VERSION 5.8 ;
BUSBITCHARS "[]" ;
DIVIDERCHAR "/" ;
UNITS
    DATABASE MICRONS 1000 ;
END UNITS

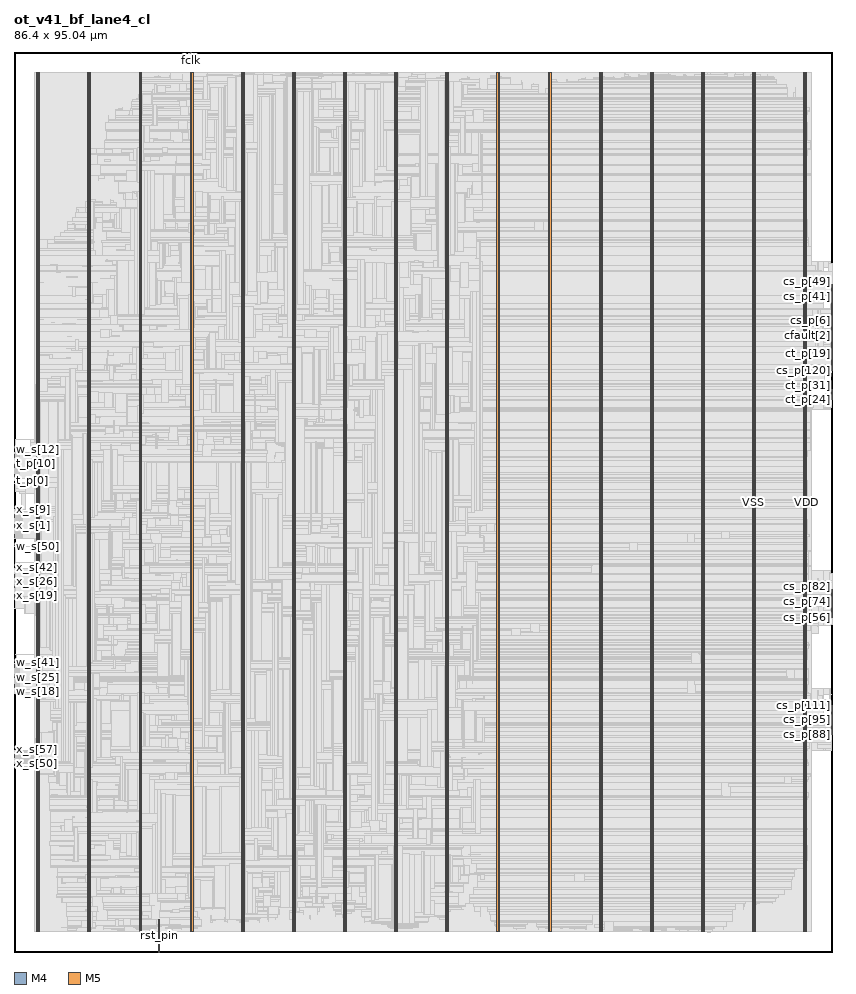
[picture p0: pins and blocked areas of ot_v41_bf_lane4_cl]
MACRO ot_v41_bf_lane4_cl
  FOREIGN ot_v41_bf_lane4_cl 0 0 ;
  CLASS BLOCK ;
  SIZE 86.4 BY 95.04 ;
  PIN cf[0]
    DIRECTION OUTPUT ;
    USE SIGNAL ;
    PORT
      LAYER M4 ;
        RECT  86.316 64.464 86.4 64.488 ;
    END
  END cf[0]
  PIN cf[1]
    DIRECTION OUTPUT ;
    USE SIGNAL ;
    PORT
      LAYER M4 ;
        RECT  86.316 64.56 86.4 64.584 ;
    END
  END cf[1]
  PIN cf[2]
    DIRECTION OUTPUT ;
    USE SIGNAL ;
    PORT
      LAYER M4 ;
        RECT  86.316 64.656 86.4 64.68 ;
    END
  END cf[2]
  PIN cf[3]
    DIRECTION OUTPUT ;
    USE SIGNAL ;
    PORT
      LAYER M4 ;
        RECT  86.316 64.752 86.4 64.776 ;
    END
  END cf[3]
  PIN cfault[0]
    DIRECTION OUTPUT ;
    USE SIGNAL ;
    PORT
      LAYER M4 ;
        RECT  86.316 64.848 86.4 64.872 ;
    END
  END cfault[0]
  PIN cfault[1]
    DIRECTION OUTPUT ;
    USE SIGNAL ;
    PORT
      LAYER M4 ;
        RECT  86.316 64.944 86.4 64.968 ;
    END
  END cfault[1]
  PIN cfault[2]
    DIRECTION OUTPUT ;
    USE SIGNAL ;
    PORT
      LAYER M4 ;
        RECT  86.316 65.04 86.4 65.064 ;
    END
  END cfault[2]
  PIN cfault[3]
    DIRECTION OUTPUT ;
    USE SIGNAL ;
    PORT
      LAYER M4 ;
        RECT  86.316 65.136 86.4 65.16 ;
    END
  END cfault[3]
  PIN cs_p[0]
    DIRECTION OUTPUT ;
    USE SIGNAL ;
    PORT
      LAYER M4 ;
        RECT  86.316 65.232 86.4 65.256 ;
    END
  END cs_p[0]
  PIN cs_p[100]
    DIRECTION OUTPUT ;
    USE SIGNAL ;
    PORT
      LAYER M4 ;
        RECT  86.316 24.144 86.4 24.168 ;
    END
  END cs_p[100]
  PIN cs_p[101]
    DIRECTION OUTPUT ;
    USE SIGNAL ;
    PORT
      LAYER M4 ;
        RECT  86.316 24.24 86.4 24.264 ;
    END
  END cs_p[101]
  PIN cs_p[102]
    DIRECTION OUTPUT ;
    USE SIGNAL ;
    PORT
      LAYER M4 ;
        RECT  86.316 24.336 86.4 24.36 ;
    END
  END cs_p[102]
  PIN cs_p[103]
    DIRECTION OUTPUT ;
    USE SIGNAL ;
    PORT
      LAYER M4 ;
        RECT  86.316 24.432 86.4 24.456 ;
    END
  END cs_p[103]
  PIN cs_p[104]
    DIRECTION OUTPUT ;
    USE SIGNAL ;
    PORT
      LAYER M4 ;
        RECT  86.316 24.528 86.4 24.552 ;
    END
  END cs_p[104]
  PIN cs_p[105]
    DIRECTION OUTPUT ;
    USE SIGNAL ;
    PORT
      LAYER M4 ;
        RECT  86.316 24.624 86.4 24.648 ;
    END
  END cs_p[105]
  PIN cs_p[106]
    DIRECTION OUTPUT ;
    USE SIGNAL ;
    PORT
      LAYER M4 ;
        RECT  86.316 24.72 86.4 24.744 ;
    END
  END cs_p[106]
  PIN cs_p[107]
    DIRECTION OUTPUT ;
    USE SIGNAL ;
    PORT
      LAYER M4 ;
        RECT  86.316 24.816 86.4 24.84 ;
    END
  END cs_p[107]
  PIN cs_p[108]
    DIRECTION OUTPUT ;
    USE SIGNAL ;
    PORT
      LAYER M4 ;
        RECT  86.316 24.912 86.4 24.936 ;
    END
  END cs_p[108]
  PIN cs_p[109]
    DIRECTION OUTPUT ;
    USE SIGNAL ;
    PORT
      LAYER M4 ;
        RECT  86.316 25.008 86.4 25.032 ;
    END
  END cs_p[109]
  PIN cs_p[10]
    DIRECTION OUTPUT ;
    USE SIGNAL ;
    PORT
      LAYER M4 ;
        RECT  86.316 66.192 86.4 66.216 ;
    END
  END cs_p[10]
  PIN cs_p[110]
    DIRECTION OUTPUT ;
    USE SIGNAL ;
    PORT
      LAYER M4 ;
        RECT  86.316 25.104 86.4 25.128 ;
    END
  END cs_p[110]
  PIN cs_p[111]
    DIRECTION OUTPUT ;
    USE SIGNAL ;
    PORT
      LAYER M4 ;
        RECT  86.316 25.2 86.4 25.224 ;
    END
  END cs_p[111]
  PIN cs_p[112]
    DIRECTION OUTPUT ;
    USE SIGNAL ;
    PORT
      LAYER M4 ;
        RECT  86.316 25.296 86.4 25.32 ;
    END
  END cs_p[112]
  PIN cs_p[113]
    DIRECTION OUTPUT ;
    USE SIGNAL ;
    PORT
      LAYER M4 ;
        RECT  86.316 25.392 86.4 25.416 ;
    END
  END cs_p[113]
  PIN cs_p[114]
    DIRECTION OUTPUT ;
    USE SIGNAL ;
    PORT
      LAYER M4 ;
        RECT  86.316 25.488 86.4 25.512 ;
    END
  END cs_p[114]
  PIN cs_p[115]
    DIRECTION OUTPUT ;
    USE SIGNAL ;
    PORT
      LAYER M4 ;
        RECT  86.316 25.584 86.4 25.608 ;
    END
  END cs_p[115]
  PIN cs_p[116]
    DIRECTION OUTPUT ;
    USE SIGNAL ;
    PORT
      LAYER M4 ;
        RECT  86.316 25.68 86.4 25.704 ;
    END
  END cs_p[116]
  PIN cs_p[117]
    DIRECTION OUTPUT ;
    USE SIGNAL ;
    PORT
      LAYER M4 ;
        RECT  86.316 25.776 86.4 25.8 ;
    END
  END cs_p[117]
  PIN cs_p[118]
    DIRECTION OUTPUT ;
    USE SIGNAL ;
    PORT
      LAYER M4 ;
        RECT  86.316 25.872 86.4 25.896 ;
    END
  END cs_p[118]
  PIN cs_p[119]
    DIRECTION OUTPUT ;
    USE SIGNAL ;
    PORT
      LAYER M4 ;
        RECT  86.316 25.968 86.4 25.992 ;
    END
  END cs_p[119]
  PIN cs_p[11]
    DIRECTION OUTPUT ;
    USE SIGNAL ;
    PORT
      LAYER M4 ;
        RECT  86.316 66.288 86.4 66.312 ;
    END
  END cs_p[11]
  PIN cs_p[120]
    DIRECTION OUTPUT ;
    USE SIGNAL ;
    PORT
      LAYER M4 ;
        RECT  86.316 61.392 86.4 61.416 ;
    END
  END cs_p[120]
  PIN cs_p[121]
    DIRECTION OUTPUT ;
    USE SIGNAL ;
    PORT
      LAYER M4 ;
        RECT  86.316 61.488 86.4 61.512 ;
    END
  END cs_p[121]
  PIN cs_p[122]
    DIRECTION OUTPUT ;
    USE SIGNAL ;
    PORT
      LAYER M4 ;
        RECT  86.316 61.584 86.4 61.608 ;
    END
  END cs_p[122]
  PIN cs_p[123]
    DIRECTION OUTPUT ;
    USE SIGNAL ;
    PORT
      LAYER M4 ;
        RECT  86.316 61.68 86.4 61.704 ;
    END
  END cs_p[123]
  PIN cs_p[124]
    DIRECTION OUTPUT ;
    USE SIGNAL ;
    PORT
      LAYER M4 ;
        RECT  86.316 61.776 86.4 61.8 ;
    END
  END cs_p[124]
  PIN cs_p[125]
    DIRECTION OUTPUT ;
    USE SIGNAL ;
    PORT
      LAYER M4 ;
        RECT  86.316 61.872 86.4 61.896 ;
    END
  END cs_p[125]
  PIN cs_p[126]
    DIRECTION OUTPUT ;
    USE SIGNAL ;
    PORT
      LAYER M4 ;
        RECT  86.316 61.968 86.4 61.992 ;
    END
  END cs_p[126]
  PIN cs_p[127]
    DIRECTION OUTPUT ;
    USE SIGNAL ;
    PORT
      LAYER M4 ;
        RECT  86.316 62.064 86.4 62.088 ;
    END
  END cs_p[127]
  PIN cs_p[12]
    DIRECTION OUTPUT ;
    USE SIGNAL ;
    PORT
      LAYER M4 ;
        RECT  86.316 66.384 86.4 66.408 ;
    END
  END cs_p[12]
  PIN cs_p[13]
    DIRECTION OUTPUT ;
    USE SIGNAL ;
    PORT
      LAYER M4 ;
        RECT  86.316 66.48 86.4 66.504 ;
    END
  END cs_p[13]
  PIN cs_p[14]
    DIRECTION OUTPUT ;
    USE SIGNAL ;
    PORT
      LAYER M4 ;
        RECT  86.316 66.576 86.4 66.6 ;
    END
  END cs_p[14]
  PIN cs_p[15]
    DIRECTION OUTPUT ;
    USE SIGNAL ;
    PORT
      LAYER M4 ;
        RECT  86.316 66.672 86.4 66.696 ;
    END
  END cs_p[15]
  PIN cs_p[16]
    DIRECTION OUTPUT ;
    USE SIGNAL ;
    PORT
      LAYER M4 ;
        RECT  86.316 66.768 86.4 66.792 ;
    END
  END cs_p[16]
  PIN cs_p[17]
    DIRECTION OUTPUT ;
    USE SIGNAL ;
    PORT
      LAYER M4 ;
        RECT  86.316 66.864 86.4 66.888 ;
    END
  END cs_p[17]
  PIN cs_p[18]
    DIRECTION OUTPUT ;
    USE SIGNAL ;
    PORT
      LAYER M4 ;
        RECT  86.316 66.96 86.4 66.984 ;
    END
  END cs_p[18]
  PIN cs_p[19]
    DIRECTION OUTPUT ;
    USE SIGNAL ;
    PORT
      LAYER M4 ;
        RECT  86.316 67.056 86.4 67.08 ;
    END
  END cs_p[19]
  PIN cs_p[1]
    DIRECTION OUTPUT ;
    USE SIGNAL ;
    PORT
      LAYER M4 ;
        RECT  86.316 65.328 86.4 65.352 ;
    END
  END cs_p[1]
  PIN cs_p[20]
    DIRECTION OUTPUT ;
    USE SIGNAL ;
    PORT
      LAYER M4 ;
        RECT  86.316 67.152 86.4 67.176 ;
    END
  END cs_p[20]
  PIN cs_p[21]
    DIRECTION OUTPUT ;
    USE SIGNAL ;
    PORT
      LAYER M4 ;
        RECT  86.316 67.248 86.4 67.272 ;
    END
  END cs_p[21]
  PIN cs_p[22]
    DIRECTION OUTPUT ;
    USE SIGNAL ;
    PORT
      LAYER M4 ;
        RECT  86.316 67.344 86.4 67.368 ;
    END
  END cs_p[22]
  PIN cs_p[23]
    DIRECTION OUTPUT ;
    USE SIGNAL ;
    PORT
      LAYER M4 ;
        RECT  86.316 67.44 86.4 67.464 ;
    END
  END cs_p[23]
  PIN cs_p[24]
    DIRECTION OUTPUT ;
    USE SIGNAL ;
    PORT
      LAYER M4 ;
        RECT  86.316 67.536 86.4 67.56 ;
    END
  END cs_p[24]
  PIN cs_p[25]
    DIRECTION OUTPUT ;
    USE SIGNAL ;
    PORT
      LAYER M4 ;
        RECT  86.316 67.632 86.4 67.656 ;
    END
  END cs_p[25]
  PIN cs_p[26]
    DIRECTION OUTPUT ;
    USE SIGNAL ;
    PORT
      LAYER M4 ;
        RECT  86.316 67.728 86.4 67.752 ;
    END
  END cs_p[26]
  PIN cs_p[27]
    DIRECTION OUTPUT ;
    USE SIGNAL ;
    PORT
      LAYER M4 ;
        RECT  86.316 67.824 86.4 67.848 ;
    END
  END cs_p[27]
  PIN cs_p[28]
    DIRECTION OUTPUT ;
    USE SIGNAL ;
    PORT
      LAYER M4 ;
        RECT  86.316 67.92 86.4 67.944 ;
    END
  END cs_p[28]
  PIN cs_p[29]
    DIRECTION OUTPUT ;
    USE SIGNAL ;
    PORT
      LAYER M4 ;
        RECT  86.316 68.016 86.4 68.04 ;
    END
  END cs_p[29]
  PIN cs_p[2]
    DIRECTION OUTPUT ;
    USE SIGNAL ;
    PORT
      LAYER M4 ;
        RECT  86.316 65.424 86.4 65.448 ;
    END
  END cs_p[2]
  PIN cs_p[30]
    DIRECTION OUTPUT ;
    USE SIGNAL ;
    PORT
      LAYER M4 ;
        RECT  86.316 68.112 86.4 68.136 ;
    END
  END cs_p[30]
  PIN cs_p[31]
    DIRECTION OUTPUT ;
    USE SIGNAL ;
    PORT
      LAYER M4 ;
        RECT  86.316 68.208 86.4 68.232 ;
    END
  END cs_p[31]
  PIN cs_p[32]
    DIRECTION OUTPUT ;
    USE SIGNAL ;
    PORT
      LAYER M4 ;
        RECT  86.316 68.304 86.4 68.328 ;
    END
  END cs_p[32]
  PIN cs_p[33]
    DIRECTION OUTPUT ;
    USE SIGNAL ;
    PORT
      LAYER M4 ;
        RECT  86.316 68.4 86.4 68.424 ;
    END
  END cs_p[33]
  PIN cs_p[34]
    DIRECTION OUTPUT ;
    USE SIGNAL ;
    PORT
      LAYER M4 ;
        RECT  86.316 68.496 86.4 68.52 ;
    END
  END cs_p[34]
  PIN cs_p[35]
    DIRECTION OUTPUT ;
    USE SIGNAL ;
    PORT
      LAYER M4 ;
        RECT  86.316 68.592 86.4 68.616 ;
    END
  END cs_p[35]
  PIN cs_p[36]
    DIRECTION OUTPUT ;
    USE SIGNAL ;
    PORT
      LAYER M4 ;
        RECT  86.316 68.688 86.4 68.712 ;
    END
  END cs_p[36]
  PIN cs_p[37]
    DIRECTION OUTPUT ;
    USE SIGNAL ;
    PORT
      LAYER M4 ;
        RECT  86.316 68.784 86.4 68.808 ;
    END
  END cs_p[37]
  PIN cs_p[38]
    DIRECTION OUTPUT ;
    USE SIGNAL ;
    PORT
      LAYER M4 ;
        RECT  86.316 68.88 86.4 68.904 ;
    END
  END cs_p[38]
  PIN cs_p[39]
    DIRECTION OUTPUT ;
    USE SIGNAL ;
    PORT
      LAYER M4 ;
        RECT  86.316 68.976 86.4 69 ;
    END
  END cs_p[39]
  PIN cs_p[3]
    DIRECTION OUTPUT ;
    USE SIGNAL ;
    PORT
      LAYER M4 ;
        RECT  86.316 65.52 86.4 65.544 ;
    END
  END cs_p[3]
  PIN cs_p[40]
    DIRECTION OUTPUT ;
    USE SIGNAL ;
    PORT
      LAYER M4 ;
        RECT  86.316 69.072 86.4 69.096 ;
    END
  END cs_p[40]
  PIN cs_p[41]
    DIRECTION OUTPUT ;
    USE SIGNAL ;
    PORT
      LAYER M4 ;
        RECT  86.316 69.168 86.4 69.192 ;
    END
  END cs_p[41]
  PIN cs_p[42]
    DIRECTION OUTPUT ;
    USE SIGNAL ;
    PORT
      LAYER M4 ;
        RECT  86.316 69.264 86.4 69.288 ;
    END
  END cs_p[42]
  PIN cs_p[43]
    DIRECTION OUTPUT ;
    USE SIGNAL ;
    PORT
      LAYER M4 ;
        RECT  86.316 69.36 86.4 69.384 ;
    END
  END cs_p[43]
  PIN cs_p[44]
    DIRECTION OUTPUT ;
    USE SIGNAL ;
    PORT
      LAYER M4 ;
        RECT  86.316 69.456 86.4 69.48 ;
    END
  END cs_p[44]
  PIN cs_p[45]
    DIRECTION OUTPUT ;
    USE SIGNAL ;
    PORT
      LAYER M4 ;
        RECT  86.316 69.552 86.4 69.576 ;
    END
  END cs_p[45]
  PIN cs_p[46]
    DIRECTION OUTPUT ;
    USE SIGNAL ;
    PORT
      LAYER M4 ;
        RECT  86.316 69.648 86.4 69.672 ;
    END
  END cs_p[46]
  PIN cs_p[47]
    DIRECTION OUTPUT ;
    USE SIGNAL ;
    PORT
      LAYER M4 ;
        RECT  86.316 69.744 86.4 69.768 ;
    END
  END cs_p[47]
  PIN cs_p[48]
    DIRECTION OUTPUT ;
    USE SIGNAL ;
    PORT
      LAYER M4 ;
        RECT  86.316 69.84 86.4 69.864 ;
    END
  END cs_p[48]
  PIN cs_p[49]
    DIRECTION OUTPUT ;
    USE SIGNAL ;
    PORT
      LAYER M4 ;
        RECT  86.316 69.936 86.4 69.96 ;
    END
  END cs_p[49]
  PIN cs_p[4]
    DIRECTION OUTPUT ;
    USE SIGNAL ;
    PORT
      LAYER M4 ;
        RECT  86.316 65.616 86.4 65.64 ;
    END
  END cs_p[4]
  PIN cs_p[50]
    DIRECTION OUTPUT ;
    USE SIGNAL ;
    PORT
      LAYER M4 ;
        RECT  86.316 70.032 86.4 70.056 ;
    END
  END cs_p[50]
  PIN cs_p[51]
    DIRECTION OUTPUT ;
    USE SIGNAL ;
    PORT
      LAYER M4 ;
        RECT  86.316 70.128 86.4 70.152 ;
    END
  END cs_p[51]
  PIN cs_p[52]
    DIRECTION OUTPUT ;
    USE SIGNAL ;
    PORT
      LAYER M4 ;
        RECT  86.316 70.224 86.4 70.248 ;
    END
  END cs_p[52]
  PIN cs_p[53]
    DIRECTION OUTPUT ;
    USE SIGNAL ;
    PORT
      LAYER M4 ;
        RECT  86.316 70.32 86.4 70.344 ;
    END
  END cs_p[53]
  PIN cs_p[54]
    DIRECTION OUTPUT ;
    USE SIGNAL ;
    PORT
      LAYER M4 ;
        RECT  86.316 70.416 86.4 70.44 ;
    END
  END cs_p[54]
  PIN cs_p[55]
    DIRECTION OUTPUT ;
    USE SIGNAL ;
    PORT
      LAYER M4 ;
        RECT  86.316 70.512 86.4 70.536 ;
    END
  END cs_p[55]
  PIN cs_p[56]
    DIRECTION OUTPUT ;
    USE SIGNAL ;
    PORT
      LAYER M4 ;
        RECT  86.316 35.28 86.4 35.304 ;
    END
  END cs_p[56]
  PIN cs_p[57]
    DIRECTION OUTPUT ;
    USE SIGNAL ;
    PORT
      LAYER M4 ;
        RECT  86.316 35.376 86.4 35.4 ;
    END
  END cs_p[57]
  PIN cs_p[58]
    DIRECTION OUTPUT ;
    USE SIGNAL ;
    PORT
      LAYER M4 ;
        RECT  86.316 35.472 86.4 35.496 ;
    END
  END cs_p[58]
  PIN cs_p[59]
    DIRECTION OUTPUT ;
    USE SIGNAL ;
    PORT
      LAYER M4 ;
        RECT  86.316 35.568 86.4 35.592 ;
    END
  END cs_p[59]
  PIN cs_p[5]
    DIRECTION OUTPUT ;
    USE SIGNAL ;
    PORT
      LAYER M4 ;
        RECT  86.316 65.712 86.4 65.736 ;
    END
  END cs_p[5]
  PIN cs_p[60]
    DIRECTION OUTPUT ;
    USE SIGNAL ;
    PORT
      LAYER M4 ;
        RECT  86.316 35.664 86.4 35.688 ;
    END
  END cs_p[60]
  PIN cs_p[61]
    DIRECTION OUTPUT ;
    USE SIGNAL ;
    PORT
      LAYER M4 ;
        RECT  86.316 35.76 86.4 35.784 ;
    END
  END cs_p[61]
  PIN cs_p[62]
    DIRECTION OUTPUT ;
    USE SIGNAL ;
    PORT
      LAYER M4 ;
        RECT  86.316 35.856 86.4 35.88 ;
    END
  END cs_p[62]
  PIN cs_p[63]
    DIRECTION OUTPUT ;
    USE SIGNAL ;
    PORT
      LAYER M4 ;
        RECT  86.316 35.952 86.4 35.976 ;
    END
  END cs_p[63]
  PIN cs_p[64]
    DIRECTION OUTPUT ;
    USE SIGNAL ;
    PORT
      LAYER M4 ;
        RECT  86.316 36.048 86.4 36.072 ;
    END
  END cs_p[64]
  PIN cs_p[65]
    DIRECTION OUTPUT ;
    USE SIGNAL ;
    PORT
      LAYER M4 ;
        RECT  86.316 36.144 86.4 36.168 ;
    END
  END cs_p[65]
  PIN cs_p[66]
    DIRECTION OUTPUT ;
    USE SIGNAL ;
    PORT
      LAYER M4 ;
        RECT  86.316 36.24 86.4 36.264 ;
    END
  END cs_p[66]
  PIN cs_p[67]
    DIRECTION OUTPUT ;
    USE SIGNAL ;
    PORT
      LAYER M4 ;
        RECT  86.316 36.336 86.4 36.36 ;
    END
  END cs_p[67]
  PIN cs_p[68]
    DIRECTION OUTPUT ;
    USE SIGNAL ;
    PORT
      LAYER M4 ;
        RECT  86.316 36.432 86.4 36.456 ;
    END
  END cs_p[68]
  PIN cs_p[69]
    DIRECTION OUTPUT ;
    USE SIGNAL ;
    PORT
      LAYER M4 ;
        RECT  86.316 36.528 86.4 36.552 ;
    END
  END cs_p[69]
  PIN cs_p[6]
    DIRECTION OUTPUT ;
    USE SIGNAL ;
    PORT
      LAYER M4 ;
        RECT  86.316 65.808 86.4 65.832 ;
    END
  END cs_p[6]
  PIN cs_p[70]
    DIRECTION OUTPUT ;
    USE SIGNAL ;
    PORT
      LAYER M4 ;
        RECT  86.316 36.624 86.4 36.648 ;
    END
  END cs_p[70]
  PIN cs_p[71]
    DIRECTION OUTPUT ;
    USE SIGNAL ;
    PORT
      LAYER M4 ;
        RECT  86.316 36.72 86.4 36.744 ;
    END
  END cs_p[71]
  PIN cs_p[72]
    DIRECTION OUTPUT ;
    USE SIGNAL ;
    PORT
      LAYER M4 ;
        RECT  86.316 36.816 86.4 36.84 ;
    END
  END cs_p[72]
  PIN cs_p[73]
    DIRECTION OUTPUT ;
    USE SIGNAL ;
    PORT
      LAYER M4 ;
        RECT  86.316 36.912 86.4 36.936 ;
    END
  END cs_p[73]
  PIN cs_p[74]
    DIRECTION OUTPUT ;
    USE SIGNAL ;
    PORT
      LAYER M4 ;
        RECT  86.316 37.008 86.4 37.032 ;
    END
  END cs_p[74]
  PIN cs_p[75]
    DIRECTION OUTPUT ;
    USE SIGNAL ;
    PORT
      LAYER M4 ;
        RECT  86.316 37.104 86.4 37.128 ;
    END
  END cs_p[75]
  PIN cs_p[76]
    DIRECTION OUTPUT ;
    USE SIGNAL ;
    PORT
      LAYER M4 ;
        RECT  86.316 37.2 86.4 37.224 ;
    END
  END cs_p[76]
  PIN cs_p[77]
    DIRECTION OUTPUT ;
    USE SIGNAL ;
    PORT
      LAYER M4 ;
        RECT  86.316 37.296 86.4 37.32 ;
    END
  END cs_p[77]
  PIN cs_p[78]
    DIRECTION OUTPUT ;
    USE SIGNAL ;
    PORT
      LAYER M4 ;
        RECT  86.316 37.392 86.4 37.416 ;
    END
  END cs_p[78]
  PIN cs_p[79]
    DIRECTION OUTPUT ;
    USE SIGNAL ;
    PORT
      LAYER M4 ;
        RECT  86.316 37.488 86.4 37.512 ;
    END
  END cs_p[79]
  PIN cs_p[7]
    DIRECTION OUTPUT ;
    USE SIGNAL ;
    PORT
      LAYER M4 ;
        RECT  86.316 65.904 86.4 65.928 ;
    END
  END cs_p[7]
  PIN cs_p[80]
    DIRECTION OUTPUT ;
    USE SIGNAL ;
    PORT
      LAYER M4 ;
        RECT  86.316 37.584 86.4 37.608 ;
    END
  END cs_p[80]
  PIN cs_p[81]
    DIRECTION OUTPUT ;
    USE SIGNAL ;
    PORT
      LAYER M4 ;
        RECT  86.316 37.68 86.4 37.704 ;
    END
  END cs_p[81]
  PIN cs_p[82]
    DIRECTION OUTPUT ;
    USE SIGNAL ;
    PORT
      LAYER M4 ;
        RECT  86.316 37.776 86.4 37.8 ;
    END
  END cs_p[82]
  PIN cs_p[83]
    DIRECTION OUTPUT ;
    USE SIGNAL ;
    PORT
      LAYER M4 ;
        RECT  86.316 37.872 86.4 37.896 ;
    END
  END cs_p[83]
  PIN cs_p[84]
    DIRECTION OUTPUT ;
    USE SIGNAL ;
    PORT
      LAYER M4 ;
        RECT  86.316 37.968 86.4 37.992 ;
    END
  END cs_p[84]
  PIN cs_p[85]
    DIRECTION OUTPUT ;
    USE SIGNAL ;
    PORT
      LAYER M4 ;
        RECT  86.316 38.064 86.4 38.088 ;
    END
  END cs_p[85]
  PIN cs_p[86]
    DIRECTION OUTPUT ;
    USE SIGNAL ;
    PORT
      LAYER M4 ;
        RECT  86.316 38.16 86.4 38.184 ;
    END
  END cs_p[86]
  PIN cs_p[87]
    DIRECTION OUTPUT ;
    USE SIGNAL ;
    PORT
      LAYER M4 ;
        RECT  86.316 38.256 86.4 38.28 ;
    END
  END cs_p[87]
  PIN cs_p[88]
    DIRECTION OUTPUT ;
    USE SIGNAL ;
    PORT
      LAYER M4 ;
        RECT  86.316 22.992 86.4 23.016 ;
    END
  END cs_p[88]
  PIN cs_p[89]
    DIRECTION OUTPUT ;
    USE SIGNAL ;
    PORT
      LAYER M4 ;
        RECT  86.316 23.088 86.4 23.112 ;
    END
  END cs_p[89]
  PIN cs_p[8]
    DIRECTION OUTPUT ;
    USE SIGNAL ;
    PORT
      LAYER M4 ;
        RECT  86.316 66 86.4 66.024 ;
    END
  END cs_p[8]
  PIN cs_p[90]
    DIRECTION OUTPUT ;
    USE SIGNAL ;
    PORT
      LAYER M4 ;
        RECT  86.316 23.184 86.4 23.208 ;
    END
  END cs_p[90]
  PIN cs_p[91]
    DIRECTION OUTPUT ;
    USE SIGNAL ;
    PORT
      LAYER M4 ;
        RECT  86.316 23.28 86.4 23.304 ;
    END
  END cs_p[91]
  PIN cs_p[92]
    DIRECTION OUTPUT ;
    USE SIGNAL ;
    PORT
      LAYER M4 ;
        RECT  86.316 23.376 86.4 23.4 ;
    END
  END cs_p[92]
  PIN cs_p[93]
    DIRECTION OUTPUT ;
    USE SIGNAL ;
    PORT
      LAYER M4 ;
        RECT  86.316 23.472 86.4 23.496 ;
    END
  END cs_p[93]
  PIN cs_p[94]
    DIRECTION OUTPUT ;
    USE SIGNAL ;
    PORT
      LAYER M4 ;
        RECT  86.316 23.568 86.4 23.592 ;
    END
  END cs_p[94]
  PIN cs_p[95]
    DIRECTION OUTPUT ;
    USE SIGNAL ;
    PORT
      LAYER M4 ;
        RECT  86.316 23.664 86.4 23.688 ;
    END
  END cs_p[95]
  PIN cs_p[96]
    DIRECTION OUTPUT ;
    USE SIGNAL ;
    PORT
      LAYER M4 ;
        RECT  86.316 23.76 86.4 23.784 ;
    END
  END cs_p[96]
  PIN cs_p[97]
    DIRECTION OUTPUT ;
    USE SIGNAL ;
    PORT
      LAYER M4 ;
        RECT  86.316 23.856 86.4 23.88 ;
    END
  END cs_p[97]
  PIN cs_p[98]
    DIRECTION OUTPUT ;
    USE SIGNAL ;
    PORT
      LAYER M4 ;
        RECT  86.316 23.952 86.4 23.976 ;
    END
  END cs_p[98]
  PIN cs_p[99]
    DIRECTION OUTPUT ;
    USE SIGNAL ;
    PORT
      LAYER M4 ;
        RECT  86.316 24.048 86.4 24.072 ;
    END
  END cs_p[99]
  PIN cs_p[9]
    DIRECTION OUTPUT ;
    USE SIGNAL ;
    PORT
      LAYER M4 ;
        RECT  86.316 66.096 86.4 66.12 ;
    END
  END cs_p[9]
  PIN ct_p[0]
    DIRECTION OUTPUT ;
    USE SIGNAL ;
    PORT
      LAYER M4 ;
        RECT  86.316 62.16 86.4 62.184 ;
    END
  END ct_p[0]
  PIN ct_p[10]
    DIRECTION OUTPUT ;
    USE SIGNAL ;
    PORT
      LAYER M4 ;
        RECT  86.316 63.12 86.4 63.144 ;
    END
  END ct_p[10]
  PIN ct_p[11]
    DIRECTION OUTPUT ;
    USE SIGNAL ;
    PORT
      LAYER M4 ;
        RECT  86.316 63.216 86.4 63.24 ;
    END
  END ct_p[11]
  PIN ct_p[12]
    DIRECTION OUTPUT ;
    USE SIGNAL ;
    PORT
      LAYER M4 ;
        RECT  86.316 63.312 86.4 63.336 ;
    END
  END ct_p[12]
  PIN ct_p[13]
    DIRECTION OUTPUT ;
    USE SIGNAL ;
    PORT
      LAYER M4 ;
        RECT  86.316 63.408 86.4 63.432 ;
    END
  END ct_p[13]
  PIN ct_p[14]
    DIRECTION OUTPUT ;
    USE SIGNAL ;
    PORT
      LAYER M4 ;
        RECT  86.316 63.504 86.4 63.528 ;
    END
  END ct_p[14]
  PIN ct_p[15]
    DIRECTION OUTPUT ;
    USE SIGNAL ;
    PORT
      LAYER M4 ;
        RECT  86.316 63.6 86.4 63.624 ;
    END
  END ct_p[15]
  PIN ct_p[16]
    DIRECTION OUTPUT ;
    USE SIGNAL ;
    PORT
      LAYER M4 ;
        RECT  86.316 63.696 86.4 63.72 ;
    END
  END ct_p[16]
  PIN ct_p[17]
    DIRECTION OUTPUT ;
    USE SIGNAL ;
    PORT
      LAYER M4 ;
        RECT  86.316 63.792 86.4 63.816 ;
    END
  END ct_p[17]
  PIN ct_p[18]
    DIRECTION OUTPUT ;
    USE SIGNAL ;
    PORT
      LAYER M4 ;
        RECT  86.316 63.888 86.4 63.912 ;
    END
  END ct_p[18]
  PIN ct_p[19]
    DIRECTION OUTPUT ;
    USE SIGNAL ;
    PORT
      LAYER M4 ;
        RECT  86.316 63.984 86.4 64.008 ;
    END
  END ct_p[19]
  PIN ct_p[1]
    DIRECTION OUTPUT ;
    USE SIGNAL ;
    PORT
      LAYER M4 ;
        RECT  86.316 62.256 86.4 62.28 ;
    END
  END ct_p[1]
  PIN ct_p[20]
    DIRECTION OUTPUT ;
    USE SIGNAL ;
    PORT
      LAYER M4 ;
        RECT  86.316 64.08 86.4 64.104 ;
    END
  END ct_p[20]
  PIN ct_p[21]
    DIRECTION OUTPUT ;
    USE SIGNAL ;
    PORT
      LAYER M4 ;
        RECT  86.316 64.176 86.4 64.2 ;
    END
  END ct_p[21]
  PIN ct_p[22]
    DIRECTION OUTPUT ;
    USE SIGNAL ;
    PORT
      LAYER M4 ;
        RECT  86.316 64.272 86.4 64.296 ;
    END
  END ct_p[22]
  PIN ct_p[23]
    DIRECTION OUTPUT ;
    USE SIGNAL ;
    PORT
      LAYER M4 ;
        RECT  86.316 64.368 86.4 64.392 ;
    END
  END ct_p[23]
  PIN ct_p[24]
    DIRECTION OUTPUT ;
    USE SIGNAL ;
    PORT
      LAYER M4 ;
        RECT  86.316 58.32 86.4 58.344 ;
    END
  END ct_p[24]
  PIN ct_p[25]
    DIRECTION OUTPUT ;
    USE SIGNAL ;
    PORT
      LAYER M4 ;
        RECT  86.316 58.416 86.4 58.44 ;
    END
  END ct_p[25]
  PIN ct_p[26]
    DIRECTION OUTPUT ;
    USE SIGNAL ;
    PORT
      LAYER M4 ;
        RECT  86.316 58.512 86.4 58.536 ;
    END
  END ct_p[26]
  PIN ct_p[27]
    DIRECTION OUTPUT ;
    USE SIGNAL ;
    PORT
      LAYER M4 ;
        RECT  86.316 58.608 86.4 58.632 ;
    END
  END ct_p[27]
  PIN ct_p[28]
    DIRECTION OUTPUT ;
    USE SIGNAL ;
    PORT
      LAYER M4 ;
        RECT  86.316 58.704 86.4 58.728 ;
    END
  END ct_p[28]
  PIN ct_p[29]
    DIRECTION OUTPUT ;
    USE SIGNAL ;
    PORT
      LAYER M4 ;
        RECT  86.316 58.8 86.4 58.824 ;
    END
  END ct_p[29]
  PIN ct_p[2]
    DIRECTION OUTPUT ;
    USE SIGNAL ;
    PORT
      LAYER M4 ;
        RECT  86.316 62.352 86.4 62.376 ;
    END
  END ct_p[2]
  PIN ct_p[30]
    DIRECTION OUTPUT ;
    USE SIGNAL ;
    PORT
      LAYER M4 ;
        RECT  86.316 58.896 86.4 58.92 ;
    END
  END ct_p[30]
  PIN ct_p[31]
    DIRECTION OUTPUT ;
    USE SIGNAL ;
    PORT
      LAYER M4 ;
        RECT  86.316 58.992 86.4 59.016 ;
    END
  END ct_p[31]
  PIN ct_p[3]
    DIRECTION OUTPUT ;
    USE SIGNAL ;
    PORT
      LAYER M4 ;
        RECT  86.316 62.448 86.4 62.472 ;
    END
  END ct_p[3]
  PIN ct_p[4]
    DIRECTION OUTPUT ;
    USE SIGNAL ;
    PORT
      LAYER M4 ;
        RECT  86.316 62.544 86.4 62.568 ;
    END
  END ct_p[4]
  PIN ct_p[5]
    DIRECTION OUTPUT ;
    USE SIGNAL ;
    PORT
      LAYER M4 ;
        RECT  86.316 62.64 86.4 62.664 ;
    END
  END ct_p[5]
  PIN ct_p[6]
    DIRECTION OUTPUT ;
    USE SIGNAL ;
    PORT
      LAYER M4 ;
        RECT  86.316 62.736 86.4 62.76 ;
    END
  END ct_p[6]
  PIN ct_p[7]
    DIRECTION OUTPUT ;
    USE SIGNAL ;
    PORT
      LAYER M4 ;
        RECT  86.316 62.832 86.4 62.856 ;
    END
  END ct_p[7]
  PIN ct_p[8]
    DIRECTION OUTPUT ;
    USE SIGNAL ;
    PORT
      LAYER M4 ;
        RECT  86.316 62.928 86.4 62.952 ;
    END
  END ct_p[8]
  PIN ct_p[9]
    DIRECTION OUTPUT ;
    USE SIGNAL ;
    PORT
      LAYER M4 ;
        RECT  86.316 63.024 86.4 63.048 ;
    END
  END ct_p[9]
  PIN cv[0]
    DIRECTION OUTPUT ;
    USE SIGNAL ;
    PORT
      LAYER M4 ;
        RECT  86.316 59.088 86.4 59.112 ;
    END
  END cv[0]
  PIN cv[1]
    DIRECTION OUTPUT ;
    USE SIGNAL ;
    PORT
      LAYER M4 ;
        RECT  86.316 59.184 86.4 59.208 ;
    END
  END cv[1]
  PIN cv[2]
    DIRECTION OUTPUT ;
    USE SIGNAL ;
    PORT
      LAYER M4 ;
        RECT  86.316 59.28 86.4 59.304 ;
    END
  END cv[2]
  PIN cv[3]
    DIRECTION OUTPUT ;
    USE SIGNAL ;
    PORT
      LAYER M4 ;
        RECT  86.316 59.376 86.4 59.4 ;
    END
  END cv[3]
  PIN fclk
    DIRECTION INPUT ;
    USE SIGNAL ;
    PORT
      LAYER M5 ;
        RECT  18.672 94.956 18.696 95.04 ;
    END
    PORT
      LAYER M5 ;
        RECT  18.672 94.931 18.696 94.992 ;
    END
  END fclk
  PIN rst_pin
    DIRECTION INPUT ;
    USE SIGNAL ;
    PORT
      LAYER M5 ;
        RECT  15.312 0 15.336 0.084 ;
    END
    PORT
      LAYER M5 ;
        RECT  15.312 0.016 15.336 3.397 ;
    END
  END rst_pin
  PIN t_p[0]
    DIRECTION INPUT ;
    USE SIGNAL ;
    PORT
      LAYER M4 ;
        RECT  0 49.776 0.084 49.8 ;
    END
  END t_p[0]
  PIN t_p[10]
    DIRECTION INPUT ;
    USE SIGNAL ;
    PORT
      LAYER M4 ;
        RECT  0 50.736 0.084 50.76 ;
    END
  END t_p[10]
  PIN t_p[11]
    DIRECTION INPUT ;
    USE SIGNAL ;
    PORT
      LAYER M4 ;
        RECT  0 50.832 0.084 50.856 ;
    END
  END t_p[11]
  PIN t_p[12]
    DIRECTION INPUT ;
    USE SIGNAL ;
    PORT
      LAYER M4 ;
        RECT  0 50.928 0.084 50.952 ;
    END
  END t_p[12]
  PIN t_p[1]
    DIRECTION INPUT ;
    USE SIGNAL ;
    PORT
      LAYER M4 ;
        RECT  0 49.872 0.084 49.896 ;
    END
  END t_p[1]
  PIN t_p[2]
    DIRECTION INPUT ;
    USE SIGNAL ;
    PORT
      LAYER M4 ;
        RECT  0 49.968 0.084 49.992 ;
    END
  END t_p[2]
  PIN t_p[3]
    DIRECTION INPUT ;
    USE SIGNAL ;
    PORT
      LAYER M4 ;
        RECT  0 50.064 0.084 50.088 ;
    END
  END t_p[3]
  PIN t_p[4]
    DIRECTION INPUT ;
    USE SIGNAL ;
    PORT
      LAYER M4 ;
        RECT  0 50.16 0.084 50.184 ;
    END
  END t_p[4]
  PIN t_p[5]
    DIRECTION INPUT ;
    USE SIGNAL ;
    PORT
      LAYER M4 ;
        RECT  0 50.256 0.084 50.28 ;
    END
  END t_p[5]
  PIN t_p[6]
    DIRECTION INPUT ;
    USE SIGNAL ;
    PORT
      LAYER M4 ;
        RECT  0 50.352 0.084 50.376 ;
    END
  END t_p[6]
  PIN t_p[7]
    DIRECTION INPUT ;
    USE SIGNAL ;
    PORT
      LAYER M4 ;
        RECT  0 50.448 0.084 50.472 ;
    END
  END t_p[7]
  PIN t_p[8]
    DIRECTION INPUT ;
    USE SIGNAL ;
    PORT
      LAYER M4 ;
        RECT  0 50.544 0.084 50.568 ;
    END
  END t_p[8]
  PIN t_p[9]
    DIRECTION INPUT ;
    USE SIGNAL ;
    PORT
      LAYER M4 ;
        RECT  0 50.64 0.084 50.664 ;
    END
  END t_p[9]
  PIN v_s
    DIRECTION INPUT ;
    USE SIGNAL ;
    PORT
      LAYER M4 ;
        RECT  0 51.024 0.084 51.048 ;
    END
  END v_s
  PIN w_s[0]
    DIRECTION INPUT ;
    USE SIGNAL ;
    PORT
      LAYER M4 ;
        RECT  0 51.12 0.084 51.144 ;
    END
  END w_s[0]
  PIN w_s[10]
    DIRECTION INPUT ;
    USE SIGNAL ;
    PORT
      LAYER M4 ;
        RECT  0 52.08 0.084 52.104 ;
    END
  END w_s[10]
  PIN w_s[11]
    DIRECTION INPUT ;
    USE SIGNAL ;
    PORT
      LAYER M4 ;
        RECT  0 52.176 0.084 52.2 ;
    END
  END w_s[11]
  PIN w_s[12]
    DIRECTION INPUT ;
    USE SIGNAL ;
    PORT
      LAYER M4 ;
        RECT  0 52.272 0.084 52.296 ;
    END
  END w_s[12]
  PIN w_s[13]
    DIRECTION INPUT ;
    USE SIGNAL ;
    PORT
      LAYER M4 ;
        RECT  0 52.368 0.084 52.392 ;
    END
  END w_s[13]
  PIN w_s[14]
    DIRECTION INPUT ;
    USE SIGNAL ;
    PORT
      LAYER M4 ;
        RECT  0 52.464 0.084 52.488 ;
    END
  END w_s[14]
  PIN w_s[15]
    DIRECTION INPUT ;
    USE SIGNAL ;
    PORT
      LAYER M4 ;
        RECT  0 52.56 0.084 52.584 ;
    END
  END w_s[15]
  PIN w_s[16]
    DIRECTION INPUT ;
    USE SIGNAL ;
    PORT
      LAYER M4 ;
        RECT  0 52.656 0.084 52.68 ;
    END
  END w_s[16]
  PIN w_s[17]
    DIRECTION INPUT ;
    USE SIGNAL ;
    PORT
      LAYER M4 ;
        RECT  0 52.752 0.084 52.776 ;
    END
  END w_s[17]
  PIN w_s[18]
    DIRECTION INPUT ;
    USE SIGNAL ;
    PORT
      LAYER M4 ;
        RECT  0 27.504 0.084 27.528 ;
    END
  END w_s[18]
  PIN w_s[19]
    DIRECTION INPUT ;
    USE SIGNAL ;
    PORT
      LAYER M4 ;
        RECT  0 27.6 0.084 27.624 ;
    END
  END w_s[19]
  PIN w_s[1]
    DIRECTION INPUT ;
    USE SIGNAL ;
    PORT
      LAYER M4 ;
        RECT  0 51.216 0.084 51.24 ;
    END
  END w_s[1]
  PIN w_s[20]
    DIRECTION INPUT ;
    USE SIGNAL ;
    PORT
      LAYER M4 ;
        RECT  0 27.696 0.084 27.72 ;
    END
  END w_s[20]
  PIN w_s[21]
    DIRECTION INPUT ;
    USE SIGNAL ;
    PORT
      LAYER M4 ;
        RECT  0 27.792 0.084 27.816 ;
    END
  END w_s[21]
  PIN w_s[22]
    DIRECTION INPUT ;
    USE SIGNAL ;
    PORT
      LAYER M4 ;
        RECT  0 27.888 0.084 27.912 ;
    END
  END w_s[22]
  PIN w_s[23]
    DIRECTION INPUT ;
    USE SIGNAL ;
    PORT
      LAYER M4 ;
        RECT  0 27.984 0.084 28.008 ;
    END
  END w_s[23]
  PIN w_s[24]
    DIRECTION INPUT ;
    USE SIGNAL ;
    PORT
      LAYER M4 ;
        RECT  0 28.08 0.084 28.104 ;
    END
  END w_s[24]
  PIN w_s[25]
    DIRECTION INPUT ;
    USE SIGNAL ;
    PORT
      LAYER M4 ;
        RECT  0 28.176 0.084 28.2 ;
    END
  END w_s[25]
  PIN w_s[26]
    DIRECTION INPUT ;
    USE SIGNAL ;
    PORT
      LAYER M4 ;
        RECT  0 28.272 0.084 28.296 ;
    END
  END w_s[26]
  PIN w_s[27]
    DIRECTION INPUT ;
    USE SIGNAL ;
    PORT
      LAYER M4 ;
        RECT  0 28.368 0.084 28.392 ;
    END
  END w_s[27]
  PIN w_s[28]
    DIRECTION INPUT ;
    USE SIGNAL ;
    PORT
      LAYER M4 ;
        RECT  0 28.464 0.084 28.488 ;
    END
  END w_s[28]
  PIN w_s[29]
    DIRECTION INPUT ;
    USE SIGNAL ;
    PORT
      LAYER M4 ;
        RECT  0 28.56 0.084 28.584 ;
    END
  END w_s[29]
  PIN w_s[2]
    DIRECTION INPUT ;
    USE SIGNAL ;
    PORT
      LAYER M4 ;
        RECT  0 51.312 0.084 51.336 ;
    END
  END w_s[2]
  PIN w_s[30]
    DIRECTION INPUT ;
    USE SIGNAL ;
    PORT
      LAYER M4 ;
        RECT  0 28.656 0.084 28.68 ;
    END
  END w_s[30]
  PIN w_s[31]
    DIRECTION INPUT ;
    USE SIGNAL ;
    PORT
      LAYER M4 ;
        RECT  0 28.752 0.084 28.776 ;
    END
  END w_s[31]
  PIN w_s[32]
    DIRECTION INPUT ;
    USE SIGNAL ;
    PORT
      LAYER M4 ;
        RECT  0 28.848 0.084 28.872 ;
    END
  END w_s[32]
  PIN w_s[33]
    DIRECTION INPUT ;
    USE SIGNAL ;
    PORT
      LAYER M4 ;
        RECT  0 28.944 0.084 28.968 ;
    END
  END w_s[33]
  PIN w_s[34]
    DIRECTION INPUT ;
    USE SIGNAL ;
    PORT
      LAYER M4 ;
        RECT  0 29.04 0.084 29.064 ;
    END
  END w_s[34]
  PIN w_s[35]
    DIRECTION INPUT ;
    USE SIGNAL ;
    PORT
      LAYER M4 ;
        RECT  0 29.136 0.084 29.16 ;
    END
  END w_s[35]
  PIN w_s[36]
    DIRECTION INPUT ;
    USE SIGNAL ;
    PORT
      LAYER M4 ;
        RECT  0 29.232 0.084 29.256 ;
    END
  END w_s[36]
  PIN w_s[37]
    DIRECTION INPUT ;
    USE SIGNAL ;
    PORT
      LAYER M4 ;
        RECT  0 29.328 0.084 29.352 ;
    END
  END w_s[37]
  PIN w_s[38]
    DIRECTION INPUT ;
    USE SIGNAL ;
    PORT
      LAYER M4 ;
        RECT  0 29.424 0.084 29.448 ;
    END
  END w_s[38]
  PIN w_s[39]
    DIRECTION INPUT ;
    USE SIGNAL ;
    PORT
      LAYER M4 ;
        RECT  0 29.52 0.084 29.544 ;
    END
  END w_s[39]
  PIN w_s[3]
    DIRECTION INPUT ;
    USE SIGNAL ;
    PORT
      LAYER M4 ;
        RECT  0 51.408 0.084 51.432 ;
    END
  END w_s[3]
  PIN w_s[40]
    DIRECTION INPUT ;
    USE SIGNAL ;
    PORT
      LAYER M4 ;
        RECT  0 29.616 0.084 29.64 ;
    END
  END w_s[40]
  PIN w_s[41]
    DIRECTION INPUT ;
    USE SIGNAL ;
    PORT
      LAYER M4 ;
        RECT  0 29.712 0.084 29.736 ;
    END
  END w_s[41]
  PIN w_s[42]
    DIRECTION INPUT ;
    USE SIGNAL ;
    PORT
      LAYER M4 ;
        RECT  0 29.808 0.084 29.832 ;
    END
  END w_s[42]
  PIN w_s[43]
    DIRECTION INPUT ;
    USE SIGNAL ;
    PORT
      LAYER M4 ;
        RECT  0 29.904 0.084 29.928 ;
    END
  END w_s[43]
  PIN w_s[44]
    DIRECTION INPUT ;
    USE SIGNAL ;
    PORT
      LAYER M4 ;
        RECT  0 30 0.084 30.024 ;
    END
  END w_s[44]
  PIN w_s[45]
    DIRECTION INPUT ;
    USE SIGNAL ;
    PORT
      LAYER M4 ;
        RECT  0 30.096 0.084 30.12 ;
    END
  END w_s[45]
  PIN w_s[46]
    DIRECTION INPUT ;
    USE SIGNAL ;
    PORT
      LAYER M4 ;
        RECT  0 30.192 0.084 30.216 ;
    END
  END w_s[46]
  PIN w_s[47]
    DIRECTION INPUT ;
    USE SIGNAL ;
    PORT
      LAYER M4 ;
        RECT  0 30.288 0.084 30.312 ;
    END
  END w_s[47]
  PIN w_s[48]
    DIRECTION INPUT ;
    USE SIGNAL ;
    PORT
      LAYER M4 ;
        RECT  0 30.384 0.084 30.408 ;
    END
  END w_s[48]
  PIN w_s[49]
    DIRECTION INPUT ;
    USE SIGNAL ;
    PORT
      LAYER M4 ;
        RECT  0 30.48 0.084 30.504 ;
    END
  END w_s[49]
  PIN w_s[4]
    DIRECTION INPUT ;
    USE SIGNAL ;
    PORT
      LAYER M4 ;
        RECT  0 51.504 0.084 51.528 ;
    END
  END w_s[4]
  PIN w_s[50]
    DIRECTION INPUT ;
    USE SIGNAL ;
    PORT
      LAYER M4 ;
        RECT  0 43.632 0.084 43.656 ;
    END
  END w_s[50]
  PIN w_s[51]
    DIRECTION INPUT ;
    USE SIGNAL ;
    PORT
      LAYER M4 ;
        RECT  0 43.728 0.084 43.752 ;
    END
  END w_s[51]
  PIN w_s[52]
    DIRECTION INPUT ;
    USE SIGNAL ;
    PORT
      LAYER M4 ;
        RECT  0 43.824 0.084 43.848 ;
    END
  END w_s[52]
  PIN w_s[53]
    DIRECTION INPUT ;
    USE SIGNAL ;
    PORT
      LAYER M4 ;
        RECT  0 43.92 0.084 43.944 ;
    END
  END w_s[53]
  PIN w_s[54]
    DIRECTION INPUT ;
    USE SIGNAL ;
    PORT
      LAYER M4 ;
        RECT  0 44.016 0.084 44.04 ;
    END
  END w_s[54]
  PIN w_s[55]
    DIRECTION INPUT ;
    USE SIGNAL ;
    PORT
      LAYER M4 ;
        RECT  0 44.112 0.084 44.136 ;
    END
  END w_s[55]
  PIN w_s[56]
    DIRECTION INPUT ;
    USE SIGNAL ;
    PORT
      LAYER M4 ;
        RECT  0 44.208 0.084 44.232 ;
    END
  END w_s[56]
  PIN w_s[57]
    DIRECTION INPUT ;
    USE SIGNAL ;
    PORT
      LAYER M4 ;
        RECT  0 44.304 0.084 44.328 ;
    END
  END w_s[57]
  PIN w_s[58]
    DIRECTION INPUT ;
    USE SIGNAL ;
    PORT
      LAYER M4 ;
        RECT  0 44.4 0.084 44.424 ;
    END
  END w_s[58]
  PIN w_s[59]
    DIRECTION INPUT ;
    USE SIGNAL ;
    PORT
      LAYER M4 ;
        RECT  0 44.496 0.084 44.52 ;
    END
  END w_s[59]
  PIN w_s[5]
    DIRECTION INPUT ;
    USE SIGNAL ;
    PORT
      LAYER M4 ;
        RECT  0 51.6 0.084 51.624 ;
    END
  END w_s[5]
  PIN w_s[60]
    DIRECTION INPUT ;
    USE SIGNAL ;
    PORT
      LAYER M4 ;
        RECT  0 44.592 0.084 44.616 ;
    END
  END w_s[60]
  PIN w_s[61]
    DIRECTION INPUT ;
    USE SIGNAL ;
    PORT
      LAYER M4 ;
        RECT  0 44.688 0.084 44.712 ;
    END
  END w_s[61]
  PIN w_s[62]
    DIRECTION INPUT ;
    USE SIGNAL ;
    PORT
      LAYER M4 ;
        RECT  0 44.784 0.084 44.808 ;
    END
  END w_s[62]
  PIN w_s[63]
    DIRECTION INPUT ;
    USE SIGNAL ;
    PORT
      LAYER M4 ;
        RECT  0 44.88 0.084 44.904 ;
    END
  END w_s[63]
  PIN w_s[6]
    DIRECTION INPUT ;
    USE SIGNAL ;
    PORT
      LAYER M4 ;
        RECT  0 51.696 0.084 51.72 ;
    END
  END w_s[6]
  PIN w_s[7]
    DIRECTION INPUT ;
    USE SIGNAL ;
    PORT
      LAYER M4 ;
        RECT  0 51.792 0.084 51.816 ;
    END
  END w_s[7]
  PIN w_s[8]
    DIRECTION INPUT ;
    USE SIGNAL ;
    PORT
      LAYER M4 ;
        RECT  0 51.888 0.084 51.912 ;
    END
  END w_s[8]
  PIN w_s[9]
    DIRECTION INPUT ;
    USE SIGNAL ;
    PORT
      LAYER M4 ;
        RECT  0 51.984 0.084 52.008 ;
    END
  END w_s[9]
  PIN x_s[0]
    DIRECTION INPUT ;
    USE SIGNAL ;
    PORT
      LAYER M4 ;
        RECT  0 44.976 0.084 45 ;
    END
  END x_s[0]
  PIN x_s[10]
    DIRECTION INPUT ;
    USE SIGNAL ;
    PORT
      LAYER M4 ;
        RECT  0 45.936 0.084 45.96 ;
    END
  END x_s[10]
  PIN x_s[11]
    DIRECTION INPUT ;
    USE SIGNAL ;
    PORT
      LAYER M4 ;
        RECT  0 46.032 0.084 46.056 ;
    END
  END x_s[11]
  PIN x_s[12]
    DIRECTION INPUT ;
    USE SIGNAL ;
    PORT
      LAYER M4 ;
        RECT  0 46.128 0.084 46.152 ;
    END
  END x_s[12]
  PIN x_s[13]
    DIRECTION INPUT ;
    USE SIGNAL ;
    PORT
      LAYER M4 ;
        RECT  0 46.224 0.084 46.248 ;
    END
  END x_s[13]
  PIN x_s[14]
    DIRECTION INPUT ;
    USE SIGNAL ;
    PORT
      LAYER M4 ;
        RECT  0 46.32 0.084 46.344 ;
    END
  END x_s[14]
  PIN x_s[15]
    DIRECTION INPUT ;
    USE SIGNAL ;
    PORT
      LAYER M4 ;
        RECT  0 46.416 0.084 46.44 ;
    END
  END x_s[15]
  PIN x_s[16]
    DIRECTION INPUT ;
    USE SIGNAL ;
    PORT
      LAYER M4 ;
        RECT  0 46.512 0.084 46.536 ;
    END
  END x_s[16]
  PIN x_s[17]
    DIRECTION INPUT ;
    USE SIGNAL ;
    PORT
      LAYER M4 ;
        RECT  0 46.608 0.084 46.632 ;
    END
  END x_s[17]
  PIN x_s[18]
    DIRECTION INPUT ;
    USE SIGNAL ;
    PORT
      LAYER M4 ;
        RECT  0 37.488 0.084 37.512 ;
    END
  END x_s[18]
  PIN x_s[19]
    DIRECTION INPUT ;
    USE SIGNAL ;
    PORT
      LAYER M4 ;
        RECT  0 37.584 0.084 37.608 ;
    END
  END x_s[19]
  PIN x_s[1]
    DIRECTION INPUT ;
    USE SIGNAL ;
    PORT
      LAYER M4 ;
        RECT  0 45.072 0.084 45.096 ;
    END
  END x_s[1]
  PIN x_s[20]
    DIRECTION INPUT ;
    USE SIGNAL ;
    PORT
      LAYER M4 ;
        RECT  0 37.68 0.084 37.704 ;
    END
  END x_s[20]
  PIN x_s[21]
    DIRECTION INPUT ;
    USE SIGNAL ;
    PORT
      LAYER M4 ;
        RECT  0 37.776 0.084 37.8 ;
    END
  END x_s[21]
  PIN x_s[22]
    DIRECTION INPUT ;
    USE SIGNAL ;
    PORT
      LAYER M4 ;
        RECT  0 37.872 0.084 37.896 ;
    END
  END x_s[22]
  PIN x_s[23]
    DIRECTION INPUT ;
    USE SIGNAL ;
    PORT
      LAYER M4 ;
        RECT  0 37.968 0.084 37.992 ;
    END
  END x_s[23]
  PIN x_s[24]
    DIRECTION INPUT ;
    USE SIGNAL ;
    PORT
      LAYER M4 ;
        RECT  0 38.064 0.084 38.088 ;
    END
  END x_s[24]
  PIN x_s[25]
    DIRECTION INPUT ;
    USE SIGNAL ;
    PORT
      LAYER M4 ;
        RECT  0 38.16 0.084 38.184 ;
    END
  END x_s[25]
  PIN x_s[26]
    DIRECTION INPUT ;
    USE SIGNAL ;
    PORT
      LAYER M4 ;
        RECT  0 38.256 0.084 38.28 ;
    END
  END x_s[26]
  PIN x_s[27]
    DIRECTION INPUT ;
    USE SIGNAL ;
    PORT
      LAYER M4 ;
        RECT  0 38.352 0.084 38.376 ;
    END
  END x_s[27]
  PIN x_s[28]
    DIRECTION INPUT ;
    USE SIGNAL ;
    PORT
      LAYER M4 ;
        RECT  0 38.448 0.084 38.472 ;
    END
  END x_s[28]
  PIN x_s[29]
    DIRECTION INPUT ;
    USE SIGNAL ;
    PORT
      LAYER M4 ;
        RECT  0 38.544 0.084 38.568 ;
    END
  END x_s[29]
  PIN x_s[2]
    DIRECTION INPUT ;
    USE SIGNAL ;
    PORT
      LAYER M4 ;
        RECT  0 45.168 0.084 45.192 ;
    END
  END x_s[2]
  PIN x_s[30]
    DIRECTION INPUT ;
    USE SIGNAL ;
    PORT
      LAYER M4 ;
        RECT  0 38.64 0.084 38.664 ;
    END
  END x_s[30]
  PIN x_s[31]
    DIRECTION INPUT ;
    USE SIGNAL ;
    PORT
      LAYER M4 ;
        RECT  0 38.736 0.084 38.76 ;
    END
  END x_s[31]
  PIN x_s[32]
    DIRECTION INPUT ;
    USE SIGNAL ;
    PORT
      LAYER M4 ;
        RECT  0 38.832 0.084 38.856 ;
    END
  END x_s[32]
  PIN x_s[33]
    DIRECTION INPUT ;
    USE SIGNAL ;
    PORT
      LAYER M4 ;
        RECT  0 38.928 0.084 38.952 ;
    END
  END x_s[33]
  PIN x_s[34]
    DIRECTION INPUT ;
    USE SIGNAL ;
    PORT
      LAYER M4 ;
        RECT  0 39.024 0.084 39.048 ;
    END
  END x_s[34]
  PIN x_s[35]
    DIRECTION INPUT ;
    USE SIGNAL ;
    PORT
      LAYER M4 ;
        RECT  0 39.12 0.084 39.144 ;
    END
  END x_s[35]
  PIN x_s[36]
    DIRECTION INPUT ;
    USE SIGNAL ;
    PORT
      LAYER M4 ;
        RECT  0 39.216 0.084 39.24 ;
    END
  END x_s[36]
  PIN x_s[37]
    DIRECTION INPUT ;
    USE SIGNAL ;
    PORT
      LAYER M4 ;
        RECT  0 39.312 0.084 39.336 ;
    END
  END x_s[37]
  PIN x_s[38]
    DIRECTION INPUT ;
    USE SIGNAL ;
    PORT
      LAYER M4 ;
        RECT  0 39.408 0.084 39.432 ;
    END
  END x_s[38]
  PIN x_s[39]
    DIRECTION INPUT ;
    USE SIGNAL ;
    PORT
      LAYER M4 ;
        RECT  0 39.504 0.084 39.528 ;
    END
  END x_s[39]
  PIN x_s[3]
    DIRECTION INPUT ;
    USE SIGNAL ;
    PORT
      LAYER M4 ;
        RECT  0 45.264 0.084 45.288 ;
    END
  END x_s[3]
  PIN x_s[40]
    DIRECTION INPUT ;
    USE SIGNAL ;
    PORT
      LAYER M4 ;
        RECT  0 39.6 0.084 39.624 ;
    END
  END x_s[40]
  PIN x_s[41]
    DIRECTION INPUT ;
    USE SIGNAL ;
    PORT
      LAYER M4 ;
        RECT  0 39.696 0.084 39.72 ;
    END
  END x_s[41]
  PIN x_s[42]
    DIRECTION INPUT ;
    USE SIGNAL ;
    PORT
      LAYER M4 ;
        RECT  0 39.792 0.084 39.816 ;
    END
  END x_s[42]
  PIN x_s[43]
    DIRECTION INPUT ;
    USE SIGNAL ;
    PORT
      LAYER M4 ;
        RECT  0 39.888 0.084 39.912 ;
    END
  END x_s[43]
  PIN x_s[44]
    DIRECTION INPUT ;
    USE SIGNAL ;
    PORT
      LAYER M4 ;
        RECT  0 39.984 0.084 40.008 ;
    END
  END x_s[44]
  PIN x_s[45]
    DIRECTION INPUT ;
    USE SIGNAL ;
    PORT
      LAYER M4 ;
        RECT  0 40.08 0.084 40.104 ;
    END
  END x_s[45]
  PIN x_s[46]
    DIRECTION INPUT ;
    USE SIGNAL ;
    PORT
      LAYER M4 ;
        RECT  0 40.176 0.084 40.2 ;
    END
  END x_s[46]
  PIN x_s[47]
    DIRECTION INPUT ;
    USE SIGNAL ;
    PORT
      LAYER M4 ;
        RECT  0 40.272 0.084 40.296 ;
    END
  END x_s[47]
  PIN x_s[48]
    DIRECTION INPUT ;
    USE SIGNAL ;
    PORT
      LAYER M4 ;
        RECT  0 40.368 0.084 40.392 ;
    END
  END x_s[48]
  PIN x_s[49]
    DIRECTION INPUT ;
    USE SIGNAL ;
    PORT
      LAYER M4 ;
        RECT  0 40.464 0.084 40.488 ;
    END
  END x_s[49]
  PIN x_s[4]
    DIRECTION INPUT ;
    USE SIGNAL ;
    PORT
      LAYER M4 ;
        RECT  0 45.36 0.084 45.384 ;
    END
  END x_s[4]
  PIN x_s[50]
    DIRECTION INPUT ;
    USE SIGNAL ;
    PORT
      LAYER M4 ;
        RECT  0 19.92 0.084 19.944 ;
    END
  END x_s[50]
  PIN x_s[51]
    DIRECTION INPUT ;
    USE SIGNAL ;
    PORT
      LAYER M4 ;
        RECT  0 20.016 0.084 20.04 ;
    END
  END x_s[51]
  PIN x_s[52]
    DIRECTION INPUT ;
    USE SIGNAL ;
    PORT
      LAYER M4 ;
        RECT  0 20.112 0.084 20.136 ;
    END
  END x_s[52]
  PIN x_s[53]
    DIRECTION INPUT ;
    USE SIGNAL ;
    PORT
      LAYER M4 ;
        RECT  0 20.208 0.084 20.232 ;
    END
  END x_s[53]
  PIN x_s[54]
    DIRECTION INPUT ;
    USE SIGNAL ;
    PORT
      LAYER M4 ;
        RECT  0 20.304 0.084 20.328 ;
    END
  END x_s[54]
  PIN x_s[55]
    DIRECTION INPUT ;
    USE SIGNAL ;
    PORT
      LAYER M4 ;
        RECT  0 20.4 0.084 20.424 ;
    END
  END x_s[55]
  PIN x_s[56]
    DIRECTION INPUT ;
    USE SIGNAL ;
    PORT
      LAYER M4 ;
        RECT  0 20.496 0.084 20.52 ;
    END
  END x_s[56]
  PIN x_s[57]
    DIRECTION INPUT ;
    USE SIGNAL ;
    PORT
      LAYER M4 ;
        RECT  0 20.592 0.084 20.616 ;
    END
  END x_s[57]
  PIN x_s[58]
    DIRECTION INPUT ;
    USE SIGNAL ;
    PORT
      LAYER M4 ;
        RECT  0 20.688 0.084 20.712 ;
    END
  END x_s[58]
  PIN x_s[59]
    DIRECTION INPUT ;
    USE SIGNAL ;
    PORT
      LAYER M4 ;
        RECT  0 20.784 0.084 20.808 ;
    END
  END x_s[59]
  PIN x_s[5]
    DIRECTION INPUT ;
    USE SIGNAL ;
    PORT
      LAYER M4 ;
        RECT  0 45.456 0.084 45.48 ;
    END
  END x_s[5]
  PIN x_s[60]
    DIRECTION INPUT ;
    USE SIGNAL ;
    PORT
      LAYER M4 ;
        RECT  0 20.88 0.084 20.904 ;
    END
  END x_s[60]
  PIN x_s[61]
    DIRECTION INPUT ;
    USE SIGNAL ;
    PORT
      LAYER M4 ;
        RECT  0 20.976 0.084 21 ;
    END
  END x_s[61]
  PIN x_s[62]
    DIRECTION INPUT ;
    USE SIGNAL ;
    PORT
      LAYER M4 ;
        RECT  0 21.072 0.084 21.096 ;
    END
  END x_s[62]
  PIN x_s[63]
    DIRECTION INPUT ;
    USE SIGNAL ;
    PORT
      LAYER M4 ;
        RECT  0 21.168 0.084 21.192 ;
    END
  END x_s[63]
  PIN x_s[6]
    DIRECTION INPUT ;
    USE SIGNAL ;
    PORT
      LAYER M4 ;
        RECT  0 45.552 0.084 45.576 ;
    END
  END x_s[6]
  PIN x_s[7]
    DIRECTION INPUT ;
    USE SIGNAL ;
    PORT
      LAYER M4 ;
        RECT  0 45.648 0.084 45.672 ;
    END
  END x_s[7]
  PIN x_s[8]
    DIRECTION INPUT ;
    USE SIGNAL ;
    PORT
      LAYER M4 ;
        RECT  0 45.744 0.084 45.768 ;
    END
  END x_s[8]
  PIN x_s[9]
    DIRECTION INPUT ;
    USE SIGNAL ;
    PORT
      LAYER M4 ;
        RECT  0 45.84 0.084 45.864 ;
    END
  END x_s[9]
  PIN ze_d
    DIRECTION INPUT ;
    USE SIGNAL ;
    PORT
      LAYER M4 ;
        RECT  0 21.264 0.084 21.288 ;
    END
  END ze_d
  PIN VSS
    DIRECTION INOUT ;
    USE GROUND ;
    PORT
      LAYER M5 ;
        RECT  83.4 2.137 83.52 92.903 ;
        RECT  78 2.137 78.12 92.903 ;
        RECT  72.6 2.137 72.72 92.903 ;
        RECT  67.2 2.137 67.32 92.903 ;
        RECT  61.8 2.137 61.92 92.903 ;
        RECT  56.4 2.137 56.52 92.903 ;
        RECT  51 2.137 51.12 92.903 ;
        RECT  45.6 2.137 45.72 92.903 ;
        RECT  40.2 2.137 40.32 92.903 ;
        RECT  34.8 2.137 34.92 92.903 ;
        RECT  29.4 2.137 29.52 92.903 ;
        RECT  24 2.137 24.12 92.903 ;
        RECT  18.6 2.137 18.72 92.903 ;
        RECT  13.2 2.137 13.32 92.903 ;
        RECT  7.8 2.137 7.92 92.903 ;
        RECT  2.4 2.137 2.52 92.903 ;
    END
  END VSS
  PIN VDD
    DIRECTION INOUT ;
    USE POWER ;
    PORT
      LAYER M5 ;
        RECT  83.592 2.151 83.712 92.889 ;
        RECT  78.192 2.151 78.312 92.889 ;
        RECT  72.792 2.151 72.912 92.889 ;
        RECT  67.392 2.151 67.512 92.889 ;
        RECT  61.992 2.151 62.112 92.889 ;
        RECT  56.592 2.151 56.712 92.889 ;
        RECT  51.192 2.151 51.312 92.889 ;
        RECT  45.792 2.151 45.912 92.889 ;
        RECT  40.392 2.151 40.512 92.889 ;
        RECT  34.992 2.151 35.112 92.889 ;
        RECT  29.592 2.151 29.712 92.889 ;
        RECT  24.192 2.151 24.312 92.889 ;
        RECT  18.792 2.151 18.912 92.889 ;
        RECT  13.392 2.151 13.512 92.889 ;
        RECT  7.992 2.151 8.112 92.889 ;
        RECT  2.592 2.151 2.712 92.889 ;
    END
  END VDD
  # OT_OBS_CLOSED layer=M5 d_um=1.536 added=929
  OBS
    LAYER RVTN ;
     RECT  2.16 2.16 84.24 2.295 ;
     RECT  2.16 2.565 84.24 2.835 ;
     RECT  2.16 3.105 84.24 3.375 ;
     RECT  2.16 3.645 84.24 3.915 ;
     RECT  2.16 4.185 84.24 4.455 ;
     RECT  2.16 4.725 84.24 4.995 ;
     RECT  2.16 5.265 84.24 5.535 ;
     RECT  2.16 5.805 84.24 6.075 ;
     RECT  2.16 6.345 84.24 6.615 ;
     RECT  2.16 6.885 84.24 7.155 ;
     RECT  2.16 7.425 84.24 7.695 ;
     RECT  2.16 7.965 84.24 8.235 ;
     RECT  2.16 8.505 84.24 8.775 ;
     RECT  2.16 9.045 84.24 9.315 ;
     RECT  2.16 9.585 84.24 9.855 ;
     RECT  2.16 10.125 84.24 10.395 ;
     RECT  2.16 10.665 84.24 10.935 ;
     RECT  2.16 11.205 84.24 11.475 ;
     RECT  2.16 11.745 84.24 12.015 ;
     RECT  2.16 12.285 84.24 12.555 ;
     RECT  2.16 12.825 84.24 13.095 ;
     RECT  2.16 13.365 84.24 13.635 ;
     RECT  2.16 13.905 84.24 14.175 ;
     RECT  2.16 14.445 84.24 14.715 ;
     RECT  2.16 14.985 84.24 15.255 ;
     RECT  2.16 15.525 84.24 15.795 ;
     RECT  2.16 16.065 84.24 16.335 ;
     RECT  2.16 16.605 84.24 16.875 ;
     RECT  2.16 17.145 84.24 17.415 ;
     RECT  2.16 17.685 84.24 17.955 ;
     RECT  2.16 18.225 84.24 18.495 ;
     RECT  2.16 18.765 84.24 19.035 ;
     RECT  2.16 19.305 84.24 19.575 ;
     RECT  2.16 19.845 84.24 20.115 ;
     RECT  2.16 20.385 84.24 20.655 ;
     RECT  2.16 20.925 84.24 21.195 ;
     RECT  2.16 21.465 84.24 21.735 ;
     RECT  2.16 22.005 84.24 22.275 ;
     RECT  2.16 22.545 84.24 22.815 ;
     RECT  2.16 23.085 84.24 23.355 ;
     RECT  2.16 23.625 84.24 23.895 ;
     RECT  2.16 24.165 84.24 24.435 ;
     RECT  2.16 24.705 84.24 24.975 ;
     RECT  2.16 25.245 84.24 25.515 ;
     RECT  2.16 25.785 84.24 26.055 ;
     RECT  2.16 26.325 84.24 26.595 ;
     RECT  2.16 26.865 84.24 27.135 ;
     RECT  2.16 27.405 84.24 27.675 ;
     RECT  2.16 27.945 84.24 28.215 ;
     RECT  2.16 28.485 84.24 28.755 ;
     RECT  2.16 29.025 84.24 29.295 ;
     RECT  2.16 29.565 84.24 29.835 ;
     RECT  2.16 30.105 84.24 30.375 ;
     RECT  2.16 30.645 84.24 30.915 ;
     RECT  2.16 31.185 84.24 31.455 ;
     RECT  2.16 31.725 84.24 31.995 ;
     RECT  2.16 32.265 84.24 32.535 ;
     RECT  2.16 32.805 84.24 33.075 ;
     RECT  2.16 33.345 84.24 33.615 ;
     RECT  2.16 33.885 84.24 34.155 ;
     RECT  2.16 34.425 84.24 34.695 ;
     RECT  2.16 34.965 84.24 35.235 ;
     RECT  2.16 35.505 84.24 35.775 ;
     RECT  2.16 36.045 84.24 36.315 ;
     RECT  2.16 36.585 84.24 36.855 ;
     RECT  2.16 37.125 84.24 37.395 ;
     RECT  2.16 37.665 84.24 37.935 ;
     RECT  2.16 38.205 84.24 38.475 ;
     RECT  2.16 38.745 84.24 39.015 ;
     RECT  2.16 39.285 84.24 39.555 ;
     RECT  2.16 39.825 84.24 40.095 ;
     RECT  2.16 40.365 84.24 40.635 ;
     RECT  2.16 40.905 84.24 41.175 ;
     RECT  2.16 41.445 84.24 41.715 ;
     RECT  2.16 41.985 84.24 42.255 ;
     RECT  2.16 42.525 84.24 42.795 ;
     RECT  2.16 43.065 84.24 43.335 ;
     RECT  2.16 43.605 84.24 43.875 ;
     RECT  2.16 44.145 84.24 44.415 ;
     RECT  2.16 44.685 84.24 44.955 ;
     RECT  2.16 45.225 84.24 45.495 ;
     RECT  2.16 45.765 84.24 46.035 ;
     RECT  2.16 46.305 84.24 46.575 ;
     RECT  2.16 46.845 84.24 47.115 ;
     RECT  2.16 47.385 84.24 47.655 ;
     RECT  2.16 47.925 84.24 48.195 ;
     RECT  2.16 48.465 84.24 48.735 ;
     RECT  2.16 49.005 84.24 49.275 ;
     RECT  2.16 49.545 84.24 49.815 ;
     RECT  2.16 50.085 84.24 50.355 ;
     RECT  2.16 50.625 84.24 50.895 ;
     RECT  2.16 51.165 84.24 51.435 ;
     RECT  2.16 51.705 84.24 51.975 ;
     RECT  2.16 52.245 84.24 52.515 ;
     RECT  2.16 52.785 84.24 53.055 ;
     RECT  2.16 53.325 84.24 53.595 ;
     RECT  2.16 53.865 84.24 54.135 ;
     RECT  2.16 54.405 84.24 54.675 ;
     RECT  2.16 54.945 84.24 55.215 ;
     RECT  2.16 55.485 84.24 55.755 ;
     RECT  2.16 56.025 84.24 56.295 ;
     RECT  2.16 56.565 84.24 56.835 ;
     RECT  2.16 57.105 84.24 57.375 ;
     RECT  2.16 57.645 84.24 57.915 ;
     RECT  2.16 58.185 84.24 58.455 ;
     RECT  2.16 58.725 84.24 58.995 ;
     RECT  2.16 59.265 84.24 59.535 ;
     RECT  2.16 59.805 84.24 60.075 ;
     RECT  2.16 60.345 84.24 60.615 ;
     RECT  2.16 60.885 84.24 61.155 ;
     RECT  2.16 61.425 84.24 61.695 ;
     RECT  2.16 61.965 84.24 62.235 ;
     RECT  2.16 62.505 84.24 62.775 ;
     RECT  2.16 63.045 84.24 63.315 ;
     RECT  2.16 63.585 84.24 63.855 ;
     RECT  2.16 64.125 84.24 64.395 ;
     RECT  2.16 64.665 84.24 64.935 ;
     RECT  2.16 65.205 84.24 65.475 ;
     RECT  2.16 65.745 84.24 66.015 ;
     RECT  2.16 66.285 84.24 66.555 ;
     RECT  2.16 66.825 84.24 67.095 ;
     RECT  2.16 67.365 84.24 67.635 ;
     RECT  2.16 67.905 84.24 68.175 ;
     RECT  2.16 68.445 84.24 68.715 ;
     RECT  2.16 68.985 84.24 69.255 ;
     RECT  2.16 69.525 84.24 69.795 ;
     RECT  2.16 70.065 84.24 70.335 ;
     RECT  2.16 70.605 84.24 70.875 ;
     RECT  2.16 71.145 84.24 71.415 ;
     RECT  2.16 71.685 84.24 71.955 ;
     RECT  2.16 72.225 84.24 72.495 ;
     RECT  2.16 72.765 84.24 73.035 ;
     RECT  2.16 73.305 84.24 73.575 ;
     RECT  2.16 73.845 84.24 74.115 ;
     RECT  2.16 74.385 84.24 74.655 ;
     RECT  2.16 74.925 84.24 75.195 ;
     RECT  2.16 75.465 84.24 75.735 ;
     RECT  2.16 76.005 84.24 76.275 ;
     RECT  2.16 76.545 84.24 76.815 ;
     RECT  2.16 77.085 84.24 77.355 ;
     RECT  2.16 77.625 84.24 77.895 ;
     RECT  2.16 78.165 84.24 78.435 ;
     RECT  2.16 78.705 84.24 78.975 ;
     RECT  2.16 79.245 84.24 79.515 ;
     RECT  2.16 79.785 84.24 80.055 ;
     RECT  2.16 80.325 84.24 80.595 ;
     RECT  2.16 80.865 84.24 81.135 ;
     RECT  2.16 81.405 84.24 81.675 ;
     RECT  2.16 81.945 84.24 82.215 ;
     RECT  2.16 82.485 84.24 82.755 ;
     RECT  2.16 83.025 84.24 83.295 ;
     RECT  2.16 83.565 84.24 83.835 ;
     RECT  2.16 84.105 84.24 84.375 ;
     RECT  2.16 84.645 84.24 84.915 ;
     RECT  2.16 85.185 84.24 85.455 ;
     RECT  2.16 85.725 84.24 85.995 ;
     RECT  2.16 86.265 84.24 86.535 ;
     RECT  2.16 86.805 84.24 87.075 ;
     RECT  2.16 87.345 84.24 87.615 ;
     RECT  2.16 87.885 84.24 88.155 ;
     RECT  2.16 88.425 84.24 88.695 ;
     RECT  2.16 88.965 84.24 89.235 ;
     RECT  2.16 89.505 84.24 89.775 ;
     RECT  2.16 90.045 84.24 90.315 ;
     RECT  2.16 90.585 84.24 90.855 ;
     RECT  2.16 91.125 84.24 91.395 ;
     RECT  2.16 91.665 84.24 91.935 ;
     RECT  2.16 92.205 84.24 92.475 ;
     RECT  2.16 92.745 84.24 92.88 ;
    LAYER RVTP ;
     RECT  2.16 2.295 84.24 2.565 ;
     RECT  2.16 2.835 84.24 3.105 ;
     RECT  2.16 3.375 84.24 3.645 ;
     RECT  2.16 3.915 84.24 4.185 ;
     RECT  2.16 4.455 84.24 4.725 ;
     RECT  2.16 4.995 84.24 5.265 ;
     RECT  2.16 5.535 84.24 5.805 ;
     RECT  2.16 6.075 84.24 6.345 ;
     RECT  2.16 6.615 84.24 6.885 ;
     RECT  2.16 7.155 84.24 7.425 ;
     RECT  2.16 7.695 84.24 7.965 ;
     RECT  2.16 8.235 84.24 8.505 ;
     RECT  2.16 8.775 84.24 9.045 ;
     RECT  2.16 9.315 84.24 9.585 ;
     RECT  2.16 9.855 84.24 10.125 ;
     RECT  2.16 10.395 84.24 10.665 ;
     RECT  2.16 10.935 84.24 11.205 ;
     RECT  2.16 11.475 84.24 11.745 ;
     RECT  2.16 12.015 84.24 12.285 ;
     RECT  2.16 12.555 84.24 12.825 ;
     RECT  2.16 13.095 84.24 13.365 ;
     RECT  2.16 13.635 84.24 13.905 ;
     RECT  2.16 14.175 84.24 14.445 ;
     RECT  2.16 14.715 84.24 14.985 ;
     RECT  2.16 15.255 84.24 15.525 ;
     RECT  2.16 15.795 84.24 16.065 ;
     RECT  2.16 16.335 84.24 16.605 ;
     RECT  2.16 16.875 84.24 17.145 ;
     RECT  2.16 17.415 84.24 17.685 ;
     RECT  2.16 17.955 84.24 18.225 ;
     RECT  2.16 18.495 84.24 18.765 ;
     RECT  2.16 19.035 84.24 19.305 ;
     RECT  2.16 19.575 84.24 19.845 ;
     RECT  2.16 20.115 84.24 20.385 ;
     RECT  2.16 20.655 84.24 20.925 ;
     RECT  2.16 21.195 84.24 21.465 ;
     RECT  2.16 21.735 84.24 22.005 ;
     RECT  2.16 22.275 84.24 22.545 ;
     RECT  2.16 22.815 84.24 23.085 ;
     RECT  2.16 23.355 84.24 23.625 ;
     RECT  2.16 23.895 84.24 24.165 ;
     RECT  2.16 24.435 84.24 24.705 ;
     RECT  2.16 24.975 84.24 25.245 ;
     RECT  2.16 25.515 84.24 25.785 ;
     RECT  2.16 26.055 84.24 26.325 ;
     RECT  2.16 26.595 84.24 26.865 ;
     RECT  2.16 27.135 84.24 27.405 ;
     RECT  2.16 27.675 84.24 27.945 ;
     RECT  2.16 28.215 84.24 28.485 ;
     RECT  2.16 28.755 84.24 29.025 ;
     RECT  2.16 29.295 84.24 29.565 ;
     RECT  2.16 29.835 84.24 30.105 ;
     RECT  2.16 30.375 84.24 30.645 ;
     RECT  2.16 30.915 84.24 31.185 ;
     RECT  2.16 31.455 84.24 31.725 ;
     RECT  2.16 31.995 84.24 32.265 ;
     RECT  2.16 32.535 84.24 32.805 ;
     RECT  2.16 33.075 84.24 33.345 ;
     RECT  2.16 33.615 84.24 33.885 ;
     RECT  2.16 34.155 84.24 34.425 ;
     RECT  2.16 34.695 84.24 34.965 ;
     RECT  2.16 35.235 84.24 35.505 ;
     RECT  2.16 35.775 84.24 36.045 ;
     RECT  2.16 36.315 84.24 36.585 ;
     RECT  2.16 36.855 84.24 37.125 ;
     RECT  2.16 37.395 84.24 37.665 ;
     RECT  2.16 37.935 84.24 38.205 ;
     RECT  2.16 38.475 84.24 38.745 ;
     RECT  2.16 39.015 84.24 39.285 ;
     RECT  2.16 39.555 84.24 39.825 ;
     RECT  2.16 40.095 84.24 40.365 ;
     RECT  2.16 40.635 84.24 40.905 ;
     RECT  2.16 41.175 84.24 41.445 ;
     RECT  2.16 41.715 84.24 41.985 ;
     RECT  2.16 42.255 84.24 42.525 ;
     RECT  2.16 42.795 84.24 43.065 ;
     RECT  2.16 43.335 84.24 43.605 ;
     RECT  2.16 43.875 84.24 44.145 ;
     RECT  2.16 44.415 84.24 44.685 ;
     RECT  2.16 44.955 84.24 45.225 ;
     RECT  2.16 45.495 84.24 45.765 ;
     RECT  2.16 46.035 84.24 46.305 ;
     RECT  2.16 46.575 84.24 46.845 ;
     RECT  2.16 47.115 84.24 47.385 ;
     RECT  2.16 47.655 84.24 47.925 ;
     RECT  2.16 48.195 84.24 48.465 ;
     RECT  2.16 48.735 84.24 49.005 ;
     RECT  2.16 49.275 84.24 49.545 ;
     RECT  2.16 49.815 84.24 50.085 ;
     RECT  2.16 50.355 84.24 50.625 ;
     RECT  2.16 50.895 84.24 51.165 ;
     RECT  2.16 51.435 84.24 51.705 ;
     RECT  2.16 51.975 84.24 52.245 ;
     RECT  2.16 52.515 84.24 52.785 ;
     RECT  2.16 53.055 84.24 53.325 ;
     RECT  2.16 53.595 84.24 53.865 ;
     RECT  2.16 54.135 84.24 54.405 ;
     RECT  2.16 54.675 84.24 54.945 ;
     RECT  2.16 55.215 84.24 55.485 ;
     RECT  2.16 55.755 84.24 56.025 ;
     RECT  2.16 56.295 84.24 56.565 ;
     RECT  2.16 56.835 84.24 57.105 ;
     RECT  2.16 57.375 84.24 57.645 ;
     RECT  2.16 57.915 84.24 58.185 ;
     RECT  2.16 58.455 84.24 58.725 ;
     RECT  2.16 58.995 84.24 59.265 ;
     RECT  2.16 59.535 84.24 59.805 ;
     RECT  2.16 60.075 84.24 60.345 ;
     RECT  2.16 60.615 84.24 60.885 ;
     RECT  2.16 61.155 84.24 61.425 ;
     RECT  2.16 61.695 84.24 61.965 ;
     RECT  2.16 62.235 84.24 62.505 ;
     RECT  2.16 62.775 84.24 63.045 ;
     RECT  2.16 63.315 84.24 63.585 ;
     RECT  2.16 63.855 84.24 64.125 ;
     RECT  2.16 64.395 84.24 64.665 ;
     RECT  2.16 64.935 84.24 65.205 ;
     RECT  2.16 65.475 84.24 65.745 ;
     RECT  2.16 66.015 84.24 66.285 ;
     RECT  2.16 66.555 84.24 66.825 ;
     RECT  2.16 67.095 84.24 67.365 ;
     RECT  2.16 67.635 84.24 67.905 ;
     RECT  2.16 68.175 84.24 68.445 ;
     RECT  2.16 68.715 84.24 68.985 ;
     RECT  2.16 69.255 84.24 69.525 ;
     RECT  2.16 69.795 84.24 70.065 ;
     RECT  2.16 70.335 84.24 70.605 ;
     RECT  2.16 70.875 84.24 71.145 ;
     RECT  2.16 71.415 84.24 71.685 ;
     RECT  2.16 71.955 84.24 72.225 ;
     RECT  2.16 72.495 84.24 72.765 ;
     RECT  2.16 73.035 84.24 73.305 ;
     RECT  2.16 73.575 84.24 73.845 ;
     RECT  2.16 74.115 84.24 74.385 ;
     RECT  2.16 74.655 84.24 74.925 ;
     RECT  2.16 75.195 84.24 75.465 ;
     RECT  2.16 75.735 84.24 76.005 ;
     RECT  2.16 76.275 84.24 76.545 ;
     RECT  2.16 76.815 84.24 77.085 ;
     RECT  2.16 77.355 84.24 77.625 ;
     RECT  2.16 77.895 84.24 78.165 ;
     RECT  2.16 78.435 84.24 78.705 ;
     RECT  2.16 78.975 84.24 79.245 ;
     RECT  2.16 79.515 84.24 79.785 ;
     RECT  2.16 80.055 84.24 80.325 ;
     RECT  2.16 80.595 84.24 80.865 ;
     RECT  2.16 81.135 84.24 81.405 ;
     RECT  2.16 81.675 84.24 81.945 ;
     RECT  2.16 82.215 84.24 82.485 ;
     RECT  2.16 82.755 84.24 83.025 ;
     RECT  2.16 83.295 84.24 83.565 ;
     RECT  2.16 83.835 84.24 84.105 ;
     RECT  2.16 84.375 84.24 84.645 ;
     RECT  2.16 84.915 84.24 85.185 ;
     RECT  2.16 85.455 84.24 85.725 ;
     RECT  2.16 85.995 84.24 86.265 ;
     RECT  2.16 86.535 84.24 86.805 ;
     RECT  2.16 87.075 84.24 87.345 ;
     RECT  2.16 87.615 84.24 87.885 ;
     RECT  2.16 88.155 84.24 88.425 ;
     RECT  2.16 88.695 84.24 88.965 ;
     RECT  2.16 89.235 84.24 89.505 ;
     RECT  2.16 89.775 84.24 90.045 ;
     RECT  2.16 90.315 84.24 90.585 ;
     RECT  2.16 90.855 84.24 91.125 ;
     RECT  2.16 91.395 84.24 91.665 ;
     RECT  2.16 91.935 84.24 92.205 ;
     RECT  2.16 92.475 84.24 92.745 ;
    LAYER M1 ;
     RECT  2.16 2.151 84.24 92.889 ;
    LAYER M2 ;
     RECT  0.103 37.602 0.139 37.62 ;
     RECT  0.103 36.252 0.175 36.27 ;
     RECT  0.139 37.026 0.175 37.62 ;
     RECT  0.103 27.342 0.499 27.36 ;
     RECT  0.175 48.672 0.499 48.69 ;
     RECT  0.103 49.482 0.499 49.5 ;
     RECT  0.103 45 0.535 45.018 ;
     RECT  0.499 48.672 0.535 49.5 ;
     RECT  0.175 51.21 0.535 51.228 ;
     RECT  0.103 52.524 0.535 52.542 ;
     RECT  0.535 48.672 0.571 49.572 ;
     RECT  0.175 36.252 1.147 37.62 ;
     RECT  0.103 46.746 1.175 46.764 ;
     RECT  0.139 54.072 1.723 54.09 ;
     RECT  0.103 19.62 2.16 19.638 ;
     RECT  0.499 27.072 2.16 27.36 ;
     RECT  0.211 31.392 2.16 31.41 ;
     RECT  1.147 35.712 2.16 37.62 ;
     RECT  0.103 38.484 2.16 39.24 ;
     RECT  0.535 41.112 2.16 41.13 ;
     RECT  0.103 42.804 2.16 42.822 ;
     RECT  0.103 43.812 2.16 43.83 ;
     RECT  0.535 44.928 2.16 45.018 ;
     RECT  0.571 48.402 2.16 49.572 ;
     RECT  0.535 50.67 2.16 51.228 ;
     RECT  0.535 51.984 2.16 52.542 ;
     RECT  1.723 53.802 2.16 54.09 ;
     RECT  2.16 2.151 73.183 92.889 ;
     RECT  73.183 2.106 73.535 92.889 ;
     RECT  73.535 2.151 84.24 92.889 ;
     RECT  84.24 60.048 84.875 72.954 ;
     RECT  84.875 60.318 84.911 70.398 ;
     RECT  84.875 71.226 84.911 72.954 ;
     RECT  84.24 33.588 84.947 36.504 ;
     RECT  84.947 33.588 84.983 33.606 ;
     RECT  84.911 66.798 85.307 70.398 ;
     RECT  85.307 69.156 85.415 70.398 ;
     RECT  84.24 25.956 85.451 27.774 ;
     RECT  84.911 60.318 85.451 66.006 ;
     RECT  85.307 66.798 85.451 68.364 ;
     RECT  84.911 71.586 85.451 72.954 ;
     RECT  84.24 21.276 85.487 25.164 ;
     RECT  84.947 34.506 85.487 36.504 ;
     RECT  84.24 38.376 85.487 40.284 ;
     RECT  85.451 60.318 85.487 65.844 ;
     RECT  85.487 21.276 85.523 24.264 ;
     RECT  85.451 26.406 85.523 27.774 ;
     RECT  85.487 34.506 85.523 36.414 ;
     RECT  85.487 60.318 85.523 65.574 ;
     RECT  85.451 66.798 85.523 68.202 ;
     RECT  85.523 26.406 85.559 26.424 ;
     RECT  85.523 61.092 85.559 64.386 ;
     RECT  85.523 60.318 85.595 60.336 ;
     RECT  85.523 21.276 85.667 23.184 ;
     RECT  85.667 22.824 85.703 23.184 ;
     RECT  85.559 61.236 85.703 64.386 ;
     RECT  85.451 72.234 86.027 72.954 ;
     RECT  84.24 57.312 86.143 58.644 ;
     RECT  85.523 27.216 86.171 27.774 ;
     RECT  85.523 34.506 86.171 35.802 ;
     RECT  86.143 57.312 86.171 58.716 ;
     RECT  86.171 27.216 86.207 27.702 ;
     RECT  86.171 34.506 86.207 35.19 ;
     RECT  85.487 38.826 86.207 40.284 ;
     RECT  86.171 57.501 86.207 58.716 ;
     RECT  86.027 72.234 86.207 72.864 ;
     RECT  86.207 34.506 86.243 35.064 ;
     RECT  86.207 39.096 86.243 40.284 ;
     RECT  85.415 69.336 86.243 70.398 ;
     RECT  86.207 27.216 86.279 27.234 ;
     RECT  86.243 34.632 86.279 35.064 ;
     RECT  86.243 39.096 86.279 40.014 ;
     RECT  86.207 58.536 86.279 58.716 ;
     RECT  85.703 61.236 86.279 63.306 ;
     RECT  85.523 66.798 86.279 67.968 ;
     RECT  86.243 69.336 86.279 69.984 ;
     RECT  85.667 21.276 86.315 21.96 ;
     RECT  86.279 34.632 86.315 34.758 ;
     RECT  86.279 39.096 86.315 39.114 ;
     RECT  86.207 57.501 86.315 57.519 ;
     RECT  86.279 58.698 86.315 58.716 ;
     RECT  86.279 61.506 86.315 62.46 ;
     RECT  85.703 64.368 86.315 64.386 ;
     RECT  85.523 65.25 86.315 65.268 ;
     RECT  86.279 67.716 86.315 67.734 ;
     RECT  86.279 69.381 86.315 69.984 ;
     RECT  86.315 21.942 86.351 21.96 ;
     RECT  85.703 22.824 86.351 22.842 ;
     RECT  86.315 62.046 86.351 62.064 ;
     RECT  86.279 63.288 86.351 63.306 ;
     RECT  86.207 72.234 86.351 72.684 ;
     RECT  86.315 34.632 86.387 34.65 ;
     RECT  86.287 36.018 86.387 36.036 ;
     RECT  86.215 37.791 86.387 37.809 ;
     RECT  86.279 39.996 86.387 40.014 ;
     RECT  86.315 69.381 86.387 69.399 ;
     RECT  86.351 72.666 86.387 72.684 ;
    LAYER M3 ;
     RECT  73.188 2.101 73.53 2.143 ;
     RECT  67.215 2.143 67.305 2.191 ;
     RECT  72.615 2.143 73.53 2.191 ;
     RECT  6.588 2.191 6.606 2.227 ;
     RECT  63.864 2.191 64.602 2.227 ;
     RECT  66.816 2.191 67.305 2.227 ;
     RECT  71.244 2.191 71.262 2.227 ;
     RECT  63.864 2.227 65.286 2.251 ;
     RECT  18.615 2.143 18.705 2.263 ;
     RECT  63.828 2.251 65.286 2.263 ;
     RECT  66.816 2.227 67.554 2.263 ;
     RECT  68.4 2.191 68.814 2.263 ;
     RECT  11.592 2.191 11.61 2.299 ;
     RECT  13.215 2.143 13.305 2.335 ;
     RECT  14.328 2.263 14.346 2.335 ;
     RECT  66.384 2.263 67.554 2.335 ;
     RECT  70.308 2.191 70.326 2.335 ;
     RECT  71.1 2.227 71.262 2.335 ;
     RECT  7.815 2.143 7.905 2.371 ;
     RECT  10.98 2.299 11.718 2.371 ;
     RECT  13.215 2.335 14.418 2.371 ;
     RECT  61.815 2.143 61.905 2.371 ;
     RECT  63.288 2.263 65.286 2.371 ;
     RECT  66.096 2.335 67.554 2.371 ;
     RECT  68.4 2.263 68.886 2.371 ;
     RECT  69.948 2.335 70.326 2.371 ;
     RECT  71.1 2.335 71.442 2.371 ;
     RECT  72.288 2.191 73.71 2.371 ;
     RECT  2.415 2.143 2.505 2.413 ;
     RECT  24.015 2.143 24.105 2.413 ;
     RECT  29.415 2.143 29.505 2.413 ;
     RECT  34.815 2.143 34.905 2.413 ;
     RECT  40.215 2.143 40.305 2.413 ;
     RECT  45.615 2.143 45.705 2.413 ;
     RECT  51.015 2.143 51.105 2.413 ;
     RECT  56.415 2.143 56.505 2.413 ;
     RECT  78.015 2.143 78.105 2.413 ;
     RECT  83.415 2.143 83.505 2.413 ;
     RECT  9.468 2.371 9.486 2.461 ;
     RECT  10.26 2.371 11.718 2.461 ;
     RECT  12.924 2.371 14.418 2.461 ;
     RECT  16.596 2.371 16.686 2.461 ;
     RECT  17.64 2.371 17.658 2.461 ;
     RECT  18.615 2.263 18.99 2.461 ;
     RECT  40.215 2.413 40.497 2.461 ;
     RECT  56.415 2.413 56.697 2.461 ;
     RECT  63.288 2.371 65.358 2.461 ;
     RECT  66.096 2.371 68.886 2.461 ;
     RECT  7.815 2.371 8.19 2.497 ;
     RECT  39.78 2.461 41.274 2.497 ;
     RECT  53.028 2.371 53.046 2.497 ;
     RECT  59.184 2.371 59.202 2.497 ;
     RECT  60.3 2.371 60.498 2.497 ;
     RECT  5.616 2.227 6.606 2.533 ;
     RECT  16.488 2.461 17.658 2.533 ;
     RECT  39.78 2.497 42.102 2.533 ;
     RECT  52.74 2.497 53.046 2.533 ;
     RECT  54 2.497 54.018 2.533 ;
     RECT  57.708 2.497 57.726 2.533 ;
     RECT  69.804 2.371 73.782 2.533 ;
     RECT  7.815 2.497 8.586 2.569 ;
     RECT  12.816 2.461 15.066 2.569 ;
     RECT  39.708 2.533 42.102 2.569 ;
     RECT  55.368 2.371 55.386 2.569 ;
     RECT  56.124 2.461 56.697 2.569 ;
     RECT  57.708 2.533 57.942 2.569 ;
     RECT  58.68 2.497 60.498 2.569 ;
     RECT  5.616 2.533 6.678 2.605 ;
     RECT  7.452 2.569 8.586 2.605 ;
     RECT  16.02 2.533 17.658 2.605 ;
     RECT  18.615 2.461 19.422 2.605 ;
     RECT  39.708 2.569 42.75 2.605 ;
     RECT  55.368 2.569 56.718 2.605 ;
     RECT  57.708 2.569 60.498 2.605 ;
     RECT  61.815 2.371 62.406 2.605 ;
     RECT  63.288 2.461 68.886 2.605 ;
     RECT  69.804 2.533 73.962 2.605 ;
     RECT  16.02 2.605 19.422 2.633 ;
     RECT  5.616 2.605 8.586 2.641 ;
     RECT  12.636 2.569 15.066 2.641 ;
     RECT  16.308 2.633 19.422 2.641 ;
     RECT  39.528 2.605 42.75 2.641 ;
     RECT  51.015 2.413 51.297 2.641 ;
     RECT  52.74 2.533 54.018 2.641 ;
     RECT  55.26 2.605 60.498 2.641 ;
     RECT  63.288 2.605 73.962 2.641 ;
     RECT  74.88 2.371 74.898 2.641 ;
     RECT  9.468 2.461 11.718 2.725 ;
     RECT  9.468 2.725 11.79 2.731 ;
     RECT  12.636 2.641 15.534 2.731 ;
     RECT  63.288 2.641 74.898 2.731 ;
     RECT  9.468 2.731 15.534 2.759 ;
     RECT  16.308 2.641 19.818 2.759 ;
     RECT  9.468 2.759 15.39 2.765 ;
     RECT  50.796 2.641 54.018 2.767 ;
     RECT  5.616 2.641 8.73 2.839 ;
     RECT  9.468 2.765 11.538 2.839 ;
     RECT  39.456 2.641 42.75 2.839 ;
     RECT  61.308 2.605 62.406 2.861 ;
     RECT  39.42 2.839 42.75 2.875 ;
     RECT  55.152 2.641 60.498 2.875 ;
     RECT  39.348 2.875 42.75 2.911 ;
     RECT  50.688 2.767 54.018 2.911 ;
     RECT  37.764 3.001 37.782 3.037 ;
     RECT  38.844 2.911 42.75 3.037 ;
     RECT  37.764 3.037 42.75 3.073 ;
     RECT  50.688 2.911 54.234 3.109 ;
     RECT  55.152 2.875 61.074 3.109 ;
     RECT  20.7 3.073 20.718 3.145 ;
     RECT  24.015 2.413 24.297 3.145 ;
     RECT  22.536 3.073 22.554 3.181 ;
     RECT  23.832 3.145 24.297 3.181 ;
     RECT  37.008 3.109 37.026 3.181 ;
     RECT  37.764 3.073 43.65 3.181 ;
     RECT  61.815 2.861 62.406 3.181 ;
     RECT  63.288 2.731 75.222 3.181 ;
     RECT  50.688 3.109 61.074 3.271 ;
     RECT  5.616 2.839 11.538 3.299 ;
     RECT  20.7 3.145 20.934 3.307 ;
     RECT  25.884 3.109 25.902 3.307 ;
     RECT  50.4 3.271 61.074 3.343 ;
     RECT  9.468 3.299 11.538 3.371 ;
     RECT  23.832 3.181 24.714 3.379 ;
     RECT  22.32 3.181 22.554 3.403 ;
     RECT  23.508 3.379 24.714 3.403 ;
     RECT  16.38 2.759 19.818 3.407 ;
     RECT  26.856 3.271 26.874 3.415 ;
     RECT  29.415 2.413 29.697 3.415 ;
     RECT  12.312 2.765 15.39 3.437 ;
     RECT  20.7 3.307 21.33 3.437 ;
     RECT  22.32 3.403 24.714 3.451 ;
     RECT  25.704 3.307 25.902 3.451 ;
     RECT  45.615 2.413 45.897 3.451 ;
     RECT  9.828 3.371 11.538 3.541 ;
     RECT  12.312 3.437 14.382 3.541 ;
     RECT  22.248 3.451 25.974 3.541 ;
     RECT  26.82 3.415 26.874 3.541 ;
     RECT  31.284 3.451 31.302 3.541 ;
     RECT  34.815 2.413 35.097 3.541 ;
     RECT  9.828 3.541 14.382 3.569 ;
     RECT  20.7 3.437 20.898 3.569 ;
     RECT  16.38 3.407 19.638 3.605 ;
     RECT  22.248 3.541 26.01 3.605 ;
     RECT  16.38 3.605 19.602 3.613 ;
     RECT  22.32 3.605 26.01 3.613 ;
     RECT  26.82 3.541 26.91 3.613 ;
     RECT  27.648 3.451 27.666 3.613 ;
     RECT  37.008 3.181 43.758 3.613 ;
     RECT  44.892 3.451 45.897 3.613 ;
     RECT  34.776 3.541 35.097 3.649 ;
     RECT  36.972 3.613 43.758 3.649 ;
     RECT  15.408 3.613 19.602 3.677 ;
     RECT  22.32 3.613 27.666 3.685 ;
     RECT  36.756 3.649 43.758 3.685 ;
     RECT  5.616 3.299 8.73 3.721 ;
     RECT  36.756 3.685 43.866 3.721 ;
     RECT  44.676 3.613 45.897 3.721 ;
     RECT  9.828 3.569 14.238 3.839 ;
     RECT  20.736 3.569 20.898 3.839 ;
     RECT  31.212 3.541 31.302 3.839 ;
     RECT  31.284 3.839 31.302 3.875 ;
     RECT  22.32 3.685 27.846 3.911 ;
     RECT  50.292 3.343 61.074 3.955 ;
     RECT  61.815 3.181 75.834 3.955 ;
     RECT  33.984 3.721 34.002 3.979 ;
     RECT  34.74 3.649 35.097 3.979 ;
     RECT  25.596 3.911 27.846 3.983 ;
     RECT  25.668 3.983 27.846 3.991 ;
     RECT  50.292 3.955 75.834 3.991 ;
     RECT  33.984 3.979 35.097 4.081 ;
     RECT  29.088 3.415 29.697 4.153 ;
     RECT  30.528 3.919 30.546 4.153 ;
     RECT  22.32 3.911 24.642 4.205 ;
     RECT  5.544 3.721 8.73 4.225 ;
     RECT  33.984 4.081 35.658 4.225 ;
     RECT  49.284 3.721 49.302 4.225 ;
     RECT  50.256 3.991 75.834 4.225 ;
     RECT  15.408 3.677 19.422 4.253 ;
     RECT  25.668 3.991 27.99 4.253 ;
     RECT  32.04 3.991 32.058 4.261 ;
     RECT  36.684 3.721 45.897 4.261 ;
     RECT  5.544 4.225 8.946 4.301 ;
     RECT  33.984 4.225 35.946 4.351 ;
     RECT  15.408 4.253 19.098 4.379 ;
     RECT  25.74 4.253 27.99 4.415 ;
     RECT  29.088 4.153 30.546 4.415 ;
     RECT  9.828 3.839 13.554 4.423 ;
     RECT  9.72 4.423 13.554 4.459 ;
     RECT  36.684 4.261 46.098 4.459 ;
     RECT  27.072 4.415 27.99 4.487 ;
     RECT  19.836 4.459 19.962 4.531 ;
     RECT  22.32 4.205 24.57 4.531 ;
     RECT  33.732 4.351 35.946 4.531 ;
     RECT  36.684 4.459 46.17 4.531 ;
     RECT  47.232 4.495 47.25 4.531 ;
     RECT  50.04 4.225 75.834 4.531 ;
     RECT  19.836 4.531 20.142 4.621 ;
     RECT  20.952 4.459 20.97 4.621 ;
     RECT  22.248 4.531 24.57 4.621 ;
     RECT  32.04 4.261 32.274 4.651 ;
     RECT  9.504 4.459 13.554 4.693 ;
     RECT  31.392 4.651 32.274 4.693 ;
     RECT  9.504 4.693 13.59 4.729 ;
     RECT  14.4 4.315 14.49 4.729 ;
     RECT  30.744 4.693 32.274 4.729 ;
     RECT  33.732 4.531 47.25 4.729 ;
     RECT  33.66 4.729 47.25 4.765 ;
     RECT  5.544 4.301 8.766 4.793 ;
     RECT  28.44 4.651 28.602 4.793 ;
     RECT  48.6 4.225 49.302 4.801 ;
     RECT  50.04 4.531 76.194 4.801 ;
     RECT  77.04 4.531 77.058 4.801 ;
     RECT  5.544 4.793 8.334 4.829 ;
     RECT  30.744 4.729 32.778 4.829 ;
     RECT  27.072 4.487 27.126 4.919 ;
     RECT  33.66 4.765 47.682 4.919 ;
     RECT  19.836 4.621 24.57 4.927 ;
     RECT  9.504 4.729 14.49 4.942 ;
     RECT  19.836 4.927 24.786 4.999 ;
     RECT  78.015 2.413 78.297 5.035 ;
     RECT  48.564 4.801 76.194 5.071 ;
     RECT  77.04 4.801 77.13 5.071 ;
     RECT  78.015 5.035 78.39 5.071 ;
     RECT  47.664 4.919 47.682 5.083 ;
     RECT  48.564 5.071 77.13 5.083 ;
     RECT  33.66 4.919 46.926 5.099 ;
     RECT  47.664 5.083 77.13 5.117 ;
     RECT  48.096 5.117 77.13 5.161 ;
     RECT  78.015 5.071 78.462 5.161 ;
     RECT  5.544 4.829 8.298 5.179 ;
     RECT  33.66 5.099 36.054 5.189 ;
     RECT  9.504 4.942 14.31 5.197 ;
     RECT  30.744 4.829 32.634 5.197 ;
     RECT  15.444 4.379 19.098 5.233 ;
     RECT  19.836 4.999 24.966 5.233 ;
     RECT  25.74 4.415 26.298 5.233 ;
     RECT  78.015 5.161 78.75 5.233 ;
     RECT  80.1 5.161 80.118 5.233 ;
     RECT  15.444 5.233 26.298 5.305 ;
     RECT  48.096 5.161 77.274 5.305 ;
     RECT  78.015 5.233 80.118 5.305 ;
     RECT  27.108 4.919 27.126 5.341 ;
     RECT  29.415 4.415 29.898 5.341 ;
     RECT  30.708 5.197 32.634 5.341 ;
     RECT  15.156 5.305 26.298 5.459 ;
     RECT  33.984 5.189 36.054 5.459 ;
     RECT  27.108 5.341 27.882 5.575 ;
     RECT  28.656 5.341 28.674 5.575 ;
     RECT  29.415 5.341 32.634 5.611 ;
     RECT  48.096 5.305 80.406 5.611 ;
     RECT  15.156 5.459 17.298 5.639 ;
     RECT  18.072 5.459 26.298 5.701 ;
     RECT  5.004 5.179 8.298 5.707 ;
     RECT  27.108 5.575 28.674 5.707 ;
     RECT  29.415 5.611 33.174 5.707 ;
     RECT  48.096 5.611 80.55 5.773 ;
     RECT  27.108 5.707 33.174 5.873 ;
     RECT  4.464 5.707 8.298 5.881 ;
     RECT  9.324 5.197 14.31 5.881 ;
     RECT  27.108 5.873 30.474 5.881 ;
     RECT  36.792 5.099 46.926 5.881 ;
     RECT  18.072 5.701 26.334 5.971 ;
     RECT  27.072 5.881 30.474 5.971 ;
     RECT  4.464 5.881 14.31 6.035 ;
     RECT  48.096 5.773 80.73 6.035 ;
     RECT  48.564 6.035 80.73 6.043 ;
     RECT  4.608 6.035 14.31 6.151 ;
     RECT  31.212 5.873 33.174 6.151 ;
     RECT  33.984 5.459 35.622 6.151 ;
     RECT  36.504 5.881 46.926 6.235 ;
     RECT  15.192 5.639 17.298 6.349 ;
     RECT  18.072 5.971 30.474 6.349 ;
     RECT  4.608 6.151 14.418 6.523 ;
     RECT  15.192 6.349 30.474 6.523 ;
     RECT  48.564 6.043 81.414 6.583 ;
     RECT  4.608 6.523 30.474 6.809 ;
     RECT  48.564 6.583 82.134 6.845 ;
     RECT  26.964 6.809 30.474 6.961 ;
     RECT  31.212 6.151 35.622 6.961 ;
     RECT  36.504 6.235 47.466 6.961 ;
     RECT  26.964 6.961 47.466 7.051 ;
     RECT  26.964 7.051 47.502 7.195 ;
     RECT  26.964 7.195 48.042 7.349 ;
     RECT  48.996 6.845 82.134 7.493 ;
     RECT  26.964 7.349 35.622 7.619 ;
     RECT  60.228 7.493 82.134 7.663 ;
     RECT  4.608 6.809 26.19 7.861 ;
     RECT  26.964 7.619 35.514 7.861 ;
     RECT  4.608 7.861 35.514 7.867 ;
     RECT  4.464 7.867 35.514 7.925 ;
     RECT  60.228 7.663 82.206 7.963 ;
     RECT  36.576 7.349 48.042 8.041 ;
     RECT  48.996 7.493 59.238 8.131 ;
     RECT  60.228 7.963 82.458 8.275 ;
     RECT  36.576 8.041 48.078 8.311 ;
     RECT  48.924 8.131 59.238 8.311 ;
     RECT  60.192 8.275 82.458 8.311 ;
     RECT  36.576 8.311 82.458 8.339 ;
     RECT  4.608 7.925 35.514 8.401 ;
     RECT  36.576 8.339 47.826 8.401 ;
     RECT  48.6 8.339 82.458 8.429 ;
     RECT  83.415 2.413 83.697 8.581 ;
     RECT  48.816 8.429 82.458 8.671 ;
     RECT  48.816 8.671 82.494 8.707 ;
     RECT  48.816 8.707 82.602 8.815 ;
     RECT  83.376 8.581 83.697 8.815 ;
     RECT  4.608 8.401 47.826 8.971 ;
     RECT  3.816 8.971 47.826 9.011 ;
     RECT  3.852 9.011 47.826 9.067 ;
     RECT  3.852 9.067 48.042 9.113 ;
     RECT  48.816 8.815 83.697 9.391 ;
     RECT  48.348 9.391 83.697 9.625 ;
     RECT  3.852 9.113 47.502 9.779 ;
     RECT  11.124 9.779 47.502 9.859 ;
     RECT  48.348 9.625 83.754 9.859 ;
     RECT  11.124 9.859 83.754 10.049 ;
     RECT  3.852 9.779 10.242 10.157 ;
     RECT  3.852 10.157 9.702 10.319 ;
     RECT  48.24 10.049 83.754 10.471 ;
     RECT  11.124 10.049 47.286 10.831 ;
     RECT  10.512 10.831 47.286 10.903 ;
     RECT  10.512 10.903 47.322 11.011 ;
     RECT  48.24 10.471 83.826 11.237 ;
     RECT  3.852 10.319 9.63 11.281 ;
     RECT  10.512 11.011 47.502 11.281 ;
     RECT  48.24 11.237 83.697 11.281 ;
     RECT  10.512 11.281 83.697 11.471 ;
     RECT  3.78 11.281 9.63 11.669 ;
     RECT  3.852 11.669 9.63 11.785 ;
     RECT  10.512 11.471 36.99 11.785 ;
     RECT  3.852 11.785 36.99 12.325 ;
     RECT  37.764 11.471 83.697 12.325 ;
     RECT  3.852 12.325 83.697 12.749 ;
     RECT  38.556 12.749 83.697 12.901 ;
     RECT  38.556 12.901 83.79 13.019 ;
     RECT  38.592 13.019 83.79 13.091 ;
     RECT  3.852 12.749 37.602 13.289 ;
     RECT  3.852 13.289 37.494 13.703 ;
     RECT  28.62 13.703 37.494 14.215 ;
     RECT  38.592 13.091 83.697 14.215 ;
     RECT  3.852 13.703 27.846 14.881 ;
     RECT  3.816 14.881 27.846 14.953 ;
     RECT  3.78 14.953 27.846 15.061 ;
     RECT  28.62 14.215 83.697 15.061 ;
     RECT  3.78 15.061 83.697 15.493 ;
     RECT  3.744 15.493 83.697 16.141 ;
     RECT  3.744 16.141 83.79 16.267 ;
     RECT  3.744 16.267 83.934 16.397 ;
     RECT  3.744 16.397 74.862 16.529 ;
     RECT  75.672 16.397 83.934 16.799 ;
     RECT  75.672 16.799 83.79 16.835 ;
     RECT  3.744 16.529 74.718 17.117 ;
     RECT  75.672 16.835 83.697 17.491 ;
     RECT  75.456 17.491 83.697 17.753 ;
     RECT  3.744 17.117 74.682 17.851 ;
     RECT  75.456 17.753 81.414 17.851 ;
     RECT  82.152 17.753 83.697 18.031 ;
     RECT  82.152 18.031 83.754 18.265 ;
     RECT  3.672 17.851 81.414 18.499 ;
     RECT  82.152 18.265 83.934 18.499 ;
     RECT  3.672 18.499 83.934 18.571 ;
     RECT  2.415 2.413 2.697 18.697 ;
     RECT  2.415 18.697 2.862 18.769 ;
     RECT  3.672 18.571 84.114 18.769 ;
     RECT  2.415 18.769 84.114 18.797 ;
     RECT  2.415 18.797 83.697 19.651 ;
     RECT  2.415 19.651 83.79 19.741 ;
     RECT  2.415 19.741 83.934 19.885 ;
     RECT  2.304 19.885 83.934 20.039 ;
     RECT  0.108 19.615 0.126 20.237 ;
     RECT  2.304 20.039 83.79 20.309 ;
     RECT  2.304 20.309 83.697 21.067 ;
     RECT  2.268 21.067 83.697 21.235 ;
     RECT  2.268 21.235 83.754 21.299 ;
     RECT  2.268 21.299 17.37 21.389 ;
     RECT  86.292 21.271 86.31 21.469 ;
     RECT  18.108 21.299 83.754 21.505 ;
     RECT  85.608 21.469 86.31 21.541 ;
     RECT  2.268 21.389 17.334 21.659 ;
     RECT  18.108 21.505 83.97 21.695 ;
     RECT  2.268 21.659 17.226 21.803 ;
     RECT  84.888 21.541 86.31 21.937 ;
     RECT  2.268 21.803 17.19 21.965 ;
     RECT  18.144 21.695 83.97 22.081 ;
     RECT  84.888 21.937 86.346 22.081 ;
     RECT  2.304 21.965 17.19 22.505 ;
     RECT  2.34 22.505 17.19 22.613 ;
     RECT  18.144 22.081 86.346 22.621 ;
     RECT  17.532 22.621 86.346 22.847 ;
     RECT  2.34 22.613 16.722 23.009 ;
     RECT  2.415 23.009 16.722 23.165 ;
     RECT  2.415 23.165 2.862 23.189 ;
     RECT  3.672 23.165 16.722 23.279 ;
     RECT  17.532 22.847 86.31 23.309 ;
     RECT  4.104 23.279 16.722 23.315 ;
     RECT  4.104 23.315 14.346 23.387 ;
     RECT  15.192 23.315 16.722 23.665 ;
     RECT  17.532 23.309 86.274 23.665 ;
     RECT  15.192 23.665 86.274 23.933 ;
     RECT  15.552 23.933 86.274 23.981 ;
     RECT  15.552 23.981 85.698 24.077 ;
     RECT  4.104 23.387 14.13 24.241 ;
     RECT  15.552 24.077 85.518 24.269 ;
     RECT  4.104 24.241 14.238 24.331 ;
     RECT  4.104 24.331 14.634 24.475 ;
     RECT  3.888 24.475 14.634 24.673 ;
     RECT  3.888 24.673 14.814 24.781 ;
     RECT  15.552 24.269 83.934 24.781 ;
     RECT  3.888 24.781 83.934 25.099 ;
     RECT  84.888 24.269 85.518 25.099 ;
     RECT  3.888 25.099 85.518 25.483 ;
     RECT  86.256 25.387 86.274 25.483 ;
     RECT  2.415 23.189 2.697 26.491 ;
     RECT  3.888 25.483 86.274 26.491 ;
     RECT  2.415 26.491 86.274 26.627 ;
     RECT  2.415 26.627 85.374 26.699 ;
     RECT  84.888 26.699 85.374 27.059 ;
     RECT  2.415 26.699 84.114 27.095 ;
     RECT  0.504 27.067 0.522 27.139 ;
     RECT  86.148 26.627 86.274 27.239 ;
     RECT  9.756 27.095 84.114 27.329 ;
     RECT  0.504 27.139 0.558 27.337 ;
     RECT  39.744 27.329 71.118 27.365 ;
     RECT  71.964 27.329 83.898 27.365 ;
     RECT  71.964 27.365 83.79 27.509 ;
     RECT  0.108 27.337 0.558 27.533 ;
     RECT  84.888 27.059 84.906 27.599 ;
     RECT  0.108 27.533 0.522 27.629 ;
     RECT  2.415 27.095 9.018 27.691 ;
     RECT  86.148 27.239 86.202 27.707 ;
     RECT  86.148 27.707 86.166 27.779 ;
     RECT  0.504 27.629 0.522 27.821 ;
     RECT  2.412 27.691 9.018 27.841 ;
     RECT  39.744 27.365 71.082 27.869 ;
     RECT  2.412 27.841 9.09 27.979 ;
     RECT  2.34 27.979 9.09 28.075 ;
     RECT  2.304 28.075 9.09 28.255 ;
     RECT  9.828 27.329 38.862 28.255 ;
     RECT  71.964 27.509 83.754 28.255 ;
     RECT  71.856 28.255 83.754 28.291 ;
     RECT  2.304 28.255 38.862 28.552 ;
     RECT  2.268 28.552 38.862 28.561 ;
     RECT  39.744 27.869 46.998 28.561 ;
     RECT  2.268 28.561 46.998 28.651 ;
     RECT  47.736 27.869 71.082 28.651 ;
     RECT  71.856 28.291 83.898 28.651 ;
     RECT  2.268 28.651 83.898 28.787 ;
     RECT  2.268 28.787 83.862 28.829 ;
     RECT  2.268 28.829 81.666 28.985 ;
     RECT  2.304 28.985 81.666 29.069 ;
     RECT  2.304 29.069 81.594 29.525 ;
     RECT  12.744 29.525 81.594 29.597 ;
     RECT  12.924 29.597 81.594 29.633 ;
     RECT  2.304 29.525 11.826 29.707 ;
     RECT  13.104 29.633 81.594 29.795 ;
     RECT  13.176 29.795 81.594 29.875 ;
     RECT  82.404 28.829 83.862 29.875 ;
     RECT  13.176 29.875 83.862 29.939 ;
     RECT  0.144 29.899 0.162 29.995 ;
     RECT  0.144 29.995 0.234 30.077 ;
     RECT  2.268 29.707 11.826 30.283 ;
     RECT  13.176 29.939 83.697 30.443 ;
     RECT  2.232 30.283 11.826 30.451 ;
     RECT  13.176 30.443 71.55 30.649 ;
     RECT  2.232 30.451 12.294 30.685 ;
     RECT  2.232 30.685 12.33 30.721 ;
     RECT  13.104 30.649 71.55 30.721 ;
     RECT  2.232 30.721 71.55 30.875 ;
     RECT  72.468 30.443 83.697 30.883 ;
     RECT  2.268 30.875 71.55 30.947 ;
     RECT  2.34 30.947 71.55 31.145 ;
     RECT  2.376 31.145 71.55 31.253 ;
     RECT  2.376 31.253 10.638 31.379 ;
     RECT  0.216 30.077 0.234 31.415 ;
     RECT  11.628 31.253 71.55 31.451 ;
     RECT  72.468 30.883 83.754 31.459 ;
     RECT  72.36 31.459 83.754 31.495 ;
     RECT  72.36 31.495 83.79 31.531 ;
     RECT  11.736 31.451 71.55 31.621 ;
     RECT  72.288 31.531 83.79 31.621 ;
     RECT  11.736 31.621 83.79 31.721 ;
     RECT  11.808 31.721 83.79 31.955 ;
     RECT  11.952 31.955 83.79 32.071 ;
     RECT  2.415 31.379 10.494 32.341 ;
     RECT  11.952 32.071 83.862 32.341 ;
     RECT  11.952 32.341 83.97 32.459 ;
     RECT  2.415 32.341 10.782 32.467 ;
     RECT  2.415 32.467 10.854 32.491 ;
     RECT  11.952 32.459 83.862 32.729 ;
     RECT  2.415 32.491 10.962 32.881 ;
     RECT  11.952 32.729 83.697 32.881 ;
     RECT  2.415 32.881 11.07 33.043 ;
     RECT  11.844 32.881 83.697 33.043 ;
     RECT  2.415 33.043 83.697 33.377 ;
     RECT  53.496 33.377 83.697 33.719 ;
     RECT  53.496 33.719 54.738 33.809 ;
     RECT  55.512 33.719 83.697 33.925 ;
     RECT  2.415 33.377 52.506 33.953 ;
     RECT  55.512 33.925 83.934 33.961 ;
     RECT  84.96 33.583 84.978 34.051 ;
     RECT  11.88 33.953 52.506 34.079 ;
     RECT  11.988 34.079 52.506 34.159 ;
     RECT  11.988 34.159 52.542 34.195 ;
     RECT  53.496 33.809 54.594 34.195 ;
     RECT  2.415 33.953 10.962 34.349 ;
     RECT  84.924 34.051 84.978 34.357 ;
     RECT  55.512 33.961 84.114 34.429 ;
     RECT  84.888 34.357 84.978 34.429 ;
     RECT  86.22 34.501 86.238 34.627 ;
     RECT  11.988 34.195 54.594 34.699 ;
     RECT  55.512 34.429 84.978 34.699 ;
     RECT  11.988 34.699 84.978 35.041 ;
     RECT  86.22 34.627 86.382 35.167 ;
     RECT  11.952 35.041 84.978 35.239 ;
     RECT  86.184 35.167 86.382 35.239 ;
     RECT  2.415 34.349 10.458 35.275 ;
     RECT  11.952 35.239 86.382 35.275 ;
     RECT  2.415 35.275 86.382 35.581 ;
     RECT  2.304 35.581 86.382 35.597 ;
     RECT  2.304 35.597 84.438 35.981 ;
     RECT  85.464 35.597 86.382 36.041 ;
     RECT  85.464 36.041 86.31 36.077 ;
     RECT  2.304 35.981 84.042 36.239 ;
     RECT  11.448 36.239 84.042 36.383 ;
     RECT  85.464 36.077 86.274 36.461 ;
     RECT  2.304 36.239 10.53 36.509 ;
     RECT  85.464 36.461 86.202 36.557 ;
     RECT  2.304 36.509 10.458 36.653 ;
     RECT  85.464 36.557 86.166 36.653 ;
     RECT  85.464 36.653 86.13 36.749 ;
     RECT  1.152 35.707 1.17 36.787 ;
     RECT  85.464 36.749 85.59 36.845 ;
     RECT  0.108 36.247 0.126 36.895 ;
     RECT  1.152 36.787 1.206 36.923 ;
     RECT  1.152 36.923 1.17 37.049 ;
     RECT  11.664 36.383 84.042 37.099 ;
     RECT  11.664 37.099 84.366 37.195 ;
     RECT  85.464 36.845 85.518 37.195 ;
     RECT  11.664 37.195 85.518 37.327 ;
     RECT  0.108 36.895 0.198 37.363 ;
     RECT  2.304 36.653 10.278 37.399 ;
     RECT  11.448 37.327 85.518 37.399 ;
     RECT  0.108 37.363 0.234 37.561 ;
     RECT  86.292 37.579 86.31 37.675 ;
     RECT  0.108 37.561 0.306 37.709 ;
     RECT  2.304 37.399 85.518 37.771 ;
     RECT  86.256 37.675 86.31 37.771 ;
     RECT  2.304 37.771 86.31 37.786 ;
     RECT  2.304 37.786 86.382 38.137 ;
     RECT  2.268 38.137 86.382 38.309 ;
     RECT  0.144 37.709 0.306 38.479 ;
     RECT  2.268 38.309 16.65 38.713 ;
     RECT  0.108 38.479 0.306 38.923 ;
     RECT  17.46 38.309 86.382 39.011 ;
     RECT  0.108 38.923 0.342 39.053 ;
     RECT  17.46 39.011 83.898 39.083 ;
     RECT  2.232 38.713 16.65 39.181 ;
     RECT  84.888 39.011 86.382 39.209 ;
     RECT  84.888 39.209 84.906 39.479 ;
     RECT  1.26 39.403 1.278 39.499 ;
     RECT  1.152 39.499 1.278 39.533 ;
     RECT  1.152 39.533 1.17 39.677 ;
     RECT  0.108 39.053 0.126 39.787 ;
     RECT  17.676 39.083 83.898 39.821 ;
     RECT  31.248 39.821 83.898 39.929 ;
     RECT  2.232 39.181 16.794 40.019 ;
     RECT  86.112 39.209 86.382 40.019 ;
     RECT  14.328 40.019 16.794 40.027 ;
     RECT  17.676 39.821 30.474 40.027 ;
     RECT  31.248 39.929 61.002 40.055 ;
     RECT  86.112 40.019 86.238 40.127 ;
     RECT  86.22 40.127 86.238 40.289 ;
     RECT  2.232 40.019 13.497 40.493 ;
     RECT  2.304 40.493 13.497 40.595 ;
     RECT  14.328 40.027 30.474 40.639 ;
     RECT  31.248 40.055 60.966 40.639 ;
     RECT  61.815 39.929 83.898 40.675 ;
     RECT  14.328 40.639 60.966 40.801 ;
     RECT  61.815 40.675 84.114 40.829 ;
     RECT  2.34 40.595 13.497 40.837 ;
     RECT  14.328 40.801 61.074 40.837 ;
     RECT  2.34 40.837 61.074 40.909 ;
     RECT  61.815 40.829 83.934 40.909 ;
     RECT  2.34 40.909 83.934 40.973 ;
     RECT  21.42 40.973 83.934 41.009 ;
     RECT  0.108 39.787 0.558 41.135 ;
     RECT  2.34 40.973 20.502 41.341 ;
     RECT  43.884 41.009 83.934 41.477 ;
     RECT  21.42 41.009 42.894 41.755 ;
     RECT  43.884 41.477 83.898 41.755 ;
     RECT  21.42 41.755 83.898 41.989 ;
     RECT  2.304 41.341 20.502 42.025 ;
     RECT  21.276 41.989 83.898 42.025 ;
     RECT  2.304 42.025 83.898 42.295 ;
     RECT  2.304 42.295 84.114 42.449 ;
     RECT  2.304 42.449 64.998 42.719 ;
     RECT  2.304 42.719 20.142 42.755 ;
     RECT  0.108 41.135 0.126 42.827 ;
     RECT  65.808 42.449 83.826 42.989 ;
     RECT  20.88 42.719 64.998 43.097 ;
     RECT  2.304 42.755 19.854 43.181 ;
     RECT  21.78 43.097 64.998 43.231 ;
     RECT  65.808 42.989 83.79 43.231 ;
     RECT  2.304 43.181 14.67 43.259 ;
     RECT  21.78 43.231 83.79 43.295 ;
     RECT  2.304 43.259 14.49 43.529 ;
     RECT  71.892 43.295 83.79 43.637 ;
     RECT  15.552 43.181 19.854 43.807 ;
     RECT  20.88 43.097 20.898 43.807 ;
     RECT  75.528 43.637 83.79 43.843 ;
     RECT  15.552 43.807 20.898 43.853 ;
     RECT  75.528 43.843 83.826 43.915 ;
     RECT  0.108 43.807 0.126 43.949 ;
     RECT  75.528 43.915 84.042 44.069 ;
     RECT  21.78 43.295 71.154 44.149 ;
     RECT  71.892 43.637 74.754 44.149 ;
     RECT  18.615 43.853 20.898 44.203 ;
     RECT  21.78 44.149 74.754 44.203 ;
     RECT  2.304 43.529 14.454 44.299 ;
     RECT  18.615 44.203 74.754 44.381 ;
     RECT  15.552 43.853 17.766 44.419 ;
     RECT  50.688 44.381 74.754 44.419 ;
     RECT  75.528 44.069 83.826 44.419 ;
     RECT  2.268 44.299 14.454 44.617 ;
     RECT  15.3 44.419 17.766 44.617 ;
     RECT  2.268 44.617 17.766 44.879 ;
     RECT  2.268 44.879 14.13 44.951 ;
     RECT  0.54 44.923 0.558 44.995 ;
     RECT  14.94 44.879 17.766 45.023 ;
     RECT  18.615 44.381 49.914 45.023 ;
     RECT  50.688 44.419 83.826 45.149 ;
     RECT  0.108 44.995 0.558 45.293 ;
     RECT  33.372 45.023 49.914 45.301 ;
     RECT  50.688 45.149 83.754 45.301 ;
     RECT  12.24 44.951 14.13 45.455 ;
     RECT  18.615 45.023 32.598 45.463 ;
     RECT  17.352 45.023 17.766 45.535 ;
     RECT  18.504 45.463 32.598 45.535 ;
     RECT  0.18 45.293 0.558 45.581 ;
     RECT  33.372 45.301 83.754 45.689 ;
     RECT  2.268 44.951 11.394 45.697 ;
     RECT  2.268 45.697 11.682 45.724 ;
     RECT  12.528 45.455 14.13 45.769 ;
     RECT  14.94 45.023 16.506 45.769 ;
     RECT  17.352 45.535 32.598 45.841 ;
     RECT  33.372 45.689 83.697 45.841 ;
     RECT  0.18 45.581 0.198 46.027 ;
     RECT  12.528 45.769 16.506 46.111 ;
     RECT  12.528 46.111 16.542 46.265 ;
     RECT  12.528 46.265 16.326 46.373 ;
     RECT  2.232 45.724 11.682 46.381 ;
     RECT  12.528 46.373 14.418 46.381 ;
     RECT  2.232 46.381 14.418 46.571 ;
     RECT  0.108 46.027 0.198 46.603 ;
     RECT  0.108 46.603 0.846 46.741 ;
     RECT  0.108 46.741 1.17 46.769 ;
     RECT  2.268 46.571 14.418 46.805 ;
     RECT  17.352 45.841 83.697 46.849 ;
     RECT  17.352 46.849 83.754 47.011 ;
     RECT  2.304 46.805 14.418 47.075 ;
     RECT  2.34 47.075 14.418 47.191 ;
     RECT  15.3 46.373 16.326 47.191 ;
     RECT  2.34 47.191 16.326 47.345 ;
     RECT  17.208 47.011 83.754 47.461 ;
     RECT  2.376 47.345 16.326 47.615 ;
     RECT  12.276 47.615 16.326 47.731 ;
     RECT  17.136 47.461 83.79 47.731 ;
     RECT  12.276 47.731 83.79 47.759 ;
     RECT  12.276 47.759 20.682 47.849 ;
     RECT  12.276 47.849 17.226 47.891 ;
     RECT  0.828 46.769 1.17 48.397 ;
     RECT  2.376 47.615 11.466 48.469 ;
     RECT  12.276 47.891 17.118 48.469 ;
     RECT  2.376 48.469 17.118 48.541 ;
     RECT  18.036 47.849 20.682 48.541 ;
     RECT  21.564 47.759 83.79 48.541 ;
     RECT  0.576 48.397 1.17 48.667 ;
     RECT  2.34 48.541 17.118 48.811 ;
     RECT  18.036 48.541 83.79 48.811 ;
     RECT  0.18 48.667 1.17 48.965 ;
     RECT  0.18 48.965 1.134 49.477 ;
     RECT  0.108 49.477 1.134 49.505 ;
     RECT  2.304 48.811 83.79 49.613 ;
     RECT  0.108 49.505 0.558 49.805 ;
     RECT  12.6 49.613 83.79 49.811 ;
     RECT  12.6 49.811 83.697 50.045 ;
     RECT  22.572 50.045 83.697 50.081 ;
     RECT  2.304 49.613 11.682 50.251 ;
     RECT  22.68 50.081 83.697 50.423 ;
     RECT  12.6 50.045 21.798 50.431 ;
     RECT  2.268 50.251 11.682 50.521 ;
     RECT  12.564 50.431 21.798 50.521 ;
     RECT  23.508 50.423 83.697 50.621 ;
     RECT  23.832 50.621 83.697 50.657 ;
     RECT  0.108 49.805 0.522 50.665 ;
     RECT  2.268 50.521 21.798 50.827 ;
     RECT  2.196 50.827 21.798 50.864 ;
     RECT  0.108 50.665 0.558 51.149 ;
     RECT  24.015 50.657 83.697 51.233 ;
     RECT  2.268 50.864 21.798 51.331 ;
     RECT  22.572 50.971 22.662 51.331 ;
     RECT  2.268 51.331 22.662 51.403 ;
     RECT  24.015 51.233 27.486 51.403 ;
     RECT  23.976 51.403 27.486 51.451 ;
     RECT  2.268 51.403 22.734 51.475 ;
     RECT  23.904 51.451 27.486 51.475 ;
     RECT  2.268 51.475 27.486 51.595 ;
     RECT  1.98 51.595 27.486 51.629 ;
     RECT  1.98 51.629 26.694 51.773 ;
     RECT  27.468 51.629 27.486 51.809 ;
     RECT  28.296 51.233 83.697 51.899 ;
     RECT  28.548 51.899 83.697 51.935 ;
     RECT  0.108 51.149 0.342 51.979 ;
     RECT  35.928 51.935 83.697 52.169 ;
     RECT  27.504 52.141 27.522 52.285 ;
     RECT  2.232 51.773 26.694 52.313 ;
     RECT  36 52.169 83.697 52.321 ;
     RECT  27.504 52.285 27.666 52.439 ;
     RECT  0.108 51.979 0.558 52.547 ;
     RECT  2.232 52.313 19.854 52.555 ;
     RECT  20.808 52.313 26.694 52.591 ;
     RECT  0.144 52.547 0.558 52.685 ;
     RECT  27.576 52.439 27.594 52.733 ;
     RECT  28.548 51.935 35.19 52.795 ;
     RECT  20.808 52.591 26.802 52.979 ;
     RECT  36 52.321 83.826 52.987 ;
     RECT  20.808 52.979 26.694 53.015 ;
     RECT  28.548 52.795 35.226 53.249 ;
     RECT  33.66 53.249 35.226 53.321 ;
     RECT  28.548 53.249 32.814 53.365 ;
     RECT  1.728 52.555 19.854 53.519 ;
     RECT  18.18 53.519 19.854 53.527 ;
     RECT  28.224 53.365 32.814 53.527 ;
     RECT  21.132 53.015 26.694 53.555 ;
     RECT  27.972 53.527 32.814 53.563 ;
     RECT  18.18 53.527 20.034 53.591 ;
     RECT  21.132 53.555 24.354 53.627 ;
     RECT  27.756 53.563 32.814 53.635 ;
     RECT  27.684 53.635 32.814 53.671 ;
     RECT  25.128 53.555 26.694 53.761 ;
     RECT  27.576 53.671 32.814 53.761 ;
     RECT  1.728 53.519 17.406 53.825 ;
     RECT  33.696 53.321 35.226 53.833 ;
     RECT  36 52.987 84.114 53.833 ;
     RECT  21.132 53.627 24.318 53.905 ;
     RECT  2.304 53.825 17.406 53.969 ;
     RECT  0.144 52.685 0.162 54.095 ;
     RECT  18.288 53.591 20.034 54.095 ;
     RECT  21.096 53.905 24.318 54.103 ;
     RECT  25.128 53.761 32.814 54.211 ;
     RECT  33.696 53.833 84.114 54.211 ;
     RECT  25.128 54.211 84.114 54.301 ;
     RECT  2.304 53.969 16.362 54.329 ;
     RECT  25.056 54.301 84.114 54.329 ;
     RECT  17.244 53.969 17.406 54.409 ;
     RECT  18.288 54.095 19.386 54.409 ;
     RECT  20.304 54.211 20.322 54.445 ;
     RECT  21.06 54.103 24.318 54.445 ;
     RECT  17.244 54.409 19.386 54.671 ;
     RECT  20.304 54.445 24.318 54.715 ;
     RECT  25.056 54.329 25.182 54.715 ;
     RECT  12.492 54.329 16.362 54.841 ;
     RECT  17.28 54.671 19.386 54.949 ;
     RECT  20.304 54.715 25.182 54.949 ;
     RECT  2.304 54.329 11.538 54.985 ;
     RECT  17.28 54.949 25.182 55.099 ;
     RECT  25.992 54.329 84.114 55.099 ;
     RECT  2.268 54.985 11.538 55.111 ;
     RECT  12.492 54.841 16.434 55.111 ;
     RECT  17.28 55.099 84.114 55.139 ;
     RECT  2.268 55.111 16.434 55.181 ;
     RECT  2.304 55.181 16.434 55.489 ;
     RECT  2.304 55.489 16.506 55.525 ;
     RECT  17.28 55.139 35.19 55.525 ;
     RECT  2.304 55.525 35.19 55.589 ;
     RECT  20.052 55.589 35.19 55.679 ;
     RECT  36 55.139 84.114 55.949 ;
     RECT  20.052 55.679 35.097 56.219 ;
     RECT  2.304 55.589 19.062 56.497 ;
     RECT  20.052 56.219 32.742 56.497 ;
     RECT  36 55.949 84.078 57.109 ;
     RECT  36 57.109 84.222 57.145 ;
     RECT  35.856 57.145 84.222 57.299 ;
     RECT  2.304 56.497 32.742 57.307 ;
     RECT  33.48 56.219 35.097 57.307 ;
     RECT  86.148 57.307 86.166 57.379 ;
     RECT  36 57.299 84.222 57.415 ;
     RECT  2.304 57.307 35.097 57.451 ;
     RECT  36 57.415 84.366 57.451 ;
     RECT  85.5 57.379 86.166 57.496 ;
     RECT  2.304 57.451 35.226 58.261 ;
     RECT  36 57.451 84.402 58.261 ;
     RECT  2.304 58.261 84.402 58.349 ;
     RECT  85.5 57.496 86.31 58.541 ;
     RECT  2.304 58.349 84.222 58.685 ;
     RECT  85.572 58.541 86.31 58.733 ;
     RECT  2.304 58.685 16.758 58.829 ;
     RECT  85.608 58.733 86.31 58.829 ;
     RECT  85.68 58.829 86.31 58.925 ;
     RECT  85.68 58.925 86.274 59.021 ;
     RECT  86.184 59.021 86.274 59.117 ;
     RECT  86.184 59.117 86.238 59.213 ;
     RECT  86.184 59.213 86.202 59.309 ;
     RECT  17.568 58.685 84.222 59.371 ;
     RECT  2.304 58.829 13.986 59.611 ;
     RECT  14.796 58.829 16.758 59.611 ;
     RECT  2.304 59.611 16.758 59.737 ;
     RECT  17.568 59.371 84.87 59.737 ;
     RECT  2.304 59.737 84.87 59.909 ;
     RECT  2.376 59.909 84.87 60.035 ;
     RECT  2.415 60.035 84.87 60.313 ;
     RECT  2.415 60.313 85.59 61.231 ;
     RECT  2.415 61.231 86.274 61.501 ;
     RECT  2.415 61.501 86.31 62.041 ;
     RECT  2.415 62.041 86.346 63.311 ;
     RECT  2.415 63.311 86.274 63.917 ;
     RECT  85.464 63.917 86.274 64.202 ;
     RECT  85.5 64.202 86.274 64.363 ;
     RECT  2.415 63.917 84.69 64.493 ;
     RECT  85.5 64.363 86.31 65.035 ;
     RECT  85.464 65.035 86.31 65.227 ;
     RECT  85.428 65.227 86.31 65.453 ;
     RECT  2.415 64.493 84.654 65.543 ;
     RECT  85.428 65.453 86.274 65.837 ;
     RECT  85.428 65.837 85.482 65.849 ;
     RECT  26.928 65.543 84.654 66.011 ;
     RECT  85.428 65.849 85.446 66.011 ;
     RECT  2.415 65.543 26.19 66.245 ;
     RECT  39.276 66.011 84.654 66.283 ;
     RECT  10.944 66.245 26.19 66.289 ;
     RECT  26.928 66.011 38.466 66.289 ;
     RECT  86.22 65.837 86.274 66.365 ;
     RECT  39.276 66.283 85.302 66.413 ;
     RECT  86.256 66.365 86.274 66.571 ;
     RECT  10.944 66.289 38.466 66.757 ;
     RECT  39.276 66.413 84.222 66.757 ;
     RECT  85.176 66.413 85.302 66.763 ;
     RECT  2.415 66.245 10.206 67.019 ;
     RECT  2.415 67.019 9.018 67.027 ;
     RECT  10.944 66.757 84.222 67.147 ;
     RECT  9.972 67.019 10.206 67.171 ;
     RECT  10.944 67.147 84.366 67.171 ;
     RECT  85.176 66.763 85.482 67.339 ;
     RECT  85.176 67.339 85.518 67.405 ;
     RECT  86.256 66.571 86.31 67.405 ;
     RECT  2.376 67.027 9.018 67.801 ;
     RECT  9.972 67.171 84.366 67.801 ;
     RECT  2.376 67.801 84.366 67.819 ;
     RECT  85.176 67.405 86.31 67.819 ;
     RECT  2.376 67.819 86.31 67.949 ;
     RECT  2.376 67.949 85.518 68.525 ;
     RECT  86.256 67.949 86.31 68.971 ;
     RECT  2.376 68.525 85.482 69.355 ;
     RECT  86.22 68.971 86.31 69.355 ;
     RECT  2.376 69.355 86.31 69.376 ;
     RECT  2.376 69.376 86.382 71.879 ;
     RECT  2.376 71.879 85.266 71.987 ;
     RECT  2.376 71.987 84.654 72.455 ;
     RECT  2.415 72.455 84.654 72.527 ;
     RECT  86.004 71.879 86.382 72.689 ;
     RECT  86.004 72.689 86.202 72.869 ;
     RECT  86.004 72.869 86.022 72.959 ;
     RECT  2.415 72.527 84.222 73.535 ;
     RECT  2.415 73.535 8.586 74.039 ;
     RECT  2.415 74.039 8.514 74.075 ;
     RECT  2.415 74.075 8.406 74.309 ;
     RECT  9.324 73.535 84.222 74.489 ;
     RECT  3.492 74.309 8.406 74.849 ;
     RECT  4.284 74.849 8.406 74.893 ;
     RECT  9.324 74.489 83.934 74.893 ;
     RECT  4.284 74.893 8.55 74.993 ;
     RECT  9.288 74.893 83.934 75.119 ;
     RECT  9.72 75.119 83.934 75.227 ;
     RECT  3.492 74.849 3.51 75.245 ;
     RECT  9.792 75.227 83.934 75.497 ;
     RECT  4.284 74.993 8.406 75.533 ;
     RECT  4.896 75.533 8.406 75.965 ;
     RECT  9.792 75.497 83.754 76.045 ;
     RECT  9.72 76.045 83.754 76.081 ;
     RECT  5.328 75.965 8.406 76.235 ;
     RECT  9.324 76.081 83.754 76.235 ;
     RECT  5.616 76.235 8.406 76.411 ;
     RECT  9.324 76.235 54.99 76.505 ;
     RECT  5.616 76.411 8.586 76.775 ;
     RECT  9.36 76.505 54.99 77.125 ;
     RECT  5.616 76.775 8.442 77.153 ;
     RECT  9.36 77.125 55.134 77.161 ;
     RECT  55.872 76.235 83.754 77.161 ;
     RECT  9.36 77.161 83.754 77.279 ;
     RECT  10.116 77.279 83.754 77.315 ;
     RECT  10.224 77.315 83.754 77.387 ;
     RECT  6.192 77.153 8.442 77.515 ;
     RECT  9.36 77.279 9.378 77.515 ;
     RECT  6.192 77.515 9.378 77.549 ;
     RECT  6.516 77.549 9.378 78.089 ;
     RECT  7.524 78.089 9.378 78.133 ;
     RECT  10.224 77.387 83.697 78.133 ;
     RECT  6.624 78.089 6.786 78.359 ;
     RECT  7.524 78.133 83.697 78.629 ;
     RECT  6.624 78.359 6.642 78.653 ;
     RECT  11.592 78.629 83.697 78.665 ;
     RECT  7.56 78.629 10.818 78.809 ;
     RECT  7.596 78.809 10.818 78.935 ;
     RECT  7.596 78.935 9.486 78.971 ;
     RECT  10.224 78.935 10.818 79.169 ;
     RECT  7.596 78.971 9.342 79.229 ;
     RECT  7.815 79.229 8.802 79.241 ;
     RECT  10.224 79.169 10.53 79.313 ;
     RECT  7.815 79.241 8.586 79.439 ;
     RECT  10.224 79.313 10.242 79.439 ;
     RECT  11.808 78.665 83.697 79.439 ;
     RECT  7.815 79.439 8.37 79.475 ;
     RECT  11.556 79.447 11.754 80.131 ;
     RECT  11.016 80.131 11.754 80.221 ;
     RECT  12.528 79.439 83.697 80.221 ;
     RECT  11.016 80.221 83.697 81.403 ;
     RECT  8.892 81.445 8.91 81.715 ;
     RECT  7.815 79.475 8.097 82.021 ;
     RECT  8.892 81.715 9.594 82.021 ;
     RECT  10.656 81.403 83.697 82.021 ;
     RECT  7.815 82.021 84.114 82.061 ;
     RECT  8.892 82.061 84.114 82.211 ;
     RECT  7.815 82.061 8.097 83.101 ;
     RECT  8.892 82.211 83.697 83.101 ;
     RECT  7.815 83.101 83.697 83.165 ;
     RECT  8.82 83.165 83.697 84.145 ;
     RECT  7.815 83.165 8.097 84.181 ;
     RECT  8.82 84.145 83.754 84.181 ;
     RECT  7.815 84.181 83.754 84.299 ;
     RECT  7.815 84.299 8.694 84.365 ;
     RECT  9.54 84.299 83.754 84.721 ;
     RECT  9.54 84.721 84.114 84.839 ;
     RECT  9.576 84.839 84.114 85.469 ;
     RECT  9.576 85.469 16.83 85.649 ;
     RECT  17.748 85.469 84.114 85.649 ;
     RECT  9.576 85.649 16.506 85.685 ;
     RECT  9.648 85.685 16.506 85.757 ;
     RECT  17.748 85.649 83.754 86.575 ;
     RECT  9.756 85.757 16.506 86.635 ;
     RECT  17.64 86.575 83.754 86.635 ;
     RECT  9.756 86.635 83.754 86.737 ;
     RECT  9.684 86.737 83.754 86.873 ;
     RECT  9.684 86.873 17.37 87.611 ;
     RECT  18.288 86.873 83.754 87.647 ;
     RECT  9.936 87.611 17.37 87.853 ;
     RECT  18.288 87.647 83.697 87.853 ;
     RECT  9.936 87.853 83.697 87.917 ;
     RECT  10.692 87.917 83.697 88.115 ;
     RECT  10.692 88.115 47.646 88.349 ;
     RECT  9.936 87.917 9.954 88.385 ;
     RECT  10.692 88.349 32.886 88.385 ;
     RECT  18.432 88.385 32.886 88.397 ;
     RECT  48.384 88.115 83.697 88.429 ;
     RECT  18.432 88.397 32.85 88.541 ;
     RECT  33.732 88.349 47.646 88.727 ;
     RECT  48.384 88.429 83.79 88.735 ;
     RECT  45.252 88.727 47.646 88.861 ;
     RECT  48.384 88.735 83.97 88.861 ;
     RECT  10.692 88.385 17.622 88.889 ;
     RECT  10.692 88.889 11.43 88.925 ;
     RECT  12.312 88.889 17.622 89.033 ;
     RECT  11.052 88.925 11.43 89.069 ;
     RECT  45.252 88.861 83.97 89.159 ;
     RECT  11.412 89.069 11.43 89.195 ;
     RECT  45.252 89.159 83.862 89.195 ;
     RECT  12.456 89.033 17.622 89.311 ;
     RECT  18.432 88.541 32.706 89.311 ;
     RECT  33.732 88.727 44.514 89.311 ;
     RECT  12.456 89.311 44.514 89.473 ;
     RECT  45.252 89.195 83.697 89.473 ;
     RECT  12.456 89.473 83.697 89.807 ;
     RECT  12.564 89.807 83.697 90.041 ;
     RECT  12.96 90.041 83.697 90.077 ;
     RECT  13.104 90.077 83.697 90.239 ;
     RECT  82.368 90.239 83.697 90.275 ;
     RECT  13.104 90.239 81.63 90.581 ;
     RECT  13.215 90.581 81.63 90.605 ;
     RECT  82.368 90.275 82.53 90.779 ;
     RECT  13.215 90.605 55.35 90.887 ;
     RECT  18.18 90.887 55.35 91.049 ;
     RECT  82.476 90.779 82.53 91.049 ;
     RECT  50.004 91.049 55.35 91.085 ;
     RECT  18.18 91.049 49.266 91.181 ;
     RECT  41.328 91.181 49.266 91.193 ;
     RECT  56.16 90.605 81.63 91.193 ;
     RECT  56.415 91.193 81.63 91.319 ;
     RECT  82.476 91.049 82.494 91.319 ;
     RECT  54.612 91.085 55.35 91.355 ;
     RECT  50.004 91.085 53.658 91.589 ;
     RECT  54.684 91.355 55.35 91.589 ;
     RECT  56.415 91.319 81.558 91.589 ;
     RECT  50.004 91.589 52.65 91.625 ;
     RECT  54.792 91.589 55.242 91.625 ;
     RECT  54.864 91.625 54.882 91.661 ;
     RECT  13.215 90.887 17.442 91.705 ;
     RECT  18.18 91.181 40.59 91.705 ;
     RECT  56.415 91.589 80.514 91.769 ;
     RECT  41.328 91.193 49.158 91.859 ;
     RECT  53.604 91.589 53.658 91.859 ;
     RECT  13.215 91.705 40.59 91.895 ;
     RECT  41.328 91.859 46.17 91.901 ;
     RECT  56.415 91.769 57.402 91.901 ;
     RECT  18.615 91.895 40.59 91.931 ;
     RECT  58.32 91.769 80.514 91.931 ;
     RECT  58.32 91.931 58.626 91.967 ;
     RECT  41.328 91.901 45.897 92.003 ;
     RECT  53.604 91.859 53.622 92.003 ;
     RECT  13.215 91.895 17.838 92.129 ;
     RECT  47.052 91.859 49.158 92.129 ;
     RECT  56.415 91.901 57.294 92.129 ;
     RECT  58.32 91.967 58.482 92.129 ;
     RECT  59.58 91.931 80.514 92.129 ;
     RECT  17.28 92.129 17.838 92.165 ;
     RECT  47.232 92.129 49.158 92.165 ;
     RECT  56.415 92.129 57.186 92.165 ;
     RECT  58.32 92.129 58.338 92.165 ;
     RECT  59.58 92.129 80.298 92.165 ;
     RECT  41.616 92.003 45.897 92.237 ;
     RECT  49.14 92.165 49.158 92.237 ;
     RECT  61.164 92.165 80.298 92.237 ;
     RECT  18.615 91.931 19.602 92.273 ;
     RECT  47.232 92.165 48.078 92.273 ;
     RECT  50.004 91.625 52.398 92.273 ;
     RECT  59.976 92.165 60.318 92.273 ;
     RECT  13.215 92.129 16.542 92.309 ;
     RECT  60.3 92.273 60.318 92.309 ;
     RECT  61.164 92.237 63.378 92.309 ;
     RECT  64.152 92.237 80.298 92.333 ;
     RECT  14.76 92.309 16.542 92.399 ;
     RECT  18.615 92.273 19.386 92.399 ;
     RECT  44.568 92.237 45.897 92.399 ;
     RECT  47.844 92.273 48.078 92.399 ;
     RECT  50.328 92.273 52.398 92.399 ;
     RECT  61.815 92.309 62.55 92.399 ;
     RECT  63.288 92.309 63.378 92.399 ;
     RECT  64.512 92.333 80.298 92.399 ;
     RECT  65.916 92.399 75.366 92.429 ;
     RECT  41.616 92.237 42.642 92.435 ;
     RECT  47.844 92.399 47.862 92.435 ;
     RECT  50.328 92.399 51.462 92.435 ;
     RECT  61.815 92.399 62.406 92.435 ;
     RECT  63.288 92.399 63.306 92.435 ;
     RECT  64.512 92.399 65.07 92.435 ;
     RECT  65.916 92.429 70.974 92.435 ;
     RECT  71.784 92.429 75.366 92.435 ;
     RECT  76.104 92.399 80.19 92.435 ;
     RECT  14.796 92.399 15.426 92.471 ;
     RECT  76.104 92.435 79.614 92.471 ;
     RECT  20.34 91.931 40.59 92.507 ;
     RECT  50.328 92.435 51.297 92.507 ;
     RECT  65.916 92.435 69.822 92.507 ;
     RECT  15.228 92.471 15.246 92.543 ;
     RECT  45 92.399 45.897 92.543 ;
     RECT  28.188 92.507 40.59 92.551 ;
     RECT  16.38 92.399 16.542 92.579 ;
     RECT  20.34 92.507 27.306 92.579 ;
     RECT  70.668 92.435 70.974 92.579 ;
     RECT  2.415 74.309 2.697 92.627 ;
     RECT  7.815 84.365 8.097 92.627 ;
     RECT  13.215 92.309 13.497 92.627 ;
     RECT  18.615 92.399 18.897 92.627 ;
     RECT  45.615 92.543 45.897 92.627 ;
     RECT  51.015 92.507 51.297 92.627 ;
     RECT  56.415 92.165 56.697 92.627 ;
     RECT  61.815 92.435 62.097 92.627 ;
     RECT  83.415 90.275 83.697 92.627 ;
     RECT  18.615 92.627 18.774 92.669 ;
     RECT  20.34 92.579 23.058 92.669 ;
     RECT  23.832 92.579 27.306 92.669 ;
     RECT  28.188 92.551 40.626 92.669 ;
     RECT  42.012 92.435 42.642 92.669 ;
     RECT  65.916 92.507 66.042 92.669 ;
     RECT  66.888 92.507 69.318 92.669 ;
     RECT  70.668 92.579 70.866 92.669 ;
     RECT  71.82 92.435 75.366 92.669 ;
     RECT  77.796 92.471 78.822 92.669 ;
     RECT  79.596 92.471 79.614 92.669 ;
     RECT  17.82 92.165 17.838 92.705 ;
     RECT  21.564 92.669 22.014 92.705 ;
     RECT  24.015 92.669 26.37 92.705 ;
     RECT  27.288 92.669 27.306 92.705 ;
     RECT  33.264 92.669 33.966 92.705 ;
     RECT  34.815 92.669 40.626 92.705 ;
     RECT  64.512 92.435 64.854 92.705 ;
     RECT  65.916 92.669 65.934 92.705 ;
     RECT  68.22 92.669 68.238 92.705 ;
     RECT  69.084 92.669 69.318 92.705 ;
     RECT  70.668 92.669 70.686 92.705 ;
     RECT  73.44 92.669 74.034 92.705 ;
     RECT  76.104 92.471 77.022 92.705 ;
     RECT  42.012 92.669 42.03 92.717 ;
     RECT  43.452 92.237 43.47 92.717 ;
     RECT  28.656 92.669 32.526 92.741 ;
     RECT  24.015 92.705 25.398 92.777 ;
     RECT  26.352 92.705 26.37 92.777 ;
     RECT  29.415 92.741 30.366 92.777 ;
     RECT  32.508 92.741 32.526 92.777 ;
     RECT  35.712 92.705 35.91 92.777 ;
     RECT  37.116 92.705 37.638 92.777 ;
     RECT  66.888 92.669 67.374 92.777 ;
     RECT  69.084 92.705 69.102 92.777 ;
     RECT  75.024 92.669 75.366 92.777 ;
     RECT  16.524 92.579 16.542 92.813 ;
     RECT  20.448 92.669 20.466 92.813 ;
     RECT  24.015 92.777 25.362 92.813 ;
     RECT  31.392 92.741 31.59 92.813 ;
     RECT  35.712 92.777 35.73 92.813 ;
     RECT  38.664 92.705 39.402 92.813 ;
     RECT  40.215 92.705 40.626 92.813 ;
     RECT  75.06 92.777 75.366 92.813 ;
     RECT  78.015 92.669 78.354 92.813 ;
     RECT  24.015 92.813 24.786 92.849 ;
     RECT  28.656 92.741 28.674 92.849 ;
     RECT  29.415 92.777 30.078 92.849 ;
     RECT  31.572 92.813 31.59 92.849 ;
     RECT  33.588 92.705 33.606 92.849 ;
     RECT  37.62 92.777 37.638 92.849 ;
     RECT  39.384 92.813 39.402 92.849 ;
     RECT  64.512 92.705 64.53 92.849 ;
     RECT  67.215 92.777 67.374 92.849 ;
     RECT  75.348 92.813 75.366 92.849 ;
     RECT  76.14 92.705 76.158 92.849 ;
     RECT  77.004 92.705 77.022 92.849 ;
     RECT  2.415 92.627 2.505 92.897 ;
     RECT  7.815 92.627 7.905 92.897 ;
     RECT  13.215 92.627 13.305 92.897 ;
     RECT  18.615 92.669 18.705 92.897 ;
     RECT  24.015 92.849 24.105 92.897 ;
     RECT  29.415 92.849 29.505 92.897 ;
     RECT  34.815 92.705 34.905 92.897 ;
     RECT  40.215 92.813 40.305 92.897 ;
     RECT  45.615 92.627 45.705 92.897 ;
     RECT  51.015 92.627 51.105 92.897 ;
     RECT  56.415 92.627 56.505 92.897 ;
     RECT  61.815 92.627 61.905 92.897 ;
     RECT  67.215 92.849 67.305 92.897 ;
     RECT  72.615 92.669 72.705 92.897 ;
     RECT  78.015 92.813 78.105 92.897 ;
     RECT  83.415 92.627 83.505 92.897 ;
    LAYER M4 ;
     RECT  0.084 37.488 0.137 37.512 ;
     RECT  0.06 37.512 0.137 37.584 ;
     RECT  0.084 37.584 0.137 37.608 ;
     RECT  0.06 37.608 0.137 37.68 ;
     RECT  0.084 37.68 0.137 37.704 ;
     RECT  0.06 37.704 0.137 37.776 ;
     RECT  0.084 37.776 0.137 37.8 ;
     RECT  0.06 37.8 0.137 37.872 ;
     RECT  0.084 37.872 0.137 37.896 ;
     RECT  0.06 37.896 0.137 37.968 ;
     RECT  0.084 37.968 0.137 37.992 ;
     RECT  0.06 37.992 0.137 38.064 ;
     RECT  0.084 38.064 0.137 38.088 ;
     RECT  0.06 38.088 0.137 38.16 ;
     RECT  0.084 38.16 0.137 38.184 ;
     RECT  0.06 38.184 0.137 38.256 ;
     RECT  0.084 38.256 0.137 38.28 ;
     RECT  0.06 38.28 0.137 38.352 ;
     RECT  0.084 38.352 0.137 38.376 ;
     RECT  0.06 38.376 0.137 38.448 ;
     RECT  0.084 38.448 0.137 38.472 ;
     RECT  0.06 38.472 0.137 38.544 ;
     RECT  0.084 38.544 0.137 38.568 ;
     RECT  0.06 38.568 0.137 38.64 ;
     RECT  0.084 38.64 0.137 38.664 ;
     RECT  0.06 38.664 0.137 38.736 ;
     RECT  0.084 38.736 0.137 38.76 ;
     RECT  0.06 38.76 0.137 38.832 ;
     RECT  0.084 38.832 0.137 38.856 ;
     RECT  0.06 38.856 0.137 38.928 ;
     RECT  0.084 38.928 0.137 38.952 ;
     RECT  0.06 38.952 0.137 39.024 ;
     RECT  0.084 39.024 0.137 39.048 ;
     RECT  0.06 39.048 0.137 39.12 ;
     RECT  0.084 39.12 0.137 39.144 ;
     RECT  0.06 39.144 0.137 39.216 ;
     RECT  0.084 39.216 0.137 39.24 ;
     RECT  0.06 39.24 0.137 39.312 ;
     RECT  0.084 39.312 0.137 39.336 ;
     RECT  0.06 39.336 0.137 39.408 ;
     RECT  0.084 39.408 0.137 39.432 ;
     RECT  0.06 39.432 0.137 39.504 ;
     RECT  0.084 39.504 0.137 39.528 ;
     RECT  0.06 39.528 0.137 39.6 ;
     RECT  0.084 39.6 0.137 39.624 ;
     RECT  0.06 39.624 0.137 39.696 ;
     RECT  0.084 39.696 0.137 39.72 ;
     RECT  0.06 39.72 0.137 39.792 ;
     RECT  0.084 39.792 0.137 39.816 ;
     RECT  0.06 39.816 0.137 39.888 ;
     RECT  0.084 39.888 0.137 39.912 ;
     RECT  0.06 39.912 0.137 39.984 ;
     RECT  0.084 39.984 0.137 40.008 ;
     RECT  0.06 40.008 0.137 40.08 ;
     RECT  0.084 40.08 0.137 40.104 ;
     RECT  0.06 40.104 0.137 40.176 ;
     RECT  0.084 40.176 0.137 40.2 ;
     RECT  0.06 40.2 0.137 40.272 ;
     RECT  0.084 40.272 0.137 40.296 ;
     RECT  0.06 40.296 0.137 40.368 ;
     RECT  0.084 40.368 0.137 40.392 ;
     RECT  0.06 40.392 0.137 40.464 ;
     RECT  0.084 40.464 0.137 40.488 ;
     RECT  0.084 27.504 0.569 27.528 ;
     RECT  0.06 27.528 0.569 27.6 ;
     RECT  0.084 27.6 0.569 27.624 ;
     RECT  0.06 27.624 0.569 27.696 ;
     RECT  0.084 27.696 0.569 27.72 ;
     RECT  0.06 27.72 0.569 27.792 ;
     RECT  0.084 27.792 0.569 27.816 ;
     RECT  0.06 27.816 0.569 27.888 ;
     RECT  0.084 27.888 0.569 27.912 ;
     RECT  0.06 27.912 0.569 27.984 ;
     RECT  0.084 27.984 0.569 28.008 ;
     RECT  0.06 28.008 0.569 28.08 ;
     RECT  0.084 28.08 0.569 28.104 ;
     RECT  0.06 28.104 0.569 28.176 ;
     RECT  0.084 28.176 0.569 28.2 ;
     RECT  0.06 28.2 0.569 28.272 ;
     RECT  0.084 28.272 0.569 28.296 ;
     RECT  0.06 28.296 0.569 28.368 ;
     RECT  0.084 28.368 0.569 28.392 ;
     RECT  0.06 28.392 0.569 28.464 ;
     RECT  0.084 28.464 0.569 28.488 ;
     RECT  0.06 28.488 0.569 28.56 ;
     RECT  0.084 28.56 0.569 28.584 ;
     RECT  0.06 28.584 0.569 28.656 ;
     RECT  0.084 28.656 0.569 28.68 ;
     RECT  0.06 28.68 0.569 28.752 ;
     RECT  0.084 28.752 0.569 28.776 ;
     RECT  0.06 28.776 0.569 28.848 ;
     RECT  0.084 28.848 0.569 28.872 ;
     RECT  0.06 28.872 0.569 28.944 ;
     RECT  0.084 28.944 0.569 28.968 ;
     RECT  0.06 28.968 0.569 29.04 ;
     RECT  0.084 29.04 0.569 29.064 ;
     RECT  0.06 29.064 0.569 29.136 ;
     RECT  0.084 29.136 0.569 29.16 ;
     RECT  0.06 29.16 0.569 29.232 ;
     RECT  0.084 29.232 0.569 29.256 ;
     RECT  0.06 29.256 0.569 29.328 ;
     RECT  0.084 29.328 0.569 29.352 ;
     RECT  0.06 29.352 0.569 29.424 ;
     RECT  0.084 29.424 0.569 29.448 ;
     RECT  0.06 29.448 0.569 29.52 ;
     RECT  0.084 29.52 0.569 29.544 ;
     RECT  0.06 29.544 0.569 29.616 ;
     RECT  0.084 29.616 0.569 29.64 ;
     RECT  0.06 29.64 0.569 29.712 ;
     RECT  0.084 29.712 0.569 29.736 ;
     RECT  0.06 29.736 0.569 29.808 ;
     RECT  0.084 29.808 0.569 29.832 ;
     RECT  0.06 29.832 0.569 29.904 ;
     RECT  0.084 29.904 0.569 29.928 ;
     RECT  0.06 29.928 0.569 30 ;
     RECT  0.084 30 0.569 30.024 ;
     RECT  0.06 30.024 0.569 30.096 ;
     RECT  0.084 30.096 0.569 30.12 ;
     RECT  0.06 30.12 0.569 30.192 ;
     RECT  0.084 30.192 0.569 30.216 ;
     RECT  0.06 30.216 0.569 30.288 ;
     RECT  0.084 30.288 0.569 30.312 ;
     RECT  0.06 30.312 0.569 30.384 ;
     RECT  0.084 30.384 0.569 30.408 ;
     RECT  0.06 30.408 0.569 30.48 ;
     RECT  0.084 30.48 0.569 30.504 ;
     RECT  0.084 49.776 0.569 49.8 ;
     RECT  0.06 49.8 0.569 49.872 ;
     RECT  0.084 49.872 0.569 49.896 ;
     RECT  0.06 49.896 0.569 49.968 ;
     RECT  0.084 49.968 0.569 49.992 ;
     RECT  0.06 49.992 0.569 50.064 ;
     RECT  0.084 50.064 0.569 50.088 ;
     RECT  0.06 50.088 0.569 50.16 ;
     RECT  0.084 50.16 0.569 50.184 ;
     RECT  0.06 50.184 0.569 50.256 ;
     RECT  0.084 50.256 0.569 50.28 ;
     RECT  0.06 50.28 0.569 50.352 ;
     RECT  0.084 50.352 0.569 50.376 ;
     RECT  0.06 50.376 0.569 50.448 ;
     RECT  0.084 50.448 0.569 50.472 ;
     RECT  0.06 50.472 0.569 50.544 ;
     RECT  0.084 50.544 0.569 50.568 ;
     RECT  0.06 50.568 0.569 50.64 ;
     RECT  0.084 50.64 0.569 50.664 ;
     RECT  0.06 50.664 0.569 50.736 ;
     RECT  0.084 50.736 0.569 50.76 ;
     RECT  0.06 50.76 0.569 50.832 ;
     RECT  0.084 50.832 0.569 50.856 ;
     RECT  0.06 50.856 0.569 50.928 ;
     RECT  0.084 50.928 0.569 50.952 ;
     RECT  0.06 50.952 0.569 51.024 ;
     RECT  0.084 51.024 0.569 51.048 ;
     RECT  0.06 51.048 0.569 51.12 ;
     RECT  0.084 51.12 0.569 51.144 ;
     RECT  0.06 51.144 0.569 51.216 ;
     RECT  0.084 51.216 0.569 51.24 ;
     RECT  0.06 51.24 0.569 51.312 ;
     RECT  0.084 51.312 0.569 51.336 ;
     RECT  0.06 51.336 0.569 51.408 ;
     RECT  0.084 51.408 0.569 51.432 ;
     RECT  0.06 51.432 0.569 51.504 ;
     RECT  0.084 51.504 0.569 51.528 ;
     RECT  0.06 51.528 0.569 51.6 ;
     RECT  0.084 51.6 0.569 51.624 ;
     RECT  0.06 51.624 0.569 51.696 ;
     RECT  0.084 51.696 0.569 51.72 ;
     RECT  0.06 51.72 0.569 51.792 ;
     RECT  0.084 51.792 0.569 51.816 ;
     RECT  0.06 51.816 0.569 51.888 ;
     RECT  0.084 51.888 0.569 51.912 ;
     RECT  0.06 51.912 0.569 51.984 ;
     RECT  0.084 51.984 0.569 52.008 ;
     RECT  0.06 52.008 0.569 52.08 ;
     RECT  0.084 52.08 0.569 52.104 ;
     RECT  0.06 52.104 0.569 52.176 ;
     RECT  0.084 52.176 0.569 52.2 ;
     RECT  0.06 52.2 0.569 52.272 ;
     RECT  0.084 52.272 0.569 52.296 ;
     RECT  0.06 52.296 0.569 52.368 ;
     RECT  0.084 52.368 0.569 52.392 ;
     RECT  0.06 52.392 0.569 52.464 ;
     RECT  0.084 52.464 0.569 52.488 ;
     RECT  0.06 52.488 0.569 52.56 ;
     RECT  0.084 52.56 0.569 52.584 ;
     RECT  0.06 52.584 0.569 52.656 ;
     RECT  0.084 52.656 0.569 52.68 ;
     RECT  0.06 52.68 0.569 52.752 ;
     RECT  0.084 52.752 0.569 52.776 ;
     RECT  0.084 43.632 0.857 43.656 ;
     RECT  0.06 43.656 0.857 43.728 ;
     RECT  0.084 43.728 0.857 43.752 ;
     RECT  0.06 43.752 0.857 43.824 ;
     RECT  0.084 43.824 0.857 43.848 ;
     RECT  0.06 43.848 0.857 43.92 ;
     RECT  0.084 43.92 0.857 43.944 ;
     RECT  0.06 43.944 0.857 44.016 ;
     RECT  0.084 44.016 0.857 44.04 ;
     RECT  0.06 44.04 0.857 44.112 ;
     RECT  0.084 44.112 0.857 44.136 ;
     RECT  0.06 44.136 0.857 44.208 ;
     RECT  0.084 44.208 0.857 44.232 ;
     RECT  0.06 44.232 0.857 44.304 ;
     RECT  0.084 44.304 0.857 44.328 ;
     RECT  0.06 44.328 0.857 44.4 ;
     RECT  0.084 44.4 0.857 44.424 ;
     RECT  0.06 44.424 0.857 44.496 ;
     RECT  0.084 44.496 0.857 44.52 ;
     RECT  0.06 44.52 0.857 44.592 ;
     RECT  0.084 44.592 0.857 44.616 ;
     RECT  0.06 44.616 0.857 44.688 ;
     RECT  0.084 44.688 0.857 44.712 ;
     RECT  0.06 44.712 0.857 44.784 ;
     RECT  0.084 44.784 0.857 44.808 ;
     RECT  0.06 44.808 0.857 44.88 ;
     RECT  0.084 44.88 0.857 44.904 ;
     RECT  0.06 44.904 0.857 44.976 ;
     RECT  0.084 44.976 0.857 45 ;
     RECT  0.06 45 0.857 45.072 ;
     RECT  0.084 45.072 0.857 45.096 ;
     RECT  0.06 45.096 0.857 45.168 ;
     RECT  0.084 45.168 0.857 45.192 ;
     RECT  0.06 45.192 0.857 45.264 ;
     RECT  0.084 45.264 0.857 45.288 ;
     RECT  0.06 45.288 0.857 45.36 ;
     RECT  0.084 45.36 0.857 45.384 ;
     RECT  0.06 45.384 0.857 45.456 ;
     RECT  0.084 45.456 0.857 45.48 ;
     RECT  0.06 45.48 0.857 45.552 ;
     RECT  0.084 45.552 0.857 45.576 ;
     RECT  0.06 45.576 0.857 45.648 ;
     RECT  0.084 45.648 0.857 45.672 ;
     RECT  0.06 45.672 0.857 45.744 ;
     RECT  0.084 45.744 0.857 45.768 ;
     RECT  0.06 45.768 0.857 45.84 ;
     RECT  0.084 45.84 0.857 45.864 ;
     RECT  0.06 45.864 0.857 45.936 ;
     RECT  0.084 45.936 0.857 45.96 ;
     RECT  0.06 45.96 0.857 46.032 ;
     RECT  0.084 46.032 0.857 46.056 ;
     RECT  0.06 46.056 0.857 46.128 ;
     RECT  0.084 46.128 0.857 46.152 ;
     RECT  0.06 46.152 0.857 46.224 ;
     RECT  0.084 46.224 0.857 46.248 ;
     RECT  0.06 46.248 0.857 46.32 ;
     RECT  0.084 46.32 0.857 46.344 ;
     RECT  0.06 46.344 0.857 46.416 ;
     RECT  0.084 46.416 0.857 46.44 ;
     RECT  0.06 46.44 0.857 46.512 ;
     RECT  0.084 46.512 0.857 46.536 ;
     RECT  0.06 46.536 0.857 46.608 ;
     RECT  0.084 46.608 0.857 46.632 ;
     RECT  0.137 37.584 2.293 40.488 ;
     RECT  2.257 55.152 2.293 55.176 ;
     RECT  0.857 43.632 2.365 46.536 ;
     RECT  0.084 19.92 2.401 19.944 ;
     RECT  0.06 19.944 2.401 20.016 ;
     RECT  0.084 20.016 2.401 20.04 ;
     RECT  0.06 20.04 2.401 20.112 ;
     RECT  0.084 20.112 2.401 20.136 ;
     RECT  0.06 20.136 2.401 20.208 ;
     RECT  0.084 20.208 2.401 20.232 ;
     RECT  0.06 20.232 2.401 20.304 ;
     RECT  0.084 20.304 2.401 20.328 ;
     RECT  0.06 20.328 2.401 20.4 ;
     RECT  0.084 20.4 2.401 20.424 ;
     RECT  0.06 20.424 2.401 20.496 ;
     RECT  0.084 20.496 2.401 20.52 ;
     RECT  0.06 20.52 2.401 20.592 ;
     RECT  0.084 20.592 2.401 20.616 ;
     RECT  0.06 20.616 2.401 20.688 ;
     RECT  0.084 20.688 2.401 20.712 ;
     RECT  0.06 20.712 2.401 20.784 ;
     RECT  0.084 20.784 2.401 20.808 ;
     RECT  0.06 20.808 2.401 20.88 ;
     RECT  0.084 20.88 2.401 20.904 ;
     RECT  0.06 20.904 2.401 20.976 ;
     RECT  0.084 20.976 2.401 21 ;
     RECT  0.06 21 2.401 21.072 ;
     RECT  0.084 21.072 2.401 21.096 ;
     RECT  0.06 21.096 2.401 21.168 ;
     RECT  0.084 21.168 2.401 21.192 ;
     RECT  0.06 21.192 2.401 21.264 ;
     RECT  0.084 21.264 2.401 21.288 ;
     RECT  2.401 19.92 2.408 21.528 ;
     RECT  0.569 27.696 2.408 30.504 ;
     RECT  2.293 36.576 2.408 41.4 ;
     RECT  2.365 43.104 2.408 47.4 ;
     RECT  0.569 49.968 2.408 52.776 ;
     RECT  2.293 54.912 2.408 55.176 ;
     RECT  2.293 56.784 2.408 56.808 ;
     RECT  2.408 2.148 2.512 92.892 ;
     RECT  2.512 2.418 2.704 92.622 ;
     RECT  2.704 32.208 2.765 58.152 ;
     RECT  2.704 28.176 2.801 30.408 ;
     RECT  2.765 32.208 2.819 46.008 ;
     RECT  2.704 19.92 2.867 23.16 ;
     RECT  2.819 40.992 2.909 46.008 ;
     RECT  2.801 28.464 3.017 30.408 ;
     RECT  2.704 66.816 3.161 66.84 ;
     RECT  2.704 70.656 3.161 70.68 ;
     RECT  2.704 26.784 3.341 26.808 ;
     RECT  2.819 32.208 3.449 39.624 ;
     RECT  2.704 59.232 3.539 60.552 ;
     RECT  2.765 47.04 3.628 58.152 ;
     RECT  3.449 32.208 3.733 38.28 ;
     RECT  3.017 28.464 3.769 29.304 ;
     RECT  2.704 63.024 3.769 63.048 ;
     RECT  3.733 31.92 3.877 38.28 ;
     RECT  3.449 39.312 3.905 39.624 ;
     RECT  3.539 60.528 3.949 60.552 ;
     RECT  3.697 30.72 3.985 30.744 ;
     RECT  3.985 30.72 4.021 30.84 ;
     RECT  3.877 31.872 4.021 38.28 ;
     RECT  2.704 18.768 4.057 18.792 ;
     RECT  3.769 62.64 4.061 63.048 ;
     RECT  4.057 18.768 4.129 18.84 ;
     RECT  2.909 40.992 4.129 45.48 ;
     RECT  4.129 18.768 4.165 19.032 ;
     RECT  2.867 20.064 4.165 23.16 ;
     RECT  3.905 39.312 4.172 39.912 ;
     RECT  4.172 39.312 4.201 40.008 ;
     RECT  4.129 40.992 4.201 46.008 ;
     RECT  4.165 18.768 4.237 23.16 ;
     RECT  3.769 28.128 4.273 29.304 ;
     RECT  4.165 14.832 4.277 14.856 ;
     RECT  3.949 66.432 4.277 66.456 ;
     RECT  4.237 18.768 4.309 23.4 ;
     RECT  4.201 25.68 4.345 26.472 ;
     RECT  4.273 28.128 4.389 29.352 ;
     RECT  4.021 30.72 4.389 38.28 ;
     RECT  4.201 39.312 4.412 46.008 ;
     RECT  3.628 47.04 4.412 49.032 ;
     RECT  4.345 25.68 4.417 26.808 ;
     RECT  4.389 28.128 4.417 38.28 ;
     RECT  4.309 18.672 4.453 23.4 ;
     RECT  4.453 18.624 4.525 23.4 ;
     RECT  3.805 72.576 4.525 72.6 ;
     RECT  3.949 16.56 4.565 16.584 ;
     RECT  4.525 17.76 4.565 24.216 ;
     RECT  4.412 39.312 4.597 49.032 ;
     RECT  3.628 50.112 4.597 58.152 ;
     RECT  4.525 71.808 4.601 72.6 ;
     RECT  4.417 25.68 4.705 38.28 ;
     RECT  4.597 39.312 4.705 58.152 ;
     RECT  4.565 17.76 4.709 19.128 ;
     RECT  4.705 25.68 4.745 58.152 ;
     RECT  3.805 8.976 4.781 9 ;
     RECT  4.709 17.76 4.844 18.936 ;
     RECT  3.949 60.528 4.885 60.792 ;
     RECT  4.885 13.056 4.957 13.08 ;
     RECT  4.601 71.808 4.961 71.832 ;
     RECT  4.453 5.712 4.988 5.736 ;
     RECT  4.957 13.056 4.993 13.368 ;
     RECT  4.453 7.872 5.001 7.896 ;
     RECT  4.565 20.16 5.029 24.216 ;
     RECT  4.745 25.68 5.029 53.064 ;
     RECT  4.993 12.912 5.065 13.368 ;
     RECT  4.988 5.184 5.075 5.736 ;
     RECT  5.001 7.248 5.075 7.896 ;
     RECT  5.075 5.712 5.097 5.736 ;
     RECT  5.029 20.16 5.177 53.064 ;
     RECT  5.101 66.384 5.281 66.408 ;
     RECT  4.745 54.096 5.317 58.152 ;
     RECT  5.065 12.768 5.353 13.368 ;
     RECT  5.317 54.096 5.389 58.728 ;
     RECT  4.885 59.712 5.389 60.792 ;
     RECT  5.075 7.248 5.429 7.368 ;
     RECT  5.177 20.16 5.459 37.608 ;
     RECT  4.061 62.64 5.533 62.664 ;
     RECT  4.844 17.616 5.569 18.936 ;
     RECT  5.569 16.8 5.701 18.936 ;
     RECT  5.459 20.16 5.747 37.32 ;
     RECT  5.747 20.16 5.789 29.064 ;
     RECT  5.389 54.096 5.893 60.792 ;
     RECT  5.281 66.24 5.897 66.408 ;
     RECT  5.533 62.64 5.933 62.76 ;
     RECT  5.893 54.096 5.941 61.608 ;
     RECT  5.941 54.048 5.965 61.608 ;
     RECT  5.701 16.512 5.969 18.936 ;
     RECT  5.789 20.16 6.001 26.376 ;
     RECT  5.965 54.048 6.005 61.656 ;
     RECT  6.005 54.048 6.041 54.696 ;
     RECT  5.677 64.992 6.077 65.016 ;
     RECT  5.177 38.688 6.092 53.064 ;
     RECT  6.041 54.048 6.092 54.504 ;
     RECT  5.569 63.744 6.109 63.768 ;
     RECT  5.389 9.648 6.145 9.672 ;
     RECT  6.092 38.688 6.149 54.504 ;
     RECT  5.353 12.768 6.181 13.944 ;
     RECT  5.747 30.144 6.193 37.32 ;
     RECT  6.181 69.216 6.217 69.24 ;
     RECT  5.749 70.272 6.217 70.296 ;
     RECT  6.181 12.768 6.221 14.28 ;
     RECT  6.149 46.224 6.221 54.504 ;
     RECT  6.149 38.688 6.253 45.192 ;
     RECT  5.789 27.648 6.275 29.064 ;
     RECT  6.145 9.6 6.289 9.672 ;
     RECT  4.777 11.136 6.289 11.16 ;
     RECT  6.221 12.768 6.289 13.224 ;
     RECT  5.969 16.944 6.325 18.936 ;
     RECT  6.001 19.92 6.325 26.376 ;
     RECT  6.289 12.336 6.365 13.224 ;
     RECT  6.221 14.256 6.365 14.28 ;
     RECT  6.325 16.944 6.365 26.376 ;
     RECT  6.365 19.44 6.371 26.376 ;
     RECT  6.181 76.944 6.373 76.968 ;
     RECT  6.289 9.6 6.397 11.16 ;
     RECT  6.365 12.336 6.397 13.128 ;
     RECT  6.275 27.648 6.401 28.488 ;
     RECT  2.704 75.216 6.419 75.24 ;
     RECT  6.373 76.32 6.437 76.968 ;
     RECT  6.437 76.32 6.46 76.824 ;
     RECT  6.253 38.64 6.473 45.192 ;
     RECT  5.897 66.384 6.473 66.408 ;
     RECT  6.109 63.504 6.505 63.768 ;
     RECT  6.005 55.872 6.545 61.656 ;
     RECT  6.217 69.216 6.545 70.296 ;
     RECT  6.193 30.192 6.577 37.32 ;
     RECT  6.473 38.64 6.577 44.184 ;
     RECT  6.371 23.904 6.581 26.376 ;
     RECT  6.371 19.44 6.617 22.776 ;
     RECT  5.533 71.28 6.653 71.304 ;
     RECT  6.545 55.872 6.707 60.264 ;
     RECT  5.429 7.344 6.709 7.368 ;
     RECT  6.545 61.392 6.721 61.656 ;
     RECT  6.397 9.6 6.725 13.128 ;
     RECT  6.725 9.6 6.797 12.504 ;
     RECT  6.505 63.504 6.797 64.68 ;
     RECT  6.707 55.872 6.803 58.68 ;
     RECT  6.365 16.944 7.009 18.408 ;
     RECT  5.029 2.544 7.117 2.568 ;
     RECT  6.221 46.224 7.189 54.36 ;
     RECT  6.721 61.392 7.189 62.04 ;
     RECT  6.797 63.504 7.189 63.768 ;
     RECT  6.473 45.168 7.333 45.192 ;
     RECT  7.189 46.224 7.333 54.744 ;
     RECT  7.009 16.56 7.405 18.408 ;
     RECT  6.617 19.44 7.405 21.144 ;
     RECT  6.401 27.696 7.441 28.488 ;
     RECT  6.709 7.344 7.513 7.752 ;
     RECT  7.405 16.56 7.585 21.144 ;
     RECT  6.617 22.176 7.585 22.776 ;
     RECT  6.46 76.32 7.585 76.344 ;
     RECT  6.613 78.624 7.585 78.648 ;
     RECT  7.585 16.56 7.657 22.776 ;
     RECT  6.581 24.192 7.657 26.376 ;
     RECT  6.577 30.192 7.669 44.184 ;
     RECT  7.333 45.168 7.669 54.744 ;
     RECT  7.117 2.544 7.808 3.336 ;
     RECT  7.585 4.416 7.808 4.44 ;
     RECT  7.045 6.048 7.808 6.072 ;
     RECT  7.513 7.344 7.808 8.184 ;
     RECT  6.797 10.176 7.808 12.504 ;
     RECT  7.585 14.208 7.808 14.232 ;
     RECT  7.669 15.312 7.808 15.336 ;
     RECT  7.657 16.56 7.808 26.376 ;
     RECT  7.441 27.6 7.808 28.488 ;
     RECT  7.669 30.192 7.808 54.744 ;
     RECT  6.803 56.496 7.808 58.68 ;
     RECT  6.707 59.808 7.808 60.264 ;
     RECT  7.189 61.392 7.808 63.768 ;
     RECT  6.757 66.768 7.808 66.792 ;
     RECT  7.585 68.928 7.808 68.952 ;
     RECT  6.545 70.128 7.808 70.296 ;
     RECT  7.225 72.432 7.808 72.456 ;
     RECT  7.585 76.32 7.808 76.872 ;
     RECT  7.585 78.624 7.808 79.224 ;
     RECT  7.808 2.148 7.912 92.892 ;
     RECT  7.912 2.418 8.104 92.622 ;
     RECT  8.104 72.384 8.234 72.456 ;
     RECT  8.104 2.544 8.237 4.296 ;
     RECT  8.104 45.936 8.243 51.96 ;
     RECT  8.104 75.168 8.243 75.192 ;
     RECT  8.104 19.536 8.284 29.4 ;
     RECT  8.104 14.784 8.304 18.216 ;
     RECT  8.104 30.624 8.309 44.184 ;
     RECT  8.104 68.64 8.339 70.68 ;
     RECT  8.234 72.384 8.339 72.408 ;
     RECT  8.339 68.64 8.345 69.432 ;
     RECT  8.284 20.112 8.381 29.4 ;
     RECT  8.381 20.16 8.417 29.4 ;
     RECT  8.104 76.32 8.417 79.224 ;
     RECT  8.309 30.816 8.483 44.184 ;
     RECT  8.104 10.944 8.489 11.4 ;
     RECT  8.483 30.816 8.489 43.56 ;
     RECT  8.417 76.416 8.489 79.224 ;
     RECT  8.243 45.936 8.524 51.72 ;
     RECT  8.489 76.416 8.524 77.784 ;
     RECT  8.104 55.824 8.579 56.712 ;
     RECT  8.237 2.544 8.597 3.144 ;
     RECT  8.524 76.416 8.597 77.544 ;
     RECT  8.597 2.88 8.633 3.144 ;
     RECT  8.489 30.816 8.633 36.792 ;
     RECT  8.104 5.904 8.675 7.896 ;
     RECT  8.633 30.816 8.677 36.264 ;
     RECT  8.597 76.992 8.705 77.544 ;
     RECT  8.304 14.784 8.723 17.976 ;
     RECT  8.417 20.16 8.723 26.808 ;
     RECT  8.104 84.336 8.723 84.84 ;
     RECT  8.723 17.616 8.813 17.976 ;
     RECT  8.524 46.08 8.813 51.72 ;
     RECT  8.339 70.656 8.813 70.68 ;
     RECT  8.677 33.072 8.849 36.264 ;
     RECT  8.723 14.784 8.867 16.296 ;
     RECT  8.489 11.232 8.913 11.4 ;
     RECT  8.104 57.984 8.915 59.16 ;
     RECT  8.237 4.272 8.957 4.296 ;
     RECT  8.867 16.032 9.065 16.296 ;
     RECT  8.417 27.888 9.065 29.4 ;
     RECT  8.489 38.112 9.065 43.56 ;
     RECT  8.579 55.824 9.065 56.424 ;
     RECT  8.675 6.48 9.107 7.896 ;
     RECT  8.723 20.544 9.137 26.568 ;
     RECT  8.104 52.992 9.137 53.832 ;
     RECT  8.104 82.032 9.137 83.16 ;
     RECT  9.065 56.4 9.145 56.424 ;
     RECT  9.065 38.112 9.155 39.24 ;
     RECT  9.133 64.944 9.169 64.968 ;
     RECT  9.137 20.592 9.209 26.568 ;
     RECT  8.104 66.768 9.209 66.792 ;
     RECT  9.107 7.728 9.245 7.896 ;
     RECT  8.813 46.512 9.245 51.72 ;
     RECT  8.913 11.376 9.251 11.4 ;
     RECT  8.677 30.816 9.281 31.8 ;
     RECT  8.867 14.784 9.317 14.904 ;
     RECT  8.104 60.24 9.353 60.264 ;
     RECT  8.489 79.2 9.353 79.224 ;
     RECT  9.241 68.064 9.385 68.088 ;
     RECT  8.345 69.264 9.385 69.432 ;
     RECT  8.849 33.072 9.425 34.632 ;
     RECT  9.245 47.664 9.457 51.72 ;
     RECT  9.137 52.992 9.457 53.112 ;
     RECT  8.915 57.984 9.529 59.064 ;
     RECT  8.104 61.392 9.529 61.464 ;
     RECT  9.137 82.032 9.605 82.056 ;
     RECT  9.529 54.672 9.637 54.696 ;
     RECT  9.637 54.672 9.683 55.368 ;
     RECT  8.849 35.712 9.733 36.264 ;
     RECT  9.637 72.96 9.745 72.984 ;
     RECT  9.529 61.392 9.788 61.896 ;
     RECT  9.385 68.064 9.817 69.432 ;
     RECT  9.788 61.392 9.829 62.664 ;
     RECT  9.745 72.96 9.857 73.128 ;
     RECT  9.829 61.392 9.875 63.48 ;
     RECT  8.104 9.648 9.893 9.672 ;
     RECT  9.065 27.888 9.893 28.536 ;
     RECT  9.733 35.712 9.893 36.6 ;
     RECT  9.245 7.776 9.929 7.896 ;
     RECT  9.155 38.784 9.929 39.24 ;
     RECT  8.104 12.48 9.961 12.504 ;
     RECT  9.817 68.064 9.961 70.008 ;
     RECT  9.875 62.976 9.965 63.48 ;
     RECT  9.425 34.608 9.989 34.632 ;
     RECT  9.893 35.712 9.989 36.504 ;
     RECT  9.425 33.072 10.021 33.384 ;
     RECT  9.065 40.368 10.021 43.56 ;
     RECT  10.021 40.368 10.033 44.424 ;
     RECT  9.875 61.392 10.033 61.896 ;
     RECT  9.169 64.944 10.067 65.688 ;
     RECT  9.989 34.608 10.073 36.504 ;
     RECT  9.929 38.832 10.141 39.24 ;
     RECT  10.033 40.368 10.141 45.096 ;
     RECT  9.209 20.592 10.145 22.488 ;
     RECT  9.565 83.472 10.145 83.64 ;
     RECT  9.457 47.664 10.177 53.112 ;
     RECT  9.209 24.096 10.181 26.568 ;
     RECT  10.141 38.832 10.181 45.096 ;
     RECT  9.107 6.48 10.213 6.504 ;
     RECT  9.133 71.136 10.213 71.16 ;
     RECT  10.145 83.616 10.217 83.64 ;
     RECT  10.213 6.144 10.249 6.504 ;
     RECT  10.145 21.744 10.249 22.488 ;
     RECT  10.181 24.096 10.249 25.512 ;
     RECT  10.181 38.832 10.253 44.424 ;
     RECT  10.253 39.792 10.259 44.424 ;
     RECT  9.281 31.2 10.261 31.8 ;
     RECT  10.021 32.784 10.261 33.384 ;
     RECT  10.177 47.664 10.261 53.592 ;
     RECT  10.261 31.2 10.307 33.384 ;
     RECT  10.067 65.04 10.325 65.688 ;
     RECT  10.145 20.592 10.357 20.616 ;
     RECT  10.073 35.712 10.361 36.504 ;
     RECT  9.529 57.552 10.361 59.064 ;
     RECT  8.705 76.992 10.393 77.016 ;
     RECT  10.259 41.52 10.397 44.424 ;
     RECT  9.857 72.96 10.429 73.032 ;
     RECT  10.393 76.656 10.429 77.016 ;
     RECT  8.723 84.816 10.429 84.84 ;
     RECT  9.893 28.512 10.433 28.536 ;
     RECT  10.261 47.664 10.433 53.112 ;
     RECT  10.033 60.432 10.46 61.896 ;
     RECT  10.261 29.952 10.465 29.976 ;
     RECT  10.307 31.2 10.465 31.224 ;
     RECT  10.361 57.552 10.501 59.016 ;
     RECT  10.429 76.656 10.501 77.16 ;
     RECT  10.465 29.952 10.505 31.224 ;
     RECT  10.361 35.712 10.505 36.264 ;
     RECT  10.46 60.24 10.505 61.896 ;
     RECT  9.683 54.72 10.508 55.368 ;
     RECT  10.307 32.496 10.541 33.384 ;
     RECT  9.965 62.976 10.541 63.336 ;
     RECT  10.505 60.24 10.547 60.264 ;
     RECT  10.249 6.144 10.549 6.696 ;
     RECT  9.317 14.88 10.549 14.904 ;
     RECT  9.065 16.272 10.549 16.296 ;
     RECT  10.501 76.512 10.573 77.16 ;
     RECT  10.508 54.72 10.595 56.136 ;
     RECT  10.505 61.248 10.595 61.896 ;
     RECT  10.573 76.368 10.609 77.16 ;
     RECT  10.549 14.88 10.636 16.296 ;
     RECT  9.245 46.512 10.645 46.632 ;
     RECT  10.433 47.664 10.645 48.264 ;
     RECT  9.961 67.248 10.645 70.008 ;
     RECT  10.213 71.136 10.645 71.448 ;
     RECT  10.357 20.4 10.681 20.616 ;
     RECT  10.501 57.504 10.681 59.016 ;
     RECT  10.645 46.512 10.685 48.264 ;
     RECT  10.595 61.344 10.685 61.896 ;
     RECT  9.929 7.872 10.717 7.896 ;
     RECT  10.681 17.664 10.748 17.688 ;
     RECT  10.505 29.952 10.757 30.936 ;
     RECT  10.429 72.576 10.793 73.032 ;
     RECT  10.609 76.368 10.817 77.832 ;
     RECT  10.073 34.608 10.825 34.632 ;
     RECT  10.685 46.848 10.829 48.264 ;
     RECT  10.645 67.248 10.861 71.448 ;
     RECT  10.793 72.576 10.861 72.984 ;
     RECT  10.789 74.16 10.861 74.184 ;
     RECT  10.717 7.872 10.937 8.04 ;
     RECT  10.541 32.496 10.973 33 ;
     RECT  10.825 34.08 10.973 34.632 ;
     RECT  10.433 49.296 10.973 53.112 ;
     RECT  10.861 67.248 10.973 72.984 ;
     RECT  10.636 16.032 11.029 16.296 ;
     RECT  10.748 17.568 11.029 17.688 ;
     RECT  10.717 2.736 11.081 3.384 ;
     RECT  10.595 54.72 11.117 55.608 ;
     RECT  10.181 26.544 11.149 26.568 ;
     RECT  10.817 76.368 11.149 78.12 ;
     RECT  11.029 16.032 11.185 17.688 ;
     RECT  10.325 65.04 11.189 65.064 ;
     RECT  10.501 10.848 11.221 10.872 ;
     RECT  9.961 12 11.221 12.504 ;
     RECT  10.549 6.144 11.249 6.84 ;
     RECT  11.185 16.032 11.257 18.504 ;
     RECT  10.681 19.776 11.257 20.616 ;
     RECT  10.685 61.872 11.293 61.896 ;
     RECT  11.081 2.736 11.333 2.808 ;
     RECT  11.249 6.144 11.333 6.936 ;
     RECT  10.757 30.72 11.333 30.936 ;
     RECT  11.149 26.544 11.365 27.096 ;
     RECT  10.259 39.792 11.365 40.392 ;
     RECT  11.149 76.368 11.365 78.504 ;
     RECT  10.429 84.336 11.369 84.84 ;
     RECT  11.257 16.032 11.405 20.616 ;
     RECT  11.293 61.872 11.405 62.184 ;
     RECT  10.397 41.664 11.459 44.424 ;
     RECT  11.365 39.792 11.473 40.68 ;
     RECT  11.149 66.096 11.473 66.12 ;
     RECT  11.365 26.544 11.513 27.144 ;
     RECT  10.973 49.296 11.513 52.392 ;
     RECT  11.473 65.568 11.513 66.12 ;
     RECT  10.541 63.264 11.549 63.336 ;
     RECT  10.829 46.848 11.585 47.688 ;
     RECT  11.333 6.144 11.653 6.6 ;
     RECT  11.405 16.032 11.689 20.04 ;
     RECT  11.473 39.456 11.689 40.68 ;
     RECT  11.459 41.664 11.689 42.552 ;
     RECT  11.689 39.456 11.693 42.552 ;
     RECT  11.689 15.936 11.747 20.04 ;
     RECT  10.636 14.88 11.761 14.904 ;
     RECT  10.861 74.064 11.761 74.184 ;
     RECT  11.333 2.736 11.801 2.76 ;
     RECT  11.761 14.88 11.833 14.952 ;
     RECT  10.681 56.928 11.833 59.016 ;
     RECT  11.221 10.464 11.869 12.504 ;
     RECT  11.117 55.584 11.869 55.608 ;
     RECT  11.833 56.688 11.869 59.016 ;
     RECT  10.645 81.408 11.869 81.432 ;
     RECT  11.869 81.408 11.893 81.48 ;
     RECT  11.833 14.688 11.945 14.952 ;
     RECT  11.869 55.584 11.945 59.016 ;
     RECT  11.585 47.328 11.987 47.688 ;
     RECT  11.945 14.928 12.013 14.952 ;
     RECT  11.747 15.936 12.013 19.32 ;
     RECT  11.945 55.92 12.017 59.016 ;
     RECT  12.013 14.928 12.097 19.32 ;
     RECT  10.973 67.296 12.121 72.984 ;
     RECT  11.693 39.456 12.125 39.576 ;
     RECT  12.017 58.896 12.161 59.016 ;
     RECT  11.459 43.536 12.181 44.424 ;
     RECT  11.413 45.84 12.181 45.864 ;
     RECT  10.249 21.744 12.193 25.512 ;
     RECT  11.513 26.544 12.193 27.096 ;
     RECT  11.369 84.336 12.193 84.408 ;
     RECT  12.049 88.416 12.193 88.44 ;
     RECT  11.693 40.656 12.197 42.552 ;
     RECT  12.181 43.536 12.227 45.864 ;
     RECT  11.405 62.16 12.229 62.184 ;
     RECT  12.193 88.368 12.229 88.44 ;
     RECT  10.937 8.016 12.233 8.04 ;
     RECT  10.973 34.608 12.265 34.632 ;
     RECT  10.505 35.712 12.265 35.736 ;
     RECT  12.193 21.744 12.301 27.096 ;
     RECT  11.761 74.064 12.301 74.712 ;
     RECT  11.365 75.936 12.301 78.504 ;
     RECT  11.365 53.472 12.325 53.688 ;
     RECT  11.333 30.72 12.332 30.744 ;
     RECT  11.869 10.176 12.373 12.504 ;
     RECT  12.181 60.432 12.409 60.456 ;
     RECT  12.229 62.16 12.517 63.096 ;
     RECT  12.229 88.368 12.517 88.872 ;
     RECT  12.193 83.568 12.589 84.408 ;
     RECT  12.589 83.568 12.625 84.744 ;
     RECT  12.301 74.064 12.697 78.504 ;
     RECT  12.125 39.456 12.769 39.48 ;
     RECT  12.121 67.296 12.769 73.032 ;
     RECT  12.697 74.016 12.769 78.504 ;
     RECT  12.553 80.256 12.769 80.28 ;
     RECT  12.769 80.064 12.913 80.28 ;
     RECT  11.653 6.096 12.949 6.6 ;
     RECT  11.893 81.408 12.949 82.488 ;
     RECT  12.625 83.568 12.949 84.888 ;
     RECT  12.373 10.128 12.985 12.504 ;
     RECT  12.227 44.112 12.985 45.864 ;
     RECT  11.987 47.664 12.985 47.688 ;
     RECT  12.409 60.432 12.985 60.984 ;
     RECT  12.517 62.16 12.985 63.816 ;
     RECT  12.301 21.12 13.021 27.096 ;
     RECT  12.017 55.92 13.021 57.624 ;
     RECT  12.097 14.928 13.093 14.952 ;
     RECT  12.097 16.032 13.093 19.32 ;
     RECT  12.769 67.296 13.093 78.504 ;
     RECT  12.913 79.776 13.093 80.28 ;
     RECT  12.949 81.408 13.093 84.888 ;
     RECT  12.985 10.128 13.165 12.6 ;
     RECT  10.973 32.784 13.201 33 ;
     RECT  12.949 6.096 13.208 6.888 ;
     RECT  12.697 8.544 13.208 8.808 ;
     RECT  13.165 9.888 13.208 12.6 ;
     RECT  12.985 13.824 13.208 13.848 ;
     RECT  13.093 14.928 13.208 19.32 ;
     RECT  13.021 21.12 13.208 27.384 ;
     RECT  12.877 28.992 13.208 29.016 ;
     RECT  12.332 30.72 13.208 30.84 ;
     RECT  13.201 32.784 13.208 33.096 ;
     RECT  12.265 34.608 13.208 35.736 ;
     RECT  12.373 37.056 13.208 37.08 ;
     RECT  12.769 39.216 13.208 39.48 ;
     RECT  12.197 40.8 13.208 42.552 ;
     RECT  12.985 44.112 13.208 47.688 ;
     RECT  11.513 49.296 13.208 51.816 ;
     RECT  12.325 52.992 13.208 53.688 ;
     RECT  13.021 55.92 13.208 57.672 ;
     RECT  12.161 58.992 13.208 59.016 ;
     RECT  12.985 60.432 13.208 63.816 ;
     RECT  11.513 65.568 13.208 65.592 ;
     RECT  13.093 67.296 13.208 80.28 ;
     RECT  13.093 81.312 13.208 84.936 ;
     RECT  12.517 88.368 13.208 88.92 ;
     RECT  12.949 90.048 13.208 90.072 ;
     RECT  13.208 2.148 13.312 92.892 ;
     RECT  13.312 2.418 13.504 92.622 ;
     RECT  13.504 28.992 13.565 29.016 ;
     RECT  13.504 88.368 13.601 90.552 ;
     RECT  13.504 61.632 13.637 61.656 ;
     RECT  13.504 83.472 13.637 87.288 ;
     RECT  13.504 56.88 13.673 58.92 ;
     RECT  13.504 2.592 13.709 2.616 ;
     RECT  13.504 21.744 13.709 25.272 ;
     RECT  13.673 57.648 13.709 58.92 ;
     RECT  13.504 62.688 13.709 64.392 ;
     RECT  13.709 21.744 13.781 25.224 ;
     RECT  13.504 40.848 13.781 42.552 ;
     RECT  13.504 46.368 13.781 51.816 ;
     RECT  13.637 83.472 13.781 84.12 ;
     RECT  13.504 26.256 13.817 27.384 ;
     RECT  13.504 67.296 13.817 82.488 ;
     RECT  13.637 85.488 13.825 87.288 ;
     RECT  13.781 21.744 13.853 25.176 ;
     RECT  13.504 34.704 13.853 36.648 ;
     RECT  13.504 53.568 13.859 54.504 ;
     RECT  13.504 92.16 13.955 92.184 ;
     RECT  13.859 53.952 13.961 54.504 ;
     RECT  13.853 34.704 14.003 35.736 ;
     RECT  13.504 44.208 14.033 45.192 ;
     RECT  13.781 46.704 14.033 51.816 ;
     RECT  13.817 68.064 14.069 82.488 ;
     RECT  13.709 62.688 14.105 63.096 ;
     RECT  13.504 55.776 14.177 55.896 ;
     RECT  13.817 26.256 14.285 27.096 ;
     RECT  13.504 65.568 14.285 66.12 ;
     RECT  14.069 68.064 14.285 72.84 ;
     RECT  13.825 85.536 14.285 87.288 ;
     RECT  13.504 14.64 14.357 18.84 ;
     RECT  13.853 21.744 14.357 25.032 ;
     RECT  14.177 55.776 14.357 55.8 ;
     RECT  14.069 74.064 14.393 82.488 ;
     RECT  13.781 83.472 14.429 84.024 ;
     RECT  14.033 46.704 14.473 51.72 ;
     RECT  13.504 4.32 14.485 4.92 ;
     RECT  13.504 37.872 14.497 37.896 ;
     RECT  14.285 87.264 14.497 87.288 ;
     RECT  13.504 39.216 14.501 39.24 ;
     RECT  14.485 3.408 14.531 4.92 ;
     RECT  13.601 89.52 14.533 90.552 ;
     RECT  14.393 74.064 14.537 75.24 ;
     RECT  14.533 89.52 14.573 90.792 ;
     RECT  13.504 6.144 14.605 13.08 ;
     RECT  13.961 54.432 14.605 54.504 ;
     RECT  14.497 87.264 14.605 87.336 ;
     RECT  13.601 88.368 14.605 88.392 ;
     RECT  14.533 60.384 14.641 60.408 ;
     RECT  14.573 90.672 14.641 90.792 ;
     RECT  14.605 6.144 14.677 13.368 ;
     RECT  14.605 87.264 14.677 88.392 ;
     RECT  14.573 89.52 14.677 89.544 ;
     RECT  14.641 90.672 14.677 90.84 ;
     RECT  14.285 26.256 14.681 26.28 ;
     RECT  13.709 64.368 14.713 64.392 ;
     RECT  14.285 85.536 14.725 85.944 ;
     RECT  13.781 41.136 14.732 42.552 ;
     RECT  14.713 63.84 14.753 64.392 ;
     RECT  14.677 87.264 14.753 89.544 ;
     RECT  14.531 4.896 14.819 4.92 ;
     RECT  14.393 76.272 14.819 82.488 ;
     RECT  14.677 90.672 14.821 91.032 ;
     RECT  14.357 14.64 14.825 18.264 ;
     RECT  13.504 31.632 14.861 33.624 ;
     RECT  13.709 58.032 14.893 58.92 ;
     RECT  14.357 23.904 14.897 25.032 ;
     RECT  14.285 68.256 14.897 72.84 ;
     RECT  14.605 54.432 14.929 54.696 ;
     RECT  14.677 6.144 14.965 13.416 ;
     RECT  14.003 34.896 14.965 35.736 ;
     RECT  14.732 41.136 14.965 42.792 ;
     RECT  14.531 3.408 15.001 3.432 ;
     RECT  14.965 34.752 15.001 35.736 ;
     RECT  14.497 37.584 15.001 37.896 ;
     RECT  14.897 68.352 15.005 72.84 ;
     RECT  15.001 34.752 15.011 37.896 ;
     RECT  14.285 65.712 15.011 66.12 ;
     RECT  14.605 28.416 15.037 28.44 ;
     RECT  15.001 2.832 15.041 3.432 ;
     RECT  14.929 53.184 15.041 54.744 ;
     RECT  15.037 27.84 15.077 28.44 ;
     RECT  14.473 47.664 15.077 51.72 ;
     RECT  14.753 87.312 15.077 89.544 ;
     RECT  14.821 90.672 15.077 91.56 ;
     RECT  15.011 65.76 15.107 66.12 ;
     RECT  14.861 33.6 15.109 33.624 ;
     RECT  15.011 34.752 15.109 36.648 ;
     RECT  14.725 85.92 15.113 85.944 ;
     RECT  15.077 90.672 15.113 91.512 ;
     RECT  13.504 30.048 15.145 30.216 ;
     RECT  14.861 31.632 15.145 32.616 ;
     RECT  15.041 53.184 15.149 54.504 ;
     RECT  15.005 68.352 15.149 71.16 ;
     RECT  15.077 87.312 15.149 89.208 ;
     RECT  15.113 90.768 15.149 91.512 ;
     RECT  14.965 6.144 15.181 13.656 ;
     RECT  14.825 14.64 15.181 17.208 ;
     RECT  15.145 30.048 15.181 32.616 ;
     RECT  14.537 74.064 15.185 75 ;
     RECT  15.149 89.136 15.185 89.208 ;
     RECT  14.897 23.904 15.221 24.936 ;
     RECT  15.077 27.84 15.221 28.008 ;
     RECT  15.221 27.84 15.253 27.96 ;
     RECT  15.149 54.048 15.257 54.504 ;
     RECT  14.965 41.136 15.293 43.176 ;
     RECT  14.825 18.24 15.325 18.264 ;
     RECT  15.109 33.6 15.329 36.648 ;
     RECT  14.033 44.208 15.329 44.472 ;
     RECT  14.773 45.84 15.349 45.864 ;
     RECT  15.257 54.048 15.365 54.12 ;
     RECT  15.005 72.192 15.397 72.84 ;
     RECT  15.185 74.064 15.397 74.856 ;
     RECT  14.429 83.616 15.401 84.024 ;
     RECT  15.011 37.824 15.433 37.896 ;
     RECT  15.293 41.616 15.436 43.176 ;
     RECT  15.181 6.144 15.437 17.208 ;
     RECT  14.929 39.744 15.437 39.912 ;
     RECT  15.349 45.6 15.509 45.864 ;
     RECT  15.149 68.352 15.509 70.92 ;
     RECT  14.893 57.984 15.577 58.92 ;
     RECT  14.641 59.952 15.577 60.408 ;
     RECT  15.437 6.144 15.581 16.776 ;
     RECT  15.509 68.496 15.581 70.92 ;
     RECT  14.357 21.744 15.589 22.584 ;
     RECT  15.577 57.984 15.617 60.408 ;
     RECT  14.753 63.84 15.653 63.864 ;
     RECT  15.401 84 15.721 84.024 ;
     RECT  15.721 84 15.724 84.984 ;
     RECT  15.397 72.192 15.731 74.856 ;
     RECT  14.105 62.688 15.757 62.712 ;
     RECT  14.819 76.272 15.761 82.152 ;
     RECT  15.185 89.184 15.797 89.208 ;
     RECT  15.325 18.24 15.829 18.648 ;
     RECT  15.365 54.096 15.833 54.12 ;
     RECT  15.731 72.24 15.833 74.856 ;
     RECT  15.833 72.528 15.905 74.856 ;
     RECT  15.581 69.216 15.941 70.92 ;
     RECT  15.581 9.024 15.971 16.776 ;
     RECT  15.829 18.24 15.973 18.696 ;
     RECT  15.589 21.648 15.973 22.584 ;
     RECT  15.757 62.688 15.973 63.288 ;
     RECT  15.581 6.144 16.013 7.608 ;
     RECT  14.749 20.16 16.013 20.184 ;
     RECT  15.941 69.216 16.013 69.768 ;
     RECT  15.149 90.816 16.013 91.512 ;
     RECT  15.905 72.72 16.049 74.856 ;
     RECT  15.761 76.272 16.049 76.92 ;
     RECT  15.107 66.096 16.085 66.12 ;
     RECT  15.724 84.384 16.157 84.984 ;
     RECT  15.253 27.312 16.189 27.96 ;
     RECT  15.077 47.664 16.189 47.88 ;
     RECT  15.509 45.84 16.213 45.864 ;
     RECT  16.189 47.28 16.213 47.88 ;
     RECT  16.213 45.84 16.259 47.88 ;
     RECT  16.259 46.08 16.3 47.88 ;
     RECT  15.973 21.648 16.301 22.824 ;
     RECT  16.049 73.488 16.301 74.856 ;
     RECT  16.189 27.264 16.333 27.96 ;
     RECT  15.617 58.032 16.337 60.408 ;
     RECT  16.3 47.28 16.357 47.88 ;
     RECT  15.077 49.296 16.357 51.72 ;
     RECT  16.333 26.88 16.364 27.96 ;
     RECT  15.181 29.088 16.364 32.616 ;
     RECT  16.357 47.28 16.403 51.72 ;
     RECT  15.329 34.032 16.405 36.648 ;
     RECT  15.433 37.824 16.405 38.376 ;
     RECT  16.364 26.88 16.445 32.616 ;
     RECT  16.405 34.032 16.445 38.376 ;
     RECT  16.445 27.216 16.451 32.616 ;
     RECT  15.437 39.744 16.481 39.768 ;
     RECT  16.013 91.296 16.481 91.512 ;
     RECT  15.436 41.616 16.501 42.456 ;
     RECT  15.149 88.032 16.517 88.056 ;
     RECT  16.501 41.616 16.547 42.84 ;
     RECT  16.301 73.488 16.553 74.616 ;
     RECT  16.451 29.184 16.597 32.616 ;
     RECT  16.445 34.032 16.597 35.736 ;
     RECT  16.445 37.008 16.621 38.376 ;
     RECT  15.221 24.576 16.657 24.936 ;
     RECT  16.621 37.008 16.661 39.24 ;
     RECT  16.513 4.176 16.693 4.2 ;
     RECT  15.941 70.8 16.693 70.92 ;
     RECT  15.761 77.904 16.693 82.152 ;
     RECT  15.971 9.024 16.697 16.632 ;
     RECT  16.697 9.024 16.769 9.048 ;
     RECT  16.597 29.184 16.787 35.736 ;
     RECT  16.693 77.904 16.837 82.2 ;
     RECT  16.697 10.32 16.841 16.632 ;
     RECT  16.013 69.216 16.873 69.528 ;
     RECT  16.837 77.616 16.913 82.2 ;
     RECT  15.973 18.24 16.981 18.936 ;
     RECT  16.657 24.48 16.981 24.936 ;
     RECT  16.873 68.64 16.981 69.528 ;
     RECT  16.693 70.8 16.981 71.208 ;
     RECT  16.661 37.008 16.985 37.896 ;
     RECT  16.981 68.64 16.988 71.208 ;
     RECT  16.337 58.896 17.021 60.408 ;
     RECT  16.013 6.144 17.053 6.792 ;
     RECT  15.973 61.44 17.053 63.288 ;
     RECT  17.017 8.304 17.089 8.328 ;
     RECT  16.049 76.272 17.089 76.296 ;
     RECT  16.913 77.616 17.089 78.696 ;
     RECT  16.913 79.728 17.089 82.2 ;
     RECT  16.841 10.368 17.093 16.632 ;
     RECT  17.089 76.272 17.093 78.696 ;
     RECT  17.089 79.728 17.093 83.496 ;
     RECT  16.981 24.48 17.123 25.128 ;
     RECT  16.981 65.76 17.125 65.784 ;
     RECT  17.093 83.088 17.125 83.496 ;
     RECT  16.988 68.256 17.129 71.208 ;
     RECT  17.125 83.088 17.201 84.072 ;
     RECT  16.981 18.24 17.237 18.984 ;
     RECT  16.301 21.648 17.237 22.584 ;
     RECT  17.125 65.712 17.237 65.784 ;
     RECT  16.403 47.664 17.267 51.72 ;
     RECT  15.901 67.2 17.269 67.224 ;
     RECT  17.129 68.256 17.269 69.528 ;
     RECT  17.269 67.2 17.273 69.528 ;
     RECT  17.125 41.376 17.309 41.4 ;
     RECT  17.093 76.272 17.309 76.92 ;
     RECT  17.305 21.12 17.389 21.144 ;
     RECT  17.021 58.896 17.413 58.92 ;
     RECT  16.553 74.064 17.413 74.616 ;
     RECT  17.269 89.856 17.449 89.88 ;
     RECT  17.161 86.64 17.459 86.664 ;
     RECT  16.693 4.176 17.489 4.44 ;
     RECT  17.089 85.44 17.5 85.464 ;
     RECT  17.053 61.44 17.521 63.624 ;
     RECT  17.237 65.76 17.521 65.784 ;
     RECT  17.273 67.2 17.521 69 ;
     RECT  17.377 72.672 17.521 72.792 ;
     RECT  17.413 74.064 17.521 74.904 ;
     RECT  15.041 2.832 17.555 2.856 ;
     RECT  17.237 22.56 17.557 22.584 ;
     RECT  17.521 72.672 17.557 74.904 ;
     RECT  16.787 29.232 17.593 35.736 ;
     RECT  17.593 29.232 17.603 35.88 ;
     RECT  16.661 39.024 17.605 39.24 ;
     RECT  17.603 31.92 17.66 35.88 ;
     RECT  16.985 37.008 17.66 37.656 ;
     RECT  17.129 70.656 17.701 71.208 ;
     RECT  17.557 72.24 17.701 74.904 ;
     RECT  15.329 44.208 17.737 44.424 ;
     RECT  17.605 39.024 17.804 39.576 ;
     RECT  17.021 59.904 17.809 60.408 ;
     RECT  17.521 61.44 17.809 64.056 ;
     RECT  17.267 47.664 17.845 47.688 ;
     RECT  17.093 78.144 17.953 78.696 ;
     RECT  17.093 79.728 17.953 81.96 ;
     RECT  16.451 27.216 17.989 28.152 ;
     RECT  17.603 29.232 17.989 30.936 ;
     RECT  17.509 4.608 18.025 4.632 ;
     RECT  17.989 27.216 18.025 30.936 ;
     RECT  17.089 8.016 18.061 8.328 ;
     RECT  17.485 57.6 18.125 57.624 ;
     RECT  17.413 58.656 18.125 58.92 ;
     RECT  16.3 46.08 18.169 46.152 ;
     RECT  17.449 89.28 18.169 89.88 ;
     RECT  17.237 18.912 18.205 18.984 ;
     RECT  17.804 38.64 18.205 39.576 ;
     RECT  17.053 6.144 18.277 6.936 ;
     RECT  18.061 7.92 18.277 8.328 ;
     RECT  18.025 27.024 18.277 30.936 ;
     RECT  17.521 65.76 18.38 69 ;
     RECT  18.277 6.144 18.385 8.328 ;
     RECT  17.309 76.272 18.385 76.296 ;
     RECT  17.917 85.776 18.421 85.8 ;
     RECT  17.629 86.832 18.421 86.856 ;
     RECT  17.557 22.56 18.457 23.208 ;
     RECT  17.123 24.48 18.457 25.032 ;
     RECT  18.277 26.112 18.457 30.936 ;
     RECT  18.205 18.912 18.493 19.896 ;
     RECT  18.421 3.6 18.608 3.624 ;
     RECT  18.025 4.608 18.608 4.776 ;
     RECT  18.385 5.808 18.608 8.328 ;
     RECT  17.093 10.368 18.608 16.536 ;
     RECT  17.269 17.712 18.608 17.736 ;
     RECT  18.493 18.72 18.608 19.896 ;
     RECT  18.457 20.928 18.608 20.952 ;
     RECT  18.457 22.032 18.608 23.304 ;
     RECT  18.457 24.48 18.608 30.936 ;
     RECT  17.66 31.92 18.608 37.656 ;
     RECT  18.205 38.64 18.608 40.056 ;
     RECT  18.061 41.088 18.608 41.112 ;
     RECT  16.547 42.816 18.608 42.84 ;
     RECT  17.737 43.824 18.608 44.424 ;
     RECT  18.169 45.984 18.608 46.152 ;
     RECT  17.845 47.28 18.608 47.688 ;
     RECT  17.267 49.008 18.608 51.72 ;
     RECT  16.189 53.088 18.608 53.112 ;
     RECT  17.809 55.728 18.608 55.752 ;
     RECT  18.125 57.6 18.608 58.92 ;
     RECT  17.809 59.904 18.608 64.056 ;
     RECT  18.38 65.76 18.608 69.384 ;
     RECT  17.701 70.656 18.608 74.904 ;
     RECT  18.385 75.936 18.608 76.968 ;
     RECT  17.953 78.144 18.608 81.96 ;
     RECT  17.201 83.232 18.608 84.072 ;
     RECT  18.421 85.776 18.608 86.856 ;
     RECT  18.169 89.28 18.608 90.024 ;
     RECT  18.421 94.896 18.707 94.92 ;
     RECT  18.608 2.148 18.712 92.892 ;
     RECT  18.712 2.418 18.904 92.622 ;
     RECT  18.904 45.888 18.965 46.008 ;
     RECT  18.904 4.752 19.037 7.944 ;
     RECT  18.904 69.984 19.037 72.456 ;
     RECT  18.904 52.848 19.043 55.8 ;
     RECT  18.904 75.792 19.043 76.68 ;
     RECT  18.904 8.976 19.073 17.496 ;
     RECT  18.904 66 19.073 68.664 ;
     RECT  19.073 66 19.109 68.136 ;
     RECT  19.037 69.984 19.109 72.264 ;
     RECT  19.109 66.768 19.145 68.136 ;
     RECT  18.904 3.6 19.181 3.72 ;
     RECT  18.904 77.664 19.187 80.28 ;
     RECT  18.904 63.6 19.217 64.92 ;
     RECT  19.181 3.6 19.253 3.624 ;
     RECT  18.904 18.72 19.361 20.328 ;
     RECT  19.145 67.008 19.397 68.136 ;
     RECT  19.043 52.848 19.427 54.984 ;
     RECT  18.904 35.328 19.505 40.488 ;
     RECT  18.904 57.168 19.577 61.08 ;
     RECT  19.577 57.168 19.619 59.448 ;
     RECT  19.577 61.008 19.621 61.08 ;
     RECT  19.037 4.752 19.721 7.608 ;
     RECT  18.904 83.04 19.793 83.256 ;
     RECT  19.427 52.848 19.865 53.592 ;
     RECT  18.904 84.336 19.897 88.92 ;
     RECT  18.904 21.648 19.916 23.352 ;
     RECT  18.904 24.672 19.916 33.72 ;
     RECT  18.904 81.6 19.933 81.624 ;
     RECT  19.073 9.072 19.937 17.496 ;
     RECT  19.187 78.768 19.937 80.28 ;
     RECT  19.505 36.912 19.957 40.488 ;
     RECT  18.904 41.616 19.957 41.64 ;
     RECT  18.904 90 19.957 90.696 ;
     RECT  19.933 81.6 19.969 82.056 ;
     RECT  19.427 54.96 19.973 54.984 ;
     RECT  19.621 61.056 20.009 61.08 ;
     RECT  18.904 62.496 20.041 62.52 ;
     RECT  19.217 63.6 20.041 63.624 ;
     RECT  19.619 57.312 20.045 59.448 ;
     RECT  18.904 74.592 20.045 74.616 ;
     RECT  19.957 90 20.053 90.744 ;
     RECT  18.904 92.016 20.053 92.424 ;
     RECT  18.904 43.824 20.077 44.616 ;
     RECT  18.965 45.888 20.077 45.912 ;
     RECT  19.916 21.648 20.092 33.72 ;
     RECT  20.041 62.496 20.113 63.624 ;
     RECT  19.043 76.272 20.113 76.68 ;
     RECT  20.092 21.648 20.125 22.968 ;
     RECT  20.113 62.4 20.149 63.624 ;
     RECT  19.957 36.912 20.153 41.64 ;
     RECT  19.397 67.008 20.153 67.032 ;
     RECT  19.937 9.072 20.189 9.144 ;
     RECT  19.937 10.176 20.189 17.496 ;
     RECT  20.077 43.824 20.189 45.912 ;
     RECT  19.897 83.664 20.189 88.92 ;
     RECT  20.092 23.952 20.221 33.72 ;
     RECT  19.505 35.328 20.221 35.832 ;
     RECT  19.109 69.984 20.221 72.024 ;
     RECT  20.189 44.064 20.245 45.912 ;
     RECT  18.904 47.184 20.245 47.88 ;
     RECT  20.149 61.632 20.293 63.624 ;
     RECT  19.217 64.656 20.293 64.92 ;
     RECT  19.397 68.064 20.293 68.136 ;
     RECT  20.189 10.368 20.333 17.496 ;
     RECT  20.153 40.992 20.339 41.64 ;
     RECT  19.969 81.6 20.339 82.68 ;
     RECT  20.189 86.064 20.387 88.92 ;
     RECT  19.187 77.664 20.389 77.688 ;
     RECT  19.937 78.768 20.389 80.232 ;
     RECT  20.293 61.632 20.401 64.92 ;
     RECT  20.113 75.792 20.437 76.68 ;
     RECT  20.389 77.664 20.437 80.232 ;
     RECT  20.153 36.912 20.441 39.912 ;
     RECT  20.441 36.912 20.473 38.712 ;
     RECT  20.293 68.064 20.473 68.952 ;
     RECT  20.339 40.992 20.483 41.4 ;
     RECT  20.053 90 20.483 92.424 ;
     RECT  20.401 61.632 20.509 64.968 ;
     RECT  20.437 75.792 20.531 80.232 ;
     RECT  20.221 23.952 20.533 35.832 ;
     RECT  20.473 36.816 20.533 38.712 ;
     RECT  20.125 21.648 20.557 22.824 ;
     RECT  20.509 61.632 20.617 65.256 ;
     RECT  20.533 23.952 20.621 38.712 ;
     RECT  20.245 44.064 20.621 47.88 ;
     RECT  20.483 90 20.657 91.656 ;
     RECT  20.531 75.792 20.693 79.848 ;
     RECT  20.621 26.64 20.729 37.032 ;
     RECT  20.693 78.096 20.729 79.848 ;
     RECT  20.441 39.744 20.737 39.912 ;
     RECT  20.387 88.896 20.773 88.92 ;
     RECT  20.657 90 20.773 91.32 ;
     RECT  20.339 81.648 20.797 82.68 ;
     RECT  20.189 83.664 20.797 84.408 ;
     RECT  20.621 46.224 20.801 47.88 ;
     RECT  20.473 67.536 20.821 68.952 ;
     RECT  20.221 69.984 20.821 72.408 ;
     RECT  20.729 26.64 20.837 26.664 ;
     RECT  20.045 57.312 20.869 58.92 ;
     RECT  20.821 67.536 20.909 72.408 ;
     RECT  19.721 4.752 21.013 7.56 ;
     RECT  21.013 4.752 21.049 7.608 ;
     RECT  20.693 75.792 21.155 76.92 ;
     RECT  21.049 4.752 21.157 7.992 ;
     RECT  20.189 9.12 21.157 9.144 ;
     RECT  20.387 86.064 21.193 87.864 ;
     RECT  20.869 57.024 21.265 58.92 ;
     RECT  21.049 60.48 21.265 60.504 ;
     RECT  20.617 61.632 21.269 65.4 ;
     RECT  20.797 81.648 21.337 84.408 ;
     RECT  21.193 85.488 21.337 87.864 ;
     RECT  21.269 61.632 21.341 63.48 ;
     RECT  20.557 21.648 21.373 22.776 ;
     RECT  18.904 49.296 21.373 51.72 ;
     RECT  20.729 27.648 21.377 37.032 ;
     RECT  21.155 75.84 21.385 76.92 ;
     RECT  21.265 57.024 21.413 60.504 ;
     RECT  21.373 21.168 21.517 22.776 ;
     RECT  21.269 64.656 21.589 65.4 ;
     RECT  21.337 81.648 21.589 87.864 ;
     RECT  20.773 88.896 21.589 91.32 ;
     RECT  21.385 76.896 21.593 76.92 ;
     RECT  20.801 46.32 21.625 47.88 ;
     RECT  21.373 49.152 21.625 51.72 ;
     RECT  21.589 81.648 21.625 91.32 ;
     RECT  20.621 44.064 21.661 44.472 ;
     RECT  20.909 69.984 21.661 72.408 ;
     RECT  20.221 74.016 21.661 74.04 ;
     RECT  20.333 10.368 21.685 17.208 ;
     RECT  20.621 23.952 21.697 25.32 ;
     RECT  21.697 76.944 21.733 77.112 ;
     RECT  20.729 78.096 21.733 79.512 ;
     RECT  21.413 57.024 21.737 60.072 ;
     RECT  19.361 18.72 21.773 19.608 ;
     RECT  21.773 18.768 21.841 19.608 ;
     RECT  20.113 55.872 21.877 55.896 ;
     RECT  21.733 76.944 21.877 79.512 ;
     RECT  21.625 80.88 21.877 91.32 ;
     RECT  21.685 10.368 21.881 17.448 ;
     RECT  20.909 67.536 21.913 69 ;
     RECT  21.661 69.984 21.913 74.04 ;
     RECT  21.341 61.632 21.953 63.288 ;
     RECT  21.517 21.12 22.021 22.776 ;
     RECT  21.697 23.904 22.021 25.32 ;
     RECT  21.377 27.744 22.057 37.032 ;
     RECT  21.877 76.944 22.097 79.8 ;
     RECT  21.877 80.784 22.097 91.32 ;
     RECT  22.021 21.12 22.129 25.32 ;
     RECT  21.949 26.304 22.129 26.328 ;
     RECT  19.865 53.568 22.129 53.592 ;
     RECT  22.097 76.944 22.211 79.272 ;
     RECT  21.841 18.768 22.213 19.944 ;
     RECT  22.129 21.12 22.213 26.328 ;
     RECT  21.589 64.656 22.237 66.024 ;
     RECT  21.385 75.84 22.261 75.912 ;
     RECT  20.725 3.408 22.268 3.432 ;
     RECT  22.097 84.96 22.273 91.32 ;
     RECT  21.953 61.632 22.277 63.144 ;
     RECT  22.268 3.216 22.309 3.432 ;
     RECT  21.157 4.752 22.309 9.144 ;
     RECT  20.621 38.688 22.313 38.712 ;
     RECT  21.913 67.536 22.348 74.04 ;
     RECT  22.213 18.768 22.349 26.328 ;
     RECT  22.211 76.944 22.349 79.224 ;
     RECT  22.309 3.216 22.355 9.144 ;
     RECT  22.273 84.96 22.355 91.512 ;
     RECT  22.237 64.656 22.453 66.168 ;
     RECT  22.348 67.536 22.453 73.656 ;
     RECT  21.661 44.064 22.489 44.664 ;
     RECT  22.097 80.784 22.489 83.88 ;
     RECT  22.489 44.064 22.525 44.76 ;
     RECT  22.355 87.168 22.525 91.512 ;
     RECT  22.525 44.064 22.561 44.856 ;
     RECT  20.737 39.744 22.597 39.768 ;
     RECT  20.483 40.992 22.597 41.016 ;
     RECT  22.561 44.064 22.597 44.952 ;
     RECT  22.261 75.216 22.597 75.912 ;
     RECT  22.597 75.216 22.645 76.488 ;
     RECT  18.904 42.816 22.669 42.84 ;
     RECT  22.349 18.768 22.673 26.232 ;
     RECT  22.057 27.744 22.705 37.416 ;
     RECT  22.355 3.408 22.777 9.144 ;
     RECT  22.597 43.872 22.777 44.952 ;
     RECT  22.453 64.656 22.781 73.656 ;
     RECT  22.781 64.656 22.787 69.624 ;
     RECT  22.597 39.216 22.813 41.016 ;
     RECT  22.669 42.24 22.813 42.84 ;
     RECT  22.777 43.872 22.813 45.048 ;
     RECT  22.129 53.568 22.813 54.312 ;
     RECT  21.877 55.872 22.813 56.04 ;
     RECT  22.705 27.744 22.844 37.752 ;
     RECT  21.625 46.32 22.849 51.72 ;
     RECT  22.673 19.344 22.853 26.232 ;
     RECT  22.813 53.568 22.853 56.04 ;
     RECT  22.813 39.216 22.885 41.112 ;
     RECT  22.853 53.808 22.897 56.04 ;
     RECT  22.885 39.216 22.921 41.208 ;
     RECT  22.813 42.24 22.921 45.048 ;
     RECT  22.849 46.176 22.921 51.72 ;
     RECT  22.844 27.216 22.931 37.752 ;
     RECT  22.853 19.344 22.961 23.304 ;
     RECT  22.897 53.808 22.961 54.312 ;
     RECT  22.787 64.656 23.027 69.48 ;
     RECT  21.737 57.024 23.173 59.832 ;
     RECT  22.669 60.96 23.173 61.224 ;
     RECT  22.489 80.4 23.173 83.88 ;
     RECT  22.355 84.96 23.173 86.04 ;
     RECT  22.277 62.496 23.281 63.144 ;
     RECT  22.781 70.656 23.317 73.656 ;
     RECT  22.645 74.64 23.317 76.488 ;
     RECT  23.173 80.4 23.353 86.04 ;
     RECT  22.921 39.216 23.365 51.72 ;
     RECT  22.349 77.856 23.389 79.224 ;
     RECT  22.525 87.168 23.389 92.376 ;
     RECT  23.317 70.656 23.413 76.488 ;
     RECT  23.389 77.52 23.413 79.224 ;
     RECT  23.353 80.304 23.533 86.04 ;
     RECT  23.389 87.168 23.533 92.424 ;
     RECT  23.027 64.656 23.713 68.136 ;
     RECT  23.027 69.216 23.785 69.48 ;
     RECT  23.413 70.656 23.785 79.224 ;
     RECT  21.881 10.464 23.821 17.448 ;
     RECT  23.821 10.464 23.857 18.36 ;
     RECT  23.281 62.496 23.857 63.336 ;
     RECT  22.931 27.312 23.893 37.704 ;
     RECT  23.365 38.784 23.893 51.72 ;
     RECT  23.677 52.704 23.929 52.728 ;
     RECT  22.853 24.48 23.965 26.232 ;
     RECT  23.893 27.312 23.965 51.72 ;
     RECT  22.777 3.408 24.008 9.384 ;
     RECT  23.857 10.464 24.008 18.456 ;
     RECT  22.961 19.536 24.008 23.304 ;
     RECT  23.965 24.48 24.008 51.72 ;
     RECT  23.929 52.704 24.008 52.776 ;
     RECT  22.961 53.808 24.008 54.168 ;
     RECT  22.897 55.68 24.008 56.04 ;
     RECT  23.173 57.024 24.008 61.224 ;
     RECT  23.857 62.208 24.008 63.336 ;
     RECT  23.713 64.416 24.008 68.136 ;
     RECT  23.785 69.216 24.008 79.224 ;
     RECT  23.533 80.304 24.008 92.424 ;
     RECT  24.008 2.148 24.112 92.892 ;
     RECT  24.112 2.418 24.304 92.664 ;
     RECT  24.304 52.704 24.401 56.04 ;
     RECT  24.304 69.456 24.419 87.384 ;
     RECT  24.304 4.08 24.437 11.4 ;
     RECT  24.304 13.008 24.556 51.72 ;
     RECT  24.419 69.456 24.617 84.408 ;
     RECT  24.437 4.08 24.661 8.52 ;
     RECT  24.304 58.896 24.833 60.792 ;
     RECT  24.556 24.624 24.941 51.72 ;
     RECT  24.833 60.384 24.941 60.792 ;
     RECT  24.401 53.04 25.013 56.04 ;
     RECT  24.556 13.008 25.085 23.4 ;
     RECT  24.941 30.768 25.121 51.72 ;
     RECT  25.013 53.04 25.157 54.12 ;
     RECT  24.661 4.08 25.193 8.328 ;
     RECT  25.121 30.768 25.235 48.456 ;
     RECT  24.304 64.944 25.265 68.136 ;
     RECT  24.304 62.208 25.301 63.912 ;
     RECT  24.419 85.488 25.333 87.384 ;
     RECT  24.304 88.464 25.333 92.664 ;
     RECT  24.941 24.624 25.379 29.64 ;
     RECT  24.833 58.896 25.379 59.304 ;
     RECT  24.437 9.648 25.405 11.4 ;
     RECT  25.085 13.152 25.417 23.4 ;
     RECT  25.013 55.104 25.436 56.04 ;
     RECT  24.304 57.024 25.436 57.672 ;
     RECT  25.379 58.896 25.436 58.92 ;
     RECT  25.235 39.36 25.481 48.456 ;
     RECT  25.436 55.104 25.523 58.92 ;
     RECT  25.379 24.624 25.549 29.352 ;
     RECT  25.193 4.08 25.553 6.696 ;
     RECT  25.265 64.944 25.553 67.32 ;
     RECT  25.523 55.104 25.589 56.04 ;
     RECT  24.617 69.792 25.625 84.408 ;
     RECT  25.625 71.808 25.669 84.408 ;
     RECT  25.333 85.488 25.669 92.664 ;
     RECT  25.669 71.808 25.697 92.664 ;
     RECT  25.553 4.08 25.733 4.776 ;
     RECT  25.405 9.648 25.763 12.024 ;
     RECT  25.549 68.4 25.765 68.424 ;
     RECT  25.625 69.792 25.765 70.776 ;
     RECT  25.553 5.904 25.769 6.696 ;
     RECT  25.417 13.152 25.769 23.352 ;
     RECT  25.763 9.648 25.804 11.208 ;
     RECT  25.301 62.208 25.805 63.432 ;
     RECT  25.804 9.648 25.877 11.16 ;
     RECT  25.697 71.808 25.913 90.36 ;
     RECT  25.913 74.544 25.949 90.36 ;
     RECT  25.765 68.4 25.985 70.776 ;
     RECT  25.523 57.024 26.021 57.672 ;
     RECT  24.941 60.384 26.108 60.408 ;
     RECT  25.769 13.152 26.129 19.464 ;
     RECT  25.235 30.768 26.129 38.04 ;
     RECT  25.589 55.824 26.129 56.04 ;
     RECT  25.949 75.12 26.129 90.36 ;
     RECT  25.193 7.872 26.156 8.328 ;
     RECT  26.108 59.952 26.161 60.408 ;
     RECT  26.129 36.816 26.195 38.04 ;
     RECT  25.523 58.656 26.195 58.92 ;
     RECT  26.156 7.392 26.197 8.328 ;
     RECT  25.553 65.712 26.201 67.32 ;
     RECT  25.877 10.272 26.237 11.16 ;
     RECT  26.197 7.392 26.243 8.568 ;
     RECT  26.129 18.144 26.243 19.464 ;
     RECT  26.201 66.576 26.269 67.32 ;
     RECT  25.481 39.36 26.273 48.36 ;
     RECT  26.269 66.576 26.273 67.416 ;
     RECT  26.243 8.256 26.281 8.568 ;
     RECT  25.769 5.904 26.345 6.264 ;
     RECT  25.697 91.536 26.38 92.664 ;
     RECT  26.161 59.952 26.521 60.648 ;
     RECT  25.157 53.04 26.525 53.832 ;
     RECT  26.525 53.808 26.54 53.832 ;
     RECT  26.129 13.152 26.561 17.064 ;
     RECT  26.273 39.36 26.593 47.88 ;
     RECT  25.121 49.584 26.629 51.72 ;
     RECT  25.549 24.384 26.636 29.352 ;
     RECT  25.769 20.88 26.701 23.352 ;
     RECT  25.805 62.64 26.705 63.432 ;
     RECT  26.705 62.64 26.741 63.24 ;
     RECT  25.733 4.752 26.773 4.776 ;
     RECT  26.561 13.152 26.773 14.232 ;
     RECT  26.701 20.88 26.773 23.4 ;
     RECT  26.195 58.896 26.773 58.92 ;
     RECT  26.521 59.952 26.773 60.84 ;
     RECT  26.195 36.816 26.777 37.896 ;
     RECT  26.021 57.024 26.813 57.576 ;
     RECT  25.985 68.64 26.813 70.776 ;
     RECT  25.913 71.808 26.813 73.56 ;
     RECT  26.629 49.008 26.849 51.72 ;
     RECT  26.773 13.056 26.917 14.232 ;
     RECT  26.773 3.792 26.921 4.776 ;
     RECT  26.593 39.264 26.921 47.88 ;
     RECT  26.813 69.024 26.921 70.68 ;
     RECT  26.129 75.264 26.953 90.36 ;
     RECT  26.953 75.264 26.989 90.408 ;
     RECT  26.773 20.784 27.097 23.4 ;
     RECT  26.773 58.896 27.097 60.84 ;
     RECT  27.097 20.736 27.133 23.4 ;
     RECT  26.636 24.384 27.133 29.688 ;
     RECT  26.777 37.872 27.205 37.896 ;
     RECT  26.921 39.264 27.205 39.384 ;
     RECT  26.813 71.856 27.205 73.56 ;
     RECT  26.989 75.264 27.212 90.6 ;
     RECT  26.237 10.992 27.241 11.16 ;
     RECT  26.917 13.008 27.241 14.232 ;
     RECT  26.345 5.952 27.277 6.264 ;
     RECT  27.212 75.12 27.299 90.6 ;
     RECT  27.205 37.872 27.317 39.384 ;
     RECT  26.38 91.872 27.317 92.664 ;
     RECT  26.561 15.504 27.349 17.064 ;
     RECT  26.243 18.144 27.349 19.368 ;
     RECT  27.133 20.736 27.349 29.688 ;
     RECT  26.129 30.768 27.349 35.832 ;
     RECT  27.241 10.992 27.385 14.232 ;
     RECT  27.317 91.872 27.389 91.896 ;
     RECT  27.299 75.84 27.425 90.6 ;
     RECT  27.277 5.952 27.457 6.696 ;
     RECT  26.281 8.256 27.457 8.472 ;
     RECT  27.349 15.504 27.461 19.368 ;
     RECT  27.349 20.736 27.529 35.832 ;
     RECT  26.777 36.816 27.529 36.888 ;
     RECT  26.54 53.808 27.529 53.976 ;
     RECT  27.205 71.856 27.541 74.04 ;
     RECT  27.529 53.808 27.565 54.216 ;
     RECT  26.129 55.872 27.565 56.04 ;
     RECT  27.425 81.024 27.601 90.6 ;
     RECT  27.541 71.856 27.628 74.856 ;
     RECT  27.565 53.808 27.637 56.04 ;
     RECT  26.813 57.36 27.637 57.576 ;
     RECT  27.097 58.896 27.637 61.464 ;
     RECT  27.637 57.36 27.641 61.464 ;
     RECT  27.461 18.336 27.709 19.368 ;
     RECT  26.273 67.152 27.709 67.416 ;
     RECT  27.461 15.504 27.713 17.208 ;
     RECT  27.385 10.704 27.781 14.232 ;
     RECT  27.641 57.36 27.781 61.176 ;
     RECT  26.921 69.936 27.781 70.68 ;
     RECT  27.628 71.856 27.781 74.424 ;
     RECT  27.457 5.952 27.853 8.472 ;
     RECT  27.529 20.736 27.853 36.888 ;
     RECT  26.921 40.608 27.853 47.88 ;
     RECT  27.781 57.216 27.857 61.176 ;
     RECT  26.741 62.976 27.857 63.24 ;
     RECT  27.853 40.608 27.889 48.024 ;
     RECT  27.637 53.808 27.889 56.232 ;
     RECT  27.857 57.216 27.889 60.12 ;
     RECT  27.709 66.48 27.889 67.416 ;
     RECT  26.921 3.936 27.923 4.776 ;
     RECT  27.853 20.688 27.964 36.888 ;
     RECT  27.781 9.792 27.965 14.232 ;
     RECT  27.713 16.128 27.965 17.208 ;
     RECT  27.889 66.336 27.965 68.088 ;
     RECT  27.923 4.656 28.105 4.776 ;
     RECT  27.853 5.952 28.105 8.52 ;
     RECT  27.857 62.976 28.177 63.144 ;
     RECT  27.964 31.104 28.249 36.888 ;
     RECT  27.317 37.872 28.249 37.896 ;
     RECT  28.249 31.104 28.285 37.896 ;
     RECT  27.317 39.216 28.285 39.384 ;
     RECT  27.965 67.344 28.285 68.088 ;
     RECT  27.889 40.608 28.307 48.264 ;
     RECT  27.709 18.336 28.321 19.512 ;
     RECT  27.964 20.688 28.321 29.784 ;
     RECT  28.307 41.04 28.321 48.264 ;
     RECT  26.849 49.584 28.321 51.72 ;
     RECT  28.321 41.04 28.333 51.72 ;
     RECT  27.889 64.944 28.357 64.968 ;
     RECT  27.965 66.336 28.357 66.36 ;
     RECT  28.285 31.104 28.361 39.384 ;
     RECT  28.333 41.04 28.361 44.712 ;
     RECT  28.361 36.528 28.405 39.384 ;
     RECT  27.965 16.224 28.429 17.208 ;
     RECT  28.321 18.336 28.429 29.784 ;
     RECT  27.781 69.936 28.429 74.424 ;
     RECT  27.425 75.84 28.465 79.992 ;
     RECT  27.601 81.024 28.465 91.176 ;
     RECT  28.465 75.84 28.501 91.176 ;
     RECT  28.285 67.344 28.537 68.28 ;
     RECT  28.429 69.888 28.537 74.424 ;
     RECT  28.501 75.84 28.573 91.8 ;
     RECT  28.333 46.08 28.645 51.72 ;
     RECT  27.565 52.704 28.645 52.728 ;
     RECT  27.889 53.808 28.645 60.12 ;
     RECT  28.573 75.792 28.645 91.8 ;
     RECT  28.645 75.792 28.789 92.28 ;
     RECT  27.965 10.176 28.825 14.232 ;
     RECT  28.537 67.344 28.897 74.424 ;
     RECT  28.789 75.792 28.897 92.424 ;
     RECT  28.177 62.16 28.933 63.144 ;
     RECT  28.357 64.944 28.933 66.36 ;
     RECT  28.897 67.344 28.933 92.424 ;
     RECT  28.105 4.656 29.041 8.52 ;
     RECT  28.429 16.224 29.077 29.784 ;
     RECT  29.077 16.224 29.185 29.88 ;
     RECT  28.361 31.104 29.185 35.448 ;
     RECT  29.041 4.656 29.408 9.096 ;
     RECT  28.825 10.176 29.408 14.664 ;
     RECT  29.185 16.224 29.408 35.448 ;
     RECT  28.405 36.528 29.408 39.288 ;
     RECT  28.361 41.184 29.408 44.712 ;
     RECT  28.645 46.08 29.408 60.12 ;
     RECT  27.857 61.152 29.408 61.176 ;
     RECT  28.933 62.16 29.408 63.816 ;
     RECT  28.933 64.944 29.408 92.424 ;
     RECT  29.408 2.148 29.512 92.892 ;
     RECT  29.512 2.418 29.704 92.622 ;
     RECT  29.704 16.8 29.729 35.064 ;
     RECT  29.704 66.672 29.837 91.176 ;
     RECT  29.729 17.184 29.873 35.064 ;
     RECT  29.837 66.672 29.873 91.08 ;
     RECT  29.704 4.272 29.881 10.728 ;
     RECT  29.873 68.352 29.939 91.08 ;
     RECT  29.881 5.808 29.945 10.728 ;
     RECT  29.704 12.384 29.981 15.48 ;
     RECT  29.981 12.48 30.053 15.48 ;
     RECT  29.873 17.184 30.089 18.456 ;
     RECT  30.053 12.576 30.125 15.48 ;
     RECT  29.881 4.272 30.197 4.68 ;
     RECT  29.704 92.256 30.197 92.376 ;
     RECT  29.945 5.808 30.227 9.144 ;
     RECT  30.227 7.392 30.233 9.144 ;
     RECT  29.704 36.096 30.233 38.232 ;
     RECT  30.233 7.92 30.269 9.144 ;
     RECT  29.704 39.456 30.341 40.008 ;
     RECT  29.704 57.888 30.371 63.816 ;
     RECT  29.873 19.536 30.413 35.064 ;
     RECT  30.371 57.888 30.413 63.24 ;
     RECT  29.873 66.672 30.419 67.32 ;
     RECT  30.227 5.808 30.449 6.072 ;
     RECT  29.939 68.352 30.563 90.84 ;
     RECT  30.413 34.656 30.593 35.064 ;
     RECT  29.704 46.32 30.629 56.328 ;
     RECT  30.419 66.72 30.659 67.32 ;
     RECT  30.629 46.32 30.665 54.216 ;
     RECT  29.945 10.176 30.697 10.728 ;
     RECT  29.704 65.088 30.697 65.688 ;
     RECT  30.125 12.768 30.733 15.48 ;
     RECT  29.704 42.576 30.803 42.888 ;
     RECT  30.629 55.536 30.805 56.328 ;
     RECT  30.563 68.352 30.809 70.68 ;
     RECT  30.805 55.536 30.845 56.376 ;
     RECT  29.704 41.184 30.853 41.208 ;
     RECT  30.803 42.576 30.853 42.792 ;
     RECT  30.845 55.584 30.953 56.376 ;
     RECT  29.704 44.112 31.052 44.712 ;
     RECT  30.659 67.248 31.061 67.32 ;
     RECT  30.733 12.768 31.165 15.96 ;
     RECT  31.061 67.296 31.201 67.32 ;
     RECT  30.809 68.352 31.201 70.392 ;
     RECT  30.563 72.048 31.201 90.84 ;
     RECT  31.201 72.048 31.228 90.888 ;
     RECT  30.341 39.984 31.237 40.008 ;
     RECT  30.233 36.096 31.273 37.368 ;
     RECT  31.201 38.64 31.273 39 ;
     RECT  31.052 44.112 31.285 45.336 ;
     RECT  30.665 46.32 31.285 53.832 ;
     RECT  31.273 36.096 31.313 39 ;
     RECT  31.285 44.112 31.313 53.832 ;
     RECT  30.269 8.016 31.34 9.144 ;
     RECT  31.34 7.968 31.345 9.144 ;
     RECT  30.089 17.568 31.345 18.456 ;
     RECT  30.413 19.536 31.345 33.576 ;
     RECT  31.313 36.096 31.345 37.128 ;
     RECT  30.197 92.352 31.345 92.376 ;
     RECT  31.313 44.304 31.372 53.832 ;
     RECT  31.165 12.528 31.381 15.96 ;
     RECT  31.345 36.048 31.385 37.128 ;
     RECT  31.201 67.296 31.385 70.392 ;
     RECT  31.228 72.048 31.385 81.192 ;
     RECT  30.593 34.992 31.417 35.064 ;
     RECT  31.385 36.048 31.417 36.936 ;
     RECT  31.228 82.224 31.453 90.888 ;
     RECT  31.345 92.256 31.453 92.376 ;
     RECT  30.853 41.184 31.484 42.792 ;
     RECT  30.197 4.656 31.525 4.68 ;
     RECT  30.449 5.808 31.525 5.832 ;
     RECT  31.453 82.224 31.537 92.376 ;
     RECT  31.417 34.992 31.561 36.936 ;
     RECT  30.413 57.936 31.561 63.24 ;
     RECT  31.525 4.656 31.565 5.832 ;
     RECT  31.561 34.752 31.58 36.936 ;
     RECT  30.697 10.176 31.597 11.4 ;
     RECT  31.381 12.48 31.597 15.96 ;
     RECT  31.345 17.568 31.597 33.576 ;
     RECT  31.58 34.656 31.597 36.936 ;
     RECT  31.385 67.296 31.601 69.96 ;
     RECT  30.953 55.584 31.612 56.04 ;
     RECT  31.601 67.44 31.637 69.96 ;
     RECT  31.537 82.224 31.637 91.128 ;
     RECT  31.561 57.84 31.669 63.24 ;
     RECT  31.597 10.176 31.681 16.008 ;
     RECT  31.597 17.568 31.741 36.936 ;
     RECT  31.313 38.208 31.745 39 ;
     RECT  31.669 57.84 31.753 63.864 ;
     RECT  31.345 7.776 31.813 9.144 ;
     RECT  31.681 10.176 31.813 15.624 ;
     RECT  31.372 46.272 31.813 53.832 ;
     RECT  31.565 5.088 31.849 5.832 ;
     RECT  31.237 39.984 31.849 40.056 ;
     RECT  31.484 41.04 31.849 42.792 ;
     RECT  31.849 39.984 31.853 42.792 ;
     RECT  31.637 68.928 31.853 69.96 ;
     RECT  31.612 55.824 31.859 56.04 ;
     RECT  31.853 40.032 31.885 42.792 ;
     RECT  31.813 46.272 31.907 53.88 ;
     RECT  31.859 55.872 31.921 56.04 ;
     RECT  31.741 17.52 31.925 36.936 ;
     RECT  30.697 64.848 31.925 65.688 ;
     RECT  31.637 82.224 31.925 87.144 ;
     RECT  31.925 17.52 31.961 19.992 ;
     RECT  31.925 64.944 31.961 65.688 ;
     RECT  31.925 82.416 31.961 87.144 ;
     RECT  31.849 5.088 31.993 6.504 ;
     RECT  31.813 7.776 31.993 15.624 ;
     RECT  31.885 40.032 32.003 42.984 ;
     RECT  31.993 5.088 32.033 15.624 ;
     RECT  32.003 41.04 32.051 42.984 ;
     RECT  31.907 46.272 32.069 53.736 ;
     RECT  31.637 67.44 32.069 67.464 ;
     RECT  31.961 82.416 32.105 87.096 ;
     RECT  31.637 88.176 32.105 91.128 ;
     RECT  31.921 55.872 32.137 56.328 ;
     RECT  31.753 57.84 32.137 63.672 ;
     RECT  31.537 92.256 32.173 92.376 ;
     RECT  31.961 17.52 32.209 19.944 ;
     RECT  32.105 82.416 32.236 86.952 ;
     RECT  32.051 41.04 32.243 42.936 ;
     RECT  32.236 86.832 32.249 86.952 ;
     RECT  32.137 55.872 32.285 63.672 ;
     RECT  32.105 90 32.357 91.128 ;
     RECT  31.372 44.304 32.387 45.048 ;
     RECT  32.285 57.84 32.393 63.672 ;
     RECT  32.387 44.688 32.425 45.048 ;
     RECT  32.069 46.272 32.425 53.16 ;
     RECT  32.173 92.256 32.429 92.472 ;
     RECT  32.033 5.088 32.465 5.832 ;
     RECT  31.925 21.072 32.465 36.936 ;
     RECT  32.003 40.032 32.465 40.056 ;
     RECT  32.465 28.704 32.497 36.936 ;
     RECT  31.745 38.208 32.497 38.808 ;
     RECT  32.393 57.84 32.501 57.864 ;
     RECT  31.385 72.048 32.501 80.904 ;
     RECT  32.033 6.816 32.509 15.624 ;
     RECT  32.501 72.576 32.509 80.904 ;
     RECT  32.425 44.688 32.537 53.16 ;
     RECT  32.509 75.936 32.537 80.904 ;
     RECT  32.285 55.872 32.573 56.328 ;
     RECT  32.509 72.576 32.609 74.904 ;
     RECT  32.465 21.072 32.675 27.672 ;
     RECT  32.429 92.448 32.681 92.472 ;
     RECT  32.509 7.92 32.717 15.624 ;
     RECT  32.209 17.232 32.723 19.944 ;
     RECT  32.243 41.04 32.771 42.792 ;
     RECT  32.573 55.872 32.825 56.184 ;
     RECT  32.717 11.424 32.861 15.624 ;
     RECT  32.861 13.824 32.897 15.624 ;
     RECT  32.723 17.232 32.917 19.896 ;
     RECT  32.897 13.824 32.963 15.432 ;
     RECT  32.861 11.424 33.005 12.744 ;
     RECT  32.917 16.464 33.005 19.896 ;
     RECT  32.497 28.704 33.013 38.808 ;
     RECT  32.857 67.68 33.037 67.704 ;
     RECT  31.853 69.072 33.037 69.96 ;
     RECT  32.393 58.896 33.049 63.672 ;
     RECT  33.005 11.424 33.059 12.456 ;
     RECT  32.771 41.04 33.077 42.744 ;
     RECT  32.509 6.816 33.113 6.84 ;
     RECT  32.537 44.688 33.149 45.192 ;
     RECT  32.537 76.896 33.181 80.904 ;
     RECT  33.049 60.432 33.212 63.672 ;
     RECT  31.961 64.944 33.212 65.544 ;
     RECT  33.037 67.68 33.217 67.944 ;
     RECT  33.037 69.024 33.217 69.96 ;
     RECT  33.181 76.896 33.217 81 ;
     RECT  32.609 72.72 33.257 74.904 ;
     RECT  33.257 72.72 33.293 74.184 ;
     RECT  32.236 82.416 33.293 84.984 ;
     RECT  33.013 28.704 33.365 38.856 ;
     RECT  33.217 67.68 33.365 69.96 ;
     RECT  33.217 76.896 33.365 81.096 ;
     RECT  33.212 60.432 33.397 65.544 ;
     RECT  33.293 82.416 33.397 84.936 ;
     RECT  33.293 72.72 33.401 73.896 ;
     RECT  33.077 41.04 33.469 42.6 ;
     RECT  32.675 21.6 33.505 27.672 ;
     RECT  33.365 28.704 33.505 28.728 ;
     RECT  32.357 90.096 33.505 91.128 ;
     RECT  33.059 11.856 33.545 12.456 ;
     RECT  32.249 86.832 33.577 86.856 ;
     RECT  32.717 7.92 33.653 10.056 ;
     RECT  33.005 17.04 33.685 19.896 ;
     RECT  33.505 21.6 33.685 28.728 ;
     RECT  33.289 71.088 33.685 71.112 ;
     RECT  33.685 17.04 33.689 28.728 ;
     RECT  33.397 60.432 33.689 65.976 ;
     RECT  32.105 88.176 33.689 89.016 ;
     RECT  32.537 46.272 33.725 53.16 ;
     RECT  33.397 81.984 33.725 84.936 ;
     RECT  33.365 67.68 33.733 69.48 ;
     RECT  33.545 11.952 33.761 12.456 ;
     RECT  33.733 67.344 33.779 69.48 ;
     RECT  33.577 85.968 33.788 86.856 ;
     RECT  33.689 60.432 33.833 62.184 ;
     RECT  33.505 90.096 33.937 91.848 ;
     RECT  33.788 85.92 34.045 86.856 ;
     RECT  33.149 44.976 34.117 45.192 ;
     RECT  33.365 76.896 34.153 81 ;
     RECT  33.505 43.824 34.225 43.848 ;
     RECT  34.117 44.976 34.225 45.24 ;
     RECT  32.963 13.824 34.261 15 ;
     RECT  33.689 63.264 34.261 65.976 ;
     RECT  33.725 82.272 34.297 84.936 ;
     RECT  34.045 85.92 34.297 87.144 ;
     RECT  33.401 72.912 34.333 73.896 ;
     RECT  34.333 72.912 34.453 74.376 ;
     RECT  34.261 13.632 34.477 15 ;
     RECT  32.825 56.16 34.477 56.184 ;
     RECT  34.453 72.816 34.549 74.376 ;
     RECT  34.153 76.464 34.549 81 ;
     RECT  34.297 82.272 34.585 87.144 ;
     RECT  32.465 5.088 34.621 5.112 ;
     RECT  33.689 22.032 34.657 28.728 ;
     RECT  34.549 72.72 34.685 74.376 ;
     RECT  34.549 75.6 34.685 81 ;
     RECT  33.653 10.032 34.693 10.056 ;
     RECT  33.689 17.04 34.693 20.712 ;
     RECT  34.685 72.72 34.729 81 ;
     RECT  34.585 82.272 34.729 87.336 ;
     RECT  34.657 21.984 34.765 28.728 ;
     RECT  33.365 29.76 34.765 38.856 ;
     RECT  33.937 90.096 34.801 91.896 ;
     RECT  34.621 3.984 34.808 5.112 ;
     RECT  33.653 7.92 34.808 8.568 ;
     RECT  34.693 10.032 34.808 10.92 ;
     RECT  33.761 11.952 34.808 11.976 ;
     RECT  34.477 13.632 34.808 15.48 ;
     RECT  34.693 16.896 34.808 20.712 ;
     RECT  34.765 21.984 34.808 38.856 ;
     RECT  33.469 40.992 34.808 42.6 ;
     RECT  34.225 43.824 34.808 45.24 ;
     RECT  33.725 46.272 34.808 52.392 ;
     RECT  34.477 56.16 34.808 56.328 ;
     RECT  34.477 57.6 34.808 57.624 ;
     RECT  33.049 58.896 34.808 58.92 ;
     RECT  33.833 60.912 34.808 62.184 ;
     RECT  34.261 63.264 34.808 66.168 ;
     RECT  33.779 67.344 34.808 67.896 ;
     RECT  33.779 68.928 34.808 69.48 ;
     RECT  33.685 70.896 34.808 71.112 ;
     RECT  34.729 72.72 34.808 87.336 ;
     RECT  33.689 88.944 34.808 89.016 ;
     RECT  34.801 90 34.808 91.896 ;
     RECT  34.808 2.148 34.912 92.892 ;
     RECT  34.912 2.418 35.104 92.622 ;
     RECT  35.104 36.048 35.129 38.232 ;
     RECT  35.104 34.176 35.165 35.016 ;
     RECT  35.104 63.264 35.165 64.968 ;
     RECT  35.104 66.048 35.201 71.112 ;
     RECT  35.104 57.6 35.219 61.944 ;
     RECT  35.104 52.8 35.237 52.824 ;
     RECT  35.219 58.32 35.309 61.944 ;
     RECT  35.104 79.728 35.315 91.896 ;
     RECT  35.129 36.048 35.345 37.992 ;
     RECT  35.104 6.864 35.363 8.52 ;
     RECT  35.309 59.856 35.381 61.944 ;
     RECT  35.363 7.392 35.459 8.52 ;
     RECT  35.104 12.96 35.459 18.792 ;
     RECT  35.459 13.104 35.489 18.792 ;
     RECT  35.315 79.728 35.489 87.816 ;
     RECT  35.165 34.368 35.525 35.016 ;
     RECT  35.489 15.888 35.561 18.792 ;
     RECT  35.165 63.264 35.633 64.632 ;
     RECT  35.489 85.776 35.633 87.816 ;
     RECT  35.104 19.872 35.669 30.648 ;
     RECT  35.381 59.856 35.741 61.896 ;
     RECT  35.345 36.048 35.777 37.896 ;
     RECT  35.489 79.728 35.777 84.792 ;
     RECT  35.104 75.648 35.849 78.648 ;
     RECT  35.104 4.512 35.957 4.968 ;
     RECT  35.777 79.728 36.029 79.752 ;
     RECT  35.104 40.272 36.092 42.6 ;
     RECT  35.669 20.112 36.097 30.648 ;
     RECT  35.104 31.68 36.097 32.232 ;
     RECT  35.315 88.8 36.101 91.896 ;
     RECT  35.849 75.936 36.133 78.648 ;
     RECT  36.133 75.936 36.227 79.272 ;
     RECT  36.205 56.688 36.241 56.712 ;
     RECT  35.561 15.888 36.268 16.632 ;
     RECT  36.092 39.984 36.277 42.6 ;
     RECT  35.201 66.048 36.313 70.968 ;
     RECT  35.104 72.24 36.313 73.176 ;
     RECT  35.561 17.616 36.317 18.792 ;
     RECT  36.097 20.112 36.385 32.232 ;
     RECT  36.277 33.36 36.385 33.384 ;
     RECT  35.633 87.792 36.385 87.816 ;
     RECT  36.101 88.8 36.385 91.752 ;
     RECT  36.277 39.984 36.421 42.744 ;
     RECT  36.241 56.688 36.421 57 ;
     RECT  35.309 58.32 36.421 58.344 ;
     RECT  35.741 60.432 36.421 61.896 ;
     RECT  35.104 10.896 36.457 10.92 ;
     RECT  36.421 56.688 36.457 58.344 ;
     RECT  35.777 80.832 36.457 84.792 ;
     RECT  35.633 85.776 36.457 86.616 ;
     RECT  36.457 10.224 36.469 10.92 ;
     RECT  35.104 11.952 36.469 11.976 ;
     RECT  35.525 34.608 36.469 35.016 ;
     RECT  35.777 36.048 36.469 37.464 ;
     RECT  36.268 16.272 36.497 16.632 ;
     RECT  36.469 10.224 36.515 11.976 ;
     RECT  36.385 20.112 36.529 33.384 ;
     RECT  36.469 34.608 36.529 37.464 ;
     RECT  35.633 63.6 36.529 64.632 ;
     RECT  36.313 66.048 36.565 73.176 ;
     RECT  35.489 13.104 36.677 14.808 ;
     RECT  35.104 44.448 36.709 47.448 ;
     RECT  36.529 20.112 36.745 37.464 ;
     RECT  35.104 48.432 36.781 51.72 ;
     RECT  36.745 19.968 36.817 37.464 ;
     RECT  36.421 39.024 36.817 42.744 ;
     RECT  36.781 48.432 36.817 52.296 ;
     RECT  36.515 11.664 36.821 11.976 ;
     RECT  36.457 80.832 36.821 86.616 ;
     RECT  36.529 63.6 36.853 65.016 ;
     RECT  36.227 75.936 36.889 79.08 ;
     RECT  36.817 19.968 36.893 42.744 ;
     RECT  36.421 60.432 36.917 62.184 ;
     RECT  36.457 56.496 36.929 58.344 ;
     RECT  36.677 13.68 36.961 14.808 ;
     RECT  36.497 16.512 36.961 16.632 ;
     RECT  36.317 17.616 36.961 17.736 ;
     RECT  36.709 43.776 36.997 47.448 ;
     RECT  36.817 48.432 36.997 53.592 ;
     RECT  36.917 60.384 37.001 62.184 ;
     RECT  36.565 66 37.001 73.176 ;
     RECT  35.459 7.392 37.033 8.328 ;
     RECT  36.821 81.36 37.033 86.616 ;
     RECT  36.385 87.792 37.033 91.752 ;
     RECT  37.001 66 37.073 72.792 ;
     RECT  37.033 81.36 37.073 91.752 ;
     RECT  36.853 63.504 37.091 65.016 ;
     RECT  37.033 7.392 37.105 8.808 ;
     RECT  37.001 60.432 37.141 62.184 ;
     RECT  37.091 63.504 37.141 64.44 ;
     RECT  37.105 6.24 37.177 8.808 ;
     RECT  35.957 4.848 37.213 4.968 ;
     RECT  37.213 4.56 37.249 4.968 ;
     RECT  37.177 6.24 37.249 9.096 ;
     RECT  36.961 13.68 37.253 14.904 ;
     RECT  36.317 18.768 37.285 18.792 ;
     RECT  36.893 19.968 37.285 25.56 ;
     RECT  36.997 43.776 37.361 53.592 ;
     RECT  37.253 13.872 37.429 14.904 ;
     RECT  36.929 56.688 37.501 58.344 ;
     RECT  36.893 26.784 37.505 42.744 ;
     RECT  36.637 55.104 37.573 55.128 ;
     RECT  37.501 56.688 37.573 58.536 ;
     RECT  35.104 74.352 37.573 74.376 ;
     RECT  37.505 26.784 37.619 37.464 ;
     RECT  37.573 74.208 37.619 74.376 ;
     RECT  37.573 56.688 37.645 58.728 ;
     RECT  37.645 56.688 37.681 58.968 ;
     RECT  37.537 3.312 37.717 3.336 ;
     RECT  37.249 4.56 37.717 9.096 ;
     RECT  36.961 16.512 37.717 17.736 ;
     RECT  37.285 18.768 37.717 25.56 ;
     RECT  37.361 43.776 37.724 48.456 ;
     RECT  37.429 13.872 37.753 15.288 ;
     RECT  37.717 16.512 37.753 25.56 ;
     RECT  37.361 49.584 37.753 53.592 ;
     RECT  37.619 36.912 37.757 37.464 ;
     RECT  37.619 74.208 37.789 74.328 ;
     RECT  37.505 38.784 37.825 42.744 ;
     RECT  37.724 43.728 37.825 48.456 ;
     RECT  36.889 75.792 37.861 79.08 ;
     RECT  37.073 68.592 37.865 72.792 ;
     RECT  37.681 56.688 37.897 59.352 ;
     RECT  37.865 68.928 37.901 72.792 ;
     RECT  37.619 26.784 37.973 35.352 ;
     RECT  37.757 37.104 38.009 37.464 ;
     RECT  38.009 37.104 38.045 37.176 ;
     RECT  37.717 3.312 38.077 9.096 ;
     RECT  36.515 10.224 38.077 10.248 ;
     RECT  37.073 81.36 38.077 91.08 ;
     RECT  38.077 3.312 38.081 10.248 ;
     RECT  37.825 38.784 38.081 48.456 ;
     RECT  38.077 80.976 38.081 91.08 ;
     RECT  37.861 75.648 38.101 79.08 ;
     RECT  37.753 49.584 38.113 53.784 ;
     RECT  37.573 55.104 38.113 55.176 ;
     RECT  37.753 13.872 38.149 25.56 ;
     RECT  37.973 26.784 38.149 27.288 ;
     RECT  38.113 49.584 38.149 55.176 ;
     RECT  37.897 56.64 38.149 59.352 ;
     RECT  37.141 60.432 38.149 64.44 ;
     RECT  38.081 80.976 38.161 81.384 ;
     RECT  38.149 60.432 38.185 64.584 ;
     RECT  38.081 3.408 38.221 10.248 ;
     RECT  37.073 66 38.225 67.224 ;
     RECT  38.185 60.432 38.252 64.92 ;
     RECT  37.789 74.064 38.261 74.328 ;
     RECT  38.101 75.648 38.261 79.8 ;
     RECT  37.901 69.024 38.293 72.792 ;
     RECT  38.149 13.872 38.333 27.288 ;
     RECT  38.252 60.432 38.339 65.544 ;
     RECT  38.261 79.728 38.339 79.8 ;
     RECT  38.081 82.608 38.339 91.08 ;
     RECT  38.081 40.896 38.341 48.456 ;
     RECT  38.149 49.584 38.341 59.352 ;
     RECT  38.221 3.408 38.441 10.344 ;
     RECT  38.441 3.408 38.477 9.288 ;
     RECT  38.333 15.696 38.513 27.288 ;
     RECT  38.081 38.784 38.581 39.864 ;
     RECT  38.513 15.696 38.585 27.24 ;
     RECT  38.339 82.944 38.653 91.08 ;
     RECT  38.339 79.776 38.657 79.8 ;
     RECT  38.225 66.576 38.689 67.224 ;
     RECT  38.045 37.104 38.761 37.128 ;
     RECT  38.161 81.216 38.771 81.384 ;
     RECT  38.339 60.432 38.801 65.208 ;
     RECT  38.441 10.32 38.833 10.344 ;
     RECT  38.333 13.872 38.869 14.664 ;
     RECT  38.341 40.896 38.873 59.352 ;
     RECT  38.261 75.648 38.905 78.744 ;
     RECT  38.585 25.44 38.909 27.24 ;
     RECT  37.973 28.704 38.965 35.352 ;
     RECT  38.965 28.608 38.972 35.352 ;
     RECT  38.653 82.944 38.981 91.8 ;
     RECT  38.761 37.008 39.049 37.128 ;
     RECT  38.771 81.36 39.049 81.384 ;
     RECT  38.909 26.208 39.053 27.24 ;
     RECT  38.585 15.696 39.059 24.408 ;
     RECT  38.689 66.576 39.089 67.8 ;
     RECT  38.293 69.024 39.089 72.84 ;
     RECT  38.972 28.608 39.107 35.448 ;
     RECT  38.873 44.352 39.116 59.352 ;
     RECT  38.801 60.432 39.116 60.888 ;
     RECT  39.053 26.208 39.161 26.808 ;
     RECT  39.059 17.712 39.233 24.408 ;
     RECT  36.961 12.528 39.308 12.552 ;
     RECT  38.869 13.824 39.308 14.664 ;
     RECT  38.981 82.944 39.349 86.76 ;
     RECT  39.089 69.024 39.373 72.696 ;
     RECT  38.833 10.32 39.481 10.584 ;
     RECT  38.801 62.4 39.481 65.208 ;
     RECT  38.581 38.736 39.553 39.864 ;
     RECT  38.873 40.896 39.553 42.6 ;
     RECT  39.107 33.648 39.661 35.448 ;
     RECT  39.049 37.008 39.661 37.416 ;
     RECT  39.661 33.648 39.769 37.416 ;
     RECT  39.107 28.608 39.841 32.232 ;
     RECT  38.905 75.504 39.877 78.744 ;
     RECT  38.477 3.504 39.913 9.288 ;
     RECT  39.913 3.36 39.985 9.288 ;
     RECT  39.985 2.88 40.057 9.288 ;
     RECT  39.481 10.32 40.057 11.208 ;
     RECT  40.057 2.88 40.208 11.208 ;
     RECT  39.308 12.528 40.208 14.664 ;
     RECT  39.059 15.696 40.208 16.584 ;
     RECT  39.233 17.712 40.208 18.792 ;
     RECT  39.233 20.16 40.208 24.408 ;
     RECT  39.161 26.208 40.208 26.232 ;
     RECT  39.841 27.888 40.208 32.232 ;
     RECT  39.769 33.648 40.208 37.608 ;
     RECT  39.553 38.736 40.208 42.6 ;
     RECT  39.116 44.352 40.208 60.888 ;
     RECT  39.481 62.4 40.208 65.544 ;
     RECT  39.089 66.576 40.208 67.272 ;
     RECT  39.373 68.688 40.208 72.696 ;
     RECT  38.261 74.304 40.208 74.328 ;
     RECT  39.877 75.504 40.208 79.272 ;
     RECT  39.049 81.36 40.208 81.48 ;
     RECT  39.349 82.56 40.208 86.76 ;
     RECT  38.981 87.84 40.208 91.8 ;
     RECT  40.208 2.148 40.312 92.892 ;
     RECT  40.312 2.418 40.504 92.622 ;
     RECT  40.504 62.64 40.529 72.84 ;
     RECT  40.504 84.048 40.565 86.328 ;
     RECT  40.529 62.64 40.643 64.344 ;
     RECT  40.529 65.52 40.665 72.84 ;
     RECT  40.665 65.568 40.673 72.84 ;
     RECT  40.504 12.768 40.709 14.232 ;
     RECT  40.504 15.456 40.709 18.792 ;
     RECT  40.504 80.544 40.709 81.624 ;
     RECT  40.709 13.584 40.739 14.232 ;
     RECT  40.709 15.456 40.925 18.744 ;
     RECT  40.504 3.024 40.997 11.208 ;
     RECT  40.739 13.584 41.069 14.136 ;
     RECT  40.673 65.568 41.105 70.152 ;
     RECT  40.504 44.352 41.123 61.512 ;
     RECT  40.504 35.424 41.177 43.32 ;
     RECT  41.177 38.736 41.213 43.32 ;
     RECT  41.105 65.568 41.357 69.048 ;
     RECT  40.504 90.912 41.363 91.368 ;
     RECT  40.925 15.456 41.497 18.6 ;
     RECT  40.709 80.928 41.533 81.624 ;
     RECT  40.504 20.16 41.537 24.792 ;
     RECT  40.504 26.64 41.605 33.864 ;
     RECT  41.177 35.424 41.605 37.752 ;
     RECT  40.673 71.184 41.641 72.84 ;
     RECT  40.504 92.352 41.645 92.376 ;
     RECT  41.497 15.168 41.651 18.6 ;
     RECT  41.605 26.64 41.681 37.752 ;
     RECT  41.213 38.736 41.681 43.224 ;
     RECT  41.105 70.128 41.681 70.152 ;
     RECT  41.651 16.416 41.753 18.6 ;
     RECT  40.997 3.024 41.789 10.44 ;
     RECT  41.357 66.672 41.789 69.048 ;
     RECT  41.641 71.184 41.825 72.936 ;
     RECT  40.504 75.696 41.845 79.224 ;
     RECT  41.533 80.928 41.845 81.768 ;
     RECT  41.845 75.696 41.891 81.768 ;
     RECT  41.825 71.184 41.893 71.832 ;
     RECT  41.891 79.68 41.965 81.768 ;
     RECT  41.753 17.664 41.969 18.6 ;
     RECT  41.891 75.696 41.987 78.456 ;
     RECT  40.504 87.936 42.001 88.776 ;
     RECT  41.123 45.552 42.037 61.512 ;
     RECT  40.643 62.64 42.037 64.056 ;
     RECT  41.357 65.568 42.037 65.592 ;
     RECT  41.605 11.952 42.073 11.976 ;
     RECT  42.073 11.952 42.133 12.552 ;
     RECT  41.069 13.68 42.133 14.136 ;
     RECT  41.123 44.352 42.133 44.472 ;
     RECT  42.037 45.552 42.133 64.056 ;
     RECT  40.504 74.304 42.145 74.472 ;
     RECT  41.987 75.696 42.145 75.912 ;
     RECT  41.893 70.464 42.179 71.832 ;
     RECT  42.133 11.952 42.181 14.136 ;
     RECT  41.651 15.168 42.181 15.192 ;
     RECT  42.037 65.472 42.185 65.592 ;
     RECT  41.681 32.016 42.227 37.752 ;
     RECT  41.825 72.816 42.253 72.936 ;
     RECT  42.145 74.304 42.253 75.912 ;
     RECT  41.789 3.024 42.257 10.248 ;
     RECT  42.227 35.424 42.277 37.752 ;
     RECT  41.681 38.736 42.277 38.808 ;
     RECT  42.277 35.424 42.323 38.808 ;
     RECT  42.133 44.352 42.325 64.056 ;
     RECT  42.257 3.024 42.329 3.048 ;
     RECT  42.253 74.16 42.361 75.912 ;
     RECT  41.789 67.392 42.373 69.048 ;
     RECT  40.504 82.992 42.397 83.016 ;
     RECT  42.361 74.064 42.481 75.912 ;
     RECT  42.181 11.952 42.581 15.192 ;
     RECT  41.537 20.16 42.649 20.184 ;
     RECT  41.681 39.84 42.685 43.224 ;
     RECT  42.581 11.952 42.689 14.136 ;
     RECT  42.001 87.936 42.721 89.304 ;
     RECT  41.681 26.64 42.757 30.6 ;
     RECT  42.685 39.84 42.757 43.32 ;
     RECT  42.325 44.304 42.757 64.056 ;
     RECT  42.373 67.392 42.757 69.48 ;
     RECT  42.397 82.992 42.757 83.304 ;
     RECT  42.185 65.472 42.761 65.496 ;
     RECT  42.253 72.816 42.761 72.984 ;
     RECT  41.965 79.68 42.793 81.912 ;
     RECT  42.757 82.944 42.793 83.304 ;
     RECT  42.757 39.84 42.797 64.248 ;
     RECT  42.793 79.68 42.805 83.304 ;
     RECT  40.565 84.288 42.805 86.328 ;
     RECT  42.797 42.24 42.833 58.68 ;
     RECT  42.797 59.808 42.851 64.248 ;
     RECT  42.649 19.824 42.865 20.184 ;
     RECT  42.757 66.576 42.869 69.48 ;
     RECT  42.721 87.84 42.901 89.304 ;
     RECT  41.363 91.344 42.901 91.368 ;
     RECT  42.851 59.856 42.905 64.248 ;
     RECT  42.865 19.584 42.937 20.184 ;
     RECT  41.537 21.408 42.937 24.792 ;
     RECT  42.833 57.12 42.941 58.68 ;
     RECT  42.869 66.672 42.941 69.48 ;
     RECT  42.805 79.776 42.973 86.328 ;
     RECT  42.901 87.84 42.973 91.368 ;
     RECT  42.257 4.128 43.009 10.248 ;
     RECT  42.941 67.008 43.045 69.48 ;
     RECT  42.179 70.464 43.045 71.496 ;
     RECT  42.689 13.968 43.049 14.136 ;
     RECT  43.045 67.008 43.085 71.496 ;
     RECT  42.581 15.168 43.117 15.192 ;
     RECT  41.753 16.416 43.117 16.44 ;
     RECT  42.833 42.24 43.121 55.8 ;
     RECT  42.761 72.816 43.153 72.936 ;
     RECT  43.117 15.168 43.157 16.44 ;
     RECT  42.941 57.264 43.193 58.68 ;
     RECT  43.153 72.336 43.193 72.936 ;
     RECT  43.009 4.128 43.225 10.584 ;
     RECT  42.227 32.016 43.297 34.392 ;
     RECT  42.323 35.424 43.297 38.76 ;
     RECT  42.757 26.64 43.301 30.84 ;
     RECT  43.121 42.24 43.301 54.168 ;
     RECT  43.225 3.984 43.331 10.584 ;
     RECT  42.797 39.84 43.373 41.256 ;
     RECT  41.969 17.664 43.405 18.552 ;
     RECT  42.973 79.776 43.405 91.368 ;
     RECT  42.001 92.688 43.405 92.712 ;
     RECT  43.297 32.016 43.409 38.76 ;
     RECT  43.373 40.8 43.409 41.256 ;
     RECT  42.905 60.192 43.409 64.248 ;
     RECT  41.987 76.944 43.409 78.456 ;
     RECT  43.405 79.776 43.481 92.712 ;
     RECT  42.689 11.952 43.549 12.888 ;
     RECT  43.049 14.112 43.585 14.136 ;
     RECT  43.157 15.168 43.585 16.392 ;
     RECT  43.481 79.776 43.625 91.992 ;
     RECT  42.937 19.584 43.657 24.792 ;
     RECT  43.621 65.616 43.729 65.64 ;
     RECT  43.301 44.304 43.733 53.016 ;
     RECT  43.729 65.52 43.769 65.64 ;
     RECT  43.409 77.904 43.837 78.456 ;
     RECT  43.085 67.008 43.859 71.208 ;
     RECT  43.409 33.84 43.873 38.76 ;
     RECT  43.121 55.152 43.909 55.8 ;
     RECT  43.549 11.328 43.955 12.888 ;
     RECT  43.909 55.152 43.981 55.944 ;
     RECT  43.193 57.264 43.981 58.536 ;
     RECT  43.331 3.984 44.021 10.2 ;
     RECT  43.301 26.832 44.057 30.84 ;
     RECT  43.733 44.304 44.057 52.872 ;
     RECT  43.955 11.424 44.06 12.888 ;
     RECT  43.585 14.112 44.06 16.392 ;
     RECT  43.409 40.992 44.089 41.256 ;
     RECT  43.301 42.24 44.089 43.32 ;
     RECT  44.06 11.424 44.093 16.392 ;
     RECT  42.481 74.064 44.125 75.864 ;
     RECT  43.513 76.848 44.125 76.872 ;
     RECT  43.657 19.584 44.129 25.656 ;
     RECT  43.859 67.008 44.129 71.16 ;
     RECT  44.093 11.424 44.147 15.192 ;
     RECT  43.409 32.016 44.149 32.52 ;
     RECT  43.981 55.152 44.161 58.536 ;
     RECT  43.409 60.192 44.161 62.184 ;
     RECT  43.409 63.216 44.201 64.248 ;
     RECT  44.147 11.424 44.237 12.888 ;
     RECT  44.129 67.008 44.245 67.416 ;
     RECT  43.193 72.336 44.305 72.84 ;
     RECT  44.129 19.584 44.341 21.192 ;
     RECT  44.021 3.984 44.377 5.448 ;
     RECT  44.089 40.992 44.377 43.32 ;
     RECT  43.873 33.84 44.417 39.24 ;
     RECT  44.161 55.152 44.417 62.184 ;
     RECT  44.377 3.888 44.453 5.448 ;
     RECT  44.021 6.672 44.453 10.2 ;
     RECT  44.417 55.92 44.489 62.184 ;
     RECT  43.837 77.904 44.557 78.504 ;
     RECT  43.625 79.776 44.557 83.256 ;
     RECT  44.057 26.832 44.581 30.264 ;
     RECT  44.377 40.32 44.593 43.32 ;
     RECT  44.057 44.304 44.593 52.728 ;
     RECT  44.417 33.84 44.597 34.248 ;
     RECT  43.769 65.52 44.597 65.544 ;
     RECT  44.489 56.736 44.629 62.184 ;
     RECT  44.201 63.216 44.629 63.816 ;
     RECT  44.125 74.064 44.665 76.872 ;
     RECT  44.557 77.904 44.665 83.256 ;
     RECT  43.405 17.616 44.701 18.552 ;
     RECT  44.305 72.336 44.701 72.984 ;
     RECT  44.665 74.064 44.701 83.256 ;
     RECT  44.149 31.584 44.732 32.52 ;
     RECT  44.129 22.224 44.737 25.656 ;
     RECT  44.581 26.64 44.737 30.264 ;
     RECT  44.701 72.336 44.809 83.256 ;
     RECT  43.625 84.288 44.809 91.992 ;
     RECT  43.301 54.144 44.953 54.168 ;
     RECT  44.701 17.424 45.061 18.552 ;
     RECT  44.341 19.536 45.061 21.192 ;
     RECT  44.593 40.32 45.133 52.728 ;
     RECT  44.732 31.584 45.205 32.76 ;
     RECT  44.597 33.84 45.205 33.96 ;
     RECT  44.417 35.328 45.205 39.24 ;
     RECT  45.133 40.32 45.205 52.824 ;
     RECT  44.245 66.816 45.277 67.416 ;
     RECT  45.061 17.424 45.493 21.192 ;
     RECT  44.737 22.224 45.493 30.264 ;
     RECT  44.809 72.336 45.493 91.992 ;
     RECT  45.493 17.424 45.529 30.264 ;
     RECT  45.205 31.584 45.529 33.96 ;
     RECT  45.493 6.336 45.601 6.36 ;
     RECT  44.453 7.392 45.601 10.2 ;
     RECT  44.453 3.888 45.608 5.112 ;
     RECT  45.601 6.336 45.608 10.2 ;
     RECT  44.237 11.424 45.608 11.448 ;
     RECT  44.237 12.816 45.608 12.888 ;
     RECT  44.147 14.112 45.608 15.192 ;
     RECT  44.093 16.368 45.608 16.392 ;
     RECT  45.529 17.424 45.608 33.96 ;
     RECT  45.205 35.328 45.608 52.824 ;
     RECT  44.953 54.144 45.608 54.216 ;
     RECT  44.629 56.736 45.608 63.816 ;
     RECT  45.277 66.816 45.608 67.848 ;
     RECT  44.129 68.832 45.608 71.16 ;
     RECT  45.493 72.144 45.608 91.992 ;
     RECT  45.608 2.148 45.712 92.892 ;
     RECT  45.712 2.418 45.904 92.622 ;
     RECT  45.904 31.2 45.965 32.616 ;
     RECT  45.904 45.456 45.965 54.216 ;
     RECT  45.904 66.816 46.001 72.36 ;
     RECT  45.904 6.288 46.019 10.296 ;
     RECT  46.001 66.816 46.019 69.48 ;
     RECT  45.904 86.256 46.019 91.896 ;
     RECT  45.904 20.592 46.037 20.904 ;
     RECT  45.965 45.456 46.037 54.168 ;
     RECT  46.019 7.392 46.045 10.296 ;
     RECT  46.001 70.8 46.045 72.36 ;
     RECT  45.904 73.536 46.045 85.08 ;
     RECT  46.045 73.632 46.06 85.08 ;
     RECT  46.037 20.592 46.145 20.616 ;
     RECT  45.904 56.88 46.145 58.728 ;
     RECT  45.904 35.424 46.217 44.424 ;
     RECT  46.019 6.288 46.253 6.36 ;
     RECT  45.904 17.088 46.253 19.608 ;
     RECT  46.037 45.504 46.253 54.168 ;
     RECT  46.045 7.392 46.325 10.2 ;
     RECT  45.904 60.048 46.325 63.816 ;
     RECT  45.965 31.2 46.361 32.52 ;
     RECT  46.253 45.504 46.369 54.072 ;
     RECT  46.145 56.976 46.433 58.728 ;
     RECT  46.019 87.648 46.433 91.896 ;
     RECT  46.06 73.632 46.469 83.256 ;
     RECT  46.433 57.024 46.541 58.728 ;
     RECT  45.904 25.824 46.577 30.216 ;
     RECT  46.369 45.504 46.613 47.064 ;
     RECT  46.469 74.016 46.636 83.256 ;
     RECT  46.217 39.408 46.739 44.424 ;
     RECT  46.739 39.408 46.787 42.84 ;
     RECT  46.253 17.088 46.829 18.216 ;
     RECT  46.577 25.824 46.829 26.76 ;
     RECT  46.577 27.744 46.829 30.216 ;
     RECT  46.636 74.016 46.876 80.136 ;
     RECT  46.636 81.36 46.883 83.256 ;
     RECT  46.325 7.392 46.937 9 ;
     RECT  46.613 45.6 46.937 47.064 ;
     RECT  46.369 48.24 46.973 54.072 ;
     RECT  46.883 82.032 46.973 83.256 ;
     RECT  46.06 84.288 46.981 85.08 ;
     RECT  46.019 86.256 46.981 86.568 ;
     RECT  46.019 66.816 47.005 69.288 ;
     RECT  46.045 70.8 47.005 72.168 ;
     RECT  46.973 48.24 47.009 53.832 ;
     RECT  46.541 57.024 47.017 58.68 ;
     RECT  46.829 17.088 47.041 17.112 ;
     RECT  47.005 66.816 47.045 72.168 ;
     RECT  45.904 13.008 47.077 13.08 ;
     RECT  45.904 14.112 47.077 15 ;
     RECT  46.361 31.92 47.113 32.52 ;
     RECT  45.904 33.6 47.113 33.912 ;
     RECT  46.981 84.288 47.113 86.568 ;
     RECT  46.433 87.648 47.113 88.152 ;
     RECT  46.937 7.632 47.117 9 ;
     RECT  47.045 70.128 47.149 72.168 ;
     RECT  47.017 57.312 47.153 58.68 ;
     RECT  47.077 13.008 47.185 15 ;
     RECT  46.253 19.584 47.221 19.608 ;
     RECT  45.904 22.464 47.221 24.792 ;
     RECT  46.829 25.824 47.221 26.664 ;
     RECT  47.113 31.92 47.221 33.912 ;
     RECT  46.217 35.424 47.221 38.184 ;
     RECT  46.433 89.28 47.261 91.896 ;
     RECT  47.221 19.392 47.293 19.944 ;
     RECT  47.293 19.392 47.333 20.52 ;
     RECT  46.325 10.176 47.363 10.2 ;
     RECT  46.973 82.032 47.363 83.112 ;
     RECT  47.185 13.008 47.365 15.288 ;
     RECT  47.285 11.424 47.369 11.448 ;
     RECT  47.221 31.92 47.369 34.344 ;
     RECT  46.325 60.048 47.369 63.384 ;
     RECT  47.261 90.096 47.369 91.656 ;
     RECT  46.253 6.288 47.393 6.312 ;
     RECT  47.221 22.464 47.401 26.664 ;
     RECT  47.365 12.528 47.405 15.288 ;
     RECT  47.393 6.24 47.42 6.312 ;
     RECT  47.369 90.24 47.441 91.656 ;
     RECT  47.221 4.512 47.459 4.536 ;
     RECT  47.117 8.208 47.461 9 ;
     RECT  47.221 35.424 47.477 38.568 ;
     RECT  47.42 6.24 47.507 6.36 ;
     RECT  46.829 18.192 47.509 18.216 ;
     RECT  47.333 19.392 47.509 19.416 ;
     RECT  47.401 21.552 47.513 26.664 ;
     RECT  46.787 40.128 47.513 42.84 ;
     RECT  46.876 74.016 47.513 75.96 ;
     RECT  47.461 8.208 47.548 9.24 ;
     RECT  47.509 18.192 47.549 19.416 ;
     RECT  46.876 77.04 47.549 80.136 ;
     RECT  46.829 29.184 47.581 30.216 ;
     RECT  45.904 64.848 47.581 65.832 ;
     RECT  47.045 66.816 47.581 69.048 ;
     RECT  47.513 21.552 47.603 25.464 ;
     RECT  47.113 84.288 47.617 88.152 ;
     RECT  46.739 44.016 47.657 44.424 ;
     RECT  47.617 84.288 47.657 88.344 ;
     RECT  47.657 44.352 47.725 44.424 ;
     RECT  46.937 45.6 47.725 46.968 ;
     RECT  47.333 20.496 47.729 20.52 ;
     RECT  47.549 77.136 47.729 80.136 ;
     RECT  47.477 36.624 47.761 38.568 ;
     RECT  47.513 40.128 47.761 41.256 ;
     RECT  47.729 79.68 47.833 80.136 ;
     RECT  47.549 18.576 47.891 19.416 ;
     RECT  47.725 44.352 47.891 46.968 ;
     RECT  47.441 90.576 47.891 91.656 ;
     RECT  47.833 79.68 47.905 80.184 ;
     RECT  47.891 19.344 47.909 19.416 ;
     RECT  47.513 42.24 47.909 42.84 ;
     RECT  47.041 16.464 47.941 17.112 ;
     RECT  47.891 44.352 47.945 45.048 ;
     RECT  47.149 70.128 47.945 72.84 ;
     RECT  47.153 57.984 47.977 58.68 ;
     RECT  47.369 60.048 47.977 62.376 ;
     RECT  47.945 70.8 47.98 72.84 ;
     RECT  47.98 70.896 48.017 72.84 ;
     RECT  47.548 8.208 48.083 9.096 ;
     RECT  47.653 5.088 48.085 5.112 ;
     RECT  47.581 29.184 48.085 30.792 ;
     RECT  47.581 64.848 48.085 69.048 ;
     RECT  47.905 79.68 48.089 80.664 ;
     RECT  48.085 5.088 48.125 5.832 ;
     RECT  47.977 57.984 48.157 62.376 ;
     RECT  48.085 29.184 48.193 30.888 ;
     RECT  47.369 31.92 48.193 33.672 ;
     RECT  48.085 64.368 48.193 69.048 ;
     RECT  48.193 29.184 48.229 33.672 ;
     RECT  47.405 13.632 48.265 15.288 ;
     RECT  47.941 16.464 48.265 17.352 ;
     RECT  47.891 46.464 48.265 46.968 ;
     RECT  47.009 48.24 48.265 53.592 ;
     RECT  46.892 55.824 48.265 55.848 ;
     RECT  47.657 84.288 48.268 86.568 ;
     RECT  48.089 80.016 48.301 80.664 ;
     RECT  48.157 57.12 48.332 62.376 ;
     RECT  47.369 63.36 48.332 63.384 ;
     RECT  48.037 10.32 48.337 10.344 ;
     RECT  48.268 84.288 48.337 86.52 ;
     RECT  48.332 57.12 48.373 63.384 ;
     RECT  48.193 64.368 48.373 69.768 ;
     RECT  48.229 29.088 48.38 33.672 ;
     RECT  47.363 82.944 48.38 83.112 ;
     RECT  48.38 82.944 48.381 83.256 ;
     RECT  47.513 26.448 48.409 26.664 ;
     RECT  48.301 80.016 48.409 80.904 ;
     RECT  48.38 28.32 48.467 33.672 ;
     RECT  48.467 29.088 48.469 33.672 ;
     RECT  48.469 29.088 48.485 34.44 ;
     RECT  47.729 77.136 48.485 78.648 ;
     RECT  47.405 12.528 48.517 12.552 ;
     RECT  48.265 13.632 48.517 17.352 ;
     RECT  48.485 29.52 48.557 34.44 ;
     RECT  47.657 87.648 48.565 88.344 ;
     RECT  48.265 55.056 48.613 55.848 ;
     RECT  47.603 22.464 48.661 25.464 ;
     RECT  48.265 46.464 48.661 53.592 ;
     RECT  48.613 55.056 48.661 55.944 ;
     RECT  48.661 46.464 48.665 55.944 ;
     RECT  47.891 91.536 48.697 91.656 ;
     RECT  48.337 10.272 48.701 10.344 ;
     RECT  48.661 22.224 48.701 25.464 ;
     RECT  48.517 12.48 48.733 12.552 ;
     RECT  48.517 13.632 48.733 18.216 ;
     RECT  48.409 26.448 48.737 26.76 ;
     RECT  47.761 36.624 48.773 41.256 ;
     RECT  48.557 30.768 48.805 34.44 ;
     RECT  47.477 35.424 48.805 35.448 ;
     RECT  48.697 73.248 48.805 73.272 ;
     RECT  48.485 77.136 48.805 77.16 ;
     RECT  48.805 73.248 48.841 73.32 ;
     RECT  47.513 74.4 48.841 75.96 ;
     RECT  48.665 46.656 48.877 55.944 ;
     RECT  48.373 57.12 48.877 69.768 ;
     RECT  48.701 22.224 48.881 25.416 ;
     RECT  48.841 73.248 48.881 75.96 ;
     RECT  48.773 39.216 48.953 41.256 ;
     RECT  48.805 30.768 48.995 35.448 ;
     RECT  48.995 30.864 49.021 35.448 ;
     RECT  48.773 36.624 49.021 37.944 ;
     RECT  49.021 20.88 49.045 20.904 ;
     RECT  48.381 82.416 49.057 83.256 ;
     RECT  48.337 84.24 49.057 86.52 ;
     RECT  49.045 20.88 49.105 21.048 ;
     RECT  47.945 44.4 49.129 45.048 ;
     RECT  48.017 70.896 49.129 72.168 ;
     RECT  48.881 73.248 49.129 75 ;
     RECT  49.105 20.928 49.132 21.048 ;
     RECT  48.805 77.04 49.189 77.16 ;
     RECT  48.877 46.656 49.201 69.768 ;
     RECT  49.129 70.896 49.201 75 ;
     RECT  48.701 10.272 49.273 10.296 ;
     RECT  49.021 30.864 49.277 37.944 ;
     RECT  48.083 8.208 49.309 8.232 ;
     RECT  48.733 12.48 49.313 18.216 ;
     RECT  49.129 43.824 49.313 45.048 ;
     RECT  49.201 46.656 49.313 75 ;
     RECT  49.057 82.416 49.313 86.52 ;
     RECT  49.313 44.976 49.381 45.048 ;
     RECT  48.409 80.016 49.381 81.384 ;
     RECT  49.313 82.416 49.381 86.376 ;
     RECT  49.132 20.928 49.385 20.952 ;
     RECT  49.313 46.656 49.421 72.888 ;
     RECT  48.485 78.336 49.429 78.648 ;
     RECT  49.381 80.016 49.429 86.376 ;
     RECT  49.429 78.336 49.475 86.376 ;
     RECT  48.881 22.224 49.525 24.792 ;
     RECT  47.909 19.344 49.561 19.368 ;
     RECT  48.737 26.64 49.561 26.76 ;
     RECT  48.565 87.648 49.571 88.968 ;
     RECT  47.909 42.24 49.597 42.696 ;
     RECT  49.313 43.824 49.597 43.944 ;
     RECT  49.571 87.792 49.597 88.968 ;
     RECT  49.489 90.048 49.597 90.072 ;
     RECT  49.597 42.24 49.601 43.944 ;
     RECT  49.561 26.64 49.633 27 ;
     RECT  49.601 42.24 49.637 43.848 ;
     RECT  49.525 22.128 49.669 24.792 ;
     RECT  49.309 7.632 49.676 8.232 ;
     RECT  49.676 7.632 49.705 8.424 ;
     RECT  49.421 46.656 49.745 72.408 ;
     RECT  49.597 87.792 49.745 90.072 ;
     RECT  49.475 78.336 49.763 78.36 ;
     RECT  49.669 21.984 49.817 24.792 ;
     RECT  49.313 13.008 49.925 18.216 ;
     RECT  49.633 26.64 49.957 27.864 ;
     RECT  49.313 74.016 49.993 75 ;
     RECT  49.189 76.32 49.993 77.16 ;
     RECT  49.561 19.344 50.003 19.704 ;
     RECT  49.277 33.072 50.029 37.944 ;
     RECT  49.957 26.64 50.041 27.96 ;
     RECT  49.273 9.648 50.065 10.296 ;
     RECT  49.381 44.976 50.065 45.624 ;
     RECT  49.745 46.656 50.065 52.536 ;
     RECT  50.065 9.6 50.137 10.296 ;
     RECT  49.925 13.68 50.137 18.216 ;
     RECT  50.003 19.344 50.137 19.368 ;
     RECT  50.137 9.504 50.204 10.296 ;
     RECT  49.993 11.472 50.204 11.496 ;
     RECT  49.273 3.936 50.281 3.96 ;
     RECT  49.745 89.472 50.353 90.072 ;
     RECT  48.697 91.536 50.353 91.992 ;
     RECT  49.745 53.568 50.389 72.408 ;
     RECT  49.475 79.536 50.425 86.376 ;
     RECT  48.125 5.808 50.437 5.832 ;
     RECT  50.353 89.472 50.461 91.992 ;
     RECT  50.204 9.504 50.485 11.496 ;
     RECT  50.437 5.136 50.492 5.832 ;
     RECT  50.389 53.568 50.533 72.696 ;
     RECT  49.993 74.016 50.533 77.16 ;
     RECT  49.637 42.24 50.605 43.56 ;
     RECT  50.065 44.976 50.605 52.536 ;
     RECT  49.705 7.632 50.629 8.52 ;
     RECT  50.485 9.504 50.629 11.592 ;
     RECT  50.629 7.632 50.641 11.592 ;
     RECT  50.209 21.072 50.677 21.096 ;
     RECT  50.605 42.24 50.785 52.536 ;
     RECT  50.533 53.568 50.785 77.16 ;
     RECT  49.277 30.864 50.828 32.04 ;
     RECT  50.029 33.072 50.828 38.184 ;
     RECT  48.953 39.552 50.857 41.256 ;
     RECT  50.785 42.24 50.857 77.16 ;
     RECT  48.557 29.52 50.869 29.544 ;
     RECT  50.828 30.864 50.869 38.184 ;
     RECT  50.857 39.552 50.869 77.16 ;
     RECT  50.425 79.536 50.869 86.616 ;
     RECT  50.281 3.408 51.008 3.96 ;
     RECT  50.492 5.136 51.008 5.976 ;
     RECT  50.641 7.632 51.008 11.784 ;
     RECT  50.137 13.68 51.008 19.368 ;
     RECT  50.677 20.928 51.008 21.096 ;
     RECT  49.817 22.08 51.008 24.792 ;
     RECT  50.041 26.64 51.008 27 ;
     RECT  50.101 28.08 51.008 28.104 ;
     RECT  50.869 29.52 51.008 38.424 ;
     RECT  50.869 39.552 51.008 86.616 ;
     RECT  49.745 87.792 51.008 88.44 ;
     RECT  50.461 89.472 51.008 92.424 ;
     RECT  51.008 2.148 51.112 92.892 ;
     RECT  51.112 2.418 51.304 92.622 ;
     RECT  51.304 87.84 51.473 92.424 ;
     RECT  51.304 86.496 51.509 86.616 ;
     RECT  51.304 4.272 51.581 4.872 ;
     RECT  51.304 6.768 51.581 16.68 ;
     RECT  51.304 29.328 51.587 29.544 ;
     RECT  51.304 25.92 51.617 27.576 ;
     RECT  51.473 87.84 51.617 91.656 ;
     RECT  51.617 25.92 51.725 27.384 ;
     RECT  51.304 31.872 51.731 32.04 ;
     RECT  51.304 35.76 51.797 40.488 ;
     RECT  51.304 41.664 51.833 74.808 ;
     RECT  51.833 44.352 51.869 74.808 ;
     RECT  51.731 31.872 51.875 31.896 ;
     RECT  51.304 33.072 51.877 34.536 ;
     RECT  51.581 6.768 51.905 11.4 ;
     RECT  51.581 12.432 51.905 16.68 ;
     RECT  51.877 33.552 51.905 34.536 ;
     RECT  51.833 41.664 51.941 43.32 ;
     RECT  51.905 33.6 52.201 34.536 ;
     RECT  51.905 12.528 52.229 16.68 ;
     RECT  51.304 18.048 52.297 18.072 ;
     RECT  51.581 4.272 52.307 4.296 ;
     RECT  51.797 36.336 52.309 40.488 ;
     RECT  52.201 33.888 52.316 34.536 ;
     RECT  52.309 36.336 52.373 41.016 ;
     RECT  51.869 44.352 52.373 72.504 ;
     RECT  52.373 36.624 52.396 41.016 ;
     RECT  52.316 33.888 52.403 35.352 ;
     RECT  52.373 44.352 52.403 45.672 ;
     RECT  52.403 33.888 52.409 34.44 ;
     RECT  51.304 75.936 52.412 85.416 ;
     RECT  51.509 86.496 52.412 86.52 ;
     RECT  51.725 25.92 52.553 26.856 ;
     RECT  52.412 75.936 52.556 86.52 ;
     RECT  51.869 73.488 52.585 74.808 ;
     RECT  52.556 75.936 52.585 86.712 ;
     RECT  51.304 30.624 52.657 30.648 ;
     RECT  52.403 44.448 52.661 45.672 ;
     RECT  51.304 20.16 52.693 24.792 ;
     RECT  52.229 12.528 52.739 15.288 ;
     RECT  51.587 29.328 52.805 29.352 ;
     RECT  52.585 73.488 52.94 86.712 ;
     RECT  51.617 87.84 52.94 91.464 ;
     RECT  52.229 16.272 52.981 16.68 ;
     RECT  52.297 18.048 52.981 18.6 ;
     RECT  52.693 19.584 52.981 24.792 ;
     RECT  52.373 46.848 52.981 72.504 ;
     RECT  52.94 73.488 52.981 91.464 ;
     RECT  52.553 25.92 53.021 26.808 ;
     RECT  51.941 42.288 53.027 43.32 ;
     RECT  53.027 43.008 53.053 43.32 ;
     RECT  52.981 46.848 53.057 91.464 ;
     RECT  52.739 14.112 53.075 15.288 ;
     RECT  53.057 61.728 53.129 91.464 ;
     RECT  51.905 6.768 53.197 9.96 ;
     RECT  52.657 30.624 53.201 31.464 ;
     RECT  53.057 46.848 53.381 60.696 ;
     RECT  52.409 34.224 53.485 34.44 ;
     RECT  53.129 61.968 53.489 91.464 ;
     RECT  52.297 5.76 53.509 5.784 ;
     RECT  53.197 6.768 53.509 10.056 ;
     RECT  52.661 44.64 53.557 45.672 ;
     RECT  53.509 5.76 53.561 10.056 ;
     RECT  53.305 29.616 53.564 29.64 ;
     RECT  53.201 30.624 53.564 30.888 ;
     RECT  53.489 83.088 53.597 91.464 ;
     RECT  52.981 16.272 53.629 16.776 ;
     RECT  53.089 41.616 53.629 41.976 ;
     RECT  53.053 43.008 53.629 43.416 ;
     RECT  53.557 44.64 53.629 45.864 ;
     RECT  53.381 46.848 53.629 48.12 ;
     RECT  53.489 61.968 53.633 82.104 ;
     RECT  51.905 11.232 53.665 11.4 ;
     RECT  53.597 83.088 53.699 91.224 ;
     RECT  53.561 8.88 53.705 10.056 ;
     RECT  53.075 14.496 53.737 15.288 ;
     RECT  53.629 16.272 53.737 17.016 ;
     RECT  53.629 43.008 53.747 48.12 ;
     RECT  52.396 36.624 53.804 40.392 ;
     RECT  53.737 14.496 53.809 17.016 ;
     RECT  52.981 18.048 53.809 24.792 ;
     RECT  53.485 34.224 53.809 34.968 ;
     RECT  53.804 36.384 53.809 40.392 ;
     RECT  53.747 47.28 53.813 48.12 ;
     RECT  53.809 34.224 53.845 40.392 ;
     RECT  53.629 41.376 53.845 41.976 ;
     RECT  53.699 83.088 53.957 84.36 ;
     RECT  53.561 5.76 53.989 7.464 ;
     RECT  53.809 14.496 53.989 24.792 ;
     RECT  53.021 25.92 53.989 25.944 ;
     RECT  53.699 85.488 53.993 91.224 ;
     RECT  53.989 14.496 54.061 25.944 ;
     RECT  53.633 61.968 54.083 80.952 ;
     RECT  53.665 11.136 54.097 11.4 ;
     RECT  52.739 12.528 54.097 13.08 ;
     RECT  53.845 34.224 54.097 41.976 ;
     RECT  54.061 14.16 54.101 25.944 ;
     RECT  54.097 11.136 54.133 13.08 ;
     RECT  53.564 29.616 54.133 30.888 ;
     RECT  54.133 29.472 54.169 30.888 ;
     RECT  54.097 33.264 54.169 41.976 ;
     RECT  53.381 49.2 54.349 60.696 ;
     RECT  54.083 61.968 54.349 76.968 ;
     RECT  54.083 78.096 54.425 80.952 ;
     RECT  54.101 25.92 54.457 25.944 ;
     RECT  54.169 32.352 54.469 41.976 ;
     RECT  53.747 43.008 54.469 46.248 ;
     RECT  54.469 32.352 54.497 46.248 ;
     RECT  53.633 82.08 54.517 82.104 ;
     RECT  53.957 83.088 54.517 84.072 ;
     RECT  53.813 48.096 54.556 48.12 ;
     RECT  54.169 29.472 54.565 31.032 ;
     RECT  54.349 49.2 54.605 76.968 ;
     RECT  54.101 14.16 54.611 24.792 ;
     RECT  53.993 88.272 54.641 91.224 ;
     RECT  54.605 62.688 54.677 76.968 ;
     RECT  54.425 78.672 54.709 80.952 ;
     RECT  54.517 82.08 54.709 84.072 ;
     RECT  54.497 32.352 54.749 44.088 ;
     RECT  54.641 88.272 54.749 90.6 ;
     RECT  54.497 45.12 54.781 46.248 ;
     RECT  54.781 45.12 54.821 47.112 ;
     RECT  53.705 8.88 54.853 9.96 ;
     RECT  53.993 85.488 54.853 87.24 ;
     RECT  54.677 62.688 54.857 76.344 ;
     RECT  54.133 11.136 54.893 13.128 ;
     RECT  54.457 25.92 54.893 26.856 ;
     RECT  54.857 62.688 54.929 76.248 ;
     RECT  54.749 89.664 54.929 90.6 ;
     RECT  54.709 78.672 54.949 84.072 ;
     RECT  54.853 85.44 54.949 87.24 ;
     RECT  54.949 78.672 54.995 87.24 ;
     RECT  54.565 29.328 54.997 31.032 ;
     RECT  54.605 49.2 54.997 61.608 ;
     RECT  54.893 11.136 55.105 12.456 ;
     RECT  54.749 88.272 55.109 88.344 ;
     RECT  54.997 29.328 55.141 31.224 ;
     RECT  54.611 19.824 55.145 24.792 ;
     RECT  54.929 62.688 55.181 75.864 ;
     RECT  55.145 22.56 55.213 24.792 ;
     RECT  54.893 25.92 55.213 26.808 ;
     RECT  55.141 29.328 55.213 31.368 ;
     RECT  54.749 32.352 55.213 34.248 ;
     RECT  54.853 8.544 55.249 9.96 ;
     RECT  54.821 45.168 55.249 47.112 ;
     RECT  55.105 11.04 55.253 12.456 ;
     RECT  54.997 48.336 55.325 61.608 ;
     RECT  54.611 14.16 55.361 18.84 ;
     RECT  54.995 86.832 55.397 87.24 ;
     RECT  54.749 35.232 55.427 44.088 ;
     RECT  55.361 14.16 55.433 18.6 ;
     RECT  55.145 19.824 55.433 21.144 ;
     RECT  55.249 8.496 55.573 9.96 ;
     RECT  55.253 11.04 55.573 12.36 ;
     RECT  53.989 5.712 55.609 7.464 ;
     RECT  55.573 8.448 55.609 12.36 ;
     RECT  55.325 50.112 55.717 61.608 ;
     RECT  55.181 62.688 55.717 75.432 ;
     RECT  54.995 78.672 55.753 85.512 ;
     RECT  55.109 88.32 55.753 88.344 ;
     RECT  55.249 45.168 55.897 47.304 ;
     RECT  55.325 48.336 55.897 49.032 ;
     RECT  55.609 5.712 56.005 12.36 ;
     RECT  55.753 77.952 56.005 85.512 ;
     RECT  55.427 44.064 56.041 44.088 ;
     RECT  55.897 45.168 56.041 49.032 ;
     RECT  56.005 5.472 56.149 12.36 ;
     RECT  55.397 87.216 56.185 87.24 ;
     RECT  55.753 88.32 56.185 88.488 ;
     RECT  55.213 29.328 56.293 34.248 ;
     RECT  56.041 44.064 56.293 49.032 ;
     RECT  55.717 50.112 56.293 75.432 ;
     RECT  56.185 87.216 56.293 88.92 ;
     RECT  56.149 4.656 56.408 12.36 ;
     RECT  55.433 14.16 56.408 14.856 ;
     RECT  55.433 15.84 56.408 18.6 ;
     RECT  55.433 20.304 56.408 21.144 ;
     RECT  55.213 22.56 56.408 26.808 ;
     RECT  56.293 29.04 56.408 34.248 ;
     RECT  55.427 35.232 56.408 42.936 ;
     RECT  56.293 44.064 56.408 75.432 ;
     RECT  56.005 77.04 56.408 85.512 ;
     RECT  56.293 87.216 56.408 89.496 ;
     RECT  54.929 90.576 56.408 90.6 ;
     RECT  56.408 2.148 56.512 92.892 ;
     RECT  56.512 2.418 56.704 92.622 ;
     RECT  56.704 29.616 56.819 48.36 ;
     RECT  56.704 76.944 56.837 81.48 ;
     RECT  56.704 82.8 56.908 84.168 ;
     RECT  56.704 3.024 57.017 3.912 ;
     RECT  56.819 44.976 57.125 48.36 ;
     RECT  56.704 5.28 57.197 9.192 ;
     RECT  56.819 29.616 57.305 43.8 ;
     RECT  57.197 7.92 57.341 9.192 ;
     RECT  56.704 85.2 57.341 85.224 ;
     RECT  57.017 3.312 57.413 3.912 ;
     RECT  57.125 46.992 57.413 48.36 ;
     RECT  57.305 34.176 57.449 43.8 ;
     RECT  56.704 90.576 57.449 90.6 ;
     RECT  56.837 76.944 57.485 80.952 ;
     RECT  56.704 11.04 57.521 13.128 ;
     RECT  57.521 11.136 57.557 13.128 ;
     RECT  56.704 14.208 57.557 19.608 ;
     RECT  57.557 14.208 57.593 17.208 ;
     RECT  56.704 87.216 57.593 88.92 ;
     RECT  56.704 22.56 57.629 28.056 ;
     RECT  57.413 3.312 57.665 3.336 ;
     RECT  57.449 34.176 57.665 41.784 ;
     RECT  57.629 22.56 57.697 24.792 ;
     RECT  57.593 87.792 57.697 88.92 ;
     RECT  57.341 7.92 57.701 9 ;
     RECT  56.704 49.728 57.724 74.76 ;
     RECT  57.697 22.176 57.781 24.792 ;
     RECT  57.449 43.296 57.877 43.8 ;
     RECT  57.125 44.976 57.877 45.96 ;
     RECT  57.197 5.28 57.884 6.936 ;
     RECT  57.697 86.16 57.913 86.184 ;
     RECT  57.877 43.296 57.923 45.96 ;
     RECT  57.557 13.056 57.949 13.128 ;
     RECT  57.593 14.208 57.949 14.232 ;
     RECT  57.884 4.896 57.971 6.936 ;
     RECT  57.485 77.52 57.985 80.952 ;
     RECT  57.665 34.176 57.989 41.16 ;
     RECT  57.985 77.52 57.997 81.336 ;
     RECT  57.913 86.16 58.025 86.76 ;
     RECT  57.949 13.056 58.033 14.232 ;
     RECT  58.025 86.16 58.061 86.664 ;
     RECT  56.908 82.992 58.093 84.168 ;
     RECT  57.593 15.648 58.169 17.208 ;
     RECT  57.989 34.176 58.169 34.248 ;
     RECT  57.923 43.776 58.169 45.96 ;
     RECT  58.165 75.84 58.201 75.864 ;
     RECT  58.093 82.992 58.201 84.408 ;
     RECT  58.033 14.208 58.205 14.232 ;
     RECT  58.169 15.648 58.205 17.112 ;
     RECT  56.704 20.736 58.205 20.76 ;
     RECT  57.305 29.616 58.237 33.144 ;
     RECT  58.033 13.056 58.241 13.128 ;
     RECT  57.997 79.2 58.261 81.336 ;
     RECT  58.201 82.608 58.261 84.408 ;
     RECT  57.629 26.16 58.277 28.056 ;
     RECT  58.169 43.776 58.313 45.48 ;
     RECT  58.261 79.2 58.348 84.408 ;
     RECT  57.724 49.728 58.381 61.608 ;
     RECT  57.724 62.736 58.385 74.76 ;
     RECT  57.971 5.856 58.421 6.936 ;
     RECT  58.201 75.84 58.508 76.344 ;
     RECT  57.997 77.52 58.508 78.12 ;
     RECT  58.508 75.84 58.549 78.12 ;
     RECT  57.557 11.136 58.556 11.832 ;
     RECT  56.704 91.872 58.561 91.896 ;
     RECT  58.237 29.52 58.565 33.144 ;
     RECT  58.348 82.608 58.565 84.408 ;
     RECT  57.557 18.768 58.597 19.608 ;
     RECT  58.241 13.056 58.601 13.08 ;
     RECT  58.385 73.488 58.601 74.76 ;
     RECT  57.697 87.792 58.633 89.496 ;
     RECT  58.556 10.704 58.643 11.832 ;
     RECT  58.597 18.192 58.669 19.608 ;
     RECT  57.781 22.32 58.669 24.792 ;
     RECT  58.277 26.16 58.669 26.28 ;
     RECT  58.277 27.648 58.669 28.056 ;
     RECT  58.565 29.52 58.669 32.856 ;
     RECT  57.989 35.232 58.705 41.16 ;
     RECT  58.421 6.432 58.721 6.936 ;
     RECT  58.205 15.648 58.741 17.064 ;
     RECT  58.669 22.32 58.817 26.28 ;
     RECT  58.633 87.792 58.817 90.264 ;
     RECT  58.669 27.648 58.853 32.856 ;
     RECT  58.561 91.344 58.853 91.896 ;
     RECT  58.643 11.136 58.892 11.832 ;
     RECT  58.381 49.2 58.933 61.608 ;
     RECT  58.853 91.344 58.933 91.368 ;
     RECT  58.169 34.224 58.957 34.248 ;
     RECT  58.705 35.232 58.957 41.208 ;
     RECT  58.348 79.2 58.969 80.952 ;
     RECT  58.892 11.136 58.979 12.408 ;
     RECT  58.061 86.16 58.993 86.616 ;
     RECT  58.721 6.432 59.029 6.984 ;
     RECT  59.029 6.432 59.033 7.032 ;
     RECT  58.385 62.736 59.069 72.504 ;
     RECT  59.033 6.528 59.177 7.032 ;
     RECT  58.741 14.256 59.249 17.064 ;
     RECT  58.565 82.656 59.269 84.408 ;
     RECT  58.969 79.2 59.308 80.76 ;
     RECT  58.817 26.16 59.317 26.28 ;
     RECT  57.413 46.992 59.353 47.736 ;
     RECT  58.993 85.872 59.353 86.616 ;
     RECT  59.249 14.784 59.393 17.064 ;
     RECT  58.669 18.192 59.393 20.232 ;
     RECT  58.313 44.064 59.425 45.48 ;
     RECT  58.933 49.2 59.425 61.704 ;
     RECT  59.069 62.736 59.425 72.312 ;
     RECT  58.601 74.112 59.425 74.76 ;
     RECT  58.549 75.792 59.425 78.12 ;
     RECT  59.353 85.872 59.425 86.664 ;
     RECT  58.817 87.792 59.425 89.544 ;
     RECT  59.177 6.528 59.465 6.936 ;
     RECT  57.701 8.256 59.537 9 ;
     RECT  59.425 43.536 59.557 45.576 ;
     RECT  59.353 46.992 59.557 47.928 ;
     RECT  59.393 15.024 59.641 17.064 ;
     RECT  58.417 42.288 59.641 42.312 ;
     RECT  59.641 42.192 59.677 42.312 ;
     RECT  59.557 43.536 59.677 47.928 ;
     RECT  59.269 82.656 59.677 84.648 ;
     RECT  58.933 90.768 59.681 91.368 ;
     RECT  59.308 80.304 59.717 80.76 ;
     RECT  59.641 15.024 59.749 17.112 ;
     RECT  59.393 18.192 59.749 19.512 ;
     RECT  58.817 22.32 59.749 25.128 ;
     RECT  59.749 21.408 59.857 25.128 ;
     RECT  59.317 26.16 59.857 26.856 ;
     RECT  58.853 29.328 59.857 32.856 ;
     RECT  58.957 34.224 59.857 41.208 ;
     RECT  59.677 82.032 59.857 84.648 ;
     RECT  59.425 85.872 59.857 89.544 ;
     RECT  59.857 82.032 59.891 89.544 ;
     RECT  59.677 42.192 59.897 47.928 ;
     RECT  59.857 29.328 59.9 41.208 ;
     RECT  59.897 42.192 59.9 47.736 ;
     RECT  59.681 91.152 59.9 91.368 ;
     RECT  59.425 74.112 59.965 78.12 ;
     RECT  59.308 79.2 59.965 79.224 ;
     RECT  59.9 29.328 59.969 47.736 ;
     RECT  59.9 91.152 59.987 91.848 ;
     RECT  59.965 74.112 60.001 79.224 ;
     RECT  60.001 73.488 60.005 79.224 ;
     RECT  59.969 29.328 60.109 47.448 ;
     RECT  59.425 49.2 60.145 72.312 ;
     RECT  60.005 73.488 60.145 75 ;
     RECT  60.145 49.2 60.257 75 ;
     RECT  59.537 8.256 60.277 8.28 ;
     RECT  58.979 11.136 60.329 11.544 ;
     RECT  60.005 75.984 60.329 79.224 ;
     RECT  60.329 11.136 60.365 11.16 ;
     RECT  59.891 82.032 60.371 86.616 ;
     RECT  60.371 82.032 60.397 84.648 ;
     RECT  59.465 6.528 60.401 6.84 ;
     RECT  59.857 21.408 60.473 26.856 ;
     RECT  60.329 75.984 60.473 77.976 ;
     RECT  60.473 76.08 60.581 77.976 ;
     RECT  60.257 49.2 60.649 74.952 ;
     RECT  60.371 85.872 60.653 86.616 ;
     RECT  59.749 15.024 60.661 19.512 ;
     RECT  59.821 5.136 60.721 5.16 ;
     RECT  60.109 29.04 60.725 47.448 ;
     RECT  60.721 5.136 60.761 6.072 ;
     RECT  60.725 31.872 60.761 47.448 ;
     RECT  60.473 21.696 60.793 26.856 ;
     RECT  58.853 28.032 60.793 28.056 ;
     RECT  60.649 48.816 60.803 74.952 ;
     RECT  60.661 15.024 60.829 19.992 ;
     RECT  60.793 21.696 60.829 28.056 ;
     RECT  60.725 29.04 60.829 30.888 ;
     RECT  60.329 79.008 60.829 79.224 ;
     RECT  59.717 80.304 60.829 80.328 ;
     RECT  60.397 81.696 60.829 84.648 ;
     RECT  60.277 7.968 60.86 8.28 ;
     RECT  59.857 9.36 60.86 9.384 ;
     RECT  60.86 7.968 60.865 9.384 ;
     RECT  59.891 87.792 60.908 89.544 ;
     RECT  59.497 13.632 60.937 13.656 ;
     RECT  60.829 14.784 60.937 19.992 ;
     RECT  60.908 87.696 61.081 89.544 ;
     RECT  60.865 7.968 61.117 9.864 ;
     RECT  58.957 3.696 61.297 3.72 ;
     RECT  60.653 86.016 61.333 86.616 ;
     RECT  60.581 76.368 61.441 77.976 ;
     RECT  60.829 79.008 61.441 80.328 ;
     RECT  59.987 91.2 61.513 91.848 ;
     RECT  60.761 44.736 61.729 47.448 ;
     RECT  61.297 2.832 61.808 3.72 ;
     RECT  60.761 5.76 61.808 6.072 ;
     RECT  61.117 7.344 61.808 9.864 ;
     RECT  60.937 13.632 61.808 19.992 ;
     RECT  60.829 21.696 61.808 30.888 ;
     RECT  60.761 31.872 61.808 43.368 ;
     RECT  61.729 44.688 61.808 47.448 ;
     RECT  60.803 48.816 61.808 48.984 ;
     RECT  60.803 50.592 61.808 74.952 ;
     RECT  61.441 76.368 61.808 80.328 ;
     RECT  60.829 81.36 61.808 84.648 ;
     RECT  61.333 86.016 61.808 86.664 ;
     RECT  61.081 87.696 61.808 89.88 ;
     RECT  61.513 91.2 61.808 91.944 ;
     RECT  61.808 2.148 61.912 92.892 ;
     RECT  61.912 2.418 62.104 92.622 ;
     RECT  62.104 85.728 62.129 89.736 ;
     RECT  62.104 16.08 62.165 27.192 ;
     RECT  62.104 30.72 62.201 32.616 ;
     RECT  62.165 16.272 62.237 27.192 ;
     RECT  62.104 2.832 62.273 2.856 ;
     RECT  62.104 8.496 62.273 9.384 ;
     RECT  62.104 44.736 62.291 47.88 ;
     RECT  62.104 7.344 62.309 7.368 ;
     RECT  62.104 5.76 62.381 5.784 ;
     RECT  62.104 50.64 62.435 53.256 ;
     RECT  62.104 55.488 62.435 84.648 ;
     RECT  62.104 48.96 62.597 48.984 ;
     RECT  62.129 85.728 62.597 89.448 ;
     RECT  62.291 44.736 62.633 47.448 ;
     RECT  62.597 86.352 62.633 89.448 ;
     RECT  62.104 91.92 62.633 91.944 ;
     RECT  62.633 86.352 62.705 88.776 ;
     RECT  62.633 44.736 62.741 47.352 ;
     RECT  62.435 50.64 62.741 53.016 ;
     RECT  62.435 55.728 62.741 84.648 ;
     RECT  62.741 50.64 62.921 51.96 ;
     RECT  62.104 40.032 63.029 43.56 ;
     RECT  62.741 55.728 63.029 79.32 ;
     RECT  62.705 86.352 63.065 86.76 ;
     RECT  62.273 8.496 63.097 8.52 ;
     RECT  63.029 59.28 63.155 79.32 ;
     RECT  62.104 14.832 63.169 14.856 ;
     RECT  62.237 16.272 63.169 26.952 ;
     RECT  63.029 40.032 63.205 43.32 ;
     RECT  62.921 51.312 63.245 51.96 ;
     RECT  63.097 7.632 63.253 8.52 ;
     RECT  62.104 11.136 63.253 12.36 ;
     RECT  63.169 14.832 63.349 26.952 ;
     RECT  62.104 29.088 63.425 29.64 ;
     RECT  62.741 80.304 63.493 84.648 ;
     RECT  63.253 7.632 63.541 9.336 ;
     RECT  63.253 11.136 63.541 12.552 ;
     RECT  62.104 33.936 63.541 38.76 ;
     RECT  63.349 14.448 63.565 26.952 ;
     RECT  63.205 39.888 63.569 43.32 ;
     RECT  63.541 33.648 63.601 38.76 ;
     RECT  63.541 7.632 63.628 12.552 ;
     RECT  63.601 33.648 63.637 39.048 ;
     RECT  63.493 80.304 63.637 85.272 ;
     RECT  63.065 86.352 63.637 86.664 ;
     RECT  62.705 88.08 63.673 88.776 ;
     RECT  62.201 30.72 63.685 32.328 ;
     RECT  63.637 33.456 63.685 39.048 ;
     RECT  63.421 6.288 63.709 6.456 ;
     RECT  63.628 7.632 63.709 9.528 ;
     RECT  62.741 44.736 63.745 46.824 ;
     RECT  63.155 59.856 63.781 79.32 ;
     RECT  63.637 80.304 63.781 86.664 ;
     RECT  63.709 6.288 63.817 9.528 ;
     RECT  63.745 44.64 63.829 46.824 ;
     RECT  63.569 40.128 63.875 43.32 ;
     RECT  63.425 29.136 63.889 29.64 ;
     RECT  63.685 30.72 63.889 39.048 ;
     RECT  63.673 88.08 63.925 89.496 ;
     RECT  63.875 40.128 63.965 42.744 ;
     RECT  63.277 90.576 64.033 90.6 ;
     RECT  63.029 55.728 64.141 57.864 ;
     RECT  63.781 59.856 64.141 86.664 ;
     RECT  64.141 55.728 64.177 58.152 ;
     RECT  63.628 10.8 64.213 12.552 ;
     RECT  63.565 13.824 64.213 26.952 ;
     RECT  62.741 52.992 64.249 53.016 ;
     RECT  63.817 2.256 64.253 2.28 ;
     RECT  64.177 50.16 64.285 50.184 ;
     RECT  63.245 51.312 64.285 51.336 ;
     RECT  64.177 54.96 64.285 58.152 ;
     RECT  64.213 10.8 64.325 26.952 ;
     RECT  64.285 50.16 64.325 51.336 ;
     RECT  63.925 87.696 64.357 89.496 ;
     RECT  64.033 90.576 64.357 90.792 ;
     RECT  64.249 52.992 64.393 53.592 ;
     RECT  64.285 54.912 64.393 58.152 ;
     RECT  63.745 5.088 64.501 5.112 ;
     RECT  63.817 6.144 64.501 9.528 ;
     RECT  64.325 10.8 64.541 16.44 ;
     RECT  64.357 27.984 64.541 28.008 ;
     RECT  64.393 52.992 64.577 58.152 ;
     RECT  63.889 29.136 64.645 39.048 ;
     RECT  63.965 40.128 64.645 42.312 ;
     RECT  64.141 59.28 64.645 86.664 ;
     RECT  64.357 87.696 64.645 90.792 ;
     RECT  64.541 14.688 64.649 16.392 ;
     RECT  64.645 59.136 64.649 90.792 ;
     RECT  63.241 3.936 64.681 3.96 ;
     RECT  64.501 5.088 64.681 9.528 ;
     RECT  64.649 59.136 64.757 79.272 ;
     RECT  64.577 53.088 64.865 58.152 ;
     RECT  64.825 28.128 64.885 28.152 ;
     RECT  64.645 29.136 64.885 42.312 ;
     RECT  64.757 75.936 64.973 79.272 ;
     RECT  64.141 92.304 64.981 92.328 ;
     RECT  64.681 3.936 65.005 9.528 ;
     RECT  64.541 10.8 65.005 13.32 ;
     RECT  64.885 28.128 65.009 42.312 ;
     RECT  63.829 44.352 65.009 46.824 ;
     RECT  64.865 54.672 65.036 58.152 ;
     RECT  64.757 59.136 65.036 74.904 ;
     RECT  64.981 91.776 65.088 92.328 ;
     RECT  64.325 17.616 65.117 26.664 ;
     RECT  65.009 46.752 65.117 46.824 ;
     RECT  64.649 80.304 65.149 90.792 ;
     RECT  65.088 91.776 65.149 91.896 ;
     RECT  65.009 28.128 65.171 28.344 ;
     RECT  65.036 54.672 65.189 74.904 ;
     RECT  64.861 2.88 65.293 2.904 ;
     RECT  65.005 3.936 65.293 13.32 ;
     RECT  64.865 53.088 65.297 53.592 ;
     RECT  65.149 80.304 65.333 91.896 ;
     RECT  65.333 80.304 65.369 88.392 ;
     RECT  64.325 50.256 65.372 51.336 ;
     RECT  65.117 46.8 65.401 46.824 ;
     RECT  63.961 47.856 65.401 47.88 ;
     RECT  65.372 49.92 65.459 51.336 ;
     RECT  65.189 54.672 65.459 74.52 ;
     RECT  65.171 28.128 65.509 28.248 ;
     RECT  65.117 20.496 65.557 26.664 ;
     RECT  65.509 27.984 65.557 28.248 ;
     RECT  65.459 50.688 65.612 51.336 ;
     RECT  64.973 75.936 65.644 79.224 ;
     RECT  65.293 2.88 65.651 13.32 ;
     RECT  65.459 54.672 65.651 55.896 ;
     RECT  65.651 54.672 65.692 55.848 ;
     RECT  65.009 29.328 65.699 42.312 ;
     RECT  65.612 50.688 65.699 52.152 ;
     RECT  65.692 54.672 65.699 54.696 ;
     RECT  65.333 89.472 65.729 91.896 ;
     RECT  65.401 46.8 65.765 47.88 ;
     RECT  65.369 84.624 65.837 88.392 ;
     RECT  65.797 43.296 65.893 43.32 ;
     RECT  65.009 44.352 65.893 45.288 ;
     RECT  65.651 4.56 65.932 13.32 ;
     RECT  65.699 50.688 65.945 51.336 ;
     RECT  65.692 55.824 66.017 55.848 ;
     RECT  65.932 6.432 66.049 13.32 ;
     RECT  64.649 14.784 66.049 16.392 ;
     RECT  65.117 17.616 66.049 19.512 ;
     RECT  65.893 43.296 66.049 45.288 ;
     RECT  65.699 29.328 66.053 42.216 ;
     RECT  65.651 2.88 66.121 3.432 ;
     RECT  66.049 6.432 66.121 13.704 ;
     RECT  66.049 14.784 66.121 19.512 ;
     RECT  65.369 80.304 66.197 83.64 ;
     RECT  65.644 75.936 66.229 78.744 ;
     RECT  65.729 91.68 66.265 91.896 ;
     RECT  65.837 84.72 66.337 88.392 ;
     RECT  65.729 89.472 66.337 90.648 ;
     RECT  66.121 6.432 66.625 19.512 ;
     RECT  65.557 20.496 66.625 28.248 ;
     RECT  65.459 57.024 66.668 74.52 ;
     RECT  66.337 84.72 66.709 90.648 ;
     RECT  66.265 91.68 66.709 92.232 ;
     RECT  66.053 29.376 66.733 42.216 ;
     RECT  66.049 43.296 66.733 45.72 ;
     RECT  65.945 50.688 66.913 50.76 ;
     RECT  66.565 52.416 66.913 52.44 ;
     RECT  66.668 56.928 66.913 74.52 ;
     RECT  65.932 4.56 66.985 5.256 ;
     RECT  66.625 6.432 66.985 28.248 ;
     RECT  65.765 46.8 67.021 47.352 ;
     RECT  66.049 48.48 67.021 49.608 ;
     RECT  65.297 53.568 67.021 53.592 ;
     RECT  66.913 56.064 67.021 74.52 ;
     RECT  66.229 75.696 67.021 78.744 ;
     RECT  66.121 2.496 67.208 3.432 ;
     RECT  66.985 4.56 67.208 28.248 ;
     RECT  66.733 29.376 67.208 45.72 ;
     RECT  67.021 46.8 67.208 49.608 ;
     RECT  66.913 50.688 67.208 52.44 ;
     RECT  67.021 53.568 67.208 78.744 ;
     RECT  66.197 80.304 67.208 83.496 ;
     RECT  66.709 84.72 67.208 92.232 ;
     RECT  67.208 2.148 67.312 92.892 ;
     RECT  67.312 2.418 67.504 92.622 ;
     RECT  67.504 27.648 67.565 27.96 ;
     RECT  67.504 46.656 67.619 83.112 ;
     RECT  67.504 29.04 67.715 45.288 ;
     RECT  67.504 84.336 67.763 91.176 ;
     RECT  67.504 2.496 67.781 3.384 ;
     RECT  67.619 50.64 67.897 83.112 ;
     RECT  67.619 46.656 67.933 49.56 ;
     RECT  67.504 4.656 67.969 26.28 ;
     RECT  67.715 29.04 67.969 44.712 ;
     RECT  67.933 46.656 68.069 47.16 ;
     RECT  67.504 92.16 68.141 92.232 ;
     RECT  67.565 27.84 68.177 27.96 ;
     RECT  67.969 15.216 68.249 26.28 ;
     RECT  67.969 4.656 68.285 14.232 ;
     RECT  67.969 29.184 68.285 44.712 ;
     RECT  67.763 84.864 68.387 91.176 ;
     RECT  68.249 17.616 68.429 18.744 ;
     RECT  68.285 42.24 68.465 44.712 ;
     RECT  68.285 4.656 68.485 13.896 ;
     RECT  68.285 29.184 68.501 41.16 ;
     RECT  67.781 2.496 68.573 3.24 ;
     RECT  68.485 4.512 68.573 13.896 ;
     RECT  68.249 19.872 68.573 26.28 ;
     RECT  68.141 92.208 68.605 92.232 ;
     RECT  67.897 50.64 68.62 79.176 ;
     RECT  68.501 29.184 68.681 30.12 ;
     RECT  67.933 48.432 68.713 49.56 ;
     RECT  68.605 92.208 68.713 92.328 ;
     RECT  68.177 27.84 68.749 27.864 ;
     RECT  68.069 46.656 68.785 46.68 ;
     RECT  68.749 27.312 68.789 27.864 ;
     RECT  68.573 2.496 68.897 2.904 ;
     RECT  68.573 20.88 68.924 26.28 ;
     RECT  68.789 27.312 68.924 27.336 ;
     RECT  68.681 29.184 68.933 29.928 ;
     RECT  68.713 48.432 69.001 49.608 ;
     RECT  68.62 50.64 69.001 53.592 ;
     RECT  69.001 48.432 69.005 53.592 ;
     RECT  68.387 84.864 69.005 84.888 ;
     RECT  68.924 20.88 69.011 27.336 ;
     RECT  68.573 4.848 69.041 13.896 ;
     RECT  69.005 52.272 69.041 53.592 ;
     RECT  68.387 85.968 69.077 86.712 ;
     RECT  69.041 4.848 69.113 12.504 ;
     RECT  68.785 46.128 69.155 46.68 ;
     RECT  69.005 48.432 69.155 51.096 ;
     RECT  68.62 54.912 69.181 79.176 ;
     RECT  67.897 80.304 69.181 83.112 ;
     RECT  69.041 13.872 69.253 13.896 ;
     RECT  68.249 15.216 69.253 16.536 ;
     RECT  68.501 31.344 69.253 41.16 ;
     RECT  69.181 54.912 69.265 83.112 ;
     RECT  69.253 13.872 69.293 16.536 ;
     RECT  69.253 31.344 69.325 41.208 ;
     RECT  68.465 42.24 69.325 43.32 ;
     RECT  69.265 54.912 69.337 79.032 ;
     RECT  68.465 44.448 69.356 44.712 ;
     RECT  69.155 46.128 69.365 46.152 ;
     RECT  69.265 80.304 69.401 83.112 ;
     RECT  69.293 15.888 69.437 16.536 ;
     RECT  69.356 44.448 69.469 44.76 ;
     RECT  69.437 16.032 69.493 16.536 ;
     RECT  68.429 17.616 69.493 17.928 ;
     RECT  68.387 88.08 69.505 91.176 ;
     RECT  68.713 92.208 69.505 92.424 ;
     RECT  69.155 48.768 69.509 51.096 ;
     RECT  69.337 54.912 69.581 78.6 ;
     RECT  69.041 52.56 69.587 53.592 ;
     RECT  69.581 54.912 69.653 78.552 ;
     RECT  69.113 4.848 69.685 8.904 ;
     RECT  69.325 31.344 69.721 43.32 ;
     RECT  69.505 88.08 69.724 92.424 ;
     RECT  69.685 4.272 69.772 8.904 ;
     RECT  68.573 19.872 69.793 19.896 ;
     RECT  69.509 48.864 69.797 51.096 ;
     RECT  69.653 54.912 69.797 75.144 ;
     RECT  69.493 16.032 69.829 17.928 ;
     RECT  69.587 52.56 69.869 52.776 ;
     RECT  69.797 54.912 69.869 55.32 ;
     RECT  69.011 27.312 69.901 27.336 ;
     RECT  69.797 56.304 69.905 75.144 ;
     RECT  69.721 31.2 69.923 43.368 ;
     RECT  68.933 29.184 69.925 29.88 ;
     RECT  69.923 31.2 69.925 42.552 ;
     RECT  69.469 44.448 69.941 45.432 ;
     RECT  68.897 2.88 69.977 2.904 ;
     RECT  69.401 80.928 69.98 83.112 ;
     RECT  69.925 29.184 70.013 42.552 ;
     RECT  69.869 52.56 70.06 52.728 ;
     RECT  69.98 80.928 70.067 83.4 ;
     RECT  70.021 84.384 70.081 84.408 ;
     RECT  70.013 31.872 70.085 42.552 ;
     RECT  69.113 9.888 70.121 12.504 ;
     RECT  70.081 84.384 70.153 84.936 ;
     RECT  70.013 29.184 70.157 30.648 ;
     RECT  70.085 33.696 70.157 42.408 ;
     RECT  69.941 45.408 70.157 45.432 ;
     RECT  70.153 84.384 70.157 85.224 ;
     RECT  69.772 4.656 70.189 8.904 ;
     RECT  70.121 9.888 70.189 12.36 ;
     RECT  69.077 86.352 70.189 86.712 ;
     RECT  69.724 88.08 70.189 90.6 ;
     RECT  70.189 4.656 70.193 12.36 ;
     RECT  69.724 91.92 70.229 92.424 ;
     RECT  70.193 4.656 70.259 12.12 ;
     RECT  70.259 6.816 70.265 12.12 ;
     RECT  70.225 54.672 70.355 54.696 ;
     RECT  69.829 16.032 70.405 18.216 ;
     RECT  69.797 49.2 70.405 51.096 ;
     RECT  70.229 92.208 70.409 92.424 ;
     RECT  69.293 13.872 70.441 14.808 ;
     RECT  70.405 16.032 70.441 18.504 ;
     RECT  70.441 13.872 70.445 18.504 ;
     RECT  70.405 49.2 70.445 51.144 ;
     RECT  70.259 4.656 70.481 5.736 ;
     RECT  70.157 84.912 70.513 85.224 ;
     RECT  70.189 86.352 70.513 90.6 ;
     RECT  70.513 84.912 70.517 90.6 ;
     RECT  69.011 20.88 70.621 26.28 ;
     RECT  69.901 27.312 70.621 27.768 ;
     RECT  69.793 19.776 70.657 19.896 ;
     RECT  70.445 50.256 70.661 51.144 ;
     RECT  70.405 79.776 70.693 79.8 ;
     RECT  70.067 80.928 70.693 83.16 ;
     RECT  70.481 4.656 70.697 5.304 ;
     RECT  70.157 33.84 70.697 42.408 ;
     RECT  70.445 14.208 70.729 18.504 ;
     RECT  70.657 19.584 70.729 19.896 ;
     RECT  70.517 84.912 70.733 88.968 ;
     RECT  69.905 56.352 70.765 75.144 ;
     RECT  69.653 76.272 70.765 78.552 ;
     RECT  70.517 90.048 70.801 90.6 ;
     RECT  70.693 79.776 70.873 83.16 ;
     RECT  70.621 20.88 70.877 27.768 ;
     RECT  70.06 52.704 70.877 52.728 ;
     RECT  70.085 31.872 70.913 32.232 ;
     RECT  70.765 56.352 70.945 78.552 ;
     RECT  70.661 50.256 70.949 50.52 ;
     RECT  70.157 29.76 70.981 30.648 ;
     RECT  70.877 22.416 70.985 27.768 ;
     RECT  70.949 50.256 71.027 50.28 ;
     RECT  70.873 79.536 71.027 83.16 ;
     RECT  70.265 6.816 71.057 11.976 ;
     RECT  70.697 35.184 71.125 42.408 ;
     RECT  71.057 9.024 71.129 11.976 ;
     RECT  70.985 22.416 71.129 27.336 ;
     RECT  70.657 46.464 71.129 46.488 ;
     RECT  70.733 84.912 71.129 85.224 ;
     RECT  71.125 35.184 71.165 42.6 ;
     RECT  70.945 56.016 71.233 78.552 ;
     RECT  71.129 9.12 71.237 11.976 ;
     RECT  71.165 35.184 71.237 41.016 ;
     RECT  70.981 29.76 71.273 31.032 ;
     RECT  71.237 35.232 71.309 41.016 ;
     RECT  71.273 29.76 71.381 30.648 ;
     RECT  71.309 35.232 71.453 40.968 ;
     RECT  71.165 42 71.485 42.6 ;
     RECT  70.733 86.592 71.485 88.968 ;
     RECT  71.233 55.632 71.489 78.552 ;
     RECT  71.485 86.592 71.509 89.064 ;
     RECT  70.801 90.048 71.509 90.648 ;
     RECT  71.489 56.016 71.521 78.552 ;
     RECT  71.027 80.208 71.521 83.16 ;
     RECT  71.089 53.568 71.561 53.592 ;
     RECT  70.913 32.208 71.629 32.232 ;
     RECT  70.697 33.84 71.629 33.864 ;
     RECT  70.697 4.992 71.665 5.304 ;
     RECT  71.129 85.152 71.701 85.224 ;
     RECT  71.509 86.592 71.701 90.648 ;
     RECT  71.125 3.408 71.737 3.432 ;
     RECT  71.381 29.76 71.737 29.88 ;
     RECT  71.269 13.056 71.845 13.08 ;
     RECT  70.729 14.208 71.845 19.896 ;
     RECT  71.485 42 71.845 42.744 ;
     RECT  71.737 28.992 71.881 29.88 ;
     RECT  71.521 80.208 71.953 83.208 ;
     RECT  71.521 56.016 72.025 78.744 ;
     RECT  71.665 4.992 72.037 5.736 ;
     RECT  71.845 13.056 72.133 19.896 ;
     RECT  70.877 20.88 72.133 21.144 ;
     RECT  71.701 85.152 72.169 90.648 ;
     RECT  72.169 84.432 72.241 90.648 ;
     RECT  71.453 35.232 72.277 40.872 ;
     RECT  70.409 92.304 72.277 92.424 ;
     RECT  71.057 6.816 72.313 7.992 ;
     RECT  71.237 9.12 72.313 11.544 ;
     RECT  71.881 28.944 72.349 29.88 ;
     RECT  72.037 4.656 72.385 5.736 ;
     RECT  72.277 34.896 72.428 40.872 ;
     RECT  71.845 42 72.428 42.888 ;
     RECT  72.025 56.016 72.428 78.888 ;
     RECT  71.953 80.208 72.428 83.256 ;
     RECT  71.629 32.208 72.457 33.864 ;
     RECT  72.313 6.816 72.469 11.544 ;
     RECT  72.349 28.944 72.565 30.168 ;
     RECT  71.737 2.832 72.608 3.432 ;
     RECT  72.385 4.512 72.608 5.736 ;
     RECT  72.469 6.816 72.608 11.976 ;
     RECT  72.133 13.056 72.608 21.144 ;
     RECT  71.129 22.416 72.608 26.568 ;
     RECT  72.085 27.936 72.608 27.96 ;
     RECT  72.565 28.944 72.608 30.36 ;
     RECT  72.457 31.488 72.608 33.864 ;
     RECT  72.428 34.896 72.608 42.888 ;
     RECT  72.061 45.408 72.608 45.432 ;
     RECT  72.061 46.56 72.608 46.584 ;
     RECT  70.405 47.616 72.608 47.64 ;
     RECT  70.445 49.2 72.608 49.224 ;
     RECT  72.428 56.016 72.608 83.256 ;
     RECT  72.241 84.432 72.608 91.176 ;
     RECT  72.277 92.208 72.608 92.424 ;
     RECT  72.608 2.148 72.712 92.892 ;
     RECT  72.712 2.418 72.904 92.622 ;
     RECT  72.904 11.184 72.929 11.976 ;
     RECT  72.904 22.272 73.001 24.984 ;
     RECT  72.904 14.544 73.037 17.112 ;
     RECT  72.904 75.408 73.073 78.648 ;
     RECT  72.904 27.456 73.181 27.864 ;
     RECT  72.904 19.632 73.253 19.656 ;
     RECT  72.904 84.336 73.283 91.176 ;
     RECT  72.904 80.064 73.289 80.856 ;
     RECT  73.283 88.704 73.289 91.176 ;
     RECT  72.904 3.216 73.361 10.2 ;
     RECT  73.361 3.216 73.397 9.912 ;
     RECT  73.397 5.088 73.433 9.912 ;
     RECT  72.904 46.56 73.469 47.16 ;
     RECT  73.181 27.648 73.505 27.864 ;
     RECT  73.289 80.064 73.505 80.808 ;
     RECT  73.433 5.088 73.523 8.568 ;
     RECT  72.904 54.672 73.523 74.136 ;
     RECT  73.433 9.744 73.541 9.912 ;
     RECT  73.073 75.408 73.541 76.584 ;
     RECT  73.541 75.984 73.577 76.584 ;
     RECT  72.904 82.224 73.577 83.256 ;
     RECT  73.541 9.84 73.613 9.912 ;
     RECT  73.037 15.456 73.649 17.112 ;
     RECT  73.505 27.648 73.649 27.672 ;
     RECT  73.283 84.336 73.721 87.576 ;
     RECT  73.523 56.544 73.757 74.136 ;
     RECT  73.721 84.336 73.757 84.36 ;
     RECT  73.649 15.504 73.793 17.112 ;
     RECT  73.613 9.888 73.865 9.912 ;
     RECT  73.721 85.392 73.865 87.576 ;
     RECT  72.904 18.192 73.897 18.456 ;
     RECT  73.001 22.272 73.909 24.552 ;
     RECT  72.904 51.84 74.005 51.864 ;
     RECT  73.523 54.672 74.005 55.56 ;
     RECT  73.073 77.856 74.005 78.648 ;
     RECT  73.505 80.064 74.005 80.088 ;
     RECT  72.904 92.4 74.005 92.424 ;
     RECT  73.397 3.216 74.045 4.104 ;
     RECT  73.523 5.184 74.045 8.568 ;
     RECT  73.793 15.6 74.045 17.112 ;
     RECT  72.904 49.2 74.077 49.224 ;
     RECT  74.077 49.2 74.113 49.8 ;
     RECT  74.005 54.576 74.185 55.56 ;
     RECT  74.045 16.032 74.221 17.112 ;
     RECT  73.577 76.272 74.221 76.584 ;
     RECT  72.904 28.944 74.261 33.576 ;
     RECT  72.904 34.608 74.261 40.872 ;
     RECT  74.005 77.856 74.297 80.088 ;
     RECT  74.293 11.328 74.329 11.352 ;
     RECT  74.185 53.712 74.329 55.56 ;
     RECT  73.289 88.704 74.329 91.08 ;
     RECT  74.005 92.4 74.329 92.664 ;
     RECT  74.221 76.272 74.365 76.824 ;
     RECT  73.909 21.648 74.401 24.552 ;
     RECT  74.045 3.84 74.477 4.104 ;
     RECT  73.469 46.608 74.513 47.16 ;
     RECT  74.261 34.896 74.545 40.872 ;
     RECT  74.005 51.408 74.545 51.864 ;
     RECT  74.261 28.944 74.581 33.048 ;
     RECT  74.477 4.08 74.617 4.104 ;
     RECT  74.045 5.184 74.617 8.424 ;
     RECT  74.113 49.2 74.617 50.376 ;
     RECT  74.297 78.096 74.617 80.088 ;
     RECT  74.329 53.52 74.629 55.56 ;
     RECT  73.757 56.544 74.629 73.608 ;
     RECT  73.865 87.024 74.629 87.576 ;
     RECT  74.329 88.704 74.629 92.664 ;
     RECT  74.401 21.408 74.653 24.552 ;
     RECT  74.629 87.024 74.675 92.664 ;
     RECT  72.904 42.288 74.677 43.56 ;
     RECT  72.904 45.264 74.677 45.288 ;
     RECT  74.077 2.736 74.693 2.76 ;
     RECT  74.675 92.64 74.693 92.664 ;
     RECT  74.513 46.656 74.725 47.16 ;
     RECT  74.329 10.848 74.729 11.352 ;
     RECT  74.617 74.928 74.729 74.952 ;
     RECT  74.653 21.408 74.761 24.888 ;
     RECT  72.904 26.256 74.761 26.28 ;
     RECT  74.675 91.056 74.801 91.08 ;
     RECT  74.617 4.08 74.837 8.424 ;
     RECT  74.581 28.416 74.905 33.048 ;
     RECT  74.545 51.408 74.909 52.248 ;
     RECT  72.904 13.056 74.941 13.08 ;
     RECT  74.221 16.032 74.941 17.16 ;
     RECT  73.897 18.192 74.941 18.792 ;
     RECT  74.905 28.032 74.941 33.048 ;
     RECT  74.545 34.896 74.941 41.016 ;
     RECT  74.677 42.288 74.941 45.288 ;
     RECT  73.865 85.392 74.977 85.896 ;
     RECT  74.941 34.896 74.981 45.288 ;
     RECT  74.761 21.408 75.004 26.28 ;
     RECT  74.725 46.656 75.017 47.88 ;
     RECT  74.617 48.864 75.049 50.376 ;
     RECT  74.909 51.408 75.049 52.008 ;
     RECT  74.837 4.272 75.052 8.424 ;
     RECT  75.017 47.136 75.068 47.88 ;
     RECT  75.049 48.864 75.068 52.008 ;
     RECT  75.068 47.136 75.089 52.008 ;
     RECT  75.052 6.864 75.121 8.424 ;
     RECT  74.629 53.52 75.121 73.608 ;
     RECT  74.761 74.64 75.121 74.664 ;
     RECT  75.121 53.52 75.125 74.664 ;
     RECT  74.981 34.896 75.155 45.192 ;
     RECT  75.089 47.136 75.161 47.16 ;
     RECT  74.941 16.032 75.193 18.792 ;
     RECT  74.941 12.72 75.221 13.08 ;
     RECT  74.617 78.096 75.251 80.952 ;
     RECT  75.052 4.272 75.269 5.352 ;
     RECT  75.193 15.888 75.301 18.792 ;
     RECT  75.221 11.952 75.305 13.08 ;
     RECT  75.089 48.288 75.305 52.008 ;
     RECT  75.004 25.584 75.337 26.28 ;
     RECT  74.941 27.648 75.337 33.048 ;
     RECT  75.121 6.864 75.341 8.952 ;
     RECT  75.004 21.408 75.347 24.552 ;
     RECT  75.251 78.096 75.373 80.376 ;
     RECT  75.301 15.888 75.377 19.368 ;
     RECT  75.347 21.408 75.409 21.432 ;
     RECT  74.977 84.96 75.409 85.896 ;
     RECT  74.675 87.024 75.409 90.072 ;
     RECT  75.377 18.432 75.445 19.368 ;
     RECT  74.365 76.272 75.445 76.92 ;
     RECT  75.373 78 75.449 80.376 ;
     RECT  75.305 48.288 75.485 49.8 ;
     RECT  75.449 78 75.491 80.328 ;
     RECT  75.337 52.992 75.521 53.16 ;
     RECT  75.337 25.584 75.589 33.288 ;
     RECT  75.125 54.144 75.593 74.664 ;
     RECT  75.589 25.584 75.596 33.576 ;
     RECT  75.409 84.96 75.665 90.072 ;
     RECT  75.305 12.72 75.692 13.08 ;
     RECT  75.445 76.272 75.733 77.016 ;
     RECT  75.491 78 75.733 79.176 ;
     RECT  75.305 51.408 75.737 52.008 ;
     RECT  75.445 18.432 75.74 19.416 ;
     RECT  75.733 76.272 75.773 79.176 ;
     RECT  75.341 7.296 75.779 8.952 ;
     RECT  75.692 12.72 75.779 13.512 ;
     RECT  75.377 15.888 75.779 17.304 ;
     RECT  75.74 18.432 75.779 19.944 ;
     RECT  73.577 82.416 75.781 83.256 ;
     RECT  75.781 82.416 75.805 83.496 ;
     RECT  75.779 18.768 75.827 19.944 ;
     RECT  75.773 76.272 75.829 76.584 ;
     RECT  75.596 25.584 75.845 33.816 ;
     RECT  75.491 80.304 75.845 80.328 ;
     RECT  75.829 75.936 75.875 76.584 ;
     RECT  75.737 51.696 75.881 52.008 ;
     RECT  75.779 15.888 75.917 16.536 ;
     RECT  75.409 20.976 75.949 21.432 ;
     RECT  75.773 77.664 75.989 79.176 ;
     RECT  75.805 82.416 76.019 83.64 ;
     RECT  74.729 10.848 76.057 10.872 ;
     RECT  75.269 4.896 76.061 5.352 ;
     RECT  75.593 54.144 76.061 74.424 ;
     RECT  75.347 22.464 76.069 24.552 ;
     RECT  75.845 25.584 76.069 33.288 ;
     RECT  75.155 34.896 76.093 41.496 ;
     RECT  75.155 42.672 76.093 45.192 ;
     RECT  76.057 46.752 76.093 46.92 ;
     RECT  76.057 10.32 76.129 10.872 ;
     RECT  76.093 34.416 76.133 41.496 ;
     RECT  75.665 85.392 76.165 90.072 ;
     RECT  75.989 78.672 76.169 79.176 ;
     RECT  75.881 51.936 76.213 52.008 ;
     RECT  75.521 52.992 76.213 53.016 ;
     RECT  76.093 42.672 76.277 46.92 ;
     RECT  75.949 20.64 76.349 21.432 ;
     RECT  75.917 15.888 76.353 16.392 ;
     RECT  76.061 54.144 76.355 57.336 ;
     RECT  75.779 12.72 76.357 13.32 ;
     RECT  76.165 85.392 76.403 90.648 ;
     RECT  75.485 48.288 76.561 49.704 ;
     RECT  76.061 58.512 76.673 74.424 ;
     RECT  76.213 51.936 76.7 53.016 ;
     RECT  76.355 54.144 76.7 54.168 ;
     RECT  76.019 82.608 76.741 83.64 ;
     RECT  76.349 21.408 76.745 21.432 ;
     RECT  76.069 22.464 76.745 33.288 ;
     RECT  76.7 51.936 76.745 54.168 ;
     RECT  75.989 77.664 76.745 77.688 ;
     RECT  76.403 85.392 76.781 90.072 ;
     RECT  76.745 51.936 76.787 53.64 ;
     RECT  76.357 12.528 76.889 13.32 ;
     RECT  76.277 42.672 76.921 42.696 ;
     RECT  76.741 82.608 76.921 84.072 ;
     RECT  76.781 85.392 76.921 89.16 ;
     RECT  76.921 42.192 76.961 42.696 ;
     RECT  76.745 30.24 76.981 33.288 ;
     RECT  76.133 34.416 76.981 40.632 ;
     RECT  76.169 79.152 76.997 79.176 ;
     RECT  76.353 15.408 77.029 16.392 ;
     RECT  76.669 17.616 77.029 17.64 ;
     RECT  75.779 7.296 77.073 7.992 ;
     RECT  77.073 7.296 77.125 8.808 ;
     RECT  75.827 18.768 77.137 19.368 ;
     RECT  76.355 55.248 77.173 57.336 ;
     RECT  76.673 58.512 77.173 73.512 ;
     RECT  75.445 81.408 77.173 81.432 ;
     RECT  77.125 7.248 77.209 8.808 ;
     RECT  76.129 10.32 77.209 10.92 ;
     RECT  77.101 78.048 77.209 78.072 ;
     RECT  76.277 44.256 77.281 46.92 ;
     RECT  76.561 48.288 77.281 49.848 ;
     RECT  75.875 75.936 77.281 75.96 ;
     RECT  77.029 15.408 77.317 17.64 ;
     RECT  77.209 7.248 77.389 10.92 ;
     RECT  76.061 5.184 77.425 5.352 ;
     RECT  76.889 13.104 77.425 13.32 ;
     RECT  77.137 18.768 77.533 20.136 ;
     RECT  77.389 6.864 77.569 10.92 ;
     RECT  77.281 44.256 77.641 49.848 ;
     RECT  77.281 75.504 77.677 75.96 ;
     RECT  77.533 18.768 77.713 20.184 ;
     RECT  77.677 75.504 77.713 76.584 ;
     RECT  77.353 21.168 77.749 21.192 ;
     RECT  76.745 22.464 77.749 29.016 ;
     RECT  77.605 80.352 77.821 80.376 ;
     RECT  76.921 82.608 77.857 89.16 ;
     RECT  77.569 6.768 77.893 10.92 ;
     RECT  77.641 43.872 77.893 49.848 ;
     RECT  77.101 50.928 77.893 50.952 ;
     RECT  77.173 55.248 78.001 73.512 ;
     RECT  77.425 5.184 78.008 5.736 ;
     RECT  77.893 6.768 78.008 10.968 ;
     RECT  77.425 13.104 78.008 13.656 ;
     RECT  77.317 15.312 78.008 17.64 ;
     RECT  77.713 18.72 78.008 20.184 ;
     RECT  77.749 21.168 78.008 29.016 ;
     RECT  76.981 30.24 78.008 40.632 ;
     RECT  76.961 42.192 78.008 42.6 ;
     RECT  77.893 43.872 78.008 50.952 ;
     RECT  76.787 51.936 78.008 53.544 ;
     RECT  78.001 55.248 78.008 74.376 ;
     RECT  77.713 75.456 78.008 76.584 ;
     RECT  77.209 78.048 78.008 79.032 ;
     RECT  77.821 80.016 78.008 80.376 ;
     RECT  77.173 81.408 78.008 81.48 ;
     RECT  77.857 82.608 78.008 89.304 ;
     RECT  76.957 91.536 78.008 91.56 ;
     RECT  78.008 2.148 78.112 92.892 ;
     RECT  78.112 2.418 78.304 92.622 ;
     RECT  78.304 56.928 78.401 77.64 ;
     RECT  78.304 5.472 78.437 11.016 ;
     RECT  78.304 21.168 78.437 29.112 ;
     RECT  78.304 81.36 78.437 85.512 ;
     RECT  78.304 86.64 78.467 89.304 ;
     RECT  78.437 81.36 78.508 83.832 ;
     RECT  78.304 55.248 78.545 55.752 ;
     RECT  78.401 77.616 78.611 77.64 ;
     RECT  78.304 15.312 78.653 19.896 ;
     RECT  78.304 30.144 78.653 40.632 ;
     RECT  78.467 86.976 78.653 89.304 ;
     RECT  78.401 56.928 78.689 75.96 ;
     RECT  78.304 91.152 78.689 91.8 ;
     RECT  78.689 56.928 78.707 75.912 ;
     RECT  78.304 78.72 78.725 80.376 ;
     RECT  78.437 5.472 78.761 9.72 ;
     RECT  78.707 56.928 78.761 74.04 ;
     RECT  78.707 75.12 78.797 75.912 ;
     RECT  78.304 49.2 78.941 51.192 ;
     RECT  78.797 75.12 78.941 75.816 ;
     RECT  78.761 5.472 78.977 6.36 ;
     RECT  78.304 12.528 78.977 13.128 ;
     RECT  78.761 7.68 79.049 9.72 ;
     RECT  78.941 51.168 79.193 51.192 ;
     RECT  78.941 49.2 79.235 50.184 ;
     RECT  78.508 81.888 79.235 83.832 ;
     RECT  78.653 30.144 79.265 39.816 ;
     RECT  78.437 84.816 79.265 85.512 ;
     RECT  78.304 14.304 79.297 14.328 ;
     RECT  78.304 44.448 79.333 46.776 ;
     RECT  78.653 15.312 79.379 17.304 ;
     RECT  78.437 21.168 79.405 28.968 ;
     RECT  79.265 30.144 79.405 39.768 ;
     RECT  78.304 52.848 79.405 52.872 ;
     RECT  79.265 84.816 79.405 85.368 ;
     RECT  79.297 14.208 79.469 14.328 ;
     RECT  79.333 44.448 79.481 46.872 ;
     RECT  78.653 86.976 79.484 88.968 ;
     RECT  78.977 12.528 79.523 12.552 ;
     RECT  79.235 49.2 79.541 49.944 ;
     RECT  79.469 14.064 79.553 14.328 ;
     RECT  78.689 91.776 79.553 91.8 ;
     RECT  79.484 86.736 79.571 88.968 ;
     RECT  79.481 44.448 79.573 46.728 ;
     RECT  79.379 16.416 79.621 17.304 ;
     RECT  78.653 18.72 79.621 19.896 ;
     RECT  79.405 21.168 79.621 39.768 ;
     RECT  78.545 55.248 79.621 55.56 ;
     RECT  79.541 49.056 79.625 49.944 ;
     RECT  79.571 86.976 79.625 88.968 ;
     RECT  78.437 10.944 79.657 11.016 ;
     RECT  79.553 14.208 79.657 14.328 ;
     RECT  79.379 15.312 79.657 15.432 ;
     RECT  79.621 16.416 79.733 19.896 ;
     RECT  79.621 21.072 79.733 39.768 ;
     RECT  78.761 58.464 79.793 74.04 ;
     RECT  79.621 55.248 79.805 55.8 ;
     RECT  79.405 52.848 79.841 53.592 ;
     RECT  79.657 10.8 79.913 11.016 ;
     RECT  78.761 56.928 79.945 57.432 ;
     RECT  79.793 58.464 79.945 74.136 ;
     RECT  78.725 78.72 79.945 79.848 ;
     RECT  79.625 87.312 79.945 88.968 ;
     RECT  79.945 78.72 80.017 80.328 ;
     RECT  79.235 81.888 80.017 82.824 ;
     RECT  79.625 49.392 80.057 49.944 ;
     RECT  78.941 75.36 80.089 75.816 ;
     RECT  79.733 32.592 80.093 39.768 ;
     RECT  79.657 14.208 80.129 15.432 ;
     RECT  79.945 56.928 80.156 74.136 ;
     RECT  79.733 21.072 80.165 31.32 ;
     RECT  79.049 8.16 80.188 9.72 ;
     RECT  79.805 55.248 80.197 55.272 ;
     RECT  80.089 75.36 80.201 76.248 ;
     RECT  79.733 16.416 80.237 19.656 ;
     RECT  80.156 56.448 80.243 74.136 ;
     RECT  80.017 78.72 80.269 82.824 ;
     RECT  80.243 57.792 80.273 74.136 ;
     RECT  80.197 52.656 80.293 52.68 ;
     RECT  80.188 8.16 80.309 8.184 ;
     RECT  79.585 41.568 80.309 41.592 ;
     RECT  80.293 51.792 80.339 52.68 ;
     RECT  78.977 5.664 80.348 6.36 ;
     RECT  80.293 50.256 80.38 50.28 ;
     RECT  80.273 72 80.381 74.136 ;
     RECT  80.348 5.664 80.389 6.84 ;
     RECT  79.573 43.776 80.389 46.728 ;
     RECT  80.129 14.208 80.417 14.952 ;
     RECT  80.165 21.072 80.417 25.08 ;
     RECT  80.389 5.664 80.435 7.992 ;
     RECT  80.417 21.072 80.453 21.144 ;
     RECT  80.165 26.64 80.453 31.32 ;
     RECT  80.389 43.104 80.476 46.728 ;
     RECT  80.435 6.048 80.525 6.072 ;
     RECT  80.237 16.416 80.525 19.608 ;
     RECT  80.197 54.576 80.525 55.272 ;
     RECT  80.485 13.056 80.557 13.08 ;
     RECT  79.405 84.288 80.557 85.368 ;
     RECT  80.476 43.392 80.593 46.728 ;
     RECT  80.417 22.128 80.597 25.08 ;
     RECT  79.945 87.312 80.633 89.208 ;
     RECT  80.381 73.728 80.665 74.136 ;
     RECT  80.269 78.096 80.665 82.824 ;
     RECT  80.273 57.792 80.669 70.872 ;
     RECT  80.597 22.128 80.705 22.392 ;
     RECT  80.093 35.904 80.705 39.768 ;
     RECT  80.557 84.096 80.705 85.368 ;
     RECT  80.381 72 80.741 72.696 ;
     RECT  80.597 23.76 80.777 25.08 ;
     RECT  80.777 23.76 80.813 24.504 ;
     RECT  80.449 91.296 80.821 91.32 ;
     RECT  80.705 84.192 80.849 85.368 ;
     RECT  80.521 47.856 80.881 47.88 ;
     RECT  80.669 57.792 80.885 69.48 ;
     RECT  80.201 75.408 80.889 76.248 ;
     RECT  80.665 77.28 80.889 82.824 ;
     RECT  80.633 88.272 80.904 89.208 ;
     RECT  80.705 35.904 80.921 38.136 ;
     RECT  80.813 23.76 80.957 24.456 ;
     RECT  80.921 36 80.957 36.12 ;
     RECT  80.821 91.2 80.957 91.32 ;
     RECT  80.665 73.728 80.963 74.424 ;
     RECT  80.525 54.864 80.965 55.272 ;
     RECT  80.957 36 80.993 36.024 ;
     RECT  80.705 39.312 81.061 39.768 ;
     RECT  80.921 37.2 81.065 38.136 ;
     RECT  80.881 47.856 81.065 48.936 ;
     RECT  80.188 9.216 81.133 9.72 ;
     RECT  79.913 10.8 81.133 10.872 ;
     RECT  80.557 12.72 81.137 13.08 ;
     RECT  80.453 26.736 81.173 31.32 ;
     RECT  81.061 39.312 81.209 40.728 ;
     RECT  80.093 32.592 81.241 34.248 ;
     RECT  80.741 72.384 81.245 72.696 ;
     RECT  80.525 16.56 81.253 19.608 ;
     RECT  80.669 70.512 81.277 70.872 ;
     RECT  80.435 7.2 81.281 7.992 ;
     RECT  80.593 43.392 81.281 46.776 ;
     RECT  80.453 21.12 81.299 21.144 ;
     RECT  80.339 51.792 81.308 51.816 ;
     RECT  81.308 50.976 81.349 51.816 ;
     RECT  80.885 57.792 81.389 60.84 ;
     RECT  80.963 74.4 81.389 74.424 ;
     RECT  80.889 75.408 81.389 82.824 ;
     RECT  80.965 54.864 81.421 55.848 ;
     RECT  81.133 9.216 81.445 11.4 ;
     RECT  81.389 57.792 81.452 59.88 ;
     RECT  81.137 12.72 81.461 12.984 ;
     RECT  81.421 54.864 81.493 56.664 ;
     RECT  81.452 57.744 81.493 59.88 ;
     RECT  81.349 87.168 81.493 87.192 ;
     RECT  81.241 32.496 81.497 34.248 ;
     RECT  81.253 16.56 81.529 19.944 ;
     RECT  80.849 85.296 81.529 85.368 ;
     RECT  81.493 86.448 81.529 87.192 ;
     RECT  81.445 9.072 81.533 11.4 ;
     RECT  80.957 24.432 81.533 24.456 ;
     RECT  81.173 27.216 81.533 31.32 ;
     RECT  81.061 42.096 81.565 42.12 ;
     RECT  81.533 27.216 81.569 27.336 ;
     RECT  81.065 48.336 81.569 48.936 ;
     RECT  80.957 91.296 81.569 91.32 ;
     RECT  81.065 37.344 81.605 38.136 ;
     RECT  81.493 54.864 81.605 59.88 ;
     RECT  81.277 70.512 81.605 71.352 ;
     RECT  81.569 48.912 81.637 48.936 ;
     RECT  81.533 28.416 81.677 31.32 ;
     RECT  81.281 43.392 81.713 45 ;
     RECT  81.529 16.176 81.74 19.944 ;
     RECT  81.677 28.416 81.749 28.824 ;
     RECT  81.677 29.904 81.749 31.32 ;
     RECT  81.389 75.408 81.779 80.184 ;
     RECT  81.209 39.648 81.785 40.728 ;
     RECT  81.779 75.408 81.785 77.544 ;
     RECT  81.74 15.456 81.821 19.944 ;
     RECT  81.785 39.744 81.821 40.728 ;
     RECT  81.605 70.512 81.821 70.632 ;
     RECT  81.785 75.792 81.857 77.544 ;
     RECT  81.605 59.136 81.923 59.88 ;
     RECT  81.605 38.112 81.929 38.136 ;
     RECT  81.605 54.864 81.965 58.104 ;
     RECT  80.885 61.872 81.997 69.48 ;
     RECT  81.821 15.456 82.001 16.2 ;
     RECT  81.821 40.704 82.033 40.728 ;
     RECT  81.497 32.496 82.037 34.2 ;
     RECT  81.923 59.136 82.037 59.16 ;
     RECT  81.529 85.296 82.037 87.192 ;
     RECT  81.965 55.872 82.073 58.104 ;
     RECT  81.349 50.976 82.105 52.008 ;
     RECT  81.533 9.552 82.109 11.4 ;
     RECT  81.461 12.96 82.109 12.984 ;
     RECT  81.821 17.472 82.109 19.944 ;
     RECT  81.713 43.392 82.109 43.896 ;
     RECT  81.965 54.864 82.109 54.888 ;
     RECT  80.904 88.272 82.109 89.736 ;
     RECT  81.569 27.216 82.145 27.24 ;
     RECT  81.997 61.872 82.181 70.296 ;
     RECT  81.779 79.152 82.181 80.184 ;
     RECT  80.705 22.128 82.213 22.152 ;
     RECT  82.037 32.496 82.253 33.288 ;
     RECT  81.637 48.912 82.253 49.464 ;
     RECT  82.181 61.872 82.253 70.2 ;
     RECT  82.213 21.504 82.289 22.152 ;
     RECT  81.389 81.36 82.289 82.824 ;
     RECT  82.033 40.704 82.321 40.968 ;
     RECT  81.565 42.096 82.321 42.408 ;
     RECT  82.109 9.552 82.361 10.2 ;
     RECT  82.105 50.736 82.361 52.008 ;
     RECT  81.637 53.568 82.393 53.592 ;
     RECT  82.249 11.952 82.403 11.976 ;
     RECT  80.417 14.208 82.433 14.232 ;
     RECT  82.109 17.472 82.433 18.936 ;
     RECT  82.037 85.296 82.433 85.32 ;
     RECT  82.181 79.536 82.501 80.184 ;
     RECT  82.289 81.36 82.501 81.912 ;
     RECT  82.361 51.12 82.609 52.008 ;
     RECT  82.393 53.04 82.609 53.592 ;
     RECT  82.037 87.168 82.609 87.192 ;
     RECT  82.109 88.272 82.609 88.92 ;
     RECT  82.321 40.704 82.825 42.408 ;
     RECT  82.109 43.392 82.825 43.416 ;
     RECT  82.253 61.872 82.861 70.056 ;
     RECT  81.713 44.976 82.897 45 ;
     RECT  81.857 77.52 83.149 77.544 ;
     RECT  82.825 48.672 83.221 48.696 ;
     RECT  83.221 47.904 83.249 48.696 ;
     RECT  82.249 37.008 83.269 37.032 ;
     RECT  81.857 75.792 83.269 76.344 ;
     RECT  83.149 77.52 83.269 78.12 ;
     RECT  81.281 7.968 83.408 7.992 ;
     RECT  82.361 10.176 83.408 10.2 ;
     RECT  82.357 13.056 83.408 13.08 ;
     RECT  82.069 15.36 83.408 15.384 ;
     RECT  82.433 18.24 83.408 18.936 ;
     RECT  82.289 21.504 83.408 21.528 ;
     RECT  81.749 28.416 83.408 28.44 ;
     RECT  81.749 30.72 83.408 31.32 ;
     RECT  82.253 32.496 83.408 32.52 ;
     RECT  83.269 35.28 83.408 37.032 ;
     RECT  82.825 40.704 83.408 43.416 ;
     RECT  82.897 44.928 83.408 45 ;
     RECT  81.281 46.752 83.408 46.776 ;
     RECT  83.249 47.904 83.408 48.744 ;
     RECT  82.609 51.12 83.408 53.592 ;
     RECT  82.073 55.872 83.408 57.816 ;
     RECT  82.861 61.392 83.408 70.056 ;
     RECT  81.601 72.912 83.408 72.936 ;
     RECT  82.969 74.688 83.408 74.712 ;
     RECT  83.269 75.792 83.408 78.12 ;
     RECT  82.501 79.536 83.408 81.912 ;
     RECT  80.849 84.192 83.408 84.216 ;
     RECT  83.125 85.584 83.408 85.608 ;
     RECT  82.609 87.168 83.408 88.92 ;
     RECT  83.408 2.148 83.512 92.892 ;
     RECT  83.512 2.418 83.704 92.622 ;
     RECT  83.704 63.792 83.765 70.344 ;
     RECT  83.704 58.32 84.841 58.44 ;
     RECT  83.704 22.992 84.877 23.016 ;
     RECT  83.765 64.464 84.877 70.344 ;
     RECT  84.877 22.992 84.913 23.112 ;
     RECT  83.704 24.24 84.913 25.224 ;
     RECT  84.877 61.872 84.913 62.088 ;
     RECT  84.913 22.992 84.949 25.224 ;
     RECT  85.021 63.408 85.165 63.432 ;
     RECT  84.877 64.464 85.165 70.44 ;
     RECT  84.949 22.992 85.345 25.704 ;
     RECT  83.704 35.28 85.381 37.512 ;
     RECT  84.913 61.584 85.453 62.088 ;
     RECT  85.453 61.392 85.489 62.184 ;
     RECT  85.165 63.408 85.489 70.44 ;
     RECT  85.381 35.28 86.101 38.088 ;
     RECT  85.489 61.392 86.245 70.44 ;
     RECT  86.245 61.392 86.316 61.416 ;
     RECT  86.245 61.416 86.357 61.488 ;
     RECT  86.245 61.488 86.316 61.512 ;
     RECT  86.245 61.512 86.357 61.584 ;
     RECT  86.245 61.584 86.316 61.608 ;
     RECT  86.245 61.608 86.357 61.68 ;
     RECT  86.245 61.68 86.316 61.704 ;
     RECT  86.245 61.704 86.357 61.776 ;
     RECT  86.245 61.776 86.316 61.8 ;
     RECT  86.245 61.8 86.357 61.872 ;
     RECT  86.245 61.872 86.316 61.896 ;
     RECT  86.245 61.896 86.357 61.968 ;
     RECT  86.245 61.968 86.316 61.992 ;
     RECT  86.245 61.992 86.357 62.064 ;
     RECT  86.245 62.064 86.316 62.088 ;
     RECT  86.245 62.088 86.357 62.16 ;
     RECT  86.245 62.16 86.316 62.184 ;
     RECT  86.245 62.184 86.357 62.256 ;
     RECT  86.245 62.256 86.316 62.28 ;
     RECT  86.245 62.28 86.357 62.352 ;
     RECT  86.245 62.352 86.316 62.376 ;
     RECT  86.245 62.376 86.357 62.448 ;
     RECT  86.245 62.448 86.316 62.472 ;
     RECT  86.245 62.472 86.357 62.544 ;
     RECT  86.245 62.544 86.316 62.568 ;
     RECT  86.245 62.568 86.357 62.64 ;
     RECT  86.245 62.64 86.316 62.664 ;
     RECT  86.245 62.664 86.357 62.736 ;
     RECT  86.245 62.736 86.316 62.76 ;
     RECT  86.245 62.76 86.357 62.832 ;
     RECT  86.245 62.832 86.316 62.856 ;
     RECT  86.245 62.856 86.357 62.928 ;
     RECT  86.245 62.928 86.316 62.952 ;
     RECT  86.245 62.952 86.357 63.024 ;
     RECT  86.245 63.024 86.316 63.048 ;
     RECT  86.245 63.048 86.357 63.12 ;
     RECT  86.245 63.12 86.316 63.144 ;
     RECT  86.245 63.144 86.357 63.216 ;
     RECT  86.245 63.216 86.316 63.24 ;
     RECT  86.245 63.24 86.357 63.312 ;
     RECT  86.245 63.312 86.316 63.336 ;
     RECT  86.245 63.336 86.357 63.408 ;
     RECT  86.245 63.408 86.316 63.432 ;
     RECT  86.245 63.432 86.357 63.504 ;
     RECT  86.245 63.504 86.316 63.528 ;
     RECT  86.245 63.528 86.357 63.6 ;
     RECT  86.245 63.6 86.316 63.624 ;
     RECT  86.245 63.624 86.357 63.696 ;
     RECT  86.245 63.696 86.316 63.72 ;
     RECT  86.245 63.72 86.357 63.792 ;
     RECT  86.245 63.792 86.316 63.816 ;
     RECT  86.245 63.816 86.357 63.888 ;
     RECT  86.245 63.888 86.316 63.912 ;
     RECT  86.245 63.912 86.357 63.984 ;
     RECT  86.245 63.984 86.316 64.008 ;
     RECT  86.245 64.008 86.357 64.08 ;
     RECT  86.245 64.08 86.316 64.104 ;
     RECT  86.245 64.104 86.357 64.176 ;
     RECT  86.245 64.176 86.316 64.2 ;
     RECT  86.245 64.2 86.357 64.272 ;
     RECT  86.245 64.272 86.316 64.296 ;
     RECT  86.245 64.296 86.357 64.368 ;
     RECT  86.245 64.368 86.316 64.392 ;
     RECT  86.245 64.392 86.357 64.464 ;
     RECT  86.245 64.464 86.316 64.488 ;
     RECT  86.245 64.488 86.357 64.56 ;
     RECT  86.245 64.56 86.316 64.584 ;
     RECT  86.245 64.584 86.357 64.656 ;
     RECT  86.245 64.656 86.316 64.68 ;
     RECT  86.245 64.68 86.357 64.752 ;
     RECT  86.245 64.752 86.316 64.776 ;
     RECT  86.245 64.776 86.357 64.848 ;
     RECT  86.245 64.848 86.316 64.872 ;
     RECT  86.245 64.872 86.357 64.944 ;
     RECT  86.245 64.944 86.316 64.968 ;
     RECT  86.245 64.968 86.357 65.04 ;
     RECT  86.245 65.04 86.316 65.064 ;
     RECT  86.245 65.064 86.357 65.136 ;
     RECT  86.245 65.136 86.316 65.16 ;
     RECT  86.245 65.16 86.357 65.232 ;
     RECT  86.245 65.232 86.316 65.256 ;
     RECT  86.245 65.256 86.357 65.328 ;
     RECT  86.245 65.328 86.316 65.352 ;
     RECT  86.245 65.352 86.357 65.424 ;
     RECT  86.245 65.424 86.316 65.448 ;
     RECT  86.245 65.448 86.357 65.52 ;
     RECT  86.245 65.52 86.316 65.544 ;
     RECT  86.245 65.544 86.357 65.616 ;
     RECT  86.245 65.616 86.316 65.64 ;
     RECT  86.245 65.64 86.357 65.712 ;
     RECT  86.245 65.712 86.316 65.736 ;
     RECT  86.245 65.736 86.357 65.808 ;
     RECT  86.245 65.808 86.316 65.832 ;
     RECT  86.245 65.832 86.357 65.904 ;
     RECT  86.245 65.904 86.316 65.928 ;
     RECT  86.245 65.928 86.357 66 ;
     RECT  86.245 66 86.316 66.024 ;
     RECT  86.245 66.024 86.357 66.096 ;
     RECT  86.245 66.096 86.316 66.12 ;
     RECT  86.245 66.12 86.357 66.192 ;
     RECT  86.245 66.192 86.316 66.216 ;
     RECT  86.245 66.216 86.357 66.288 ;
     RECT  86.245 66.288 86.316 66.312 ;
     RECT  86.245 66.312 86.357 66.384 ;
     RECT  86.245 66.384 86.316 66.408 ;
     RECT  86.245 66.408 86.357 66.48 ;
     RECT  86.245 66.48 86.316 66.504 ;
     RECT  86.245 66.504 86.357 66.576 ;
     RECT  86.245 66.576 86.316 66.6 ;
     RECT  86.245 66.6 86.357 66.672 ;
     RECT  86.245 66.672 86.316 66.696 ;
     RECT  86.245 66.696 86.357 66.768 ;
     RECT  86.245 66.768 86.316 66.792 ;
     RECT  86.245 66.792 86.357 66.864 ;
     RECT  86.245 66.864 86.316 66.888 ;
     RECT  86.245 66.888 86.357 66.96 ;
     RECT  86.245 66.96 86.316 66.984 ;
     RECT  86.245 66.984 86.357 67.056 ;
     RECT  86.245 67.056 86.316 67.08 ;
     RECT  86.245 67.08 86.357 67.152 ;
     RECT  86.245 67.152 86.316 67.176 ;
     RECT  86.245 67.176 86.357 67.248 ;
     RECT  86.245 67.248 86.316 67.272 ;
     RECT  86.245 67.272 86.357 67.344 ;
     RECT  86.245 67.344 86.316 67.368 ;
     RECT  86.245 67.368 86.357 67.44 ;
     RECT  86.245 67.44 86.316 67.464 ;
     RECT  86.245 67.464 86.357 67.536 ;
     RECT  86.245 67.536 86.316 67.56 ;
     RECT  86.245 67.56 86.357 67.632 ;
     RECT  86.245 67.632 86.316 67.656 ;
     RECT  86.245 67.656 86.357 67.728 ;
     RECT  86.245 67.728 86.316 67.752 ;
     RECT  86.245 67.752 86.357 67.824 ;
     RECT  86.245 67.824 86.316 67.848 ;
     RECT  86.245 67.848 86.357 67.92 ;
     RECT  86.245 67.92 86.316 67.944 ;
     RECT  86.245 67.944 86.357 68.016 ;
     RECT  86.245 68.016 86.316 68.04 ;
     RECT  86.245 68.04 86.357 68.112 ;
     RECT  86.245 68.112 86.316 68.136 ;
     RECT  86.245 68.136 86.357 68.208 ;
     RECT  86.245 68.208 86.316 68.232 ;
     RECT  86.245 68.232 86.357 68.304 ;
     RECT  86.245 68.304 86.316 68.328 ;
     RECT  86.245 68.328 86.357 68.4 ;
     RECT  86.245 68.4 86.316 68.424 ;
     RECT  86.245 68.424 86.357 68.496 ;
     RECT  86.245 68.496 86.316 68.52 ;
     RECT  86.245 68.52 86.357 68.592 ;
     RECT  86.245 68.592 86.316 68.616 ;
     RECT  86.245 68.616 86.357 68.688 ;
     RECT  86.245 68.688 86.316 68.712 ;
     RECT  86.245 68.712 86.357 68.784 ;
     RECT  86.245 68.784 86.316 68.808 ;
     RECT  86.245 68.808 86.357 68.88 ;
     RECT  86.245 68.88 86.316 68.904 ;
     RECT  86.245 68.904 86.357 68.976 ;
     RECT  86.245 68.976 86.316 69 ;
     RECT  86.245 69 86.357 69.072 ;
     RECT  86.245 69.072 86.316 69.096 ;
     RECT  86.245 69.096 86.357 69.168 ;
     RECT  86.245 69.168 86.316 69.192 ;
     RECT  86.245 69.192 86.357 69.264 ;
     RECT  86.245 69.264 86.316 69.288 ;
     RECT  86.245 69.288 86.357 69.36 ;
     RECT  86.245 69.36 86.316 69.384 ;
     RECT  86.245 69.384 86.357 69.456 ;
     RECT  86.245 69.456 86.316 69.48 ;
     RECT  86.245 69.48 86.357 69.552 ;
     RECT  86.245 69.552 86.316 69.576 ;
     RECT  86.245 69.576 86.357 69.648 ;
     RECT  86.245 69.648 86.316 69.672 ;
     RECT  86.245 69.672 86.357 69.744 ;
     RECT  86.245 69.744 86.316 69.768 ;
     RECT  86.245 69.768 86.357 69.84 ;
     RECT  86.245 69.84 86.316 69.864 ;
     RECT  86.245 69.864 86.357 69.936 ;
     RECT  86.245 69.936 86.316 69.96 ;
     RECT  86.245 69.96 86.357 70.032 ;
     RECT  86.245 70.032 86.316 70.056 ;
     RECT  86.245 70.056 86.357 70.128 ;
     RECT  86.245 70.128 86.316 70.152 ;
     RECT  86.245 70.152 86.357 70.224 ;
     RECT  86.245 70.224 86.316 70.248 ;
     RECT  86.245 70.248 86.357 70.32 ;
     RECT  86.245 70.32 86.316 70.344 ;
     RECT  86.245 70.344 86.357 70.416 ;
     RECT  86.245 70.416 86.316 70.44 ;
     RECT  86.245 70.44 86.357 70.512 ;
     RECT  86.245 70.512 86.316 70.536 ;
     RECT  86.245 70.536 86.357 70.632 ;
     RECT  85.345 22.992 86.316 23.016 ;
     RECT  85.345 23.016 86.364 23.088 ;
     RECT  85.345 23.088 86.316 23.112 ;
     RECT  85.345 23.112 86.364 23.184 ;
     RECT  85.345 23.184 86.316 23.208 ;
     RECT  85.345 23.208 86.364 23.28 ;
     RECT  85.345 23.28 86.316 23.304 ;
     RECT  85.345 23.304 86.364 23.376 ;
     RECT  85.345 23.376 86.316 23.4 ;
     RECT  85.345 23.4 86.364 23.472 ;
     RECT  85.345 23.472 86.316 23.496 ;
     RECT  85.345 23.496 86.364 23.568 ;
     RECT  85.345 23.568 86.316 23.592 ;
     RECT  85.345 23.592 86.364 23.664 ;
     RECT  85.345 23.664 86.316 23.688 ;
     RECT  85.345 23.688 86.364 23.76 ;
     RECT  85.345 23.76 86.316 23.784 ;
     RECT  85.345 23.784 86.364 23.856 ;
     RECT  85.345 23.856 86.316 23.88 ;
     RECT  85.345 23.88 86.364 23.952 ;
     RECT  85.345 23.952 86.316 23.976 ;
     RECT  85.345 23.976 86.364 24.048 ;
     RECT  85.345 24.048 86.316 24.072 ;
     RECT  85.345 24.072 86.364 24.144 ;
     RECT  85.345 24.144 86.316 24.168 ;
     RECT  85.345 24.168 86.364 24.24 ;
     RECT  85.345 24.24 86.316 24.264 ;
     RECT  85.345 24.264 86.364 24.336 ;
     RECT  85.345 24.336 86.316 24.36 ;
     RECT  85.345 24.36 86.364 24.432 ;
     RECT  85.345 24.432 86.316 24.456 ;
     RECT  85.345 24.456 86.364 24.528 ;
     RECT  85.345 24.528 86.316 24.552 ;
     RECT  85.345 24.552 86.364 24.624 ;
     RECT  85.345 24.624 86.316 24.648 ;
     RECT  85.345 24.648 86.364 24.72 ;
     RECT  85.345 24.72 86.316 24.744 ;
     RECT  85.345 24.744 86.364 24.816 ;
     RECT  85.345 24.816 86.316 24.84 ;
     RECT  85.345 24.84 86.364 24.912 ;
     RECT  85.345 24.912 86.316 24.936 ;
     RECT  85.345 24.936 86.364 25.008 ;
     RECT  85.345 25.008 86.316 25.032 ;
     RECT  85.345 25.032 86.364 25.104 ;
     RECT  85.345 25.104 86.316 25.128 ;
     RECT  85.345 25.128 86.364 25.2 ;
     RECT  85.345 25.2 86.316 25.224 ;
     RECT  85.345 25.224 86.364 25.296 ;
     RECT  85.345 25.296 86.316 25.32 ;
     RECT  85.345 25.32 86.364 25.392 ;
     RECT  85.345 25.392 86.316 25.416 ;
     RECT  85.345 25.416 86.364 25.488 ;
     RECT  85.345 25.488 86.316 25.512 ;
     RECT  85.345 25.512 86.364 25.584 ;
     RECT  85.345 25.584 86.316 25.608 ;
     RECT  85.345 25.608 86.364 25.68 ;
     RECT  85.345 25.68 86.316 25.704 ;
     RECT  85.345 25.704 86.364 25.776 ;
     RECT  85.345 25.776 86.316 25.8 ;
     RECT  85.345 25.8 86.364 25.872 ;
     RECT  85.345 25.872 86.316 25.896 ;
     RECT  85.345 25.896 86.364 25.968 ;
     RECT  85.345 25.968 86.316 25.992 ;
     RECT  86.101 35.28 86.316 35.304 ;
     RECT  86.101 35.304 86.364 35.376 ;
     RECT  86.101 35.376 86.316 35.4 ;
     RECT  86.101 35.4 86.364 35.472 ;
     RECT  86.101 35.472 86.316 35.496 ;
     RECT  86.101 35.496 86.364 35.568 ;
     RECT  86.101 35.568 86.316 35.592 ;
     RECT  86.101 35.592 86.364 35.664 ;
     RECT  86.101 35.664 86.316 35.688 ;
     RECT  86.101 35.688 86.364 35.76 ;
     RECT  86.101 35.76 86.316 35.784 ;
     RECT  86.101 35.784 86.364 35.856 ;
     RECT  86.101 35.856 86.316 35.88 ;
     RECT  86.101 35.88 86.364 35.952 ;
     RECT  86.101 35.952 86.316 35.976 ;
     RECT  86.101 35.976 86.364 36.048 ;
     RECT  86.101 36.048 86.316 36.072 ;
     RECT  86.101 36.072 86.364 36.144 ;
     RECT  86.101 36.144 86.316 36.168 ;
     RECT  86.101 36.168 86.364 36.24 ;
     RECT  86.101 36.24 86.316 36.264 ;
     RECT  86.101 36.264 86.364 36.336 ;
     RECT  86.101 36.336 86.316 36.36 ;
     RECT  86.101 36.36 86.364 36.432 ;
     RECT  86.101 36.432 86.316 36.456 ;
     RECT  86.101 36.456 86.364 36.528 ;
     RECT  86.101 36.528 86.316 36.552 ;
     RECT  86.101 36.552 86.364 36.624 ;
     RECT  86.101 36.624 86.316 36.648 ;
     RECT  86.101 36.648 86.364 36.72 ;
     RECT  86.101 36.72 86.316 36.744 ;
     RECT  86.101 36.744 86.364 36.816 ;
     RECT  86.101 36.816 86.316 36.84 ;
     RECT  86.101 36.84 86.364 36.912 ;
     RECT  86.101 36.912 86.316 36.936 ;
     RECT  86.101 36.936 86.364 37.008 ;
     RECT  86.101 37.008 86.316 37.032 ;
     RECT  86.101 37.032 86.364 37.104 ;
     RECT  86.101 37.104 86.316 37.128 ;
     RECT  86.101 37.128 86.364 37.2 ;
     RECT  86.101 37.2 86.316 37.224 ;
     RECT  86.101 37.224 86.364 37.296 ;
     RECT  86.101 37.296 86.316 37.32 ;
     RECT  86.101 37.32 86.364 37.392 ;
     RECT  86.101 37.392 86.316 37.416 ;
     RECT  86.101 37.416 86.364 37.488 ;
     RECT  86.101 37.488 86.316 37.512 ;
     RECT  86.101 37.512 86.364 37.584 ;
     RECT  86.101 37.584 86.316 37.608 ;
     RECT  86.101 37.608 86.364 37.68 ;
     RECT  86.101 37.68 86.316 37.704 ;
     RECT  86.101 37.704 86.364 37.776 ;
     RECT  86.101 37.776 86.316 37.8 ;
     RECT  86.101 37.8 86.364 37.872 ;
     RECT  86.101 37.872 86.316 37.896 ;
     RECT  86.101 37.896 86.364 37.968 ;
     RECT  86.101 37.968 86.316 37.992 ;
     RECT  86.101 37.992 86.364 38.064 ;
     RECT  86.101 38.064 86.316 38.088 ;
     RECT  86.101 38.088 86.364 38.16 ;
     RECT  86.101 38.16 86.316 38.184 ;
     RECT  86.101 38.184 86.364 38.256 ;
     RECT  86.101 38.256 86.316 38.28 ;
     RECT  84.841 58.32 86.316 58.344 ;
     RECT  84.841 58.344 86.364 58.416 ;
     RECT  84.841 58.416 86.316 58.44 ;
     RECT  84.841 58.44 86.364 58.512 ;
     RECT  84.841 58.512 86.316 58.536 ;
     RECT  84.841 58.536 86.364 58.608 ;
     RECT  84.841 58.608 86.316 58.632 ;
     RECT  84.841 58.632 86.364 58.704 ;
     RECT  84.841 58.704 86.316 58.728 ;
     RECT  84.841 58.728 86.364 58.8 ;
     RECT  84.841 58.8 86.316 58.824 ;
     RECT  84.841 58.824 86.364 58.896 ;
     RECT  84.841 58.896 86.316 58.92 ;
     RECT  84.841 58.92 86.364 58.992 ;
     RECT  84.841 58.992 86.316 59.016 ;
     RECT  84.841 59.016 86.364 59.088 ;
     RECT  84.841 59.088 86.316 59.112 ;
     RECT  84.841 59.112 86.364 59.184 ;
     RECT  84.841 59.184 86.316 59.208 ;
     RECT  84.841 59.208 86.364 59.28 ;
     RECT  84.841 59.28 86.316 59.304 ;
     RECT  84.841 59.304 86.364 59.376 ;
     RECT  84.841 59.376 86.316 59.4 ;
     RECT  86.357 61.416 86.364 61.488 ;
     RECT  86.357 61.512 86.364 61.584 ;
     RECT  86.357 61.608 86.364 61.68 ;
     RECT  86.357 61.704 86.364 61.776 ;
     RECT  86.357 61.8 86.364 61.872 ;
     RECT  86.357 61.896 86.364 61.968 ;
     RECT  86.357 61.992 86.364 62.064 ;
     RECT  86.357 62.088 86.364 62.16 ;
     RECT  86.357 62.184 86.364 62.256 ;
     RECT  86.357 62.28 86.364 62.352 ;
     RECT  86.357 62.376 86.364 62.448 ;
     RECT  86.357 62.472 86.364 62.544 ;
     RECT  86.357 62.568 86.364 62.64 ;
     RECT  86.357 62.664 86.364 62.736 ;
     RECT  86.357 62.76 86.364 62.832 ;
     RECT  86.357 62.856 86.364 62.928 ;
     RECT  86.357 62.952 86.364 63.024 ;
     RECT  86.357 63.048 86.364 63.12 ;
     RECT  86.357 63.144 86.364 63.216 ;
     RECT  86.357 63.24 86.364 63.312 ;
     RECT  86.357 63.336 86.364 63.408 ;
     RECT  86.357 63.432 86.364 63.504 ;
     RECT  86.357 63.528 86.364 63.6 ;
     RECT  86.357 63.624 86.364 63.696 ;
     RECT  86.357 63.72 86.364 63.792 ;
     RECT  86.357 63.816 86.364 63.888 ;
     RECT  86.357 63.912 86.364 63.984 ;
     RECT  86.357 64.008 86.364 64.08 ;
     RECT  86.357 64.104 86.364 64.176 ;
     RECT  86.357 64.2 86.364 64.272 ;
     RECT  86.357 64.296 86.364 64.368 ;
     RECT  86.357 64.392 86.364 64.464 ;
     RECT  86.357 64.488 86.364 64.56 ;
     RECT  86.357 64.584 86.364 64.656 ;
     RECT  86.357 64.68 86.364 64.752 ;
     RECT  86.357 64.776 86.364 64.848 ;
     RECT  86.357 64.872 86.364 64.944 ;
     RECT  86.357 64.968 86.364 65.04 ;
     RECT  86.357 65.064 86.364 65.136 ;
     RECT  86.357 65.16 86.364 65.232 ;
     RECT  86.357 65.256 86.364 65.328 ;
     RECT  86.357 65.352 86.364 65.424 ;
     RECT  86.357 65.448 86.364 65.52 ;
     RECT  86.357 65.544 86.364 65.616 ;
     RECT  86.357 65.64 86.364 65.712 ;
     RECT  86.357 65.736 86.364 65.808 ;
     RECT  86.357 65.832 86.364 65.904 ;
     RECT  86.357 65.928 86.364 66 ;
     RECT  86.357 66.024 86.364 66.096 ;
     RECT  86.357 66.12 86.364 66.192 ;
     RECT  86.357 66.216 86.364 66.288 ;
     RECT  86.357 66.312 86.364 66.384 ;
     RECT  86.357 66.408 86.364 66.48 ;
     RECT  86.357 66.504 86.364 66.576 ;
     RECT  86.357 66.6 86.364 66.672 ;
     RECT  86.357 66.696 86.364 66.768 ;
     RECT  86.357 66.792 86.364 66.864 ;
     RECT  86.357 66.888 86.364 66.96 ;
     RECT  86.357 66.984 86.364 67.056 ;
     RECT  86.357 67.08 86.364 67.152 ;
     RECT  86.357 67.176 86.364 67.248 ;
     RECT  86.357 67.272 86.364 67.344 ;
     RECT  86.357 67.368 86.364 67.44 ;
     RECT  86.357 67.464 86.364 67.536 ;
     RECT  86.357 67.56 86.364 67.632 ;
     RECT  86.357 67.656 86.364 67.728 ;
     RECT  86.357 67.752 86.364 67.824 ;
     RECT  86.357 67.848 86.364 67.92 ;
     RECT  86.357 67.944 86.364 68.016 ;
     RECT  86.357 68.04 86.364 68.112 ;
     RECT  86.357 68.136 86.364 68.208 ;
     RECT  86.357 68.232 86.364 68.304 ;
     RECT  86.357 68.328 86.364 68.4 ;
     RECT  86.357 68.424 86.364 68.496 ;
     RECT  86.357 68.52 86.364 68.592 ;
     RECT  86.357 68.616 86.364 68.688 ;
     RECT  86.357 68.712 86.364 68.784 ;
     RECT  86.357 68.808 86.364 68.88 ;
     RECT  86.357 68.904 86.364 68.976 ;
     RECT  86.357 69 86.364 69.072 ;
     RECT  86.357 69.096 86.364 69.168 ;
     RECT  86.357 69.192 86.364 69.264 ;
     RECT  86.357 69.288 86.364 69.36 ;
     RECT  86.357 69.384 86.364 69.456 ;
     RECT  86.357 69.48 86.364 69.552 ;
     RECT  86.357 69.576 86.364 69.648 ;
     RECT  86.357 69.672 86.364 69.744 ;
     RECT  86.357 69.768 86.364 69.84 ;
     RECT  86.357 69.864 86.364 69.936 ;
     RECT  86.357 69.96 86.364 70.032 ;
     RECT  86.357 70.056 86.364 70.128 ;
     RECT  86.357 70.152 86.364 70.224 ;
     RECT  86.357 70.248 86.364 70.32 ;
     RECT  86.357 70.344 86.364 70.416 ;
     RECT  86.357 70.44 86.364 70.512 ;
    LAYER M5 ;
     RECT  2.4 2.137 2.52 2.151 ;
     RECT  7.8 2.137 7.92 2.151 ;
     RECT  13.2 2.137 13.32 2.151 ;
     RECT  18.6 2.137 18.72 2.151 ;
     RECT  24 2.137 24.12 2.151 ;
     RECT  29.4 2.137 29.52 2.151 ;
     RECT  34.8 2.137 34.92 2.151 ;
     RECT  40.2 2.137 40.32 2.151 ;
     RECT  45.6 2.137 45.72 2.151 ;
     RECT  51 2.137 51.12 2.151 ;
     RECT  56.4 2.137 56.52 2.151 ;
     RECT  61.8 2.137 61.92 2.151 ;
     RECT  67.2 2.137 67.32 2.151 ;
     RECT  72.6 2.137 72.72 2.151 ;
     RECT  78 2.137 78.12 2.151 ;
     RECT  83.4 2.137 83.52 2.151 ;
     RECT  72.6 2.151 72.912 2.821 ;
     RECT  71.76 2.821 72.912 3.205 ;
     RECT  22.32 3.205 22.344 3.397 ;
     RECT  71.76 3.205 73.128 3.443 ;
     RECT  40.2 2.151 40.512 3.733 ;
     RECT  51 2.151 51.312 3.829 ;
     RECT  40.2 3.733 41.304 3.875 ;
     RECT  50.544 3.829 51.312 3.925 ;
     RECT  22.32 3.397 22.824 4.211 ;
     RECT  7.8 2.151 8.112 4.261 ;
     RECT  29.4 2.151 29.712 4.261 ;
     RECT  50.448 3.925 51.312 4.261 ;
     RECT  65.52 3.397 65.544 4.261 ;
     RECT  14.496 3.397 15.336 4.355 ;
     RECT  65.52 4.261 65.64 4.595 ;
     RECT  17.52 2.821 17.544 4.643 ;
     RECT  27.888 3.925 27.912 4.691 ;
     RECT  72.048 3.443 73.128 4.691 ;
     RECT  69.696 4.261 69.72 5.029 ;
     RECT  72.48 4.691 73.128 5.077 ;
     RECT  40.2 3.875 40.512 5.125 ;
     RECT  29.4 4.261 29.832 5.171 ;
     RECT  50.448 4.261 52.296 5.171 ;
     RECT  68.496 3.205 68.52 5.219 ;
     RECT  67.2 2.151 67.512 5.269 ;
     RECT  40.2 5.125 41.112 5.317 ;
     RECT  65.616 4.595 65.64 5.605 ;
     RECT  40.2 5.317 41.4 5.651 ;
     RECT  65.616 5.605 65.88 5.651 ;
     RECT  40.2 5.651 41.112 5.891 ;
     RECT  74.976 4.885 75 6.035 ;
     RECT  24 2.151 24.312 6.229 ;
     RECT  22.32 4.211 22.344 6.275 ;
     RECT  47.424 4.501 47.448 6.275 ;
     RECT  45.6 2.151 45.912 6.277 ;
     RECT  57.936 4.885 57.96 6.323 ;
     RECT  31.92 5.797 31.944 6.515 ;
     RECT  29.4 5.171 29.712 6.517 ;
     RECT  14.784 4.355 15.336 6.563 ;
     RECT  72.48 5.077 73.512 6.661 ;
     RECT  15.312 6.563 15.336 6.757 ;
     RECT  11.28 6.469 11.304 6.805 ;
     RECT  65.856 5.651 65.88 6.805 ;
     RECT  58.704 6.709 58.728 6.851 ;
     RECT  34.8 2.151 35.112 6.853 ;
     RECT  10.56 6.805 11.304 6.947 ;
     RECT  65.328 6.805 65.88 6.947 ;
     RECT  72.48 6.661 74.088 6.997 ;
     RECT  38.112 7.045 38.136 7.093 ;
     RECT  72.432 6.997 74.088 7.187 ;
     RECT  80.4 5.653 80.424 7.189 ;
     RECT  80.4 7.189 80.952 7.235 ;
     RECT  78 2.151 78.312 7.237 ;
     RECT  7.8 4.261 8.664 7.333 ;
     RECT  18.6 2.151 18.912 7.333 ;
     RECT  32.4 7.285 32.424 7.381 ;
     RECT  56.4 2.151 56.712 7.381 ;
     RECT  67.2 5.269 67.608 7.381 ;
     RECT  68.688 6.229 68.712 7.381 ;
     RECT  69.696 5.029 70.248 7.381 ;
     RECT  34.8 6.853 35.352 7.427 ;
     RECT  68.688 7.381 70.248 7.475 ;
     RECT  72.48 7.187 74.088 7.475 ;
     RECT  45.6 6.277 46.008 7.477 ;
     RECT  15.312 6.757 15.432 7.619 ;
     RECT  50.496 5.171 52.296 7.621 ;
     RECT  72.48 7.475 73.512 7.715 ;
     RECT  18.384 7.333 18.912 7.763 ;
     RECT  43.824 6.229 43.848 7.765 ;
     RECT  5.04 2.533 5.064 7.907 ;
     RECT  7.8 7.333 9.096 7.907 ;
     RECT  10.56 6.947 10.584 7.907 ;
     RECT  32.4 7.381 32.472 7.909 ;
     RECT  45.504 7.477 46.008 7.955 ;
     RECT  13.2 2.151 13.512 7.957 ;
     RECT  15.312 7.619 15.336 7.957 ;
     RECT  32.4 7.909 33.048 7.957 ;
     RECT  60.384 5.125 60.408 7.957 ;
     RECT  13.2 7.957 15.336 8.003 ;
     RECT  80.928 7.235 80.952 8.003 ;
     RECT  43.296 7.765 43.848 8.053 ;
     RECT  49.728 7.621 52.296 8.147 ;
     RECT  43.104 8.053 43.848 8.243 ;
     RECT  56.4 7.381 57 8.245 ;
     RECT  60.288 7.957 60.408 8.291 ;
     RECT  61.8 2.151 62.112 8.293 ;
     RECT  40.2 5.891 40.512 8.341 ;
     RECT  37.968 7.093 38.136 8.435 ;
     RECT  49.728 8.147 51.312 8.435 ;
     RECT  56.4 8.245 57.288 8.437 ;
     RECT  65.328 6.947 65.352 8.437 ;
     RECT  24 6.229 24.408 8.485 ;
     RECT  34.8 7.427 35.112 8.485 ;
     RECT  67.104 7.381 67.608 8.533 ;
     RECT  68.688 7.475 69 8.533 ;
     RECT  26.208 7.381 26.232 8.579 ;
     RECT  40.2 8.341 41.064 8.725 ;
     RECT  77.136 7.237 78.312 8.819 ;
     RECT  13.2 8.003 14.904 8.963 ;
     RECT  75.744 7.957 75.768 8.963 ;
     RECT  47.472 6.325 47.496 9.061 ;
     RECT  80.112 8.341 80.136 9.061 ;
     RECT  29.4 6.517 30.216 9.155 ;
     RECT  39.168 8.245 39.192 9.155 ;
     RECT  70.224 7.475 70.248 9.155 ;
     RECT  40.2 8.725 41.352 9.203 ;
     RECT  55.68 8.437 57.288 9.203 ;
     RECT  67.104 8.533 69 9.203 ;
     RECT  63.264 8.485 63.288 9.347 ;
     RECT  60.912 8.293 62.112 9.395 ;
     RECT  65.184 8.437 65.352 9.491 ;
     RECT  50.64 8.435 51.312 9.589 ;
     RECT  7.8 7.907 8.856 9.637 ;
     RECT  24 8.485 24.648 9.637 ;
     RECT  43.296 8.243 43.848 9.637 ;
     RECT  38.112 8.435 38.136 9.731 ;
     RECT  81.456 9.061 81.48 9.731 ;
     RECT  55.68 9.203 56.712 9.779 ;
     RECT  72.6 7.715 73.512 9.779 ;
     RECT  31.392 7.957 33.048 10.067 ;
     RECT  6.72 7.717 6.744 10.165 ;
     RECT  7.8 9.637 9.24 10.165 ;
     RECT  47.472 9.061 48.072 10.165 ;
     RECT  45.6 7.955 46.008 10.307 ;
     RECT  65.184 9.491 65.208 10.307 ;
     RECT  47.328 10.165 48.072 10.355 ;
     RECT  13.2 8.963 14.232 10.453 ;
     RECT  43.296 9.637 43.944 10.595 ;
     RECT  6.72 10.165 9.24 10.741 ;
     RECT  6.48 10.741 9.24 10.883 ;
     RECT  79.344 9.061 80.136 10.883 ;
     RECT  58.608 10.693 58.632 11.125 ;
     RECT  6.48 10.883 6.648 11.171 ;
     RECT  24 9.637 24.936 11.173 ;
     RECT  50.64 9.589 51.432 11.173 ;
     RECT  50.496 11.173 51.432 11.221 ;
     RECT  7.8 10.883 9.24 11.267 ;
     RECT  50.256 11.221 51.432 11.363 ;
     RECT  9.216 11.267 9.24 11.411 ;
     RECT  31.392 10.067 32.328 11.413 ;
     RECT  47.328 10.355 47.352 11.459 ;
     RECT  50.496 11.363 51.432 11.459 ;
     RECT  63.552 10.165 63.576 11.507 ;
     RECT  58.608 11.125 58.968 11.555 ;
     RECT  50.496 11.459 51.312 11.603 ;
     RECT  36.48 10.885 36.504 11.699 ;
     RECT  31.392 11.413 33.048 11.891 ;
     RECT  34.8 8.485 35.448 11.941 ;
     RECT  67.2 9.203 69 11.941 ;
     RECT  72.6 9.779 72.912 11.941 ;
     RECT  24 11.173 25.752 12.035 ;
     RECT  43.824 10.595 43.944 12.035 ;
     RECT  43.92 12.035 43.944 12.083 ;
     RECT  56.4 9.779 56.712 12.181 ;
     RECT  31.392 11.891 32.952 12.227 ;
     RECT  13.2 10.453 14.808 12.325 ;
     RECT  13.2 12.325 14.952 12.467 ;
     RECT  6.624 11.171 6.648 12.469 ;
     RECT  6.624 12.469 6.792 12.515 ;
     RECT  31.392 12.227 31.896 12.517 ;
     RECT  53.52 6.613 53.544 12.517 ;
     RECT  79.344 10.883 79.368 12.517 ;
     RECT  63.264 11.941 63.288 12.563 ;
     RECT  32.928 12.227 32.952 12.755 ;
     RECT  75.264 11.941 75.288 12.755 ;
     RECT  76.368 12.517 76.392 12.755 ;
     RECT  52.704 12.517 53.544 12.995 ;
     RECT  66.672 11.941 69 13.045 ;
     RECT  14.928 12.467 14.952 13.091 ;
     RECT  72.48 11.941 72.912 13.091 ;
     RECT  82.368 11.941 82.392 13.091 ;
     RECT  31.248 12.517 31.896 13.139 ;
     RECT  34.8 11.941 35.928 13.139 ;
     RECT  56.4 12.181 57.48 13.139 ;
     RECT  5.568 13.093 5.592 13.283 ;
     RECT  52.704 12.995 53.304 13.283 ;
     RECT  40.2 9.203 40.728 13.429 ;
     RECT  31.632 13.139 31.896 13.477 ;
     RECT  58.944 11.555 58.968 13.621 ;
     RECT  42.144 12.517 42.168 13.715 ;
     RECT  66.096 13.045 69 13.715 ;
     RECT  31.632 13.477 32.808 13.813 ;
     RECT  79.344 12.517 79.512 14.099 ;
     RECT  15.408 13.621 15.432 14.101 ;
     RECT  48.528 12.469 48.552 14.149 ;
     RECT  29.4 9.155 30.024 14.195 ;
     RECT  6.768 12.515 6.792 14.197 ;
     RECT  7.8 11.267 8.112 14.197 ;
     RECT  24 12.035 24.936 14.197 ;
     RECT  57.984 13.621 58.968 14.291 ;
     RECT  31.632 13.813 33.096 14.387 ;
     RECT  48.528 14.149 48.984 14.387 ;
     RECT  31.632 14.387 32.568 14.485 ;
     RECT  30.72 14.485 32.568 14.627 ;
     RECT  22.224 14.197 22.248 14.675 ;
     RECT  30.72 14.627 31.896 14.675 ;
     RECT  39.36 13.429 40.728 14.675 ;
     RECT  44.112 13.525 44.136 14.675 ;
     RECT  72.6 13.091 72.912 14.677 ;
     RECT  61.8 9.395 62.112 14.773 ;
     RECT  71.28 13.045 71.304 14.773 ;
     RECT  72.432 14.677 72.912 14.773 ;
     RECT  15.408 14.101 15.96 14.819 ;
     RECT  30.816 14.675 31.896 14.819 ;
     RECT  34.8 13.139 35.448 14.819 ;
     RECT  48.528 14.387 48.552 14.867 ;
     RECT  71.28 14.773 72.912 14.867 ;
     RECT  18.6 7.763 18.912 14.965 ;
     RECT  24 14.197 25.032 15.061 ;
     RECT  23.616 15.061 25.032 15.109 ;
     RECT  13.2 12.467 13.944 15.205 ;
     RECT  63.84 13.813 63.864 15.349 ;
     RECT  63.744 15.349 63.864 15.395 ;
     RECT  81.792 14.197 82.296 15.395 ;
     RECT  75.744 13.477 75.768 15.397 ;
     RECT  22.656 15.109 25.032 15.443 ;
     RECT  30.816 14.819 31.752 15.443 ;
     RECT  43.728 15.157 43.752 15.443 ;
     RECT  40.2 14.675 40.728 15.493 ;
     RECT  51 11.603 51.312 15.493 ;
     RECT  38.304 14.533 38.328 15.731 ;
     RECT  6.768 14.197 8.112 15.733 ;
     RECT  40.2 15.493 40.92 15.733 ;
     RECT  51 15.493 51.432 15.827 ;
     RECT  40.032 15.733 40.92 15.829 ;
     RECT  12.048 15.349 12.072 15.925 ;
     RECT  30.816 15.443 31.656 15.971 ;
     RECT  31.632 15.971 31.656 16.019 ;
     RECT  75.744 15.397 76.44 16.019 ;
     RECT  75.744 16.019 75.768 16.069 ;
     RECT  10.56 15.637 10.584 16.261 ;
     RECT  11.712 15.925 12.072 16.261 ;
     RECT  34.8 14.819 35.112 16.261 ;
     RECT  36.192 15.877 36.216 16.261 ;
     RECT  10.56 16.261 12.072 16.307 ;
     RECT  22.656 15.443 24.888 16.307 ;
     RECT  70.32 16.021 70.344 16.355 ;
     RECT  48.96 15.925 48.984 16.453 ;
     RECT  51 15.827 51.312 16.453 ;
     RECT  53.04 13.283 53.304 16.453 ;
     RECT  66.672 13.715 69 16.453 ;
     RECT  32.928 15.397 32.952 16.499 ;
     RECT  22.656 16.307 22.68 16.501 ;
     RECT  79.344 14.099 79.368 16.501 ;
     RECT  79.344 16.501 79.8 16.547 ;
     RECT  18.6 14.965 19.368 16.595 ;
     RECT  21.696 16.501 22.68 16.643 ;
     RECT  15.936 14.819 15.96 16.787 ;
     RECT  23.712 16.307 24.888 16.787 ;
     RECT  23.856 16.787 24.888 16.885 ;
     RECT  26.208 16.501 26.232 16.885 ;
     RECT  34.8 16.261 36.216 16.885 ;
     RECT  34.704 16.885 36.216 16.931 ;
     RECT  48.96 16.453 51.312 16.979 ;
     RECT  56.4 13.139 56.712 17.029 ;
     RECT  57.984 14.291 58.008 17.029 ;
     RECT  60.864 14.773 62.112 17.029 ;
     RECT  56.4 17.029 58.008 17.075 ;
     RECT  23.856 16.885 25.08 17.123 ;
     RECT  56.4 17.075 57.624 17.171 ;
     RECT  75.12 16.069 75.768 17.171 ;
     RECT  79.776 16.547 79.8 17.171 ;
     RECT  13.104 15.205 13.944 17.219 ;
     RECT  66.672 16.453 69.528 17.267 ;
     RECT  29.4 14.195 29.712 17.413 ;
     RECT  21.696 16.643 21.72 17.459 ;
     RECT  55.344 15.925 55.368 17.509 ;
     RECT  56.4 17.171 57.48 17.509 ;
     RECT  70.704 17.269 70.728 17.555 ;
     RECT  10.8 16.307 12.072 17.603 ;
     RECT  5.712 16.501 5.736 17.605 ;
     RECT  13.2 17.219 13.944 17.605 ;
     RECT  29.184 17.413 29.712 17.605 ;
     RECT  78 8.819 78.312 17.605 ;
     RECT  81.792 15.395 81.816 17.605 ;
     RECT  63.744 15.395 63.768 17.653 ;
     RECT  11.04 17.603 12.072 17.699 ;
     RECT  36.192 16.931 36.216 17.699 ;
     RECT  40.032 15.829 41.64 17.699 ;
     RECT  11.712 17.699 12.072 17.701 ;
     RECT  17.328 15.061 17.352 17.701 ;
     RECT  18.6 16.595 18.912 17.701 ;
     RECT  50.016 16.979 51.312 17.795 ;
     RECT  55.344 17.509 57.48 17.843 ;
     RECT  32.832 17.605 32.856 18.133 ;
     RECT  34.704 16.931 35.112 18.179 ;
     RECT  55.344 17.843 56.712 18.181 ;
     RECT  63.744 17.653 63.912 18.181 ;
     RECT  13.2 17.605 14.808 18.275 ;
     RECT  23.856 17.123 24.888 18.371 ;
     RECT  24 18.371 24.888 18.421 ;
     RECT  4.896 17.605 5.736 18.563 ;
     RECT  31.296 18.133 31.32 18.565 ;
     RECT  32.64 18.133 32.856 18.565 ;
     RECT  47.952 17.317 47.976 18.565 ;
     RECT  60.816 17.029 62.112 18.565 ;
     RECT  29.088 17.605 29.712 18.613 ;
     RECT  81.792 17.605 81.912 18.659 ;
     RECT  5.04 18.563 5.736 18.757 ;
     RECT  6.768 15.733 8.856 18.757 ;
     RECT  28.704 18.613 29.712 18.757 ;
     RECT  31.296 18.565 32.856 18.757 ;
     RECT  81.792 18.659 81.816 18.851 ;
     RECT  5.04 18.757 8.856 18.947 ;
     RECT  11.712 17.701 12.12 18.947 ;
     RECT  17.328 17.701 18.912 18.947 ;
     RECT  54.576 18.181 56.712 18.947 ;
     RECT  11.712 18.947 12.024 19.043 ;
     RECT  63.552 18.181 63.912 19.141 ;
     RECT  66.672 17.267 69 19.235 ;
     RECT  31.296 18.757 32.952 19.237 ;
     RECT  47.856 18.565 47.976 19.333 ;
     RECT  26.208 16.885 26.808 19.379 ;
     RECT  39.024 17.461 39.048 19.379 ;
     RECT  77.376 17.605 78.312 19.379 ;
     RECT  31.296 19.237 33.72 19.427 ;
     RECT  75.744 17.171 75.768 19.427 ;
     RECT  26.208 19.379 26.232 19.475 ;
     RECT  70.752 19.477 70.776 19.619 ;
     RECT  18.6 18.947 18.912 19.861 ;
     RECT  2.4 2.151 2.712 19.909 ;
     RECT  6.288 18.947 8.856 20.003 ;
     RECT  24 18.421 25.224 20.003 ;
     RECT  31.296 19.427 31.32 20.003 ;
     RECT  60.672 18.565 62.112 20.003 ;
     RECT  11.712 19.043 11.736 20.051 ;
     RECT  7.632 20.003 8.856 20.099 ;
     RECT  5.04 18.947 5.064 20.149 ;
     RECT  6.288 20.003 6.36 20.149 ;
     RECT  18.6 19.861 19.032 20.339 ;
     RECT  5.04 20.149 6.36 20.485 ;
     RECT  27.792 18.757 29.712 20.485 ;
     RECT  47.664 19.333 47.976 20.485 ;
     RECT  22.224 18.757 22.248 20.531 ;
     RECT  37.44 19.861 37.464 20.531 ;
     RECT  64.992 17.605 65.016 20.531 ;
     RECT  7.8 20.099 8.856 20.533 ;
     RECT  34.8 18.179 35.112 20.581 ;
     RECT  32.688 19.427 33.72 20.723 ;
     RECT  63.552 19.141 63.96 20.725 ;
     RECT  3.84 20.053 3.864 20.867 ;
     RECT  48.96 16.979 48.984 20.869 ;
     RECT  49.968 19.669 49.992 20.869 ;
     RECT  48.96 20.869 49.992 21.059 ;
     RECT  4.992 20.485 6.36 21.061 ;
     RECT  24 20.003 24.888 21.061 ;
     RECT  32.688 20.723 32.952 21.061 ;
     RECT  75.792 19.909 75.816 21.107 ;
     RECT  17.328 18.947 17.352 21.155 ;
     RECT  26.784 20.773 26.808 21.155 ;
     RECT  55.536 18.947 56.712 21.155 ;
     RECT  81.264 19.909 81.288 21.155 ;
     RECT  61.2 20.003 62.112 21.157 ;
     RECT  63.552 20.725 64.344 21.157 ;
     RECT  61.2 21.157 64.344 21.299 ;
     RECT  38.448 20.821 38.472 21.491 ;
     RECT  67.2 19.235 69 21.637 ;
     RECT  73.92 18.757 73.944 21.683 ;
     RECT  24 21.061 25.608 21.731 ;
     RECT  7.8 20.533 9.096 21.733 ;
     RECT  13.2 18.275 13.944 21.925 ;
     RECT  2.4 19.909 2.856 21.971 ;
     RECT  4.944 21.061 6.36 22.165 ;
     RECT  27.792 20.485 30.408 22.165 ;
     RECT  32.64 21.061 32.952 22.165 ;
     RECT  43.584 22.117 43.608 22.165 ;
     RECT  15.6 21.637 15.624 22.259 ;
     RECT  26.736 22.165 30.408 22.259 ;
     RECT  40.032 17.699 40.92 22.259 ;
     RECT  63.552 21.299 64.344 22.453 ;
     RECT  49.968 21.059 49.992 22.501 ;
     RECT  51 17.795 51.312 22.501 ;
     RECT  13.2 21.925 14.136 22.549 ;
     RECT  54.72 21.829 54.744 22.549 ;
     RECT  75.312 21.637 75.336 22.549 ;
     RECT  63.552 22.453 64.968 22.595 ;
     RECT  49.968 22.501 51.312 22.643 ;
     RECT  54.336 22.549 54.744 22.643 ;
     RECT  54.336 22.643 54.36 22.691 ;
     RECT  24 21.731 24.312 22.741 ;
     RECT  25.344 21.731 25.464 22.741 ;
     RECT  67.2 21.637 69.528 22.787 ;
     RECT  15.984 22.501 16.008 22.835 ;
     RECT  20.064 21.637 20.52 22.835 ;
     RECT  26.736 22.259 30.216 22.835 ;
     RECT  40.2 22.259 40.92 22.835 ;
     RECT  52.656 16.453 53.304 22.883 ;
     RECT  26.736 22.835 26.76 22.979 ;
     RECT  18.6 20.339 18.912 22.981 ;
     RECT  20.064 22.835 20.184 22.981 ;
     RECT  4.512 22.165 6.36 23.029 ;
     RECT  67.2 22.787 67.944 23.123 ;
     RECT  67.2 23.123 67.608 23.269 ;
     RECT  22.176 22.741 22.2 23.317 ;
     RECT  66.912 23.269 67.608 23.317 ;
     RECT  75.312 22.549 75.864 23.317 ;
     RECT  4.176 23.029 6.36 23.555 ;
     RECT  27.792 22.835 30.216 23.651 ;
     RECT  42.816 22.165 43.608 23.651 ;
     RECT  45.6 10.307 45.912 23.653 ;
     RECT  37.008 21.973 37.032 23.795 ;
     RECT  63.552 22.595 64.344 23.797 ;
     RECT  75.312 23.317 76.104 23.797 ;
     RECT  42.816 23.651 43.128 23.843 ;
     RECT  59.184 22.741 59.208 23.845 ;
     RECT  6.288 23.555 6.36 23.893 ;
     RECT  13.104 22.549 14.136 23.893 ;
     RECT  4.176 23.555 5.304 23.987 ;
     RECT  40.2 22.835 40.872 23.987 ;
     RECT  48.96 21.059 48.984 23.987 ;
     RECT  68.976 22.787 69.528 23.987 ;
     RECT  24 22.741 25.464 24.083 ;
     RECT  63.552 23.797 65.016 24.085 ;
     RECT  66.336 23.317 67.608 24.085 ;
     RECT  32.448 22.165 33.24 24.133 ;
     RECT  7.8 21.733 9.528 24.181 ;
     RECT  27.936 23.651 30.216 24.227 ;
     RECT  34.8 20.581 35.544 24.229 ;
     RECT  32.448 24.133 33.432 24.275 ;
     RECT  34.8 24.229 36.072 24.467 ;
     RECT  22.176 23.317 22.728 24.469 ;
     RECT  24 24.083 24.312 24.469 ;
     RECT  78 19.379 78.312 24.469 ;
     RECT  79.776 22.117 79.8 24.469 ;
     RECT  57.744 22.165 57.768 24.563 ;
     RECT  78 24.469 79.8 24.563 ;
     RECT  13.104 23.893 14.808 24.659 ;
     RECT  43.104 23.843 43.128 24.659 ;
     RECT  66.336 24.085 67.896 24.659 ;
     RECT  66.912 24.659 67.896 24.755 ;
     RECT  44.928 23.653 45.912 24.757 ;
     RECT  67.104 24.755 67.896 24.803 ;
     RECT  25.44 24.083 25.464 24.805 ;
     RECT  22.176 24.469 24.312 24.899 ;
     RECT  34.8 24.467 35.544 24.899 ;
     RECT  74.928 23.797 76.104 24.899 ;
     RECT  13.104 24.659 13.944 25.043 ;
     RECT  17.088 24.469 17.112 25.093 ;
     RECT  16.992 25.093 17.112 25.139 ;
     RECT  59.184 23.845 59.832 25.139 ;
     RECT  22.704 24.899 24.312 25.235 ;
     RECT  25.44 24.805 26.376 25.235 ;
     RECT  23.136 25.235 24.312 25.237 ;
     RECT  27.936 24.227 30.024 25.283 ;
     RECT  18.6 22.981 20.184 25.285 ;
     RECT  44.784 24.757 45.912 25.475 ;
     RECT  78 24.563 79.272 25.573 ;
     RECT  4.176 23.987 5.064 25.621 ;
     RECT  6.288 23.893 6.552 25.621 ;
     RECT  27.936 25.283 27.96 25.621 ;
     RECT  29.184 25.283 30.024 25.621 ;
     RECT  78 25.573 79.512 25.667 ;
     RECT  29.184 25.621 30.792 25.715 ;
     RECT  63.552 24.085 65.304 25.715 ;
     RECT  18.6 25.285 20.52 25.717 ;
     RECT  61.2 21.299 62.112 25.717 ;
     RECT  27.648 25.621 27.96 25.763 ;
     RECT  61.008 25.717 62.112 25.859 ;
     RECT  75.648 24.899 76.104 25.909 ;
     RECT  79.488 25.667 79.512 25.955 ;
     RECT  67.2 24.803 67.896 26.101 ;
     RECT  7.8 24.181 10.152 26.243 ;
     RECT  66.48 26.101 67.896 26.243 ;
     RECT  47.568 20.485 47.976 26.483 ;
     RECT  40.2 23.987 40.512 26.629 ;
     RECT  44.928 25.475 45.912 26.629 ;
     RECT  23.136 25.237 25.272 26.725 ;
     RECT  47.664 26.483 47.976 26.725 ;
     RECT  75.648 25.909 76.488 26.725 ;
     RECT  66.48 26.243 67.512 26.771 ;
     RECT  68.976 23.987 69 26.771 ;
     RECT  7.8 26.243 8.712 26.819 ;
     RECT  18.48 25.717 20.52 26.819 ;
     RECT  26.352 25.235 26.376 26.821 ;
     RECT  27.648 25.763 27.672 26.821 ;
     RECT  44.592 26.629 45.912 27.059 ;
     RECT  16.992 25.139 17.016 27.205 ;
     RECT  23.136 26.725 25.368 27.205 ;
     RECT  63.552 25.715 64.92 27.205 ;
     RECT  26.352 26.821 27.672 27.301 ;
     RECT  29.184 25.715 29.712 27.301 ;
     RECT  30.768 25.715 30.792 27.301 ;
     RECT  34.8 24.899 35.112 27.301 ;
     RECT  75.408 26.725 76.488 27.301 ;
     RECT  78 25.667 78.312 27.301 ;
     RECT  26.352 27.301 29.712 27.395 ;
     RECT  7.8 26.819 8.376 27.587 ;
     RECT  18.6 26.819 20.52 27.733 ;
     RECT  34.8 27.301 35.544 27.733 ;
     RECT  36.576 26.821 36.6 27.733 ;
     RECT  18.6 27.733 21.096 27.877 ;
     RECT  16.992 27.205 17.256 27.925 ;
     RECT  44.592 27.059 44.616 27.925 ;
     RECT  4.176 25.621 6.552 27.971 ;
     RECT  28.416 27.395 29.712 27.971 ;
     RECT  34.8 27.733 36.6 27.971 ;
     RECT  49.968 22.643 49.992 27.971 ;
     RECT  72.096 14.867 72.912 27.971 ;
     RECT  16.752 27.925 17.256 28.115 ;
     RECT  42.384 26.629 42.408 28.211 ;
     RECT  32.448 24.275 33.24 28.213 ;
     RECT  5.376 27.971 6.552 28.453 ;
     RECT  7.8 27.587 8.328 28.453 ;
     RECT  45.6 27.059 45.912 28.453 ;
     RECT  47.664 26.725 48.456 28.453 ;
     RECT  75.408 27.301 78.312 28.453 ;
     RECT  79.632 26.629 79.656 28.499 ;
     RECT  40.2 26.629 41.064 28.547 ;
     RECT  38.976 26.773 39 28.643 ;
     RECT  16.752 28.115 16.776 28.837 ;
     RECT  44.16 27.925 44.616 28.933 ;
     RECT  45.6 28.453 48.456 28.933 ;
     RECT  26.352 27.395 26.856 29.029 ;
     RECT  67.2 26.771 67.512 29.029 ;
     RECT  34.8 27.971 36.504 29.123 ;
     RECT  75.408 28.453 78.408 29.123 ;
     RECT  16.416 28.837 16.776 29.219 ;
     RECT  44.16 28.933 48.456 29.219 ;
     RECT  22.896 27.205 25.368 29.317 ;
     RECT  26.352 29.029 27.672 29.317 ;
     RECT  67.2 29.029 67.944 29.365 ;
     RECT  18.6 27.877 21.672 29.461 ;
     RECT  22.896 29.317 27.672 29.461 ;
     RECT  75.408 29.123 78.312 29.461 ;
     RECT  51 22.643 51.312 29.509 ;
     RECT  30.72 27.301 30.792 29.557 ;
     RECT  31.872 28.213 33.24 29.557 ;
     RECT  18.6 29.461 27.672 29.605 ;
     RECT  29.04 27.971 29.712 29.605 ;
     RECT  72.6 27.971 72.912 29.605 ;
     RECT  18.6 29.605 29.712 29.699 ;
     RECT  27.648 29.699 29.712 29.747 ;
     RECT  63.552 27.205 65.688 29.749 ;
     RECT  66.72 29.365 67.944 29.749 ;
     RECT  30.72 29.557 33.24 29.795 ;
     RECT  29.088 29.747 29.712 29.891 ;
     RECT  18.6 29.699 26.184 29.893 ;
     RECT  29.4 29.891 29.712 29.893 ;
     RECT  30.72 29.795 32.808 29.893 ;
     RECT  52.656 22.883 52.68 29.893 ;
     RECT  16.416 29.219 16.632 29.939 ;
     RECT  10.128 26.243 10.152 29.941 ;
     RECT  15.264 27.301 15.288 30.035 ;
     RECT  39.024 28.933 39.048 30.085 ;
     RECT  51 29.509 51.576 30.133 ;
     RECT  4.176 27.971 4.344 30.181 ;
     RECT  5.376 28.453 8.328 30.181 ;
     RECT  34.8 29.123 35.256 30.181 ;
     RECT  36.24 29.123 36.504 30.181 ;
     RECT  29.4 29.893 32.808 30.227 ;
     RECT  17.616 29.893 26.184 30.275 ;
     RECT  44.16 29.219 45.912 30.275 ;
     RECT  47.616 29.219 48.456 30.275 ;
     RECT  63.552 29.749 67.944 30.275 ;
     RECT  38.448 30.085 39.048 30.277 ;
     RECT  40.2 28.547 40.512 30.277 ;
     RECT  72.6 29.605 73.704 30.371 ;
     RECT  75.264 29.461 78.312 30.421 ;
     RECT  34.8 30.181 36.504 30.469 ;
     RECT  42.816 30.373 42.84 30.565 ;
     RECT  50.88 30.133 51.576 30.613 ;
     RECT  52.656 29.893 53.64 30.613 ;
     RECT  42.816 30.565 42.888 30.661 ;
     RECT  42.768 30.661 42.888 30.707 ;
     RECT  54.96 29.605 54.984 30.707 ;
     RECT  4.176 30.181 8.328 30.709 ;
     RECT  13.2 25.043 13.944 30.709 ;
     RECT  61.2 25.859 62.112 30.709 ;
     RECT  63.552 30.275 67.608 30.709 ;
     RECT  75.264 30.421 78.696 30.709 ;
     RECT  83.4 2.151 83.712 30.709 ;
     RECT  50.88 30.613 53.64 30.755 ;
     RECT  10.128 29.941 10.296 30.757 ;
     RECT  47.952 30.275 48.456 30.757 ;
     RECT  12.384 30.709 13.944 30.851 ;
     RECT  42.768 30.707 42.84 30.851 ;
     RECT  61.2 30.709 67.608 30.851 ;
     RECT  10.128 30.757 10.824 30.899 ;
     RECT  61.8 30.851 67.608 30.899 ;
     RECT  4.128 30.709 8.328 30.947 ;
     RECT  27.648 29.747 27.912 30.949 ;
     RECT  74.64 30.709 78.696 31.285 ;
     RECT  82.56 30.709 83.712 31.331 ;
     RECT  34.8 30.469 37.368 31.379 ;
     RECT  74.64 31.285 79.56 31.379 ;
     RECT  16.608 29.939 16.632 31.525 ;
     RECT  17.616 30.275 21.624 31.525 ;
     RECT  31.584 30.227 32.808 31.525 ;
     RECT  61.8 30.899 67.512 31.715 ;
     RECT  13.2 30.851 13.944 31.813 ;
     RECT  44.16 30.275 44.616 31.861 ;
     RECT  45.6 30.275 45.912 31.861 ;
     RECT  31.536 31.525 32.808 31.909 ;
     RECT  22.656 30.275 26.184 31.955 ;
     RECT  27.36 30.949 27.912 31.955 ;
     RECT  44.16 31.861 45.912 32.005 ;
     RECT  27.36 31.955 27.528 32.195 ;
     RECT  69.936 30.757 69.96 32.195 ;
     RECT  2.4 21.971 2.712 32.197 ;
     RECT  4.176 30.947 8.328 32.197 ;
     RECT  13.2 31.813 13.992 32.197 ;
     RECT  47.952 30.757 48.984 32.197 ;
     RECT  34.8 31.379 35.304 32.243 ;
     RECT  74.64 31.379 75.96 32.341 ;
     RECT  74.448 32.341 75.96 32.435 ;
     RECT  2.4 32.197 8.328 32.437 ;
     RECT  61.8 31.715 62.112 32.437 ;
     RECT  13.2 32.197 14.088 32.483 ;
     RECT  27.456 32.195 27.528 32.483 ;
     RECT  10.128 30.899 10.296 32.531 ;
     RECT  43.824 32.005 45.912 32.531 ;
     RECT  44.352 32.531 45.912 32.771 ;
     RECT  80.928 31.285 80.952 32.771 ;
     RECT  10.128 32.531 10.152 32.773 ;
     RECT  41.712 30.325 41.736 33.011 ;
     RECT  47.952 32.197 49.224 33.011 ;
     RECT  74.448 32.435 75.672 33.011 ;
     RECT  16.608 31.525 21.624 33.013 ;
     RECT  22.752 31.955 26.184 33.013 ;
     RECT  47.952 33.011 48.504 33.013 ;
     RECT  16.608 33.013 26.184 33.059 ;
     RECT  34.8 32.243 35.112 33.061 ;
     RECT  19.92 33.059 26.184 33.107 ;
     RECT  42.816 30.851 42.84 33.107 ;
     RECT  21.264 33.107 26.184 33.155 ;
     RECT  29.4 30.227 30.408 33.155 ;
     RECT  34.656 33.061 35.112 33.157 ;
     RECT  31.488 31.909 32.808 33.203 ;
     RECT  61.008 32.437 62.112 33.299 ;
     RECT  2.4 32.437 8.664 33.349 ;
     RECT  36.48 31.379 37.368 33.349 ;
     RECT  16.608 33.059 18.912 33.539 ;
     RECT  22.368 33.155 26.184 33.589 ;
     RECT  27.456 32.483 27.48 33.589 ;
     RECT  22.368 33.589 27.48 33.635 ;
     RECT  63.552 31.715 67.512 33.635 ;
     RECT  25.392 33.635 27.48 33.683 ;
     RECT  47.568 33.013 48.504 33.683 ;
     RECT  63.552 33.635 64.632 33.683 ;
     RECT  76.992 31.379 78.312 33.683 ;
     RECT  79.536 31.379 79.56 33.683 ;
     RECT  63.696 33.683 64.632 33.731 ;
     RECT  77.904 33.683 78.312 33.779 ;
     RECT  75.648 33.011 75.672 33.827 ;
     RECT  44.352 32.771 44.616 33.829 ;
     RECT  68.496 31.909 68.52 33.875 ;
     RECT  61.8 33.299 62.112 33.925 ;
     RECT  78 33.779 78.312 33.925 ;
     RECT  50.88 30.755 52.68 34.165 ;
     RECT  64.32 33.731 64.632 34.259 ;
     RECT  65.664 33.635 67.512 34.355 ;
     RECT  44.256 33.829 44.616 34.357 ;
     RECT  50.304 34.165 52.68 34.403 ;
     RECT  13.2 32.483 13.992 34.597 ;
     RECT  36.384 33.349 37.368 34.643 ;
     RECT  13.104 34.597 13.992 34.739 ;
     RECT  2.4 33.349 8.808 34.883 ;
     RECT  22.368 33.635 24.312 34.883 ;
     RECT  72.6 30.371 72.912 34.885 ;
     RECT  16.8 33.539 18.912 34.931 ;
     RECT  21.264 33.155 21.288 34.931 ;
     RECT  53.904 34.405 53.928 34.933 ;
     RECT  26.16 33.683 27.48 34.981 ;
     RECT  29.4 33.155 29.712 34.981 ;
     RECT  42.192 33.781 42.216 34.981 ;
     RECT  67.2 34.355 67.512 34.981 ;
     RECT  26.16 34.981 29.712 35.123 ;
     RECT  31.488 33.203 32.712 35.123 ;
     RECT  22.896 34.883 24.312 35.221 ;
     RECT  56.4 21.155 56.712 35.221 ;
     RECT  67.2 34.981 68.232 35.267 ;
     RECT  83.4 31.331 83.712 35.269 ;
     RECT  17.376 34.931 18.912 35.317 ;
     RECT  27.12 35.123 29.712 35.363 ;
     RECT  36.48 34.643 37.368 35.363 ;
     RECT  61.8 33.925 62.232 35.363 ;
     RECT  31.632 35.123 32.712 35.411 ;
     RECT  47.952 33.683 48.504 35.413 ;
     RECT  78 33.925 78.696 35.605 ;
     RECT  79.776 35.413 79.8 35.605 ;
     RECT  47.952 35.413 49.128 35.653 ;
     RECT  72.6 34.885 73.368 35.699 ;
     RECT  59.664 35.269 59.688 35.701 ;
     RECT  10.032 32.773 10.152 35.845 ;
     RECT  31.68 35.411 32.712 35.939 ;
     RECT  41.76 34.981 42.216 35.939 ;
     RECT  43.92 34.357 44.616 35.939 ;
     RECT  50.304 34.403 52.392 35.939 ;
     RECT  21.12 35.701 21.144 35.941 ;
     RECT  44.256 35.939 44.616 35.987 ;
     RECT  59.664 35.701 59.88 36.035 ;
     RECT  16.224 35.317 16.248 36.227 ;
     RECT  34.176 33.157 35.112 36.227 ;
     RECT  17.376 35.317 19.416 36.229 ;
     RECT  83.28 35.269 83.712 36.275 ;
     RECT  37.056 35.363 37.368 36.277 ;
     RECT  38.448 30.277 40.512 36.277 ;
     RECT  59.856 36.035 59.88 36.515 ;
     RECT  22.896 35.221 24.888 36.517 ;
     RECT  31.776 35.939 32.712 36.563 ;
     RECT  2.4 34.883 8.376 36.565 ;
     RECT  37.056 36.277 40.512 36.565 ;
     RECT  53.856 34.933 53.928 36.565 ;
     RECT  9.744 35.845 10.152 36.611 ;
     RECT  58.56 36.517 58.584 36.659 ;
     RECT  74.448 33.011 74.472 36.661 ;
     RECT  78 35.605 79.8 36.901 ;
     RECT  74.16 36.661 74.472 36.949 ;
     RECT  75.888 36.805 75.912 36.949 ;
     RECT  17.376 36.229 19.464 36.997 ;
     RECT  20.544 35.941 21.144 36.997 ;
     RECT  17.376 36.997 21.144 37.043 ;
     RECT  67.2 35.267 67.512 37.093 ;
     RECT  64.608 34.259 64.632 37.187 ;
     RECT  65.664 34.355 66.216 37.285 ;
     RECT  44.448 35.987 44.616 37.333 ;
     RECT  53.856 36.565 54.648 37.427 ;
     RECT  64.992 37.285 66.216 37.427 ;
     RECT  44.4 37.333 44.616 37.429 ;
     RECT  45.6 32.771 45.912 37.429 ;
     RECT  74.16 36.949 75.912 37.429 ;
     RECT  50.88 35.939 52.392 37.475 ;
     RECT  2.304 36.565 8.376 37.571 ;
     RECT  28.176 35.363 29.712 37.571 ;
     RECT  41.76 35.939 41.784 37.573 ;
     RECT  44.4 37.429 45.912 37.573 ;
     RECT  47.952 35.653 49.176 37.619 ;
     RECT  17.376 37.043 20.568 37.667 ;
     RECT  74.16 37.429 76.056 37.667 ;
     RECT  41.76 37.573 42.36 37.763 ;
     RECT  77.904 36.901 79.8 37.859 ;
     RECT  22.896 36.517 25.176 37.861 ;
     RECT  77.904 37.859 79.272 37.907 ;
     RECT  44.4 37.573 46.104 37.909 ;
     RECT  22.896 37.861 25.224 38.005 ;
     RECT  27.12 35.363 27.144 38.005 ;
     RECT  69.024 37.573 69.528 38.099 ;
     RECT  2.4 37.571 8.376 38.101 ;
     RECT  10.032 36.611 10.152 38.101 ;
     RECT  60.288 37.573 60.312 38.101 ;
     RECT  44.4 37.909 46.248 38.149 ;
     RECT  29.4 37.571 29.712 38.197 ;
     RECT  31.776 36.563 32.664 38.197 ;
     RECT  31.776 38.197 33.048 38.243 ;
     RECT  47.952 37.619 48.504 38.243 ;
     RECT  72.6 35.699 72.912 38.245 ;
     RECT  22.896 38.005 27.144 38.435 ;
     RECT  50.88 37.475 51.576 38.435 ;
     RECT  47.952 38.243 48.456 38.581 ;
     RECT  17.616 37.667 20.136 38.677 ;
     RECT  28.176 37.571 28.2 38.725 ;
     RECT  61.8 35.363 62.112 38.773 ;
     RECT  22.896 38.435 24.888 38.819 ;
     RECT  42.288 37.763 42.36 38.819 ;
     RECT  78 37.907 79.272 38.819 ;
     RECT  31.824 38.243 33.048 38.867 ;
     RECT  36.144 36.565 40.512 38.867 ;
     RECT  69.024 38.099 69.048 38.867 ;
     RECT  23.904 38.819 24.888 38.915 ;
     RECT  55.68 35.221 56.712 38.917 ;
     RECT  72.6 38.245 73.56 38.965 ;
     RECT  74.976 37.667 76.056 38.965 ;
     RECT  78 38.819 78.696 39.011 ;
     RECT  0.144 38.773 0.168 39.059 ;
     RECT  60.288 38.101 60.456 39.251 ;
     RECT  38.448 38.867 40.512 39.301 ;
     RECT  2.4 38.101 10.152 39.395 ;
     RECT  26.16 38.435 27.144 39.395 ;
     RECT  28.176 38.725 28.392 39.395 ;
     RECT  47.856 38.581 48.456 39.395 ;
     RECT  44.4 38.149 46.776 39.443 ;
     RECT  29.4 38.197 30.216 39.491 ;
     RECT  17.616 38.677 20.712 39.587 ;
     RECT  48.432 39.395 48.456 39.587 ;
     RECT  72.6 38.965 76.056 39.589 ;
     RECT  5.376 39.395 10.152 39.685 ;
     RECT  72.48 39.589 76.056 39.731 ;
     RECT  36.144 38.867 37.08 39.829 ;
     RECT  38.448 39.301 40.824 39.829 ;
     RECT  65.664 37.427 66.216 39.829 ;
     RECT  23.904 38.915 24.312 39.875 ;
     RECT  24 39.875 24.312 39.877 ;
     RECT  5.376 39.685 10.2 39.923 ;
     RECT  18.6 39.587 20.712 39.923 ;
     RECT  31.824 38.867 32.28 39.973 ;
     RECT  2.4 39.395 4.248 40.019 ;
     RECT  51 38.435 51.576 40.021 ;
     RECT  61.632 38.773 62.112 40.067 ;
     RECT  58.704 38.821 58.728 40.115 ;
     RECT  52.704 39.301 52.728 40.165 ;
     RECT  54.624 37.427 54.648 40.213 ;
     RECT  55.68 38.917 57.144 40.259 ;
     RECT  74.064 39.731 76.056 40.451 ;
     RECT  24 39.877 24.408 40.453 ;
     RECT  50.88 40.021 51.576 40.453 ;
     RECT  18.6 39.923 20.376 40.499 ;
     RECT  48.96 39.829 48.984 40.499 ;
     RECT  65.328 39.829 66.216 40.499 ;
     RECT  28.176 39.395 28.2 40.597 ;
     RECT  5.376 39.923 10.152 40.645 ;
     RECT  42.336 38.819 42.36 40.789 ;
     RECT  60.288 39.251 60.312 40.789 ;
     RECT  67.2 37.093 67.992 40.835 ;
     RECT  5.328 40.645 10.152 40.883 ;
     RECT  36.144 39.829 40.824 40.931 ;
     RECT  54.48 40.213 54.648 40.933 ;
     RECT  55.68 40.259 56.712 40.933 ;
     RECT  59.904 40.789 60.312 40.979 ;
     RECT  44.4 39.443 46.248 40.981 ;
     RECT  50.736 40.453 51.576 40.981 ;
     RECT  52.704 40.165 53.016 40.981 ;
     RECT  50.736 40.981 53.016 41.027 ;
     RECT  22.896 38.819 22.92 41.029 ;
     RECT  31.536 39.973 32.28 41.029 ;
     RECT  37.728 40.931 40.824 41.075 ;
     RECT  72.48 39.731 72.912 41.075 ;
     RECT  44.4 40.981 46.92 41.077 ;
     RECT  65.328 40.499 65.688 41.171 ;
     RECT  22.896 41.029 23.016 41.219 ;
     RECT  26.736 39.395 27.144 41.219 ;
     RECT  5.424 40.883 10.152 41.317 ;
     RECT  19.968 40.499 20.376 41.365 ;
     RECT  13.2 34.739 13.896 41.605 ;
     RECT  14.976 37.573 15 41.605 ;
     RECT  83.4 36.275 83.712 41.605 ;
     RECT  19.968 41.365 20.472 41.651 ;
     RECT  37.728 41.075 40.512 41.651 ;
     RECT  31.536 41.029 32.76 41.701 ;
     RECT  5.424 41.317 10.248 41.939 ;
     RECT  24 40.453 24.504 41.939 ;
     RECT  38.256 41.651 40.512 42.035 ;
     RECT  67.2 40.835 67.512 42.085 ;
     RECT  42.336 40.789 42.744 42.179 ;
     RECT  59.904 40.979 59.976 42.181 ;
     RECT  5.712 41.939 10.248 42.227 ;
     RECT  13.2 41.605 15 42.227 ;
     RECT  54.48 40.933 56.712 42.227 ;
     RECT  65.664 41.171 65.688 42.323 ;
     RECT  82.656 41.605 83.712 42.419 ;
     RECT  74.064 40.451 75 42.421 ;
     RECT  76.032 40.451 76.056 42.421 ;
     RECT  26.736 41.219 27 42.565 ;
     RECT  28.176 40.597 28.296 42.565 ;
     RECT  22.896 41.219 22.92 42.661 ;
     RECT  24 41.939 24.456 42.661 ;
     RECT  50.88 41.027 53.016 42.707 ;
     RECT  72.6 41.075 72.912 42.709 ;
     RECT  5.712 42.227 10.152 42.755 ;
     RECT  55.296 42.227 56.712 42.755 ;
     RECT  30.864 41.701 32.76 42.757 ;
     RECT  14.784 42.227 15 42.803 ;
     RECT  22.896 42.661 24.456 42.803 ;
     RECT  30.768 42.757 32.76 42.803 ;
     RECT  59.904 42.181 60.6 42.803 ;
     RECT  16.512 41.749 16.536 42.851 ;
     RECT  30.768 42.803 32.376 42.899 ;
     RECT  71.856 42.709 72.912 42.899 ;
     RECT  23.328 42.803 24.456 42.901 ;
     RECT  5.904 42.755 10.152 42.947 ;
     RECT  44.4 41.077 47.592 43.139 ;
     RECT  14.976 42.803 15 43.141 ;
     RECT  14.976 43.141 15.384 43.187 ;
     RECT  40.2 42.035 40.512 43.285 ;
     RECT  69.888 42.517 69.912 43.379 ;
     RECT  67.2 42.085 68.04 43.523 ;
     RECT  11.424 43.285 11.448 43.525 ;
     RECT  38.256 42.035 39.144 43.717 ;
     RECT  74.064 42.421 76.056 43.717 ;
     RECT  80.4 43.093 80.424 43.765 ;
     RECT  20.304 41.651 20.472 43.813 ;
     RECT  5.904 42.947 10.056 43.861 ;
     RECT  55.296 42.755 55.32 43.861 ;
     RECT  78 39.011 78.312 43.861 ;
     RECT  66.144 43.285 66.168 43.907 ;
     RECT  79.584 43.765 80.424 43.955 ;
     RECT  23.328 42.901 24.648 44.003 ;
     RECT  56.4 42.755 56.712 44.053 ;
     RECT  5.328 43.861 10.056 44.195 ;
     RECT  44.4 43.139 45.912 44.293 ;
     RECT  30.864 42.899 32.376 44.339 ;
     RECT  37.776 43.717 39.144 44.339 ;
     RECT  7.68 44.195 10.056 44.389 ;
     RECT  7.68 44.389 10.2 44.435 ;
     RECT  30.864 44.339 32.232 44.435 ;
     RECT  15.36 43.187 15.384 44.437 ;
     RECT  50.88 42.707 52.392 44.437 ;
     RECT  5.328 44.195 6.312 44.483 ;
     RECT  59.904 42.803 59.976 44.483 ;
     RECT  20.016 43.813 20.472 44.579 ;
     RECT  23.712 44.003 24.648 44.629 ;
     RECT  50.88 44.437 52.488 44.629 ;
     RECT  55.296 43.861 55.416 44.629 ;
     RECT  56.4 44.053 56.808 44.629 ;
     RECT  40.2 43.285 41.112 44.771 ;
     RECT  26.736 42.565 28.296 44.965 ;
     RECT  34.8 36.227 35.112 44.965 ;
     RECT  36.144 40.931 36.168 44.965 ;
     RECT  65.904 44.245 65.928 44.965 ;
     RECT  2.4 40.019 4.104 45.013 ;
     RECT  5.328 44.483 5.352 45.013 ;
     RECT  42.336 42.179 42.36 45.013 ;
     RECT  53.712 44.341 53.736 45.013 ;
     RECT  61.8 40.067 62.112 45.013 ;
     RECT  11.424 43.525 12.216 45.059 ;
     RECT  34.8 44.965 36.168 45.155 ;
     RECT  67.2 43.523 67.608 45.253 ;
     RECT  63.84 43.285 63.864 45.443 ;
     RECT  0.144 45.205 0.168 45.491 ;
     RECT  42.144 45.013 42.36 45.491 ;
     RECT  59.952 44.483 59.976 45.491 ;
     RECT  20.304 44.579 20.472 45.493 ;
     RECT  43.92 44.293 45.912 45.493 ;
     RECT  20.304 45.493 20.568 45.541 ;
     RECT  79.584 43.955 79.608 45.541 ;
     RECT  42.144 45.491 42.168 45.587 ;
     RECT  7.68 44.435 9.144 45.589 ;
     RECT  47.568 43.139 47.592 45.589 ;
     RECT  48.72 44.965 48.744 45.589 ;
     RECT  14.784 44.437 15.384 45.635 ;
     RECT  26.64 44.965 28.296 45.635 ;
     RECT  43.92 45.493 46.008 45.635 ;
     RECT  57.888 43.285 57.912 45.635 ;
     RECT  53.616 45.013 53.736 45.683 ;
     RECT  11.424 45.059 11.976 45.875 ;
     RECT  14.784 45.635 14.808 45.875 ;
     RECT  37.776 44.339 37.8 45.971 ;
     RECT  53.712 45.683 53.736 46.117 ;
     RECT  55.296 44.629 56.808 46.117 ;
     RECT  39.12 44.339 39.144 46.211 ;
     RECT  47.568 45.589 48.744 46.211 ;
     RECT  23.712 44.629 24.888 46.261 ;
     RECT  30.864 44.435 32.088 46.261 ;
     RECT  26.64 45.635 27.576 46.355 ;
     RECT  16.224 45.829 16.248 46.499 ;
     RECT  23.712 46.261 24.984 46.501 ;
     RECT  40.2 44.771 40.512 46.501 ;
     RECT  44.544 45.635 46.008 46.595 ;
     RECT  61.488 45.013 62.112 46.597 ;
     RECT  7.44 45.589 9.144 46.645 ;
     RECT  33.408 44.965 33.432 46.645 ;
     RECT  44.592 46.595 46.008 46.645 ;
     RECT  47.856 46.211 48.744 46.645 ;
     RECT  69.408 44.725 69.432 46.645 ;
     RECT  13.2 42.227 13.512 46.693 ;
     RECT  79.584 45.541 80.28 46.693 ;
     RECT  39.264 46.501 40.512 46.885 ;
     RECT  23.712 46.501 25.08 46.933 ;
     RECT  34.8 45.155 35.4 47.075 ;
     RECT  23.712 46.933 25.176 47.125 ;
     RECT  67.2 45.253 67.704 47.125 ;
     RECT  6.912 46.645 9.144 47.173 ;
     RECT  18.6 40.499 18.912 47.173 ;
     RECT  20.256 45.541 20.568 47.173 ;
     RECT  30.864 46.261 32.184 47.221 ;
     RECT  33.168 46.645 33.432 47.221 ;
     RECT  23.712 47.125 25.272 47.267 ;
     RECT  17.232 46.069 17.256 47.269 ;
     RECT  50.88 44.629 52.584 47.269 ;
     RECT  26.64 46.355 27.48 47.315 ;
     RECT  2.4 45.013 5.352 47.317 ;
     RECT  6.912 47.173 9.192 47.317 ;
     RECT  11.952 45.875 11.976 47.363 ;
     RECT  30.864 47.221 33.432 47.363 ;
     RECT  61.488 46.597 62.232 47.363 ;
     RECT  65.52 44.965 65.928 47.363 ;
     RECT  2.4 47.317 9.192 47.411 ;
     RECT  23.712 47.267 24.456 47.459 ;
     RECT  2.4 47.411 9.144 47.555 ;
     RECT  50.832 47.269 52.584 47.605 ;
     RECT  50.736 47.605 52.584 47.653 ;
     RECT  13.2 46.693 14.424 47.845 ;
     RECT  18.6 47.173 20.568 47.845 ;
     RECT  44.592 46.645 46.056 47.845 ;
     RECT  61.8 47.363 62.232 47.845 ;
     RECT  65.52 47.363 65.544 47.845 ;
     RECT  67.104 47.125 67.704 47.845 ;
     RECT  13.2 47.845 14.808 47.891 ;
     RECT  65.424 47.845 65.544 47.891 ;
     RECT  30.864 47.363 32.328 47.939 ;
     RECT  67.104 47.845 67.896 47.939 ;
     RECT  53.712 46.117 56.808 48.131 ;
     RECT  39.264 46.885 41.064 48.179 ;
     RECT  83.4 42.419 83.712 48.181 ;
     RECT  37.056 47.029 37.08 48.229 ;
     RECT  74.064 43.717 76.104 48.277 ;
     RECT  2.4 47.555 4.632 48.371 ;
     RECT  14.784 47.891 14.808 48.371 ;
     RECT  16.368 47.269 17.256 48.371 ;
     RECT  37.008 48.229 37.08 48.371 ;
     RECT  47.856 46.645 49.32 48.371 ;
     RECT  55.392 48.131 56.808 48.371 ;
     RECT  50.736 47.653 52.728 48.421 ;
     RECT  33.408 47.363 33.432 48.467 ;
     RECT  16.368 48.371 16.392 48.659 ;
     RECT  48.48 48.371 49.32 48.659 ;
     RECT  48.528 48.659 49.32 48.707 ;
     RECT  83.28 48.181 83.712 48.755 ;
     RECT  5.616 47.555 9.144 48.805 ;
     RECT  10.176 44.435 10.2 48.805 ;
     RECT  50.544 48.421 52.728 48.949 ;
     RECT  53.712 48.131 53.736 48.949 ;
     RECT  61.8 47.845 62.28 48.995 ;
     RECT  65.424 47.891 65.448 48.997 ;
     RECT  26.64 47.315 26.664 49.043 ;
     RECT  30.864 47.939 31.128 49.043 ;
     RECT  48.528 48.707 49.08 49.043 ;
     RECT  37.008 48.371 37.032 49.091 ;
     RECT  79.584 46.693 80.328 49.091 ;
     RECT  69.12 46.645 69.432 49.189 ;
     RECT  77.664 43.861 78.312 49.189 ;
     RECT  50.544 48.949 53.736 49.235 ;
     RECT  22.464 49.237 22.488 49.285 ;
     RECT  42.912 48.805 42.936 49.333 ;
     RECT  34.8 47.075 35.112 49.381 ;
     RECT  77.664 49.189 78.504 49.381 ;
     RECT  5.616 48.805 10.2 49.429 ;
     RECT  40.2 48.179 41.064 49.475 ;
     RECT  31.056 49.043 31.128 49.525 ;
     RECT  32.16 47.939 32.328 49.525 ;
     RECT  42.816 49.333 42.936 49.525 ;
     RECT  67.2 47.939 67.896 49.525 ;
     RECT  68.928 49.189 69.432 49.525 ;
     RECT  31.056 49.525 32.328 49.619 ;
     RECT  65.424 48.997 66.168 49.619 ;
     RECT  56.256 48.371 56.808 49.717 ;
     RECT  67.2 49.525 69.432 49.907 ;
     RECT  40.2 49.475 40.632 49.909 ;
     RECT  59.568 46.405 59.592 49.909 ;
     RECT  31.104 49.619 32.328 49.957 ;
     RECT  21.888 49.285 22.488 50.051 ;
     RECT  67.2 49.907 69.192 50.099 ;
     RECT  18.6 47.845 20.664 50.101 ;
     RECT  21.888 50.051 21.912 50.101 ;
     RECT  18.6 50.101 21.912 50.147 ;
     RECT  77.664 49.381 79.224 50.195 ;
     RECT  40.08 49.909 40.632 50.197 ;
     RECT  2.4 48.371 4.104 50.243 ;
     RECT  23.712 47.459 24.312 50.243 ;
     RECT  34.176 49.381 35.112 50.243 ;
     RECT  38.352 49.189 38.376 50.243 ;
     RECT  67.2 50.099 69.144 50.243 ;
     RECT  40.032 50.197 40.632 50.341 ;
     RECT  56.256 49.717 56.856 50.533 ;
     RECT  77.664 50.195 78.504 50.627 ;
     RECT  60.768 48.949 60.792 50.629 ;
     RECT  61.8 48.995 62.232 50.629 ;
     RECT  44.592 47.845 46.344 50.675 ;
     RECT  50.544 49.235 53.496 50.677 ;
     RECT  55.2 50.629 55.224 50.677 ;
     RECT  50.544 50.677 55.224 50.723 ;
     RECT  31.104 49.957 32.424 50.771 ;
     RECT  21.6 50.147 21.912 50.819 ;
     RECT  58.704 49.909 59.592 50.821 ;
     RECT  56.256 50.533 56.904 50.869 ;
     RECT  58.32 50.821 59.592 50.869 ;
     RECT  5.136 49.429 10.2 50.963 ;
     RECT  31.92 50.771 32.424 51.059 ;
     RECT  11.856 50.629 11.88 51.061 ;
     RECT  50.64 50.723 55.224 51.203 ;
     RECT  45.6 50.675 46.344 51.253 ;
     RECT  5.136 50.963 8.232 51.299 ;
     RECT  65.424 49.619 65.448 51.301 ;
     RECT  3.744 50.243 4.104 51.347 ;
     RECT  9.216 50.963 10.2 51.347 ;
     RECT  60.768 50.629 62.232 51.347 ;
     RECT  11.28 51.061 11.88 51.395 ;
     RECT  32.016 51.059 32.424 51.395 ;
     RECT  67.2 50.243 68.952 51.443 ;
     RECT  48.528 49.043 48.984 51.445 ;
     RECT  39.888 50.341 40.632 51.541 ;
     RECT  61.152 51.347 62.232 51.541 ;
     RECT  61.152 51.541 62.424 51.635 ;
     RECT  3.744 51.347 3.96 51.779 ;
     RECT  39.888 51.541 41.592 51.779 ;
     RECT  13.2 47.891 13.512 51.781 ;
     RECT  48.528 51.445 49.608 51.829 ;
     RECT  50.64 51.203 54.984 51.829 ;
     RECT  39.984 51.779 41.592 51.877 ;
     RECT  3.744 51.779 3.912 51.923 ;
     RECT  5.664 51.299 8.232 51.923 ;
     RECT  45.6 51.253 47.016 51.923 ;
     RECT  6.24 51.923 8.232 51.971 ;
     RECT  81.36 50.965 81.384 52.019 ;
     RECT  65.424 51.301 65.688 52.163 ;
     RECT  39.984 51.877 41.64 52.165 ;
     RECT  42.816 49.525 43.368 52.165 ;
     RECT  56.256 50.869 59.592 52.165 ;
     RECT  0.144 51.973 0.168 52.259 ;
     RECT  11.28 51.395 11.304 52.357 ;
     RECT  12.336 51.781 13.512 52.357 ;
     RECT  11.28 52.357 13.512 52.403 ;
     RECT  67.2 51.443 68.712 52.405 ;
     RECT  48.528 51.829 54.984 52.547 ;
     RECT  3.744 51.923 3.768 52.691 ;
     RECT  80.304 49.091 80.328 52.691 ;
     RECT  39.984 52.165 43.368 52.739 ;
     RECT  39.984 52.739 41.592 52.883 ;
     RECT  74.064 48.277 76.344 52.981 ;
     RECT  77.664 50.627 78.312 52.981 ;
     RECT  11.424 52.403 13.512 53.027 ;
     RECT  24 50.243 24.312 53.029 ;
     RECT  25.344 49.669 25.368 53.029 ;
     RECT  48.624 52.547 54.984 53.075 ;
     RECT  10.176 51.347 10.2 53.077 ;
     RECT  32.016 51.395 32.04 53.123 ;
     RECT  6.24 51.971 8.112 53.125 ;
     RECT  61.68 51.635 62.424 53.269 ;
     RECT  38.304 51.637 38.328 53.317 ;
     RECT  54.48 53.075 54.984 53.365 ;
     RECT  56.16 52.165 59.592 53.365 ;
     RECT  11.424 53.027 11.448 53.507 ;
     RECT  13.2 53.027 13.512 53.557 ;
     RECT  66.576 52.405 68.712 53.557 ;
     RECT  69.984 52.549 70.008 53.557 ;
     RECT  66.576 53.557 70.008 53.603 ;
     RECT  74.064 52.981 78.312 53.651 ;
     RECT  21.888 50.819 21.912 53.797 ;
     RECT  5.088 53.029 5.112 54.037 ;
     RECT  6.144 53.125 8.112 54.037 ;
     RECT  54.48 53.365 59.592 54.083 ;
     RECT  5.088 54.037 8.112 54.085 ;
     RECT  4.464 54.085 8.112 54.131 ;
     RECT  42.816 52.739 43.368 54.179 ;
     RECT  48.624 53.075 52.968 54.325 ;
     RECT  54.672 54.083 59.592 54.371 ;
     RECT  39.984 52.883 41.112 54.613 ;
     RECT  42.816 54.179 42.84 54.613 ;
     RECT  10.176 53.077 10.44 54.661 ;
     RECT  65.424 52.163 65.448 54.661 ;
     RECT  67.2 53.603 70.008 54.661 ;
     RECT  70.992 50.245 71.016 54.661 ;
     RECT  24 53.029 25.368 54.755 ;
     RECT  39.984 54.613 42.84 54.755 ;
     RECT  9.648 54.661 10.44 54.949 ;
     RECT  54.96 54.371 59.592 54.949 ;
     RECT  38.304 53.317 38.904 55.093 ;
     RECT  39.984 54.755 41.112 55.093 ;
     RECT  38.304 55.093 41.112 55.187 ;
     RECT  54.96 54.949 59.832 55.189 ;
     RECT  60.96 53.269 62.424 55.189 ;
     RECT  4.464 54.131 4.488 55.237 ;
     RECT  48.624 54.325 53.064 55.237 ;
     RECT  74.064 53.651 76.344 55.237 ;
     RECT  77.664 53.651 78.312 55.237 ;
     RECT  80.208 54.565 80.232 55.237 ;
     RECT  4.464 55.237 4.728 55.285 ;
     RECT  67.2 54.661 71.016 55.331 ;
     RECT  9.648 54.949 10.584 55.379 ;
     RECT  54.96 55.189 62.424 55.523 ;
     RECT  5.952 54.131 8.112 55.525 ;
     RECT  72.6 42.899 72.912 55.525 ;
     RECT  74.064 55.237 78.312 55.525 ;
     RECT  3.84 55.285 4.728 55.571 ;
     RECT  10.56 55.379 10.584 55.573 ;
     RECT  31.584 53.797 31.896 55.573 ;
     RECT  69.984 55.331 71.016 55.669 ;
     RECT  5.712 55.525 8.112 55.813 ;
     RECT  45.6 51.923 46.344 55.813 ;
     RECT  65.424 54.661 65.688 55.813 ;
     RECT  80.208 55.237 80.904 55.813 ;
     RECT  21.888 53.797 22.872 55.907 ;
     RECT  26.592 53.941 26.616 55.907 ;
     RECT  72.6 55.525 78.312 55.907 ;
     RECT  4.464 55.571 4.728 55.955 ;
     RECT  48.624 55.237 53.112 55.955 ;
     RECT  2.4 50.243 2.712 55.957 ;
     RECT  42.816 54.755 42.84 55.957 ;
     RECT  55.344 55.523 62.424 56.053 ;
     RECT  63.408 55.717 63.432 56.053 ;
     RECT  5.712 55.813 8.568 56.389 ;
     RECT  25.344 54.755 25.368 56.389 ;
     RECT  67.2 55.331 68.712 56.389 ;
     RECT  69.984 55.669 71.4 56.389 ;
     RECT  72.6 55.907 76.392 56.389 ;
     RECT  4.464 55.955 4.488 56.483 ;
     RECT  55.344 56.053 63.432 56.483 ;
     RECT  67.2 56.389 76.392 56.483 ;
     RECT  5.712 56.389 9.096 56.531 ;
     RECT  74.064 56.483 76.392 56.531 ;
     RECT  42.096 55.957 42.84 56.579 ;
     RECT  11.904 55.573 11.928 56.677 ;
     RECT  44.592 50.675 44.616 56.725 ;
     RECT  45.6 55.813 46.968 56.725 ;
     RECT  64.656 55.813 65.688 56.771 ;
     RECT  37.008 56.677 37.032 56.867 ;
     RECT  44.592 56.725 46.968 56.867 ;
     RECT  67.2 56.483 72.912 56.869 ;
     RECT  67.104 56.869 72.912 56.917 ;
     RECT  77.664 55.907 78.312 56.917 ;
     RECT  5.712 56.531 6.264 56.965 ;
     RECT  55.344 56.483 63.24 56.965 ;
     RECT  77.664 56.917 79.128 56.965 ;
     RECT  45.6 56.867 46.968 57.059 ;
     RECT  65.664 56.771 65.688 57.059 ;
     RECT  66.72 56.917 72.912 57.107 ;
     RECT  48.96 55.955 53.112 57.301 ;
     RECT  7.584 56.531 9.096 57.395 ;
     RECT  10.56 55.573 10.92 57.443 ;
     RECT  69.984 57.107 72.912 57.491 ;
     RECT  10.56 57.443 10.824 57.493 ;
     RECT  2.4 55.957 3.48 57.541 ;
     RECT  48.912 57.301 53.112 57.541 ;
     RECT  80.208 55.813 81 57.541 ;
     RECT  10.512 57.493 10.824 57.587 ;
     RECT  34.8 50.243 35.112 57.589 ;
     RECT  55.296 56.965 63.24 57.635 ;
     RECT  38.304 55.187 40.512 57.637 ;
     RECT  4.848 56.965 6.264 57.875 ;
     RECT  48.48 57.541 53.112 57.971 ;
     RECT  5.04 57.875 6.264 58.019 ;
     RECT  18.6 50.147 19.752 58.117 ;
     RECT  5.04 58.019 6.024 58.163 ;
     RECT  64.656 56.771 64.68 58.501 ;
     RECT  37.824 57.637 40.512 58.595 ;
     RECT  48.48 57.971 53.016 58.597 ;
     RECT  74.064 56.531 75.912 58.597 ;
     RECT  25.344 56.389 25.512 58.645 ;
     RECT  44.592 56.867 44.616 58.645 ;
     RECT  77.664 56.965 79.224 58.645 ;
     RECT  80.208 57.541 81.912 58.645 ;
     RECT  74.064 58.597 76.296 58.693 ;
     RECT  77.328 58.645 81.912 58.693 ;
     RECT  13.2 53.557 13.848 58.739 ;
     RECT  18.144 58.117 19.752 58.739 ;
     RECT  34.8 57.589 35.208 58.885 ;
     RECT  7.8 57.395 9.096 58.931 ;
     RECT  11.904 56.677 12.216 58.931 ;
     RECT  37.872 58.595 40.512 58.979 ;
     RECT  71.52 57.491 72.912 59.077 ;
     RECT  42.816 56.579 42.84 59.125 ;
     RECT  64.656 58.501 65.112 59.171 ;
     RECT  66.72 57.107 68.952 59.173 ;
     RECT  69.984 57.491 70.344 59.173 ;
     RECT  6 58.163 6.024 59.221 ;
     RECT  74.064 58.693 81.912 59.267 ;
     RECT  25.344 58.645 26.184 59.315 ;
     RECT  34.704 58.885 35.208 59.315 ;
     RECT  58.656 57.635 63.24 59.315 ;
     RECT  66.72 59.173 70.344 59.315 ;
     RECT  55.296 57.635 57.672 59.413 ;
     RECT  37.872 58.979 39.192 59.507 ;
     RECT  69.264 59.315 70.344 59.651 ;
     RECT  64.8 59.171 65.112 59.701 ;
     RECT  48.288 58.597 53.016 59.795 ;
     RECT  64.8 59.701 65.256 59.797 ;
     RECT  66.72 59.315 68.04 59.797 ;
     RECT  74.064 59.267 80.76 59.797 ;
     RECT  71.376 59.077 72.912 59.845 ;
     RECT  73.968 59.797 80.76 59.845 ;
     RECT  60.72 59.315 63.24 59.891 ;
     RECT  81.888 59.267 81.912 59.891 ;
     RECT  42.048 59.125 42.84 59.893 ;
     RECT  26.16 59.315 26.184 59.987 ;
     RECT  71.376 59.845 80.76 60.131 ;
     RECT  48.48 59.795 53.016 60.133 ;
     RECT  6 59.221 6.696 60.181 ;
     RECT  41.712 59.893 42.84 60.181 ;
     RECT  41.712 60.181 43.272 60.227 ;
     RECT  5.136 60.181 6.696 60.275 ;
     RECT  7.8 58.931 8.904 60.275 ;
     RECT  41.712 60.227 42.072 60.275 ;
     RECT  31.536 55.573 31.896 60.277 ;
     RECT  32.976 59.797 33 60.277 ;
     RECT  64.8 59.797 68.04 60.277 ;
     RECT  37.872 59.507 38.328 60.373 ;
     RECT  12.192 58.931 12.216 60.421 ;
     RECT  13.2 58.739 13.512 60.421 ;
     RECT  12.192 60.421 13.512 60.467 ;
     RECT  69.984 59.651 70.344 60.467 ;
     RECT  80.304 60.131 80.76 60.467 ;
     RECT  2.4 57.541 3.528 60.563 ;
     RECT  64.656 60.277 68.04 60.563 ;
     RECT  80.304 60.467 80.424 60.659 ;
     RECT  42.048 60.275 42.072 60.707 ;
     RECT  5.136 60.275 6.312 60.803 ;
     RECT  31.536 60.277 33 60.901 ;
     RECT  43.248 60.227 43.272 60.901 ;
     RECT  44.496 58.645 44.616 60.901 ;
     RECT  34.704 59.315 35.112 60.947 ;
     RECT  18.48 58.739 19.752 60.949 ;
     RECT  36.96 60.373 38.328 60.997 ;
     RECT  5.664 60.803 6.312 61.043 ;
     RECT  31.536 60.901 33.384 61.043 ;
     RECT  18.288 60.949 19.752 61.091 ;
     RECT  54.912 59.413 57.672 61.189 ;
     RECT  10.512 57.587 10.584 61.237 ;
     RECT  70.176 60.467 70.344 61.237 ;
     RECT  71.376 60.131 79.224 61.237 ;
     RECT  10.272 61.237 10.584 61.283 ;
     RECT  45.6 57.059 46.344 61.333 ;
     RECT  10.272 61.283 10.536 61.379 ;
     RECT  5.664 61.043 6.024 61.427 ;
     RECT  10.272 61.379 10.296 61.427 ;
     RECT  31.536 61.043 33 61.427 ;
     RECT  48.48 60.133 53.496 61.477 ;
     RECT  54.672 61.189 57.672 61.477 ;
     RECT  70.176 61.237 79.224 61.477 ;
     RECT  58.656 59.315 59.496 61.525 ;
     RECT  60.72 59.891 63.096 61.525 ;
     RECT  7.8 60.275 8.112 61.573 ;
     RECT  64.656 60.563 65.256 61.573 ;
     RECT  48.48 61.477 57.672 61.619 ;
     RECT  58.656 61.525 63.096 61.619 ;
     RECT  64.656 61.573 65.4 61.621 ;
     RECT  31.68 61.427 33 61.667 ;
     RECT  29.4 39.491 29.712 61.717 ;
     RECT  66.528 60.563 68.04 61.765 ;
     RECT  56.256 61.619 57.672 61.859 ;
     RECT  15.984 60.373 16.008 61.907 ;
     RECT  36.288 60.997 38.328 61.907 ;
     RECT  43.248 60.901 44.616 61.907 ;
     RECT  34.8 60.947 35.112 61.909 ;
     RECT  70.128 61.477 79.224 61.957 ;
     RECT  58.896 61.619 63.096 62.101 ;
     RECT  64.656 61.621 65.496 62.101 ;
     RECT  48.48 61.619 54.936 62.147 ;
     RECT  44.112 61.907 44.616 62.149 ;
     RECT  45.6 61.333 46.776 62.149 ;
     RECT  12.528 60.467 13.512 62.195 ;
     RECT  36.96 61.907 38.328 62.195 ;
     RECT  80.304 60.659 80.328 62.195 ;
     RECT  44.112 62.149 46.776 62.339 ;
     RECT  40.2 58.979 40.512 62.389 ;
     RECT  21.888 55.907 21.912 62.437 ;
     RECT  22.992 59.557 23.016 62.437 ;
     RECT  37.584 62.195 38.328 62.437 ;
     RECT  39.312 62.389 40.512 62.437 ;
     RECT  70.08 61.957 79.224 62.437 ;
     RECT  70.08 62.437 79.704 62.533 ;
     RECT  13.104 62.195 13.512 62.579 ;
     RECT  66.528 61.765 68.376 62.581 ;
     RECT  21.888 62.437 23.016 62.675 ;
     RECT  37.584 62.437 40.512 62.675 ;
     RECT  69.984 62.533 79.704 62.675 ;
     RECT  66.528 62.581 68.568 62.723 ;
     RECT  5.664 61.427 5.688 62.771 ;
     RECT  7.2 61.573 8.112 62.771 ;
     RECT  37.584 62.675 38.328 62.771 ;
     RECT  54.672 62.147 54.936 62.771 ;
     RECT  67.2 62.723 68.568 62.821 ;
     RECT  69.984 62.675 78.696 62.821 ;
     RECT  18.6 61.091 19.752 63.157 ;
     RECT  48.48 62.147 53.496 63.157 ;
     RECT  56.256 61.859 57.576 63.157 ;
     RECT  58.896 62.101 65.496 63.157 ;
     RECT  44.112 62.339 46.344 63.251 ;
     RECT  79.68 62.675 79.704 63.251 ;
     RECT  34.704 61.909 35.112 63.299 ;
     RECT  67.2 62.821 78.696 63.299 ;
     RECT  40.2 62.675 40.512 63.445 ;
     RECT  9.84 61.861 9.864 63.491 ;
     RECT  44.592 63.251 46.344 63.491 ;
     RECT  54.912 62.771 54.936 63.491 ;
     RECT  68.544 63.299 78.696 63.539 ;
     RECT  44.592 63.491 44.616 63.587 ;
     RECT  32.976 61.667 33 63.637 ;
     RECT  56.256 63.157 66.168 63.779 ;
     RECT  40.2 63.445 40.632 63.781 ;
     RECT  31.68 61.667 31.704 63.875 ;
     RECT  64.512 63.779 66.168 63.875 ;
     RECT  64.656 63.875 66.168 63.971 ;
     RECT  48.384 63.157 53.496 64.165 ;
     RECT  34.8 63.299 35.112 64.309 ;
     RECT  54.96 63.781 54.984 64.309 ;
     RECT  56.256 63.779 63.096 64.309 ;
     RECT  48.384 64.165 53.592 64.357 ;
     RECT  38.304 62.771 38.328 64.451 ;
     RECT  68.544 63.539 78.312 64.451 ;
     RECT  64.992 63.971 66.168 64.595 ;
     RECT  69.984 64.451 78.312 64.595 ;
     RECT  48.096 64.357 53.592 64.597 ;
     RECT  54.96 64.309 63.096 64.597 ;
     RECT  65.04 64.595 66.168 64.691 ;
     RECT  20.88 64.789 20.904 64.931 ;
     RECT  39.456 63.781 40.632 64.979 ;
     RECT  37.056 63.781 37.08 65.027 ;
     RECT  69.984 64.595 70.008 65.027 ;
     RECT  10.032 64.933 10.056 65.029 ;
     RECT  10.032 65.029 10.152 65.075 ;
     RECT  32.976 63.637 33.288 65.219 ;
     RECT  45.6 63.491 46.344 65.221 ;
     RECT  34.56 64.309 35.112 65.509 ;
     RECT  65.424 64.691 66.168 65.603 ;
     RECT  68.544 64.451 68.616 65.651 ;
     RECT  15.888 63.109 15.912 65.701 ;
     RECT  48.096 64.597 63.096 65.939 ;
     RECT  21.888 62.675 21.912 66.085 ;
     RECT  22.992 62.675 23.016 66.085 ;
     RECT  34.368 65.509 35.112 66.085 ;
     RECT  36.576 65.989 36.6 66.085 ;
     RECT  34.368 66.085 36.6 66.179 ;
     RECT  34.56 66.179 36.6 66.373 ;
     RECT  24 54.755 24.312 66.421 ;
     RECT  38.304 65.509 38.328 66.611 ;
     RECT  24 66.421 24.408 66.661 ;
     RECT  48.912 65.939 63.096 66.707 ;
     RECT  29.4 61.717 30.648 66.755 ;
     RECT  71.136 64.595 78.312 66.755 ;
     RECT  44.256 66.805 44.28 66.853 ;
     RECT  45.6 65.221 46.776 66.853 ;
     RECT  47.904 66.037 47.928 66.853 ;
     RECT  34.56 66.373 37.272 66.901 ;
     RECT  17.616 63.157 19.752 67.189 ;
     RECT  44.256 66.853 47.928 67.189 ;
     RECT  68.544 65.651 68.568 67.237 ;
     RECT  49.056 66.707 63.096 67.283 ;
     RECT  65.424 65.603 65.64 67.283 ;
     RECT  71.232 66.755 78.312 67.283 ;
     RECT  67.2 63.299 67.512 67.285 ;
     RECT  68.544 67.237 68.664 67.285 ;
     RECT  24 66.661 24.984 67.331 ;
     RECT  34.56 66.901 37.368 67.331 ;
     RECT  32.976 65.219 33 67.333 ;
     RECT  34.56 67.331 35.976 67.333 ;
     RECT  49.056 67.283 62.616 67.379 ;
     RECT  40.2 64.979 40.632 67.571 ;
     RECT  21.888 66.085 23.016 67.667 ;
     RECT  67.2 67.285 68.664 67.715 ;
     RECT  65.088 67.285 65.112 67.811 ;
     RECT  68.64 67.715 68.664 67.909 ;
     RECT  21.216 67.909 21.24 68.147 ;
     RECT  17.568 67.189 19.752 68.245 ;
     RECT  29.4 66.755 30.504 68.341 ;
     RECT  42.432 67.381 42.456 68.341 ;
     RECT  66.144 67.669 66.168 68.341 ;
     RECT  67.2 67.715 67.656 68.341 ;
     RECT  22.224 67.667 23.016 68.435 ;
     RECT  44.256 67.189 47.976 68.435 ;
     RECT  49.152 67.379 62.616 68.483 ;
     RECT  71.232 67.283 75.672 68.483 ;
     RECT  13.2 62.579 13.512 68.581 ;
     RECT  60.048 68.483 62.616 68.627 ;
     RECT  66.144 68.341 67.656 68.629 ;
     RECT  32.976 67.333 35.976 68.725 ;
     RECT  22.224 68.435 22.776 68.963 ;
     RECT  17.04 68.245 19.752 69.011 ;
     RECT  49.152 68.483 58.92 69.011 ;
     RECT  65.52 68.629 67.656 69.011 ;
     RECT  71.568 68.483 75.672 69.011 ;
     RECT  64.032 69.013 64.056 69.155 ;
     RECT  72.192 69.011 75.672 69.155 ;
     RECT  13.2 68.581 13.608 69.253 ;
     RECT  49.152 69.011 58.056 69.299 ;
     RECT  72.336 69.155 75.672 69.349 ;
     RECT  76.8 67.283 78.312 69.349 ;
     RECT  49.488 69.299 58.056 69.395 ;
     RECT  7.8 62.771 8.112 69.397 ;
     RECT  10.128 65.075 10.152 69.443 ;
     RECT  42.384 68.341 42.456 69.491 ;
     RECT  13.2 69.253 13.704 69.493 ;
     RECT  14.976 65.701 15.912 69.493 ;
     RECT  25.824 69.301 25.848 69.493 ;
     RECT  65.52 69.011 65.544 69.493 ;
     RECT  66.528 69.011 67.656 69.493 ;
     RECT  68.64 67.909 69.336 69.493 ;
     RECT  22.464 68.963 22.776 69.635 ;
     RECT  29.4 68.341 30.696 69.635 ;
     RECT  32.976 68.725 36.264 69.683 ;
     RECT  64.752 69.493 65.544 69.683 ;
     RECT  20.832 68.389 20.856 69.731 ;
     RECT  37.248 67.331 37.368 69.733 ;
     RECT  40.2 67.571 40.512 69.733 ;
     RECT  72.336 69.349 78.312 69.923 ;
     RECT  25.824 69.493 26.232 69.971 ;
     RECT  79.584 69.493 79.608 70.019 ;
     RECT  29.4 69.635 30.552 70.021 ;
     RECT  60.048 68.627 62.52 70.021 ;
     RECT  37.248 69.733 38.232 70.069 ;
     RECT  60.048 70.021 62.664 70.069 ;
     RECT  64.752 69.683 65.256 70.115 ;
     RECT  66.528 69.493 69.336 70.163 ;
     RECT  11.808 69.877 11.832 70.165 ;
     RECT  44.256 68.435 47.928 70.405 ;
     RECT  49.488 69.395 57.528 70.405 ;
     RECT  66.528 70.163 67.656 70.597 ;
     RECT  81.648 70.501 81.672 70.643 ;
     RECT  22.464 69.635 22.68 70.645 ;
     RECT  11.472 70.165 11.832 70.691 ;
     RECT  72.336 69.923 75.528 70.739 ;
     RECT  26.208 69.971 26.232 70.787 ;
     RECT  43.824 70.405 47.928 70.835 ;
     RECT  76.704 69.923 78.312 70.885 ;
     RECT  13.2 69.493 15.912 70.933 ;
     RECT  13.056 70.933 15.912 71.075 ;
     RECT  65.232 70.115 65.256 71.077 ;
     RECT  32.976 69.683 35.208 71.123 ;
     RECT  40.08 69.733 40.512 71.123 ;
     RECT  43.824 70.835 47.736 71.219 ;
     RECT  42.432 69.491 42.456 71.221 ;
     RECT  58.992 70.069 62.664 71.221 ;
     RECT  66.288 70.597 67.656 71.221 ;
     RECT  68.64 70.163 69.336 71.221 ;
     RECT  58.992 71.221 63.144 71.315 ;
     RECT  65.04 71.077 65.256 71.363 ;
     RECT  65.232 71.363 65.256 71.365 ;
     RECT  66.288 71.221 69.336 71.365 ;
     RECT  29.28 70.021 30.552 71.411 ;
     RECT  61.152 71.315 63.144 71.459 ;
     RECT  65.232 71.365 69.336 71.507 ;
     RECT  22.32 70.645 22.68 71.509 ;
     RECT  44.256 71.219 47.736 71.603 ;
     RECT  58.992 71.315 60.072 71.797 ;
     RECT  42.144 71.221 42.456 71.843 ;
     RECT  29.4 71.411 30.552 71.939 ;
     RECT  72.432 70.739 75.528 71.939 ;
     RECT  49.488 70.405 57.912 72.229 ;
     RECT  58.944 71.797 60.072 72.229 ;
     RECT  34.656 71.123 35.208 72.275 ;
     RECT  49.488 72.229 60.072 72.275 ;
     RECT  72.6 71.939 75.528 72.373 ;
     RECT  76.704 70.885 78.552 72.373 ;
     RECT  80.208 71.221 80.232 72.373 ;
     RECT  7.8 69.397 8.328 72.419 ;
     RECT  49.488 72.275 59.208 72.419 ;
     RECT  22.032 71.509 22.68 72.467 ;
     RECT  22.272 72.467 22.68 72.469 ;
     RECT  24 67.331 24.312 72.469 ;
     RECT  11.808 70.691 11.832 72.613 ;
     RECT  80.208 72.373 80.952 72.659 ;
     RECT  29.4 71.939 30.36 72.707 ;
     RECT  37.248 70.069 38.328 72.707 ;
     RECT  34.656 72.275 35.112 72.709 ;
     RECT  29.4 72.707 29.712 72.805 ;
     RECT  34.56 72.709 35.112 72.805 ;
     RECT  10.704 72.661 10.728 72.851 ;
     RECT  67.008 71.507 69.336 72.901 ;
     RECT  70.944 70.645 71.256 72.901 ;
     RECT  11.808 72.613 11.976 72.947 ;
     RECT  67.008 72.901 71.256 72.949 ;
     RECT  72.6 72.373 78.552 72.949 ;
     RECT  25.968 71.797 25.992 72.995 ;
     RECT  67.008 72.949 78.552 73.045 ;
     RECT  67.008 73.045 78.648 73.283 ;
     RECT  13.2 71.075 15.912 73.381 ;
     RECT  77.712 73.283 78.648 73.381 ;
     RECT  32.976 71.123 33 73.475 ;
     RECT  61.152 71.459 62.664 73.523 ;
     RECT  13.056 73.381 15.912 73.525 ;
     RECT  34.464 72.805 35.112 73.571 ;
     RECT  67.008 73.283 76.344 73.619 ;
     RECT  29.232 72.805 29.712 73.667 ;
     RECT  12.96 73.525 15.912 73.763 ;
     RECT  34.56 73.571 35.112 73.763 ;
     RECT  67.008 73.619 73.608 73.763 ;
     RECT  80.928 72.659 80.952 73.763 ;
     RECT  27.984 72.565 28.008 73.813 ;
     RECT  27.552 73.813 28.008 74.099 ;
     RECT  50.544 72.419 59.208 74.147 ;
     RECT  67.008 73.763 73.416 74.147 ;
     RECT  79.824 72.661 79.848 74.147 ;
     RECT  31.008 73.525 31.032 74.291 ;
     RECT  32.4 74.149 32.424 74.291 ;
     RECT  67.008 74.147 73.272 74.339 ;
     RECT  77.712 73.381 78.696 74.339 ;
     RECT  49.488 72.419 49.512 74.341 ;
     RECT  37.584 72.707 38.328 74.387 ;
     RECT  67.008 74.339 71.016 74.485 ;
     RECT  66.24 74.485 71.016 74.531 ;
     RECT  22.272 72.469 24.312 74.629 ;
     RECT  11.808 72.947 11.832 74.723 ;
     RECT  50.544 74.147 58.968 74.819 ;
     RECT  27.552 74.099 27.576 74.867 ;
     RECT  52.32 74.819 58.968 74.867 ;
     RECT  49.2 74.341 49.512 74.965 ;
     RECT  50.544 74.819 51.312 74.965 ;
     RECT  29.28 73.667 29.712 75.013 ;
     RECT  44.256 71.603 47.256 75.109 ;
     RECT  7.8 72.419 8.112 75.157 ;
     RECT  22.272 74.629 24.408 75.251 ;
     RECT  66.24 74.531 69.336 75.299 ;
     RECT  77.712 74.339 78.648 75.395 ;
     RECT  72.6 74.339 73.272 75.397 ;
     RECT  29.136 75.013 29.712 75.445 ;
     RECT  22.608 75.251 24.408 75.541 ;
     RECT  34.656 73.763 35.112 75.589 ;
     RECT  20.832 72.325 20.856 75.781 ;
     RECT  29.136 75.445 29.88 75.781 ;
     RECT  40.2 71.123 40.512 75.781 ;
     RECT  42.432 71.843 42.456 75.781 ;
     RECT  40.2 75.781 42.456 75.829 ;
     RECT  43.92 75.109 47.256 75.829 ;
     RECT  40.2 75.829 47.256 75.923 ;
     RECT  66.24 75.299 69.24 75.971 ;
     RECT  74.928 73.619 76.344 75.971 ;
     RECT  49.2 74.965 51.312 76.163 ;
     RECT  29.088 75.781 29.88 76.259 ;
     RECT  20.832 75.781 21.144 76.261 ;
     RECT  13.2 73.763 15.912 76.309 ;
     RECT  52.32 74.867 53.352 76.309 ;
     RECT  54.72 74.867 58.968 76.309 ;
     RECT  83.4 48.755 83.712 76.309 ;
     RECT  22.608 75.541 24.984 76.403 ;
     RECT  66.24 75.971 67.512 76.403 ;
     RECT  70.512 74.531 71.016 76.403 ;
     RECT  32.448 75.829 32.472 76.451 ;
     RECT  22.752 76.403 24.984 76.499 ;
     RECT  52.32 76.309 58.968 76.499 ;
     RECT  74.928 75.971 75.864 76.595 ;
     RECT  17.616 69.011 19.752 76.645 ;
     RECT  20.736 76.261 21.144 76.645 ;
     RECT  83.28 76.309 83.712 76.787 ;
     RECT  17.616 76.645 21.144 76.789 ;
     RECT  6.384 75.205 6.408 76.835 ;
     RECT  7.8 75.157 8.232 76.837 ;
     RECT  23.424 76.499 24.984 76.885 ;
     RECT  36.192 69.683 36.216 76.885 ;
     RECT  80.928 76.357 80.952 76.885 ;
     RECT  43.344 75.923 47.256 77.075 ;
     RECT  13.104 76.309 15.912 77.171 ;
     RECT  36.192 76.885 36.264 77.315 ;
     RECT  80.928 76.885 81.768 77.315 ;
     RECT  14.976 77.171 15.912 77.555 ;
     RECT  33.024 76.885 33.048 77.555 ;
     RECT  52.992 76.499 58.968 77.555 ;
     RECT  72.48 75.397 73.272 77.555 ;
     RECT  77.712 75.395 78.6 77.651 ;
     RECT  67.104 76.403 67.512 77.653 ;
     RECT  15.072 77.555 15.912 77.699 ;
     RECT  7.8 76.837 8.472 77.795 ;
     RECT  17.616 76.789 21.336 77.845 ;
     RECT  27.264 75.109 27.288 77.893 ;
     RECT  34.56 75.589 35.112 77.941 ;
     RECT  36.192 77.315 36.216 77.941 ;
     RECT  70.896 76.403 71.016 77.941 ;
     RECT  26.784 77.893 27.288 78.035 ;
     RECT  17.616 77.845 21.768 78.037 ;
     RECT  23.424 76.885 25.08 78.037 ;
     RECT  10.848 77.125 10.872 78.131 ;
     RECT  26.784 78.035 26.808 78.131 ;
     RECT  58.08 77.555 58.968 78.131 ;
     RECT  40.2 75.923 41.976 78.133 ;
     RECT  49.2 76.163 49.512 78.325 ;
     RECT  43.92 77.075 47.256 78.419 ;
     RECT  67.056 77.653 67.512 78.421 ;
     RECT  70.896 77.941 71.112 78.467 ;
     RECT  49.2 78.325 49.752 78.517 ;
     RECT  67.056 78.421 67.608 78.563 ;
     RECT  17.616 78.037 25.08 78.565 ;
     RECT  34.56 77.941 36.216 78.613 ;
     RECT  38.304 74.387 38.328 78.613 ;
     RECT  58.08 78.131 58.872 78.613 ;
     RECT  72.6 77.555 73.272 78.613 ;
     RECT  40.2 78.133 42.792 78.659 ;
     RECT  49.008 78.517 49.752 78.659 ;
     RECT  52.992 77.555 56.712 78.661 ;
     RECT  17.28 78.565 25.08 78.707 ;
     RECT  29.4 76.259 29.88 78.707 ;
     RECT  69.216 75.971 69.24 78.709 ;
     RECT  67.056 78.563 67.512 78.755 ;
     RECT  69.216 78.709 69.288 79.043 ;
     RECT  29.4 78.707 29.712 79.045 ;
     RECT  74.928 76.595 75.528 79.141 ;
     RECT  65.232 71.507 65.256 79.189 ;
     RECT  18.432 78.707 25.08 79.235 ;
     RECT  13.104 77.171 13.8 79.283 ;
     RECT  18.432 79.235 22.2 79.283 ;
     RECT  34.272 78.613 36.216 79.283 ;
     RECT  44.256 78.419 47.256 79.283 ;
     RECT  81.744 77.315 81.768 79.283 ;
     RECT  77.712 77.651 78.504 79.477 ;
     RECT  15.888 77.699 15.912 79.717 ;
     RECT  38.304 78.613 38.472 79.717 ;
     RECT  38.208 79.717 38.472 79.765 ;
     RECT  44.256 79.283 44.28 79.765 ;
     RECT  67.2 78.755 67.512 79.765 ;
     RECT  70.896 78.467 71.016 79.765 ;
     RECT  77.712 79.477 78.6 79.811 ;
     RECT  15.648 79.717 15.912 79.859 ;
     RECT  23.424 79.235 25.08 79.859 ;
     RECT  57.936 78.613 58.872 79.859 ;
     RECT  69.216 79.043 69.24 79.859 ;
     RECT  80.016 79.045 80.04 79.859 ;
     RECT  17.28 78.707 17.304 80.003 ;
     RECT  18.432 79.283 21.912 80.003 ;
     RECT  41.856 78.659 42.792 80.003 ;
     RECT  58.08 79.859 58.872 80.005 ;
     RECT  74.64 79.141 75.528 80.099 ;
     RECT  49.2 78.659 49.752 80.147 ;
     RECT  29.28 79.045 29.712 80.293 ;
     RECT  41.952 80.003 42.792 80.293 ;
     RECT  43.92 79.765 44.28 80.293 ;
     RECT  41.952 80.293 44.28 80.339 ;
     RECT  77.712 79.811 78.456 80.341 ;
     RECT  52.464 78.661 56.712 80.387 ;
     RECT  18.6 80.003 21.912 80.389 ;
     RECT  23.424 79.859 24.312 80.389 ;
     RECT  29.28 80.293 29.88 80.435 ;
     RECT  30.912 78.613 30.936 80.483 ;
     RECT  70.848 79.765 71.016 80.485 ;
     RECT  72.48 78.613 73.272 80.485 ;
     RECT  52.56 80.387 56.712 80.579 ;
     RECT  67.2 79.765 67.848 80.581 ;
     RECT  65.232 79.189 65.592 80.627 ;
     RECT  67.104 80.581 67.848 80.627 ;
     RECT  18.6 80.389 24.312 80.869 ;
     RECT  52.56 80.579 53.736 80.915 ;
     RECT  61.8 73.523 62.664 80.915 ;
     RECT  68.88 80.773 68.904 80.915 ;
     RECT  75.216 80.099 75.528 80.963 ;
     RECT  34.272 79.283 35.352 81.011 ;
     RECT  38.112 79.765 38.472 81.011 ;
     RECT  64.224 80.293 64.248 81.061 ;
     RECT  26.208 80.677 26.232 81.205 ;
     RECT  38.208 81.011 38.472 81.205 ;
     RECT  64.032 81.061 64.248 81.205 ;
     RECT  70.848 80.485 73.272 81.253 ;
     RECT  77.616 80.341 78.456 81.397 ;
     RECT  63.84 81.205 64.248 81.443 ;
     RECT  75.456 80.963 75.528 81.443 ;
     RECT  27.312 80.341 27.336 81.445 ;
     RECT  29.4 80.435 29.88 81.539 ;
     RECT  70.464 81.253 73.272 81.587 ;
     RECT  41.952 80.339 41.976 81.635 ;
     RECT  52.56 80.915 53.448 81.635 ;
     RECT  67.104 80.627 67.512 81.635 ;
     RECT  43.008 80.339 44.28 81.781 ;
     RECT  45.264 79.283 47.256 81.781 ;
     RECT  43.008 81.781 47.256 81.829 ;
     RECT  18.6 80.869 24.648 81.875 ;
     RECT  64.032 81.443 64.248 81.875 ;
     RECT  77.52 81.397 78.456 81.877 ;
     RECT  7.8 77.795 8.112 82.021 ;
     RECT  42.816 81.829 47.256 82.021 ;
     RECT  27.312 81.445 28.056 82.115 ;
     RECT  27.888 82.115 28.056 82.163 ;
     RECT  70.464 81.587 70.584 82.163 ;
     RECT  52.992 81.635 53.448 82.211 ;
     RECT  49.392 80.147 49.752 82.405 ;
     RECT  75.504 81.443 75.528 82.405 ;
     RECT  34.56 81.011 35.352 82.451 ;
     RECT  15.648 79.859 15.672 82.453 ;
     RECT  23.424 81.875 24.648 82.453 ;
     RECT  25.68 81.205 26.232 82.453 ;
     RECT  70.56 82.163 70.584 82.547 ;
     RECT  38.208 81.205 38.76 82.549 ;
     RECT  40.2 78.659 40.512 82.549 ;
     RECT  67.2 81.635 67.512 82.549 ;
     RECT  68.736 81.061 68.76 82.549 ;
     RECT  42.816 82.021 47.352 82.595 ;
     RECT  52.992 82.211 53.256 82.597 ;
     RECT  54.72 80.579 56.712 82.645 ;
     RECT  7.8 82.021 9.096 82.691 ;
     RECT  23.424 82.453 26.232 82.691 ;
     RECT  67.2 82.549 68.76 82.691 ;
     RECT  75.504 82.405 76.008 82.691 ;
     RECT  77.52 81.877 79.224 82.691 ;
     RECT  43.92 82.595 47.352 82.739 ;
     RECT  77.712 82.691 79.224 82.739 ;
     RECT  48.432 82.405 49.752 82.787 ;
     RECT  58.08 80.005 59.256 82.787 ;
     RECT  54.528 82.645 56.712 82.789 ;
     RECT  43.92 82.739 44.28 82.931 ;
     RECT  48.432 82.787 49.512 82.931 ;
     RECT  67.2 82.691 67.992 82.931 ;
     RECT  65.232 80.627 65.256 82.933 ;
     RECT  72.6 81.587 73.272 82.933 ;
     RECT  48.432 82.931 48.456 82.981 ;
     RECT  45.6 82.739 47.352 83.029 ;
     RECT  48.384 82.981 48.456 83.029 ;
     RECT  34.8 82.451 35.352 83.075 ;
     RECT  65.232 82.933 65.496 83.075 ;
     RECT  72.048 82.933 73.272 83.075 ;
     RECT  36.432 83.077 36.456 83.173 ;
     RECT  61.8 80.915 62.112 83.173 ;
     RECT  27.888 82.163 27.96 83.221 ;
     RECT  29.4 81.539 29.832 83.221 ;
     RECT  43.92 82.931 43.944 83.267 ;
     RECT  45.6 83.029 48.456 83.267 ;
     RECT  58.08 82.787 58.92 83.363 ;
     RECT  13.2 79.283 13.8 83.461 ;
     RECT  14.784 82.453 15.672 83.461 ;
     RECT  54.528 82.789 56.856 83.555 ;
     RECT  33.6 82.549 33.624 83.747 ;
     RECT  78 82.739 79.224 83.747 ;
     RECT  54.72 83.555 56.856 83.795 ;
     RECT  58.896 83.363 58.92 83.797 ;
     RECT  23.424 82.691 25.224 83.843 ;
     RECT  38.208 82.549 40.512 83.843 ;
     RECT  52.944 82.597 53.256 83.843 ;
     RECT  58.896 83.797 59.016 83.843 ;
     RECT  78 83.747 78.456 83.843 ;
     RECT  38.208 83.843 38.328 83.987 ;
     RECT  42.816 82.595 42.84 83.989 ;
     RECT  58.992 83.843 59.016 83.989 ;
     RECT  13.2 83.461 15.672 84.035 ;
     RECT  39.36 83.843 40.512 84.035 ;
     RECT  42.816 83.989 43.128 84.035 ;
     RECT  31.152 80.917 31.176 84.083 ;
     RECT  78 83.843 78.408 84.085 ;
     RECT  65.328 83.075 65.352 84.179 ;
     RECT  30.96 84.085 30.984 84.181 ;
     RECT  83.4 76.787 83.712 84.181 ;
     RECT  27.264 83.221 29.832 84.275 ;
     RECT  49.44 82.931 49.512 84.277 ;
     RECT  36.432 83.173 36.648 84.325 ;
     RECT  67.2 82.931 67.512 84.325 ;
     RECT  72.6 83.075 73.272 84.325 ;
     RECT  45.6 83.267 46.008 84.373 ;
     RECT  47.232 83.267 47.928 84.373 ;
     RECT  11.904 82.309 11.928 84.419 ;
     RECT  54.72 83.795 56.712 84.419 ;
     RECT  70.032 83.125 70.056 84.419 ;
     RECT  61.8 83.173 62.904 84.563 ;
     RECT  49.44 84.277 49.752 84.613 ;
     RECT  58.992 83.989 59.304 84.613 ;
     RECT  52.944 83.843 53.208 84.709 ;
     RECT  49.008 84.613 49.752 84.755 ;
     RECT  7.8 82.691 8.712 84.851 ;
     RECT  34.8 83.075 35.256 84.853 ;
     RECT  27.264 84.275 29.712 84.899 ;
     RECT  58.992 84.613 59.544 84.901 ;
     RECT  34.8 84.853 35.304 84.949 ;
     RECT  52.608 84.709 53.208 84.949 ;
     RECT  30.912 84.181 30.984 85.043 ;
     RECT  45.6 84.373 47.928 85.091 ;
     RECT  23.424 83.843 24.312 85.093 ;
     RECT  40.2 84.035 40.512 85.141 ;
     RECT  30.96 85.043 30.984 85.283 ;
     RECT  18.6 81.875 21.912 85.381 ;
     RECT  46.992 85.091 47.928 85.381 ;
     RECT  46.992 85.381 48.216 85.427 ;
     RECT  27.888 84.899 29.712 85.523 ;
     RECT  13.2 84.035 14.712 85.571 ;
     RECT  52.608 84.949 53.688 85.571 ;
     RECT  72.6 84.325 73.512 85.619 ;
     RECT  83.136 84.181 83.712 85.619 ;
     RECT  43.104 84.035 43.128 85.667 ;
     RECT  46.992 85.427 47.064 85.667 ;
     RECT  18.6 85.381 22.344 85.715 ;
     RECT  52.608 85.571 52.68 85.717 ;
     RECT  67.2 84.325 67.752 85.765 ;
     RECT  18.6 85.715 19.032 85.907 ;
     RECT  32.16 84.901 32.184 85.907 ;
     RECT  34.8 84.949 35.352 85.909 ;
     RECT  18.6 85.907 18.912 85.957 ;
     RECT  20.16 85.715 22.344 86.005 ;
     RECT  61.8 84.563 62.112 86.005 ;
     RECT  75.504 82.691 75.816 86.005 ;
     RECT  77.904 84.085 78.408 86.005 ;
     RECT  58.992 84.901 60.36 86.051 ;
     RECT  20.16 86.005 22.392 86.099 ;
     RECT  25.68 84.277 25.944 86.149 ;
     RECT  25.68 86.149 26.328 86.195 ;
     RECT  36.336 84.325 36.648 86.195 ;
     RECT  39.792 85.141 40.512 86.245 ;
     RECT  47.04 85.667 47.064 86.291 ;
     RECT  75.504 86.005 76.632 86.291 ;
     RECT  48.192 85.427 48.216 86.293 ;
     RECT  49.248 84.755 49.752 86.293 ;
     RECT  48.192 86.293 49.752 86.341 ;
     RECT  50.736 76.163 51.312 86.341 ;
     RECT  27.888 85.523 27.912 86.435 ;
     RECT  72.6 85.619 73.272 86.485 ;
     RECT  58.992 86.051 59.928 86.581 ;
     RECT  71.76 86.485 73.272 86.581 ;
     RECT  77.616 86.005 78.408 86.629 ;
     RECT  17.424 85.429 17.448 86.675 ;
     RECT  54.72 84.419 54.984 86.675 ;
     RECT  75.504 86.291 75.528 86.675 ;
     RECT  25.92 86.195 26.328 86.723 ;
     RECT  65.568 85.477 65.592 86.723 ;
     RECT  61.8 86.005 62.232 86.725 ;
     RECT  45.6 85.091 46.008 86.771 ;
     RECT  71.328 86.581 73.272 87.011 ;
     RECT  77.616 86.629 78.456 87.011 ;
     RECT  52.464 85.717 52.68 87.157 ;
     RECT  53.664 85.571 53.688 87.157 ;
     RECT  83.4 85.619 83.712 87.157 ;
     RECT  67.2 85.765 68.376 87.203 ;
     RECT  25.92 86.723 26.136 87.251 ;
     RECT  33.84 85.909 35.352 87.251 ;
     RECT  44.16 86.485 44.184 87.251 ;
     RECT  54.864 86.675 54.984 87.251 ;
     RECT  61.8 86.725 62.664 87.251 ;
     RECT  71.328 87.011 71.544 87.299 ;
     RECT  20.16 86.099 20.472 87.683 ;
     RECT  45.6 86.771 45.912 87.685 ;
     RECT  61.8 87.251 62.112 87.685 ;
     RECT  52.464 87.157 53.688 87.827 ;
     RECT  77.616 87.011 78.408 87.827 ;
     RECT  26.112 87.251 26.136 87.875 ;
     RECT  48.192 86.341 51.312 87.875 ;
     RECT  58.896 86.581 59.928 87.875 ;
     RECT  48.192 87.875 48.6 87.923 ;
     RECT  58.944 87.875 59.928 87.923 ;
     RECT  82.656 87.157 83.712 88.067 ;
     RECT  21.744 86.099 22.392 88.213 ;
     RECT  23.424 85.093 24.408 88.213 ;
     RECT  45.504 87.685 45.912 88.261 ;
     RECT  79.536 86.725 79.56 88.307 ;
     RECT  20.16 87.683 20.376 88.403 ;
     RECT  72.6 87.011 73.272 88.403 ;
     RECT  74.64 87.541 74.664 88.453 ;
     RECT  78 87.827 78.408 88.499 ;
     RECT  67.2 87.203 67.512 88.645 ;
     RECT  64.224 81.875 64.248 88.693 ;
     RECT  74.64 88.453 74.952 88.739 ;
     RECT  20.16 88.403 20.184 88.741 ;
     RECT  45.504 88.261 46.056 88.741 ;
     RECT  19.968 88.741 20.184 88.787 ;
     RECT  33.84 87.251 35.304 88.789 ;
     RECT  36.336 86.195 36.36 88.789 ;
     RECT  60.96 87.685 62.112 88.789 ;
     RECT  33.84 88.789 36.36 88.883 ;
     RECT  29.4 85.523 29.712 88.885 ;
     RECT  52.464 87.827 53.016 88.885 ;
     RECT  28.512 88.885 29.712 88.933 ;
     RECT  80.928 88.261 80.952 88.933 ;
     RECT  48.576 87.923 48.6 88.979 ;
     RECT  58.944 87.923 59.016 88.979 ;
     RECT  45.504 88.741 46.296 89.315 ;
     RECT  71.52 87.299 71.544 89.317 ;
     RECT  72.6 88.403 72.912 89.317 ;
     RECT  71.52 89.317 72.912 89.363 ;
     RECT  76.608 86.291 76.632 89.413 ;
     RECT  49.824 87.875 51.312 89.461 ;
     RECT  52.464 88.885 53.784 89.461 ;
     RECT  56.4 84.419 56.712 89.461 ;
     RECT  64.224 88.693 64.392 89.461 ;
     RECT  66.72 88.645 67.512 89.461 ;
     RECT  38.208 83.987 38.232 89.507 ;
     RECT  49.824 89.461 53.784 89.507 ;
     RECT  60.192 88.789 62.112 89.507 ;
     RECT  44.112 87.445 44.136 89.555 ;
     RECT  45.504 89.315 46.152 89.555 ;
     RECT  50.736 89.507 53.784 89.555 ;
     RECT  60.192 89.507 60.216 89.555 ;
     RECT  75.744 89.413 76.632 89.555 ;
     RECT  21.744 88.213 24.408 89.605 ;
     RECT  70.08 88.885 70.104 89.653 ;
     RECT  54.864 87.251 54.888 89.699 ;
     RECT  69.648 89.653 70.104 89.699 ;
     RECT  80.832 88.933 80.952 89.701 ;
     RECT  63.792 89.461 64.392 89.795 ;
     RECT  28.512 88.933 30.216 89.843 ;
     RECT  19.968 88.787 19.992 89.845 ;
     RECT  21.072 89.605 24.408 89.845 ;
     RECT  33.84 88.883 35.88 89.989 ;
     RECT  39.456 86.245 40.512 90.037 ;
     RECT  45.6 89.555 46.152 90.083 ;
     RECT  75.744 89.555 76.392 90.083 ;
     RECT  50.736 89.555 52.488 90.131 ;
     RECT  66.096 89.461 67.512 90.227 ;
     RECT  29.4 89.843 30.216 90.275 ;
     RECT  45.6 90.083 46.056 90.275 ;
     RECT  53.568 89.555 53.784 90.323 ;
     RECT  26.736 89.125 26.76 90.325 ;
     RECT  26.304 90.325 26.76 90.371 ;
     RECT  56.304 89.461 56.712 90.611 ;
     RECT  63.792 89.795 63.816 90.611 ;
     RECT  39.408 90.037 40.512 90.659 ;
     RECT  71.808 89.363 72.912 90.659 ;
     RECT  76.368 90.083 76.392 90.659 ;
     RECT  19.968 89.845 24.408 90.707 ;
     RECT  19.968 90.707 20.472 90.755 ;
     RECT  33.84 89.989 36.552 90.755 ;
     RECT  33.84 90.755 35.112 90.851 ;
     RECT  21.648 90.707 24.408 90.901 ;
     RECT  39.84 90.659 40.512 90.901 ;
     RECT  50.88 90.131 52.488 90.947 ;
     RECT  39.84 90.901 41.352 91.043 ;
     RECT  69.648 89.699 69.672 91.043 ;
     RECT  29.4 90.275 29.928 91.091 ;
     RECT  72.48 90.659 72.912 91.187 ;
     RECT  53.568 90.323 53.592 91.235 ;
     RECT  66.72 90.227 67.512 91.235 ;
     RECT  80.832 89.701 81 91.235 ;
     RECT  21.648 90.901 24.552 91.331 ;
     RECT  80.976 91.235 81 91.331 ;
     RECT  39.936 91.043 41.352 91.379 ;
     RECT  58.944 88.979 58.968 91.379 ;
     RECT  22.56 91.331 24.552 91.427 ;
     RECT  52.464 90.947 52.488 91.475 ;
     RECT  26.304 90.371 26.328 91.571 ;
     RECT  47.856 90.565 47.88 91.571 ;
     RECT  44.112 90.517 44.136 91.619 ;
     RECT  50.88 90.947 51.312 91.667 ;
     RECT  74.64 88.739 74.664 91.763 ;
     RECT  31.488 87.925 31.512 91.811 ;
     RECT  38.736 91.285 38.76 91.811 ;
     RECT  59.952 91.141 59.976 91.859 ;
     RECT  13.2 85.571 13.944 92.195 ;
     RECT  64.992 91.765 65.016 92.339 ;
     RECT  68.928 91.141 68.952 92.339 ;
     RECT  22.56 91.427 24.312 92.387 ;
     RECT  40.2 91.379 41.352 92.387 ;
     RECT  20.064 90.755 20.472 92.435 ;
     RECT  2.4 60.563 2.712 92.889 ;
     RECT  7.8 84.851 8.112 92.889 ;
     RECT  13.2 92.195 13.512 92.889 ;
     RECT  18.432 85.957 18.912 92.889 ;
     RECT  24 92.387 24.312 92.889 ;
     RECT  29.4 91.091 29.712 92.889 ;
     RECT  34.8 90.851 35.112 92.889 ;
     RECT  40.2 92.387 40.512 92.889 ;
     RECT  45.6 90.275 45.912 92.889 ;
     RECT  51 91.667 51.312 92.889 ;
     RECT  56.4 90.611 56.712 92.889 ;
     RECT  61.8 89.507 62.112 92.889 ;
     RECT  67.2 91.235 67.512 92.889 ;
     RECT  72.6 91.187 72.912 92.889 ;
     RECT  78 88.499 78.312 92.889 ;
     RECT  83.4 88.067 83.712 92.889 ;
     RECT  2.4 92.889 2.52 92.903 ;
     RECT  7.8 92.889 7.92 92.903 ;
     RECT  13.2 92.889 13.32 92.903 ;
     RECT  18.432 92.889 18.72 92.903 ;
     RECT  24 92.889 24.12 92.903 ;
     RECT  29.4 92.889 29.52 92.903 ;
     RECT  34.8 92.889 34.92 92.903 ;
     RECT  40.2 92.889 40.32 92.903 ;
     RECT  45.6 92.889 45.72 92.903 ;
     RECT  51 92.889 51.12 92.903 ;
     RECT  56.4 92.889 56.52 92.903 ;
     RECT  61.8 92.889 61.92 92.903 ;
     RECT  67.2 92.889 67.32 92.903 ;
     RECT  72.6 92.889 72.72 92.903 ;
     RECT  78 92.889 78.12 92.903 ;
     RECT  83.4 92.889 83.52 92.903 ;
     RECT  18.432 92.903 18.456 94.885 ;
     RECT  18.432 94.885 18.696 94.931 ;
     RECT  17.544 2.821 18.6 4.643 ;
     RECT  67.512 3.205 68.496 5.219 ;
     RECT  13.512 3.397 14.496 4.355 ;
     RECT  22.824 3.397 24 4.211 ;
     RECT  40.512 3.875 41.304 5.125 ;
     RECT  27.912 3.925 29.4 4.691 ;
     RECT  68.52 4.261 69.696 5.219 ;
     RECT  13.512 4.355 14.784 6.563 ;
     RECT  45.912 4.501 47.424 6.275 ;
     RECT  56.712 4.885 57.936 6.323 ;
     RECT  73.512 5.077 74.976 6.035 ;
     RECT  41.112 5.125 41.304 5.317 ;
     RECT  60.408 5.125 61.8 8.291 ;
     RECT  29.712 5.171 29.832 6.517 ;
     RECT  67.512 5.219 69.696 5.269 ;
     RECT  67.608 5.269 69.696 6.229 ;
     RECT  65.88 5.605 67.2 6.947 ;
     RECT  65.616 5.651 65.856 6.805 ;
     RECT  73.512 6.035 74.088 6.661 ;
     RECT  67.608 6.229 68.688 8.533 ;
     RECT  68.712 6.229 69.696 7.381 ;
     RECT  45.912 6.275 47.448 6.277 ;
     RECT  46.008 6.277 47.448 6.325 ;
     RECT  56.712 6.323 57 7.381 ;
     RECT  46.008 6.325 47.472 10.165 ;
     RECT  31.92 6.515 31.944 7.285 ;
     RECT  13.512 6.563 15.312 7.957 ;
     RECT  52.296 6.613 53.52 8.147 ;
     RECT  67.104 6.947 67.2 7.381 ;
     RECT  80.4 7.235 80.928 8.003 ;
     RECT  31.92 7.285 32.4 7.957 ;
     RECT  9.096 7.333 10.56 7.907 ;
     RECT  35.112 7.427 35.352 8.485 ;
     RECT  69 7.475 70.224 9.155 ;
     RECT  6.744 7.717 7.8 10.165 ;
     RECT  30.216 7.957 31.392 9.155 ;
     RECT  75.768 7.957 77.136 8.819 ;
     RECT  80.4 8.003 80.952 8.341 ;
     RECT  51.312 8.147 51.432 9.589 ;
     RECT  38.136 8.245 39.168 9.155 ;
     RECT  39.192 8.245 40.2 9.155 ;
     RECT  60.912 8.291 61.8 8.293 ;
     RECT  80.136 8.341 80.952 9.061 ;
     RECT  62.112 8.485 63.264 9.347 ;
     RECT  14.232 8.963 14.808 10.453 ;
     RECT  78.312 9.061 79.344 16.547 ;
     RECT  80.136 9.061 81.456 9.731 ;
     RECT  30.024 9.155 31.392 12.517 ;
     RECT  62.112 9.347 63.288 10.165 ;
     RECT  32.328 10.067 33.048 11.413 ;
     RECT  46.008 10.165 47.328 10.307 ;
     RECT  62.112 10.165 63.552 11.507 ;
     RECT  45.912 10.307 47.328 11.459 ;
     RECT  6.648 10.883 7.8 12.469 ;
     RECT  35.448 10.885 36.48 11.699 ;
     RECT  8.112 11.267 9.216 11.411 ;
     RECT  51.312 11.459 51.432 12.517 ;
     RECT  62.112 11.507 63.288 11.941 ;
     RECT  58.608 11.555 58.944 12.181 ;
     RECT  35.448 11.699 35.928 11.941 ;
     RECT  62.112 11.941 63.264 12.563 ;
     RECT  82.392 11.941 83.4 13.091 ;
     RECT  57.48 12.181 58.944 13.139 ;
     RECT  31.896 12.227 32.928 12.755 ;
     RECT  13.944 12.467 14.928 13.091 ;
     RECT  6.792 12.469 7.8 14.197 ;
     RECT  6.624 12.515 6.768 13.093 ;
     RECT  30.024 12.517 31.248 13.139 ;
     RECT  40.728 12.517 42.144 13.715 ;
     RECT  51.312 12.517 52.704 13.283 ;
     RECT  75.288 12.517 76.368 12.755 ;
     RECT  31.896 12.755 32.952 13.477 ;
     RECT  75.744 12.755 75.768 13.477 ;
     RECT  71.304 13.045 72.48 13.091 ;
     RECT  13.944 13.091 14.952 13.621 ;
     RECT  71.304 13.091 72.6 14.677 ;
     RECT  82.368 13.091 83.4 14.197 ;
     RECT  5.592 13.093 6.768 13.283 ;
     RECT  30.024 13.139 31.632 14.195 ;
     RECT  56.712 13.139 58.944 13.621 ;
     RECT  32.808 13.477 32.952 13.813 ;
     RECT  44.136 13.525 45.6 14.675 ;
     RECT  13.944 13.621 15.408 14.819 ;
     RECT  56.712 13.621 57.984 17.029 ;
     RECT  29.712 14.195 31.632 14.485 ;
     RECT  82.296 14.197 83.4 15.395 ;
     RECT  32.568 14.387 32.952 14.627 ;
     RECT  29.712 14.485 30.72 14.675 ;
     RECT  38.328 14.533 39.36 14.675 ;
     RECT  31.896 14.627 32.952 14.819 ;
     RECT  29.712 14.675 30.816 15.971 ;
     RECT  40.032 14.675 40.2 15.733 ;
     RECT  71.304 14.677 72.432 14.773 ;
     RECT  31.752 14.819 32.952 15.397 ;
     RECT  35.112 14.819 35.448 15.877 ;
     RECT  15.96 15.061 17.328 16.787 ;
     RECT  17.352 15.061 18.6 17.701 ;
     RECT  12.072 15.349 13.104 17.219 ;
     RECT  31.752 15.397 32.928 15.443 ;
     RECT  24.888 15.443 25.032 16.501 ;
     RECT  31.656 15.443 32.928 16.019 ;
     RECT  10.584 15.637 12.048 15.925 ;
     RECT  51.312 15.827 51.432 16.453 ;
     RECT  35.112 15.877 36.192 16.261 ;
     RECT  10.584 15.925 11.712 16.261 ;
     RECT  55.368 15.925 56.4 17.509 ;
     RECT  69 16.021 70.32 16.355 ;
     RECT  22.68 16.307 23.712 16.643 ;
     RECT  69 16.355 69.528 16.453 ;
     RECT  51.312 16.453 52.656 29.509 ;
     RECT  5.736 16.501 6.768 18.757 ;
     RECT  24.888 16.501 26.208 16.885 ;
     RECT  78.312 16.547 79.776 17.171 ;
     RECT  25.08 16.885 26.208 17.123 ;
     RECT  35.112 16.931 36.192 17.699 ;
     RECT  48.984 16.979 50.016 17.795 ;
     RECT  24.888 17.123 26.208 18.421 ;
     RECT  12.072 17.219 13.2 17.701 ;
     RECT  70.728 17.269 72.096 17.555 ;
     RECT  47.976 17.317 48.96 23.987 ;
     RECT  39.048 17.461 40.032 19.379 ;
     RECT  63.768 17.605 64.992 17.653 ;
     RECT  81.912 17.605 83.4 18.659 ;
     RECT  63.912 17.653 64.992 19.141 ;
     RECT  12.12 17.701 13.2 18.947 ;
     RECT  31.32 18.133 32.64 18.565 ;
     RECT  34.704 18.179 34.8 19.237 ;
     RECT  53.304 18.181 54.576 18.947 ;
     RECT  62.112 18.181 63.552 21.157 ;
     RECT  25.224 18.421 26.208 19.475 ;
     RECT  4.896 18.563 5.04 20.053 ;
     RECT  26.808 18.757 27.792 19.379 ;
     RECT  72.912 18.757 73.92 21.683 ;
     RECT  5.064 18.947 6.288 20.149 ;
     RECT  12.024 18.947 13.2 19.043 ;
     RECT  17.352 18.947 18.6 21.155 ;
     RECT  11.736 19.043 13.2 20.051 ;
     RECT  63.96 19.141 64.992 20.531 ;
     RECT  33.72 19.237 34.8 20.723 ;
     RECT  26.232 19.379 27.792 19.475 ;
     RECT  31.32 19.427 32.688 20.003 ;
     RECT  26.784 19.475 27.792 20.773 ;
     RECT  70.776 19.477 72.096 19.619 ;
     RECT  48.984 19.669 49.968 20.869 ;
     RECT  49.992 19.669 51 22.501 ;
     RECT  6.36 20.003 7.632 20.099 ;
     RECT  24.888 20.003 25.224 21.061 ;
     RECT  32.64 20.003 32.688 21.061 ;
     RECT  2.856 20.053 3.84 20.867 ;
     RECT  3.864 20.053 5.04 20.485 ;
     RECT  6.36 20.099 7.8 23.893 ;
     RECT  18.912 20.339 19.032 21.637 ;
     RECT  3.864 20.485 4.992 20.867 ;
     RECT  63.96 20.531 64.344 20.725 ;
     RECT  32.952 20.723 33.24 22.165 ;
     RECT  26.808 20.773 27.792 21.155 ;
     RECT  4.512 20.867 4.992 21.061 ;
     RECT  48.984 21.059 49.968 23.987 ;
     RECT  4.512 21.061 4.944 22.165 ;
     RECT  25.608 21.061 26.784 21.155 ;
     RECT  75.792 21.107 75.816 21.637 ;
     RECT  25.608 21.155 27.792 21.731 ;
     RECT  62.112 21.299 63.552 30.709 ;
     RECT  18.912 21.637 20.064 22.981 ;
     RECT  73.944 21.637 75.312 21.683 ;
     RECT  75.336 21.637 75.816 22.549 ;
     RECT  24.312 21.731 25.344 22.741 ;
     RECT  25.464 21.731 27.792 22.165 ;
     RECT  53.304 21.829 54.72 22.549 ;
     RECT  14.136 21.925 15.6 22.259 ;
     RECT  2.712 21.971 2.856 23.029 ;
     RECT  35.544 21.973 37.008 23.795 ;
     RECT  78.312 22.117 79.776 24.469 ;
     RECT  25.464 22.165 26.736 22.979 ;
     RECT  56.712 22.165 57.744 24.563 ;
     RECT  53.304 22.549 54.336 22.691 ;
     RECT  64.344 22.595 64.968 23.317 ;
     RECT  49.992 22.643 51 27.971 ;
     RECT  57.768 22.741 59.184 24.563 ;
     RECT  67.944 22.787 68.976 23.123 ;
     RECT  26.76 22.835 27.792 22.979 ;
     RECT  2.712 23.029 4.176 30.709 ;
     RECT  67.608 23.123 68.976 24.085 ;
     RECT  22.728 23.317 24 24.469 ;
     RECT  64.344 23.317 66.336 23.797 ;
     RECT  5.304 23.555 6.288 23.987 ;
     RECT  35.544 23.795 36.072 24.229 ;
     RECT  65.016 23.797 66.336 24.085 ;
     RECT  59.832 23.845 61.2 25.139 ;
     RECT  6.552 23.893 7.8 28.453 ;
     RECT  5.064 23.987 6.288 25.621 ;
     RECT  24.312 24.083 25.44 25.235 ;
     RECT  65.304 24.085 66.336 24.659 ;
     RECT  67.896 24.085 68.976 26.243 ;
     RECT  33.432 24.133 34.8 24.275 ;
     RECT  30.024 24.227 30.216 25.621 ;
     RECT  17.112 24.469 18.6 25.139 ;
     RECT  79.272 24.563 79.512 25.573 ;
     RECT  65.304 24.659 66.912 24.755 ;
     RECT  65.304 24.755 67.104 24.803 ;
     RECT  65.304 24.803 67.2 25.715 ;
     RECT  17.016 25.139 18.6 25.717 ;
     RECT  61.008 25.139 61.2 25.717 ;
     RECT  24.312 25.235 26.352 25.237 ;
     RECT  25.272 25.237 26.352 26.725 ;
     RECT  27.96 25.283 29.184 25.763 ;
     RECT  44.784 25.475 44.928 26.629 ;
     RECT  26.376 25.621 27.648 26.821 ;
     RECT  78.312 25.667 79.488 25.955 ;
     RECT  29.712 25.715 30.768 27.301 ;
     RECT  64.92 25.715 67.2 26.101 ;
     RECT  17.016 25.717 18.48 26.819 ;
     RECT  27.672 25.763 29.184 27.301 ;
     RECT  76.488 25.909 78 27.301 ;
     RECT  78.312 25.955 79.512 26.629 ;
     RECT  64.92 26.101 66.48 26.771 ;
     RECT  8.712 26.243 10.128 26.819 ;
     RECT  67.512 26.243 68.976 26.771 ;
     RECT  41.064 26.629 42.384 28.211 ;
     RECT  78.312 26.629 79.632 28.453 ;
     RECT  25.368 26.725 26.352 29.317 ;
     RECT  48.456 26.725 49.968 27.971 ;
     RECT  64.92 26.771 67.2 27.205 ;
     RECT  39 26.773 40.2 28.643 ;
     RECT  17.016 26.819 18.6 27.205 ;
     RECT  35.112 26.821 36.576 27.301 ;
     RECT  44.616 27.059 45.6 28.933 ;
     RECT  17.256 27.205 18.6 28.115 ;
     RECT  65.688 27.205 67.2 29.365 ;
     RECT  13.944 27.301 15.264 30.035 ;
     RECT  29.712 27.301 30.72 29.893 ;
     RECT  35.544 27.301 36.576 27.733 ;
     RECT  21.672 27.877 22.896 29.461 ;
     RECT  15.288 27.925 16.752 28.837 ;
     RECT  4.344 27.971 5.376 30.181 ;
     RECT  28.416 27.971 29.04 29.029 ;
     RECT  30.792 28.213 31.872 29.557 ;
     RECT  78.408 28.453 79.632 28.499 ;
     RECT  38.976 28.643 40.2 28.933 ;
     RECT  15.288 28.837 16.416 29.939 ;
     RECT  38.976 28.933 39.024 30.085 ;
     RECT  39.048 28.933 40.2 30.277 ;
     RECT  27.672 29.029 29.04 29.605 ;
     RECT  35.256 29.123 36.24 30.181 ;
     RECT  78.312 29.123 78.408 30.421 ;
     RECT  16.632 29.219 16.776 29.893 ;
     RECT  65.688 29.365 66.72 29.749 ;
     RECT  51.576 29.509 52.656 30.613 ;
     RECT  54.984 29.605 56.4 30.707 ;
     RECT  26.184 29.699 27.648 30.949 ;
     RECT  27.912 29.747 29.088 29.891 ;
     RECT  27.912 29.891 29.4 31.955 ;
     RECT  16.632 29.893 17.616 31.525 ;
     RECT  53.64 29.893 54.96 30.707 ;
     RECT  15.288 29.939 16.608 30.035 ;
     RECT  30.408 30.227 31.584 31.525 ;
     RECT  21.624 30.275 22.656 31.955 ;
     RECT  44.616 30.275 45.6 31.861 ;
     RECT  40.512 30.325 41.712 33.011 ;
     RECT  41.736 30.373 42.816 30.661 ;
     RECT  42.84 30.373 44.16 30.565 ;
     RECT  37.368 30.469 38.448 36.277 ;
     RECT  42.888 30.565 44.16 30.707 ;
     RECT  41.736 30.661 42.768 30.851 ;
     RECT  42.84 30.707 44.16 32.005 ;
     RECT  2.712 30.709 4.128 30.947 ;
     RECT  41.736 30.851 42.816 33.011 ;
     RECT  67.512 30.899 67.608 31.909 ;
     RECT  2.712 30.947 4.176 32.197 ;
     RECT  26.184 30.949 27.36 32.195 ;
     RECT  79.56 31.285 80.928 32.771 ;
     RECT  35.304 31.379 36.48 32.243 ;
     RECT  75.96 31.379 76.992 32.435 ;
     RECT  78.312 31.379 79.536 33.683 ;
     RECT  30.408 31.525 31.536 31.909 ;
     RECT  62.112 31.715 63.552 33.683 ;
     RECT  30.408 31.909 31.488 33.155 ;
     RECT  67.512 31.909 68.496 33.875 ;
     RECT  68.52 31.909 69.936 32.195 ;
     RECT  21.624 31.955 22.752 33.013 ;
     RECT  42.84 32.005 43.824 32.531 ;
     RECT  26.184 32.195 27.456 33.589 ;
     RECT  35.112 32.243 36.48 33.349 ;
     RECT  75.672 32.435 76.992 33.683 ;
     RECT  8.664 32.437 10.128 32.773 ;
     RECT  42.84 32.531 44.352 33.107 ;
     RECT  44.616 32.771 45.6 37.429 ;
     RECT  8.664 32.773 10.032 33.349 ;
     RECT  42.192 33.011 42.816 33.107 ;
     RECT  74.472 33.011 75.648 33.827 ;
     RECT  18.912 33.059 19.92 33.107 ;
     RECT  42.192 33.107 42.216 33.781 ;
     RECT  43.92 33.107 44.352 33.829 ;
     RECT  21.288 33.155 22.368 34.883 ;
     RECT  32.808 33.157 34.176 33.203 ;
     RECT  32.712 33.203 34.176 36.227 ;
     RECT  8.808 33.349 10.032 34.883 ;
     RECT  35.112 33.349 36.384 34.643 ;
     RECT  24.312 33.635 25.392 33.683 ;
     RECT  64.632 33.635 65.664 37.187 ;
     RECT  62.112 33.683 63.696 33.731 ;
     RECT  78.312 33.683 78.696 33.925 ;
     RECT  62.112 33.731 62.232 33.925 ;
     RECT  43.92 33.829 44.256 34.357 ;
     RECT  67.512 33.875 68.232 34.981 ;
     RECT  66.216 34.355 67.2 40.499 ;
     RECT  52.392 34.403 52.68 34.405 ;
     RECT  52.392 34.405 53.904 34.933 ;
     RECT  35.112 34.643 36.48 35.363 ;
     RECT  8.376 34.883 10.032 35.845 ;
     RECT  73.368 34.885 74.448 35.699 ;
     RECT  16.8 34.931 17.376 35.317 ;
     RECT  52.392 34.933 53.856 37.427 ;
     RECT  40.512 34.981 41.76 37.763 ;
     RECT  16.248 35.317 17.376 36.227 ;
     RECT  27.144 35.363 28.176 41.219 ;
     RECT  35.112 35.363 37.056 36.565 ;
     RECT  49.128 35.413 50.304 35.653 ;
     RECT  78.696 35.413 79.776 35.605 ;
     RECT  49.176 35.653 50.304 35.939 ;
     RECT  72.912 35.699 74.448 36.661 ;
     RECT  8.376 35.845 9.744 36.611 ;
     RECT  19.416 35.941 20.544 36.229 ;
     RECT  44.4 35.987 44.448 37.333 ;
     RECT  19.464 36.229 20.544 36.997 ;
     RECT  35.112 36.565 36.144 44.965 ;
     RECT  54.648 36.565 55.68 40.933 ;
     RECT  8.376 36.611 10.032 38.101 ;
     RECT  72.912 36.661 74.16 37.667 ;
     RECT  74.472 36.805 75.888 36.949 ;
     RECT  64.992 37.187 65.664 37.285 ;
     RECT  28.2 37.571 29.4 38.725 ;
     RECT  13.896 37.573 14.976 41.605 ;
     RECT  60.312 37.573 61.8 38.101 ;
     RECT  67.992 37.573 69.024 38.867 ;
     RECT  20.136 37.667 20.568 38.677 ;
     RECT  72.912 37.667 74.976 38.245 ;
     RECT  60.456 38.101 61.8 38.773 ;
     RECT  46.776 38.149 47.952 38.581 ;
     RECT  73.56 38.245 74.976 38.965 ;
     RECT  24.888 38.435 26.16 38.915 ;
     RECT  46.776 38.581 47.856 39.395 ;
     RECT  28.392 38.725 29.4 39.395 ;
     RECT  60.456 38.773 61.632 39.251 ;
     RECT  22.92 38.819 23.904 39.875 ;
     RECT  42.288 38.819 42.336 39.301 ;
     RECT  37.08 38.867 38.448 39.829 ;
     RECT  24.312 38.915 24.408 39.877 ;
     RECT  60.312 39.251 61.632 40.067 ;
     RECT  40.824 39.301 42.336 41.075 ;
     RECT  51.576 39.301 52.704 40.981 ;
     RECT  4.248 39.395 5.376 40.019 ;
     RECT  28.2 39.395 29.4 40.597 ;
     RECT  72.912 39.731 74.064 55.525 ;
     RECT  22.92 39.875 24 41.029 ;
     RECT  10.152 39.923 10.2 41.317 ;
     RECT  20.376 39.923 20.472 41.365 ;
     RECT  4.104 40.019 5.376 40.645 ;
     RECT  60.312 40.067 61.8 40.979 ;
     RECT  53.016 40.213 54.48 42.227 ;
     RECT  75 40.451 76.032 42.421 ;
     RECT  18.912 40.499 19.968 41.651 ;
     RECT  65.688 40.499 67.2 42.323 ;
     RECT  28.296 40.597 29.4 45.635 ;
     RECT  4.104 40.645 5.328 40.883 ;
     RECT  67.512 40.835 67.992 42.085 ;
     RECT  4.104 40.883 5.424 41.939 ;
     RECT  59.976 40.979 61.8 42.181 ;
     RECT  23.016 41.029 24 41.219 ;
     RECT  22.92 41.219 24 42.661 ;
     RECT  27 41.219 28.176 42.565 ;
     RECT  18.912 41.651 20.304 43.813 ;
     RECT  29.712 41.701 30.864 42.757 ;
     RECT  15 41.749 16.512 42.851 ;
     RECT  24.456 41.939 24.504 42.901 ;
     RECT  39.144 42.035 40.2 46.211 ;
     RECT  60.6 42.181 61.8 42.803 ;
     RECT  10.152 42.227 10.248 42.947 ;
     RECT  13.512 42.227 14.784 42.803 ;
     RECT  66.144 42.323 67.2 43.285 ;
     RECT  5.712 42.755 5.904 43.861 ;
     RECT  55.32 42.755 56.4 43.861 ;
     RECT  29.712 42.757 30.768 42.899 ;
     RECT  13.512 42.803 14.976 43.187 ;
     RECT  15 42.851 15.384 43.141 ;
     RECT  29.712 42.899 30.864 49.043 ;
     RECT  10.056 42.947 10.248 43.285 ;
     RECT  13.512 43.187 15.36 44.437 ;
     RECT  10.056 43.285 11.424 44.389 ;
     RECT  41.112 43.285 42.336 44.771 ;
     RECT  56.712 43.285 57.888 44.053 ;
     RECT  66.168 43.285 67.2 43.907 ;
     RECT  12.216 43.525 13.2 45.059 ;
     RECT  78.312 43.765 79.584 49.091 ;
     RECT  18.912 43.813 20.016 44.579 ;
     RECT  4.104 43.861 5.328 45.013 ;
     RECT  55.416 43.861 56.4 44.629 ;
     RECT  66.144 43.907 67.2 44.245 ;
     RECT  56.808 44.053 57.888 45.635 ;
     RECT  6.312 44.195 7.68 44.483 ;
     RECT  65.928 44.245 67.2 47.125 ;
     RECT  32.232 44.339 32.376 44.435 ;
     RECT  37.8 44.339 39.12 45.971 ;
     RECT  52.392 44.341 53.712 44.437 ;
     RECT  10.2 44.389 11.424 45.875 ;
     RECT  9.144 44.435 10.176 47.173 ;
     RECT  32.088 44.435 32.376 44.965 ;
     RECT  13.512 44.437 14.784 45.875 ;
     RECT  52.488 44.437 53.712 44.629 ;
     RECT  7.44 44.483 7.68 45.589 ;
     RECT  18.912 44.579 20.304 45.541 ;
     RECT  52.584 44.629 53.712 45.013 ;
     RECT  42.144 44.771 42.336 45.013 ;
     RECT  32.088 44.965 33.408 46.261 ;
     RECT  33.432 44.965 34.8 48.467 ;
     RECT  47.592 44.965 48.72 45.589 ;
     RECT  52.584 45.013 53.616 45.683 ;
     RECT  59.976 45.013 61.488 45.491 ;
     RECT  11.976 45.059 13.2 47.363 ;
     RECT  18.912 45.541 20.256 47.173 ;
     RECT  14.808 45.635 15.384 45.829 ;
     RECT  52.584 45.683 53.712 47.653 ;
     RECT  14.808 45.829 16.224 45.875 ;
     RECT  13.512 45.875 14.424 46.693 ;
     RECT  16.248 46.069 17.232 46.499 ;
     RECT  17.256 46.069 18.6 48.371 ;
     RECT  39.264 46.211 40.2 46.501 ;
     RECT  32.184 46.261 33.408 46.645 ;
     RECT  16.368 46.499 17.232 47.269 ;
     RECT  32.184 46.645 33.168 47.221 ;
     RECT  67.704 46.645 69.12 47.845 ;
     RECT  25.176 46.933 26.64 47.125 ;
     RECT  25.272 47.125 26.64 47.267 ;
     RECT  65.928 47.125 67.104 47.363 ;
     RECT  9.192 47.173 10.176 47.411 ;
     RECT  49.32 47.269 50.832 47.605 ;
     RECT  32.328 47.363 33.408 48.467 ;
     RECT  9.144 47.411 10.176 48.805 ;
     RECT  4.632 47.555 5.616 48.371 ;
     RECT  49.32 47.605 50.736 48.421 ;
     RECT  52.728 47.653 53.712 48.949 ;
     RECT  46.344 47.845 47.856 48.371 ;
     RECT  67.896 47.845 69.12 49.189 ;
     RECT  13.512 47.891 14.784 48.371 ;
     RECT  65.448 47.891 65.544 48.997 ;
     RECT  31.128 47.939 32.16 49.525 ;
     RECT  67.104 47.939 67.2 48.997 ;
     RECT  76.344 48.277 77.664 52.981 ;
     RECT  4.104 48.371 5.616 49.429 ;
     RECT  49.32 48.421 50.544 48.707 ;
     RECT  32.328 48.467 32.424 49.957 ;
     RECT  34.176 48.467 34.8 49.381 ;
     RECT  49.08 48.707 50.544 49.043 ;
     RECT  59.592 48.949 60.768 51.347 ;
     RECT  60.792 48.949 61.8 50.629 ;
     RECT  66.168 48.997 67.2 49.619 ;
     RECT  29.712 49.043 31.056 49.619 ;
     RECT  78.312 49.091 80.304 49.189 ;
     RECT  67.896 49.189 68.928 49.525 ;
     RECT  78.504 49.189 80.304 49.381 ;
     RECT  53.496 49.235 53.736 50.629 ;
     RECT  22.488 49.237 23.712 50.051 ;
     RECT  20.664 49.285 21.888 50.101 ;
     RECT  79.224 49.381 80.304 50.195 ;
     RECT  4.104 49.429 5.136 51.299 ;
     RECT  43.368 49.525 44.592 54.179 ;
     RECT  29.712 49.619 31.104 50.771 ;
     RECT  24.312 49.669 25.344 53.029 ;
     RECT  2.712 50.243 3.744 52.691 ;
     RECT  11.88 50.629 13.2 51.395 ;
     RECT  53.496 50.629 55.2 50.677 ;
     RECT  55.224 50.629 56.256 51.203 ;
     RECT  44.616 50.675 45.6 56.725 ;
     RECT  50.544 50.723 50.64 51.445 ;
     RECT  56.904 50.821 58.32 50.869 ;
     RECT  8.232 50.963 9.216 51.347 ;
     RECT  80.328 50.965 81.36 52.019 ;
     RECT  10.2 51.061 11.28 52.403 ;
     RECT  54.984 51.203 56.256 52.165 ;
     RECT  47.016 51.253 48.528 51.923 ;
     RECT  65.688 51.301 67.2 52.163 ;
     RECT  11.304 51.395 13.2 51.781 ;
     RECT  68.712 51.443 68.952 52.549 ;
     RECT  49.608 51.445 50.64 51.829 ;
     RECT  41.592 51.541 42.816 51.877 ;
     RECT  11.304 51.781 12.336 52.357 ;
     RECT  41.64 51.877 42.816 52.165 ;
     RECT  5.664 51.923 6.24 53.029 ;
     RECT  65.448 52.163 67.2 52.405 ;
     RECT  54.984 52.165 56.16 53.365 ;
     RECT  10.2 52.403 11.424 53.077 ;
     RECT  65.448 52.405 66.576 53.603 ;
     RECT  68.712 52.549 69.984 53.557 ;
     RECT  70.008 52.549 70.992 54.661 ;
     RECT  41.592 52.739 42.816 52.883 ;
     RECT  5.112 53.029 6.24 53.125 ;
     RECT  52.968 53.075 54.48 54.083 ;
     RECT  10.44 53.077 11.424 53.507 ;
     RECT  5.112 53.125 6.144 54.037 ;
     RECT  59.592 53.269 60.96 54.949 ;
     RECT  38.904 53.317 39.984 55.093 ;
     RECT  10.44 53.507 10.584 54.949 ;
     RECT  65.448 53.603 67.2 54.661 ;
     RECT  76.344 53.651 77.664 55.237 ;
     RECT  22.872 53.797 24 55.907 ;
     RECT  25.368 53.941 26.592 55.907 ;
     RECT  52.968 54.083 53.112 54.325 ;
     RECT  4.488 54.131 5.952 55.237 ;
     RECT  53.064 54.325 53.112 55.237 ;
     RECT  65.688 54.661 67.2 56.869 ;
     RECT  24.312 54.755 25.344 59.315 ;
     RECT  41.112 54.755 42.816 55.187 ;
     RECT  59.832 54.949 60.96 55.189 ;
     RECT  42.096 55.187 42.816 55.957 ;
     RECT  4.728 55.237 5.952 55.525 ;
     RECT  2.712 55.285 3.84 55.571 ;
     RECT  68.712 55.331 69.984 56.389 ;
     RECT  9.648 55.379 10.56 55.813 ;
     RECT  55.296 55.523 55.344 56.965 ;
     RECT  4.728 55.525 5.712 55.955 ;
     RECT  2.712 55.571 4.464 55.957 ;
     RECT  10.92 55.573 11.904 57.443 ;
     RECT  11.928 55.573 13.2 56.677 ;
     RECT  71.4 55.669 72.6 56.389 ;
     RECT  62.424 55.717 63.408 56.053 ;
     RECT  8.568 55.813 10.56 56.389 ;
     RECT  63.432 55.813 64.656 56.483 ;
     RECT  25.368 55.907 25.512 56.389 ;
     RECT  76.392 55.907 77.664 56.531 ;
     RECT  4.488 55.955 5.712 56.483 ;
     RECT  48.912 55.955 48.96 57.301 ;
     RECT  3.48 55.957 4.464 56.483 ;
     RECT  9.096 56.389 10.56 57.493 ;
     RECT  3.48 56.483 5.712 56.965 ;
     RECT  63.24 56.483 64.656 59.171 ;
     RECT  72.912 56.483 74.064 59.797 ;
     RECT  6.264 56.531 7.584 57.395 ;
     RECT  12.216 56.677 13.2 60.421 ;
     RECT  37.032 56.677 38.304 56.867 ;
     RECT  64.68 56.771 65.664 57.059 ;
     RECT  37.824 56.867 38.304 57.637 ;
     RECT  44.616 56.867 45.6 62.149 ;
     RECT  65.688 56.869 67.104 56.917 ;
     RECT  65.688 56.917 66.72 57.059 ;
     RECT  79.128 56.917 80.208 56.965 ;
     RECT  3.48 56.965 4.848 57.541 ;
     RECT  79.224 56.965 80.208 58.645 ;
     RECT  64.68 57.059 65.112 58.501 ;
     RECT  68.952 57.107 69.984 59.173 ;
     RECT  10.824 57.443 11.904 57.587 ;
     RECT  70.344 57.491 71.52 59.077 ;
     RECT  9.096 57.493 10.512 58.931 ;
     RECT  3.528 57.541 4.848 57.875 ;
     RECT  81.912 57.541 83.4 59.891 ;
     RECT  10.584 57.587 11.904 58.931 ;
     RECT  57.672 57.635 58.656 61.619 ;
     RECT  3.528 57.875 5.04 58.163 ;
     RECT  6.024 58.019 6.264 59.221 ;
     RECT  76.296 58.597 77.664 58.645 ;
     RECT  76.296 58.645 77.328 58.693 ;
     RECT  39.192 58.979 40.2 59.507 ;
     RECT  70.344 59.077 71.376 61.237 ;
     RECT  63.24 59.171 64.8 59.891 ;
     RECT  6.696 59.221 7.8 60.275 ;
     RECT  80.76 59.267 81.888 59.891 ;
     RECT  59.496 59.315 60.72 61.525 ;
     RECT  68.04 59.315 69.264 59.651 ;
     RECT  21.912 59.557 22.992 62.437 ;
     RECT  23.016 59.557 24 68.435 ;
     RECT  65.256 59.701 66.72 59.797 ;
     RECT  31.896 59.797 32.976 60.277 ;
     RECT  72.912 59.797 73.968 59.845 ;
     RECT  64.656 59.891 64.8 60.277 ;
     RECT  40.512 59.893 41.712 60.275 ;
     RECT  79.224 60.131 80.304 62.195 ;
     RECT  53.496 60.133 54.912 61.189 ;
     RECT  43.272 60.181 44.496 60.901 ;
     RECT  42.072 60.227 43.248 60.707 ;
     RECT  6.312 60.275 7.8 61.043 ;
     RECT  70.08 60.467 70.176 61.477 ;
     RECT  65.256 60.563 66.528 61.573 ;
     RECT  33.384 60.901 34.704 60.947 ;
     RECT  33.384 60.947 34.8 61.043 ;
     RECT  35.112 60.997 36.288 61.907 ;
     RECT  6.024 61.043 7.8 61.427 ;
     RECT  34.704 61.043 34.8 61.909 ;
     RECT  53.496 61.189 54.672 61.477 ;
     RECT  5.688 61.427 7.8 61.573 ;
     RECT  31.536 61.427 31.68 61.717 ;
     RECT  70.08 61.477 70.128 61.957 ;
     RECT  5.688 61.573 7.2 62.771 ;
     RECT  65.4 61.573 66.528 61.621 ;
     RECT  54.936 61.619 56.256 63.491 ;
     RECT  57.672 61.619 58.896 61.859 ;
     RECT  65.496 61.621 66.528 62.723 ;
     RECT  31.704 61.667 32.976 63.875 ;
     RECT  30.648 61.717 31.68 63.875 ;
     RECT  57.576 61.859 58.896 63.157 ;
     RECT  53.496 62.147 54.672 62.771 ;
     RECT  79.224 62.195 79.704 62.437 ;
     RECT  38.328 62.389 39.312 62.437 ;
     RECT  68.568 62.581 69.984 62.821 ;
     RECT  21.912 62.675 22.992 66.085 ;
     RECT  38.328 62.675 40.2 63.781 ;
     RECT  78.696 62.675 79.68 63.251 ;
     RECT  65.496 62.723 67.2 63.157 ;
     RECT  37.584 62.771 38.304 63.781 ;
     RECT  53.496 62.771 54.912 63.491 ;
     RECT  66.168 63.157 67.2 65.603 ;
     RECT  34.704 63.299 34.8 63.637 ;
     RECT  67.512 63.299 68.544 67.285 ;
     RECT  44.616 63.491 45.6 63.587 ;
     RECT  53.496 63.491 56.256 63.781 ;
     RECT  33.288 63.637 34.8 64.309 ;
     RECT  63.096 63.779 64.512 63.875 ;
     RECT  37.08 63.781 38.304 64.451 ;
     RECT  38.328 63.781 39.456 64.451 ;
     RECT  53.496 63.781 54.96 64.165 ;
     RECT  54.984 63.781 56.256 64.309 ;
     RECT  53.592 64.165 54.96 64.597 ;
     RECT  33.288 64.309 34.56 65.219 ;
     RECT  37.08 64.451 39.456 64.979 ;
     RECT  68.616 64.451 69.984 65.027 ;
     RECT  70.008 64.595 71.136 65.027 ;
     RECT  19.752 64.789 20.88 64.931 ;
     RECT  20.904 64.789 21.888 64.931 ;
     RECT  37.08 64.979 38.328 65.027 ;
     RECT  37.056 65.027 38.328 65.509 ;
     RECT  33 65.219 34.56 65.509 ;
     RECT  46.776 65.221 48.096 65.939 ;
     RECT  33 65.509 34.368 66.179 ;
     RECT  37.056 65.509 38.304 65.989 ;
     RECT  13.512 65.701 14.976 68.581 ;
     RECT  46.776 65.939 48.912 66.037 ;
     RECT  35.112 65.989 36.576 66.085 ;
     RECT  36.6 65.989 38.304 66.373 ;
     RECT  46.776 66.037 47.904 66.853 ;
     RECT  47.928 66.037 48.912 66.707 ;
     RECT  33 66.179 34.56 67.333 ;
     RECT  37.272 66.373 38.304 66.611 ;
     RECT  37.272 66.611 37.368 66.901 ;
     RECT  47.928 66.707 49.056 67.189 ;
     RECT  44.28 66.805 45.6 66.853 ;
     RECT  47.976 67.189 49.056 67.379 ;
     RECT  65.424 67.283 65.64 67.285 ;
     RECT  75.672 67.283 76.8 69.349 ;
     RECT  65.112 67.285 65.64 67.669 ;
     RECT  35.976 67.331 37.248 68.725 ;
     RECT  47.976 67.379 49.152 68.435 ;
     RECT  21.888 67.667 22.224 67.909 ;
     RECT  65.112 67.669 66.144 67.811 ;
     RECT  66.168 67.669 67.2 68.341 ;
     RECT  67.656 67.715 68.64 69.493 ;
     RECT  65.088 67.811 66.144 68.629 ;
     RECT  19.752 67.909 21.216 68.147 ;
     RECT  21.24 67.909 22.224 68.147 ;
     RECT  19.752 68.147 22.224 68.389 ;
     RECT  15.912 68.245 17.04 69.011 ;
     RECT  19.752 68.389 20.832 69.731 ;
     RECT  20.856 68.389 22.224 68.963 ;
     RECT  22.776 68.435 24 69.635 ;
     RECT  47.928 68.435 49.152 69.299 ;
     RECT  58.92 68.483 60.048 69.011 ;
     RECT  13.608 68.581 14.976 69.253 ;
     RECT  62.52 68.627 62.616 69.013 ;
     RECT  65.088 68.629 65.52 69.013 ;
     RECT  36.264 68.725 37.248 69.683 ;
     RECT  58.056 69.011 60.048 69.395 ;
     RECT  65.544 69.011 66.528 69.683 ;
     RECT  62.52 69.013 64.032 69.155 ;
     RECT  64.056 69.013 65.52 69.155 ;
     RECT  62.52 69.155 62.664 70.021 ;
     RECT  64.752 69.155 65.52 69.493 ;
     RECT  72.192 69.155 72.336 70.645 ;
     RECT  13.704 69.253 14.976 69.493 ;
     RECT  24.312 69.301 25.824 69.971 ;
     RECT  57.528 69.395 60.048 70.069 ;
     RECT  78.312 69.493 79.584 70.019 ;
     RECT  22.68 69.635 24 72.469 ;
     RECT  35.208 69.683 36.192 72.275 ;
     RECT  36.216 69.683 37.248 72.707 ;
     RECT  65.256 69.683 66.528 70.597 ;
     RECT  11.832 69.877 13.2 70.933 ;
     RECT  75.528 69.923 76.704 72.373 ;
     RECT  78.312 70.019 78.552 70.885 ;
     RECT  57.528 70.069 58.992 70.405 ;
     RECT  65.04 70.115 65.232 71.077 ;
     RECT  67.656 70.163 68.64 71.221 ;
     RECT  42.456 70.405 43.824 71.219 ;
     RECT  57.912 70.405 58.992 71.797 ;
     RECT  65.256 70.597 66.288 71.365 ;
     RECT  71.256 70.645 72.336 70.739 ;
     RECT  71.256 70.739 72.432 71.939 ;
     RECT  11.832 70.933 13.056 71.075 ;
     RECT  11.832 71.075 13.2 72.613 ;
     RECT  60.072 71.315 61.152 72.275 ;
     RECT  29.28 71.411 29.4 72.565 ;
     RECT  57.912 71.797 58.944 72.229 ;
     RECT  71.256 71.939 72.6 72.949 ;
     RECT  35.112 72.275 36.192 77.941 ;
     RECT  19.752 72.325 20.832 76.261 ;
     RECT  20.856 72.325 22.032 72.467 ;
     RECT  49.512 72.419 50.544 74.965 ;
     RECT  20.856 72.467 22.272 75.251 ;
     RECT  28.008 72.565 29.4 72.805 ;
     RECT  11.976 72.613 13.2 72.947 ;
     RECT  80.208 72.659 80.928 72.661 ;
     RECT  10.728 72.661 11.808 72.851 ;
     RECT  78.552 72.661 79.824 73.045 ;
     RECT  79.848 72.661 80.928 73.763 ;
     RECT  29.712 72.707 30.36 73.525 ;
     RECT  36.216 72.707 37.584 74.387 ;
     RECT  28.008 72.805 29.232 73.667 ;
     RECT  33 72.805 34.464 73.475 ;
     RECT  11.832 72.947 13.2 73.381 ;
     RECT  78.648 73.045 79.824 73.381 ;
     RECT  76.344 73.283 77.712 75.971 ;
     RECT  11.832 73.381 13.056 73.525 ;
     RECT  78.696 73.381 79.824 74.147 ;
     RECT  11.832 73.525 12.96 73.763 ;
     RECT  29.712 73.525 31.008 74.291 ;
     RECT  73.608 73.619 74.928 73.763 ;
     RECT  28.008 73.667 29.28 74.099 ;
     RECT  11.832 73.763 13.2 74.723 ;
     RECT  73.416 73.763 74.928 74.147 ;
     RECT  29.136 74.099 29.28 75.013 ;
     RECT  31.032 74.149 32.4 74.291 ;
     RECT  29.712 74.291 29.88 75.445 ;
     RECT  71.016 74.339 72.6 75.397 ;
     RECT  65.256 74.485 66.24 76.403 ;
     RECT  69.336 74.531 70.512 75.299 ;
     RECT  51.312 74.819 52.32 76.499 ;
     RECT  53.352 74.867 54.72 76.309 ;
     RECT  42.456 75.109 43.92 75.829 ;
     RECT  6.408 75.205 7.8 76.835 ;
     RECT  20.856 75.251 22.608 75.781 ;
     RECT  69.24 75.299 70.512 76.403 ;
     RECT  71.016 75.397 72.48 77.555 ;
     RECT  21.144 75.781 22.608 76.403 ;
     RECT  41.976 75.923 43.344 77.075 ;
     RECT  49.512 76.163 50.736 78.325 ;
     RECT  19.752 76.261 20.736 76.645 ;
     RECT  21.144 76.403 22.752 76.499 ;
     RECT  67.056 76.403 67.104 77.653 ;
     RECT  21.144 76.499 21.768 76.789 ;
     RECT  21.336 76.789 21.768 77.845 ;
     RECT  33.048 76.885 34.56 77.555 ;
     RECT  41.976 77.075 43.92 78.133 ;
     RECT  13.8 77.171 14.976 77.555 ;
     RECT  13.8 77.555 15.072 77.699 ;
     RECT  34.272 77.555 34.56 78.613 ;
     RECT  56.712 77.555 58.08 78.613 ;
     RECT  71.016 77.555 72.6 77.941 ;
     RECT  78.504 77.651 78.6 79.045 ;
     RECT  71.112 77.941 72.6 78.467 ;
     RECT  42.792 78.133 43.92 78.419 ;
     RECT  49.752 78.325 50.736 82.787 ;
     RECT  42.792 78.419 44.256 79.765 ;
     RECT  71.016 78.467 72.6 78.613 ;
     RECT  67.512 78.563 67.608 79.765 ;
     RECT  15.912 78.565 17.28 79.859 ;
     RECT  29.88 78.613 30.912 78.707 ;
     RECT  56.712 78.613 57.936 79.859 ;
     RECT  71.016 78.613 72.48 80.485 ;
     RECT  40.512 78.659 41.856 80.003 ;
     RECT  51.312 78.661 52.464 80.387 ;
     RECT  17.304 78.707 18.432 80.003 ;
     RECT  29.712 78.707 30.912 80.293 ;
     RECT  78.504 79.045 80.016 79.477 ;
     RECT  73.272 79.141 74.64 80.099 ;
     RECT  22.2 79.235 23.424 79.283 ;
     RECT  21.912 79.283 23.424 80.389 ;
     RECT  44.28 79.283 45.264 81.781 ;
     RECT  78.6 79.477 80.016 79.811 ;
     RECT  42.792 79.765 43.92 80.293 ;
     RECT  67.848 79.765 69.216 79.859 ;
     RECT  24.312 79.859 25.08 80.677 ;
     RECT  56.712 79.859 58.08 82.789 ;
     RECT  67.848 79.859 68.904 80.627 ;
     RECT  40.512 80.003 41.952 81.635 ;
     RECT  29.88 80.293 30.912 80.483 ;
     RECT  64.248 80.293 65.232 83.075 ;
     RECT  41.976 80.339 43.008 81.635 ;
     RECT  51.312 80.387 52.56 81.635 ;
     RECT  29.28 80.435 29.4 81.445 ;
     RECT  29.88 80.483 30.936 80.917 ;
     RECT  53.736 80.579 54.72 80.915 ;
     RECT  65.592 80.581 67.104 80.627 ;
     RECT  67.512 80.627 68.904 80.773 ;
     RECT  24.312 80.677 26.208 80.869 ;
     RECT  26.232 80.677 27.312 82.115 ;
     RECT  67.512 80.773 68.88 80.915 ;
     RECT  24.648 80.869 26.208 81.205 ;
     RECT  53.448 80.915 54.72 82.211 ;
     RECT  67.512 80.915 68.76 81.061 ;
     RECT  29.88 80.917 31.152 81.539 ;
     RECT  67.512 81.061 68.736 82.549 ;
     RECT  24.648 81.205 25.68 82.453 ;
     RECT  38.76 81.205 40.2 82.549 ;
     RECT  28.056 81.445 29.4 82.163 ;
     RECT  29.832 81.539 31.152 84.083 ;
     RECT  70.584 81.587 72.6 82.547 ;
     RECT  42.816 81.635 43.008 81.829 ;
     RECT  52.944 81.635 52.992 82.597 ;
     RECT  21.912 81.875 23.424 85.381 ;
     RECT  64.032 81.875 64.224 83.173 ;
     RECT  26.232 82.115 27.888 82.691 ;
     RECT  27.96 82.163 29.4 83.221 ;
     RECT  53.256 82.211 54.72 82.645 ;
     RECT  11.928 82.309 13.2 84.419 ;
     RECT  47.352 82.405 48.432 82.981 ;
     RECT  76.008 82.405 77.52 82.691 ;
     RECT  34.56 82.451 34.8 82.549 ;
     RECT  13.8 82.453 14.784 83.461 ;
     RECT  72.048 82.547 72.6 82.933 ;
     RECT  33.624 82.549 34.8 83.747 ;
     RECT  42.84 82.595 43.92 83.267 ;
     RECT  53.256 82.645 54.528 83.555 ;
     RECT  27.264 82.691 27.888 83.221 ;
     RECT  44.28 82.739 45.6 82.931 ;
     RECT  77.904 82.739 78 84.085 ;
     RECT  49.512 82.787 50.736 84.277 ;
     RECT  58.92 82.787 59.256 83.797 ;
     RECT  56.856 82.789 58.08 83.363 ;
     RECT  48.456 82.931 49.44 83.267 ;
     RECT  67.512 82.931 67.752 84.325 ;
     RECT  47.352 82.981 48.384 83.029 ;
     RECT  35.256 83.075 35.352 83.077 ;
     RECT  64.248 83.075 65.328 84.179 ;
     RECT  35.256 83.077 36.432 84.325 ;
     RECT  62.904 83.173 64.224 84.563 ;
     RECT  42.84 83.267 43.128 83.989 ;
     RECT  46.008 83.267 47.232 84.373 ;
     RECT  47.928 83.267 49.44 84.613 ;
     RECT  53.256 83.555 54.72 83.843 ;
     RECT  59.016 83.797 59.256 83.989 ;
     RECT  24.312 83.843 25.224 84.277 ;
     RECT  38.328 83.843 39.36 83.987 ;
     RECT  53.208 83.843 54.72 84.949 ;
     RECT  38.232 83.987 39.36 84.035 ;
     RECT  39.792 84.035 40.2 85.141 ;
     RECT  29.832 84.083 31.176 84.085 ;
     RECT  29.832 84.085 30.96 84.181 ;
     RECT  30.984 84.085 31.176 84.901 ;
     RECT  64.248 84.179 65.352 85.477 ;
     RECT  29.832 84.181 30.912 84.275 ;
     RECT  29.712 84.275 30.912 85.043 ;
     RECT  24.312 84.277 25.68 85.093 ;
     RECT  25.944 84.277 27.264 84.899 ;
     RECT  49.752 84.277 50.736 86.341 ;
     RECT  35.256 84.325 36.336 84.853 ;
     RECT  54.984 84.419 56.4 87.251 ;
     RECT  62.112 84.563 62.232 86.005 ;
     RECT  47.928 84.613 49.008 84.755 ;
     RECT  51.312 84.709 52.608 85.717 ;
     RECT  47.928 84.755 49.248 85.381 ;
     RECT  35.304 84.853 36.336 84.949 ;
     RECT  25.944 84.899 26.328 86.149 ;
     RECT  30.984 84.901 32.16 85.283 ;
     RECT  60.36 84.901 61.8 86.051 ;
     RECT  35.352 84.949 36.336 87.251 ;
     RECT  53.688 84.949 54.72 86.675 ;
     RECT  29.712 85.043 30.96 85.283 ;
     RECT  46.008 85.091 46.992 85.667 ;
     RECT  24.408 85.093 25.68 86.195 ;
     RECT  22.344 85.381 23.424 86.005 ;
     RECT  48.216 85.381 49.248 86.293 ;
     RECT  47.064 85.427 48.192 86.291 ;
     RECT  17.448 85.429 18.6 85.957 ;
     RECT  64.248 85.477 65.568 86.723 ;
     RECT  27.912 85.523 29.4 86.435 ;
     RECT  52.68 85.571 53.664 87.157 ;
     RECT  46.008 85.667 47.04 86.291 ;
     RECT  19.032 85.715 20.16 85.907 ;
     RECT  51.312 85.717 52.464 89.461 ;
     RECT  18.912 85.907 20.16 88.741 ;
     RECT  17.448 85.957 18.432 86.675 ;
     RECT  22.392 86.005 23.424 88.213 ;
     RECT  76.632 86.005 77.616 87.827 ;
     RECT  20.472 86.099 21.744 87.683 ;
     RECT  24.408 86.195 25.92 87.251 ;
     RECT  38.232 86.245 39.456 89.507 ;
     RECT  75.528 86.291 76.608 86.675 ;
     RECT  44.184 86.485 45.6 87.251 ;
     RECT  53.688 86.675 54.864 87.827 ;
     RECT  78.456 86.725 79.536 87.011 ;
     RECT  45.912 86.771 46.008 88.261 ;
     RECT  71.544 87.011 72.6 89.317 ;
     RECT  78.408 87.011 79.536 88.307 ;
     RECT  35.304 87.251 36.336 88.789 ;
     RECT  44.16 87.251 45.6 87.445 ;
     RECT  54.888 87.251 56.4 89.461 ;
     RECT  44.136 87.445 45.6 87.685 ;
     RECT  73.272 87.541 74.64 88.403 ;
     RECT  20.376 87.683 21.744 88.403 ;
     RECT  44.136 87.685 45.504 89.555 ;
     RECT  59.928 87.685 60.96 87.923 ;
     RECT  53.016 87.827 54.864 88.885 ;
     RECT  76.632 87.827 78 89.555 ;
     RECT  48.6 87.875 49.824 88.979 ;
     RECT  59.016 87.923 60.96 88.789 ;
     RECT  79.56 88.261 80.928 88.307 ;
     RECT  80.832 88.307 80.928 88.933 ;
     RECT  20.184 88.403 21.744 88.787 ;
     RECT  74.664 88.739 74.952 89.413 ;
     RECT  18.912 88.741 19.968 90.755 ;
     RECT  19.992 88.787 21.744 89.605 ;
     RECT  59.016 88.789 60.192 88.979 ;
     RECT  35.88 88.883 36.36 89.989 ;
     RECT  53.784 88.885 54.864 89.699 ;
     RECT  70.104 88.885 71.52 89.363 ;
     RECT  30.216 88.933 31.488 90.275 ;
     RECT  58.968 88.979 60.192 89.555 ;
     RECT  74.664 89.413 75.744 90.083 ;
     RECT  54.888 89.461 56.304 89.699 ;
     RECT  39.408 89.507 39.456 90.037 ;
     RECT  44.112 89.555 45.6 90.517 ;
     RECT  52.488 89.555 53.568 91.235 ;
     RECT  19.992 89.605 21.072 89.845 ;
     RECT  44.136 90.517 45.6 91.619 ;
     RECT  39.408 90.659 39.84 91.043 ;
     RECT  20.472 90.707 21.648 91.331 ;
     RECT  18.912 90.755 20.064 92.435 ;
     RECT  51.312 90.947 52.464 91.475 ;
     RECT  39.408 91.043 39.936 91.285 ;
     RECT  58.968 91.141 59.952 91.379 ;
     RECT  67.512 91.141 68.928 92.339 ;
     RECT  38.76 91.285 39.936 91.379 ;
     RECT  38.76 91.379 40.2 91.811 ;
  END
END ot_v41_bf_lane4_cl
END LIBRARY
